VERSION 5.8 ;
BUSBITCHARS "[]" ;
DIVIDERCHAR "/" ;
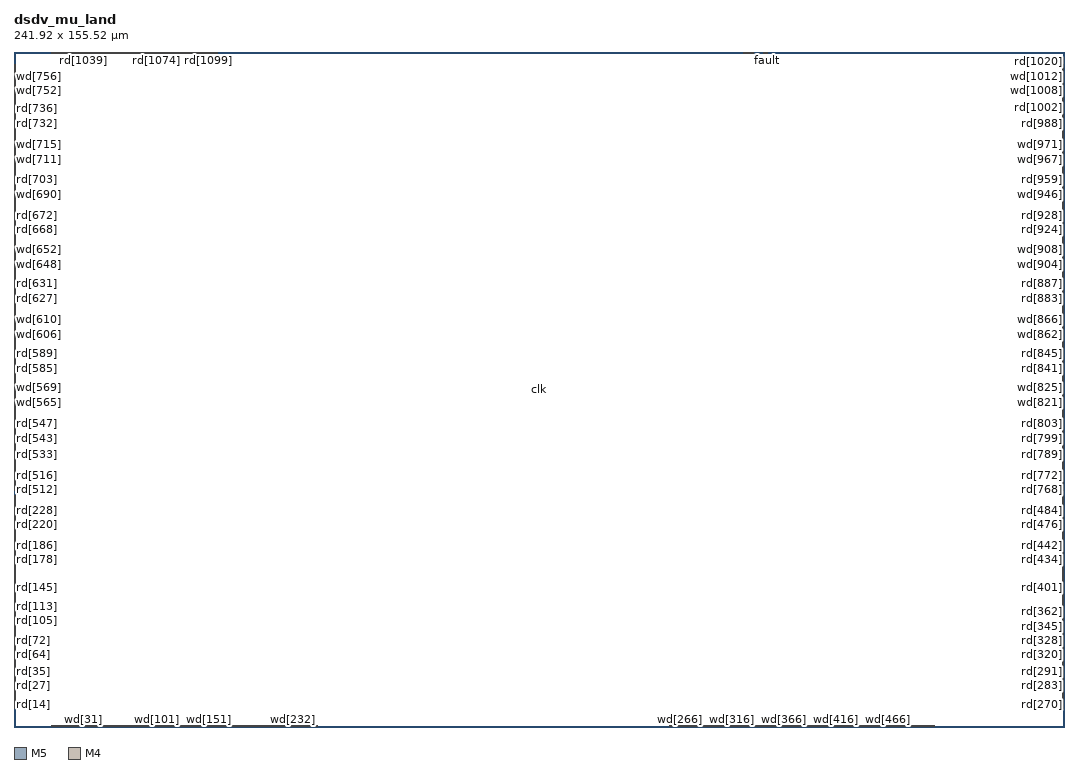
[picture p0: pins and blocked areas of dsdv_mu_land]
MACRO dsdv_mu_land
 CLASS BLOCK ;
 ORIGIN 0 0 ;
 SIZE 241.92 BY 155.52 ;
 SYMMETRY X Y ;
 PIN wd[0]
  DIRECTION INPUT ;
  USE SIGNAL ;
  PORT
   LAYER M5 ;
   RECT 8.6280 0.2160 8.6760 0.2640 ;
  END
 END wd[0]
 PIN rd[0]
  DIRECTION OUTPUT ;
  USE SIGNAL ;
  PORT
   LAYER M4 ;
   RECT 0.2160 4.3080 0.2640 4.3560 ;
  END
 END rd[0]
 PIN wd[1]
  DIRECTION INPUT ;
  USE SIGNAL ;
  PORT
   LAYER M5 ;
   RECT 8.8680 0.2160 8.9160 0.2640 ;
  END
 END wd[1]
 PIN rd[1]
  DIRECTION OUTPUT ;
  USE SIGNAL ;
  PORT
   LAYER M4 ;
   RECT 0.2160 4.5000 0.2640 4.5480 ;
  END
 END rd[1]
 PIN wd[2]
  DIRECTION INPUT ;
  USE SIGNAL ;
  PORT
   LAYER M5 ;
   RECT 9.1080 0.2160 9.1560 0.2640 ;
  END
 END wd[2]
 PIN rd[2]
  DIRECTION OUTPUT ;
  USE SIGNAL ;
  PORT
   LAYER M4 ;
   RECT 0.2160 4.6920 0.2640 4.7400 ;
  END
 END rd[2]
 PIN wd[3]
  DIRECTION INPUT ;
  USE SIGNAL ;
  PORT
   LAYER M5 ;
   RECT 9.3480 0.2160 9.3960 0.2640 ;
  END
 END wd[3]
 PIN rd[3]
  DIRECTION OUTPUT ;
  USE SIGNAL ;
  PORT
   LAYER M4 ;
   RECT 0.2160 4.8840 0.2640 4.9320 ;
  END
 END rd[3]
 PIN wd[4]
  DIRECTION INPUT ;
  USE SIGNAL ;
  PORT
   LAYER M5 ;
   RECT 9.5880 0.2160 9.6360 0.2640 ;
  END
 END wd[4]
 PIN rd[4]
  DIRECTION OUTPUT ;
  USE SIGNAL ;
  PORT
   LAYER M4 ;
   RECT 0.2160 5.0760 0.2640 5.1240 ;
  END
 END rd[4]
 PIN wd[5]
  DIRECTION INPUT ;
  USE SIGNAL ;
  PORT
   LAYER M5 ;
   RECT 9.8280 0.2160 9.8760 0.2640 ;
  END
 END wd[5]
 PIN rd[5]
  DIRECTION OUTPUT ;
  USE SIGNAL ;
  PORT
   LAYER M4 ;
   RECT 0.2160 5.2680 0.2640 5.3160 ;
  END
 END rd[5]
 PIN wd[6]
  DIRECTION INPUT ;
  USE SIGNAL ;
  PORT
   LAYER M5 ;
   RECT 10.0680 0.2160 10.1160 0.2640 ;
  END
 END wd[6]
 PIN rd[6]
  DIRECTION OUTPUT ;
  USE SIGNAL ;
  PORT
   LAYER M4 ;
   RECT 0.2160 5.4600 0.2640 5.5080 ;
  END
 END rd[6]
 PIN wd[7]
  DIRECTION INPUT ;
  USE SIGNAL ;
  PORT
   LAYER M5 ;
   RECT 10.3080 0.2160 10.3560 0.2640 ;
  END
 END wd[7]
 PIN rd[7]
  DIRECTION OUTPUT ;
  USE SIGNAL ;
  PORT
   LAYER M4 ;
   RECT 0.2160 5.6520 0.2640 5.7000 ;
  END
 END rd[7]
 PIN wd[8]
  DIRECTION INPUT ;
  USE SIGNAL ;
  PORT
   LAYER M5 ;
   RECT 10.5480 0.2160 10.5960 0.2640 ;
  END
 END wd[8]
 PIN rd[8]
  DIRECTION OUTPUT ;
  USE SIGNAL ;
  PORT
   LAYER M4 ;
   RECT 0.2160 5.8440 0.2640 5.8920 ;
  END
 END rd[8]
 PIN wd[9]
  DIRECTION INPUT ;
  USE SIGNAL ;
  PORT
   LAYER M5 ;
   RECT 10.7880 0.2160 10.8360 0.2640 ;
  END
 END wd[9]
 PIN rd[9]
  DIRECTION OUTPUT ;
  USE SIGNAL ;
  PORT
   LAYER M4 ;
   RECT 0.2160 6.0360 0.2640 6.0840 ;
  END
 END rd[9]
 PIN wd[10]
  DIRECTION INPUT ;
  USE SIGNAL ;
  PORT
   LAYER M5 ;
   RECT 11.0280 0.2160 11.0760 0.2640 ;
  END
 END wd[10]
 PIN rd[10]
  DIRECTION OUTPUT ;
  USE SIGNAL ;
  PORT
   LAYER M4 ;
   RECT 0.2160 6.2280 0.2640 6.2760 ;
  END
 END rd[10]
 PIN wd[11]
  DIRECTION INPUT ;
  USE SIGNAL ;
  PORT
   LAYER M5 ;
   RECT 11.2680 0.2160 11.3160 0.2640 ;
  END
 END wd[11]
 PIN rd[11]
  DIRECTION OUTPUT ;
  USE SIGNAL ;
  PORT
   LAYER M4 ;
   RECT 0.2160 6.4200 0.2640 6.4680 ;
  END
 END rd[11]
 PIN wd[12]
  DIRECTION INPUT ;
  USE SIGNAL ;
  PORT
   LAYER M5 ;
   RECT 11.5080 0.2160 11.5560 0.2640 ;
  END
 END wd[12]
 PIN rd[12]
  DIRECTION OUTPUT ;
  USE SIGNAL ;
  PORT
   LAYER M4 ;
   RECT 0.2160 6.6120 0.2640 6.6600 ;
  END
 END rd[12]
 PIN wd[13]
  DIRECTION INPUT ;
  USE SIGNAL ;
  PORT
   LAYER M5 ;
   RECT 11.7480 0.2160 11.7960 0.2640 ;
  END
 END wd[13]
 PIN rd[13]
  DIRECTION OUTPUT ;
  USE SIGNAL ;
  PORT
   LAYER M4 ;
   RECT 0.2160 6.8040 0.2640 6.8520 ;
  END
 END rd[13]
 PIN wd[14]
  DIRECTION INPUT ;
  USE SIGNAL ;
  PORT
   LAYER M5 ;
   RECT 11.9880 0.2160 12.0360 0.2640 ;
  END
 END wd[14]
 PIN rd[14]
  DIRECTION OUTPUT ;
  USE SIGNAL ;
  PORT
   LAYER M4 ;
   RECT 0.2160 6.9960 0.2640 7.0440 ;
  END
 END rd[14]
 PIN wd[15]
  DIRECTION INPUT ;
  USE SIGNAL ;
  PORT
   LAYER M5 ;
   RECT 12.2280 0.2160 12.2760 0.2640 ;
  END
 END wd[15]
 PIN rd[15]
  DIRECTION OUTPUT ;
  USE SIGNAL ;
  PORT
   LAYER M4 ;
   RECT 0.2160 7.1880 0.2640 7.2360 ;
  END
 END rd[15]
 PIN wd[16]
  DIRECTION INPUT ;
  USE SIGNAL ;
  PORT
   LAYER M5 ;
   RECT 12.4680 0.2160 12.5160 0.2640 ;
  END
 END wd[16]
 PIN rd[16]
  DIRECTION OUTPUT ;
  USE SIGNAL ;
  PORT
   LAYER M4 ;
   RECT 0.2160 7.3800 0.2640 7.4280 ;
  END
 END rd[16]
 PIN wd[17]
  DIRECTION INPUT ;
  USE SIGNAL ;
  PORT
   LAYER M5 ;
   RECT 12.7080 0.2160 12.7560 0.2640 ;
  END
 END wd[17]
 PIN rd[17]
  DIRECTION OUTPUT ;
  USE SIGNAL ;
  PORT
   LAYER M4 ;
   RECT 0.2160 7.5720 0.2640 7.6200 ;
  END
 END rd[17]
 PIN wd[18]
  DIRECTION INPUT ;
  USE SIGNAL ;
  PORT
   LAYER M5 ;
   RECT 12.9480 0.2160 12.9960 0.2640 ;
  END
 END wd[18]
 PIN rd[18]
  DIRECTION OUTPUT ;
  USE SIGNAL ;
  PORT
   LAYER M4 ;
   RECT 0.2160 7.7640 0.2640 7.8120 ;
  END
 END rd[18]
 PIN wd[19]
  DIRECTION INPUT ;
  USE SIGNAL ;
  PORT
   LAYER M5 ;
   RECT 13.1880 0.2160 13.2360 0.2640 ;
  END
 END wd[19]
 PIN rd[19]
  DIRECTION OUTPUT ;
  USE SIGNAL ;
  PORT
   LAYER M4 ;
   RECT 0.2160 7.9560 0.2640 8.0040 ;
  END
 END rd[19]
 PIN wd[20]
  DIRECTION INPUT ;
  USE SIGNAL ;
  PORT
   LAYER M5 ;
   RECT 13.4280 0.2160 13.4760 0.2640 ;
  END
 END wd[20]
 PIN rd[20]
  DIRECTION OUTPUT ;
  USE SIGNAL ;
  PORT
   LAYER M4 ;
   RECT 0.2160 8.1480 0.2640 8.1960 ;
  END
 END rd[20]
 PIN wd[21]
  DIRECTION INPUT ;
  USE SIGNAL ;
  PORT
   LAYER M5 ;
   RECT 13.6680 0.2160 13.7160 0.2640 ;
  END
 END wd[21]
 PIN rd[21]
  DIRECTION OUTPUT ;
  USE SIGNAL ;
  PORT
   LAYER M4 ;
   RECT 0.2160 8.3400 0.2640 8.3880 ;
  END
 END rd[21]
 PIN wd[22]
  DIRECTION INPUT ;
  USE SIGNAL ;
  PORT
   LAYER M5 ;
   RECT 13.9080 0.2160 13.9560 0.2640 ;
  END
 END wd[22]
 PIN rd[22]
  DIRECTION OUTPUT ;
  USE SIGNAL ;
  PORT
   LAYER M4 ;
   RECT 0.2160 8.5320 0.2640 8.5800 ;
  END
 END rd[22]
 PIN wd[23]
  DIRECTION INPUT ;
  USE SIGNAL ;
  PORT
   LAYER M5 ;
   RECT 14.1480 0.2160 14.1960 0.2640 ;
  END
 END wd[23]
 PIN rd[23]
  DIRECTION OUTPUT ;
  USE SIGNAL ;
  PORT
   LAYER M4 ;
   RECT 0.2160 8.7240 0.2640 8.7720 ;
  END
 END rd[23]
 PIN wd[24]
  DIRECTION INPUT ;
  USE SIGNAL ;
  PORT
   LAYER M5 ;
   RECT 14.3880 0.2160 14.4360 0.2640 ;
  END
 END wd[24]
 PIN rd[24]
  DIRECTION OUTPUT ;
  USE SIGNAL ;
  PORT
   LAYER M4 ;
   RECT 0.2160 8.9160 0.2640 8.9640 ;
  END
 END rd[24]
 PIN wd[25]
  DIRECTION INPUT ;
  USE SIGNAL ;
  PORT
   LAYER M5 ;
   RECT 14.6280 0.2160 14.6760 0.2640 ;
  END
 END wd[25]
 PIN rd[25]
  DIRECTION OUTPUT ;
  USE SIGNAL ;
  PORT
   LAYER M4 ;
   RECT 0.2160 9.1080 0.2640 9.1560 ;
  END
 END rd[25]
 PIN wd[26]
  DIRECTION INPUT ;
  USE SIGNAL ;
  PORT
   LAYER M5 ;
   RECT 14.8680 0.2160 14.9160 0.2640 ;
  END
 END wd[26]
 PIN rd[26]
  DIRECTION OUTPUT ;
  USE SIGNAL ;
  PORT
   LAYER M4 ;
   RECT 0.2160 9.3000 0.2640 9.3480 ;
  END
 END rd[26]
 PIN wd[27]
  DIRECTION INPUT ;
  USE SIGNAL ;
  PORT
   LAYER M5 ;
   RECT 15.1080 0.2160 15.1560 0.2640 ;
  END
 END wd[27]
 PIN rd[27]
  DIRECTION OUTPUT ;
  USE SIGNAL ;
  PORT
   LAYER M4 ;
   RECT 0.2160 9.4920 0.2640 9.5400 ;
  END
 END rd[27]
 PIN wd[28]
  DIRECTION INPUT ;
  USE SIGNAL ;
  PORT
   LAYER M5 ;
   RECT 15.3480 0.2160 15.3960 0.2640 ;
  END
 END wd[28]
 PIN rd[28]
  DIRECTION OUTPUT ;
  USE SIGNAL ;
  PORT
   LAYER M4 ;
   RECT 0.2160 9.6840 0.2640 9.7320 ;
  END
 END rd[28]
 PIN wd[29]
  DIRECTION INPUT ;
  USE SIGNAL ;
  PORT
   LAYER M5 ;
   RECT 15.5880 0.2160 15.6360 0.2640 ;
  END
 END wd[29]
 PIN rd[29]
  DIRECTION OUTPUT ;
  USE SIGNAL ;
  PORT
   LAYER M4 ;
   RECT 0.2160 9.8760 0.2640 9.9240 ;
  END
 END rd[29]
 PIN wd[30]
  DIRECTION INPUT ;
  USE SIGNAL ;
  PORT
   LAYER M5 ;
   RECT 15.8280 0.2160 15.8760 0.2640 ;
  END
 END wd[30]
 PIN rd[30]
  DIRECTION OUTPUT ;
  USE SIGNAL ;
  PORT
   LAYER M4 ;
   RECT 0.2160 10.0680 0.2640 10.1160 ;
  END
 END rd[30]
 PIN wd[31]
  DIRECTION INPUT ;
  USE SIGNAL ;
  PORT
   LAYER M5 ;
   RECT 16.0680 0.2160 16.1160 0.2640 ;
  END
 END wd[31]
 PIN rd[31]
  DIRECTION OUTPUT ;
  USE SIGNAL ;
  PORT
   LAYER M4 ;
   RECT 0.2160 10.2600 0.2640 10.3080 ;
  END
 END rd[31]
 PIN wd[32]
  DIRECTION INPUT ;
  USE SIGNAL ;
  PORT
   LAYER M5 ;
   RECT 16.3080 0.2160 16.3560 0.2640 ;
  END
 END wd[32]
 PIN rd[32]
  DIRECTION OUTPUT ;
  USE SIGNAL ;
  PORT
   LAYER M4 ;
   RECT 0.2160 10.4520 0.2640 10.5000 ;
  END
 END rd[32]
 PIN wd[33]
  DIRECTION INPUT ;
  USE SIGNAL ;
  PORT
   LAYER M5 ;
   RECT 16.5480 0.2160 16.5960 0.2640 ;
  END
 END wd[33]
 PIN rd[33]
  DIRECTION OUTPUT ;
  USE SIGNAL ;
  PORT
   LAYER M4 ;
   RECT 0.2160 10.6440 0.2640 10.6920 ;
  END
 END rd[33]
 PIN wd[34]
  DIRECTION INPUT ;
  USE SIGNAL ;
  PORT
   LAYER M5 ;
   RECT 16.7880 0.2160 16.8360 0.2640 ;
  END
 END wd[34]
 PIN rd[34]
  DIRECTION OUTPUT ;
  USE SIGNAL ;
  PORT
   LAYER M4 ;
   RECT 0.2160 10.8360 0.2640 10.8840 ;
  END
 END rd[34]
 PIN wd[35]
  DIRECTION INPUT ;
  USE SIGNAL ;
  PORT
   LAYER M5 ;
   RECT 17.0280 0.2160 17.0760 0.2640 ;
  END
 END wd[35]
 PIN rd[35]
  DIRECTION OUTPUT ;
  USE SIGNAL ;
  PORT
   LAYER M4 ;
   RECT 0.2160 11.0280 0.2640 11.0760 ;
  END
 END rd[35]
 PIN wd[36]
  DIRECTION INPUT ;
  USE SIGNAL ;
  PORT
   LAYER M5 ;
   RECT 17.2680 0.2160 17.3160 0.2640 ;
  END
 END wd[36]
 PIN rd[36]
  DIRECTION OUTPUT ;
  USE SIGNAL ;
  PORT
   LAYER M4 ;
   RECT 0.2160 11.2200 0.2640 11.2680 ;
  END
 END rd[36]
 PIN wd[37]
  DIRECTION INPUT ;
  USE SIGNAL ;
  PORT
   LAYER M5 ;
   RECT 17.5080 0.2160 17.5560 0.2640 ;
  END
 END wd[37]
 PIN rd[37]
  DIRECTION OUTPUT ;
  USE SIGNAL ;
  PORT
   LAYER M4 ;
   RECT 0.2160 11.4120 0.2640 11.4600 ;
  END
 END rd[37]
 PIN wd[38]
  DIRECTION INPUT ;
  USE SIGNAL ;
  PORT
   LAYER M5 ;
   RECT 17.7480 0.2160 17.7960 0.2640 ;
  END
 END wd[38]
 PIN rd[38]
  DIRECTION OUTPUT ;
  USE SIGNAL ;
  PORT
   LAYER M4 ;
   RECT 0.2160 11.6040 0.2640 11.6520 ;
  END
 END rd[38]
 PIN wd[39]
  DIRECTION INPUT ;
  USE SIGNAL ;
  PORT
   LAYER M5 ;
   RECT 17.9880 0.2160 18.0360 0.2640 ;
  END
 END wd[39]
 PIN rd[39]
  DIRECTION OUTPUT ;
  USE SIGNAL ;
  PORT
   LAYER M4 ;
   RECT 0.2160 11.7960 0.2640 11.8440 ;
  END
 END rd[39]
 PIN wd[40]
  DIRECTION INPUT ;
  USE SIGNAL ;
  PORT
   LAYER M5 ;
   RECT 18.2280 0.2160 18.2760 0.2640 ;
  END
 END wd[40]
 PIN rd[40]
  DIRECTION OUTPUT ;
  USE SIGNAL ;
  PORT
   LAYER M4 ;
   RECT 0.2160 11.9880 0.2640 12.0360 ;
  END
 END rd[40]
 PIN wd[41]
  DIRECTION INPUT ;
  USE SIGNAL ;
  PORT
   LAYER M5 ;
   RECT 18.4680 0.2160 18.5160 0.2640 ;
  END
 END wd[41]
 PIN rd[41]
  DIRECTION OUTPUT ;
  USE SIGNAL ;
  PORT
   LAYER M4 ;
   RECT 0.2160 12.1800 0.2640 12.2280 ;
  END
 END rd[41]
 PIN wd[42]
  DIRECTION INPUT ;
  USE SIGNAL ;
  PORT
   LAYER M5 ;
   RECT 18.7080 0.2160 18.7560 0.2640 ;
  END
 END wd[42]
 PIN rd[42]
  DIRECTION OUTPUT ;
  USE SIGNAL ;
  PORT
   LAYER M4 ;
   RECT 0.2160 12.3720 0.2640 12.4200 ;
  END
 END rd[42]
 PIN wd[43]
  DIRECTION INPUT ;
  USE SIGNAL ;
  PORT
   LAYER M5 ;
   RECT 18.9480 0.2160 18.9960 0.2640 ;
  END
 END wd[43]
 PIN rd[43]
  DIRECTION OUTPUT ;
  USE SIGNAL ;
  PORT
   LAYER M4 ;
   RECT 0.2160 12.5640 0.2640 12.6120 ;
  END
 END rd[43]
 PIN wd[44]
  DIRECTION INPUT ;
  USE SIGNAL ;
  PORT
   LAYER M5 ;
   RECT 19.1880 0.2160 19.2360 0.2640 ;
  END
 END wd[44]
 PIN rd[44]
  DIRECTION OUTPUT ;
  USE SIGNAL ;
  PORT
   LAYER M4 ;
   RECT 0.2160 12.7560 0.2640 12.8040 ;
  END
 END rd[44]
 PIN wd[45]
  DIRECTION INPUT ;
  USE SIGNAL ;
  PORT
   LAYER M5 ;
   RECT 19.4280 0.2160 19.4760 0.2640 ;
  END
 END wd[45]
 PIN rd[45]
  DIRECTION OUTPUT ;
  USE SIGNAL ;
  PORT
   LAYER M4 ;
   RECT 0.2160 12.9480 0.2640 12.9960 ;
  END
 END rd[45]
 PIN wd[46]
  DIRECTION INPUT ;
  USE SIGNAL ;
  PORT
   LAYER M5 ;
   RECT 19.6680 0.2160 19.7160 0.2640 ;
  END
 END wd[46]
 PIN rd[46]
  DIRECTION OUTPUT ;
  USE SIGNAL ;
  PORT
   LAYER M4 ;
   RECT 0.2160 13.1400 0.2640 13.1880 ;
  END
 END rd[46]
 PIN wd[47]
  DIRECTION INPUT ;
  USE SIGNAL ;
  PORT
   LAYER M5 ;
   RECT 19.9080 0.2160 19.9560 0.2640 ;
  END
 END wd[47]
 PIN rd[47]
  DIRECTION OUTPUT ;
  USE SIGNAL ;
  PORT
   LAYER M4 ;
   RECT 0.2160 13.3320 0.2640 13.3800 ;
  END
 END rd[47]
 PIN wd[48]
  DIRECTION INPUT ;
  USE SIGNAL ;
  PORT
   LAYER M5 ;
   RECT 20.1480 0.2160 20.1960 0.2640 ;
  END
 END wd[48]
 PIN rd[48]
  DIRECTION OUTPUT ;
  USE SIGNAL ;
  PORT
   LAYER M4 ;
   RECT 0.2160 13.5240 0.2640 13.5720 ;
  END
 END rd[48]
 PIN wd[49]
  DIRECTION INPUT ;
  USE SIGNAL ;
  PORT
   LAYER M5 ;
   RECT 20.3880 0.2160 20.4360 0.2640 ;
  END
 END wd[49]
 PIN rd[49]
  DIRECTION OUTPUT ;
  USE SIGNAL ;
  PORT
   LAYER M4 ;
   RECT 0.2160 13.7160 0.2640 13.7640 ;
  END
 END rd[49]
 PIN wd[50]
  DIRECTION INPUT ;
  USE SIGNAL ;
  PORT
   LAYER M5 ;
   RECT 20.6280 0.2160 20.6760 0.2640 ;
  END
 END wd[50]
 PIN rd[50]
  DIRECTION OUTPUT ;
  USE SIGNAL ;
  PORT
   LAYER M4 ;
   RECT 0.2160 13.9080 0.2640 13.9560 ;
  END
 END rd[50]
 PIN wd[51]
  DIRECTION INPUT ;
  USE SIGNAL ;
  PORT
   LAYER M5 ;
   RECT 20.8680 0.2160 20.9160 0.2640 ;
  END
 END wd[51]
 PIN rd[51]
  DIRECTION OUTPUT ;
  USE SIGNAL ;
  PORT
   LAYER M4 ;
   RECT 0.2160 14.1000 0.2640 14.1480 ;
  END
 END rd[51]
 PIN wd[52]
  DIRECTION INPUT ;
  USE SIGNAL ;
  PORT
   LAYER M5 ;
   RECT 21.1080 0.2160 21.1560 0.2640 ;
  END
 END wd[52]
 PIN rd[52]
  DIRECTION OUTPUT ;
  USE SIGNAL ;
  PORT
   LAYER M4 ;
   RECT 0.2160 14.2920 0.2640 14.3400 ;
  END
 END rd[52]
 PIN wd[53]
  DIRECTION INPUT ;
  USE SIGNAL ;
  PORT
   LAYER M5 ;
   RECT 21.3480 0.2160 21.3960 0.2640 ;
  END
 END wd[53]
 PIN rd[53]
  DIRECTION OUTPUT ;
  USE SIGNAL ;
  PORT
   LAYER M4 ;
   RECT 0.2160 14.4840 0.2640 14.5320 ;
  END
 END rd[53]
 PIN wd[54]
  DIRECTION INPUT ;
  USE SIGNAL ;
  PORT
   LAYER M5 ;
   RECT 21.5880 0.2160 21.6360 0.2640 ;
  END
 END wd[54]
 PIN rd[54]
  DIRECTION OUTPUT ;
  USE SIGNAL ;
  PORT
   LAYER M4 ;
   RECT 0.2160 14.6760 0.2640 14.7240 ;
  END
 END rd[54]
 PIN wd[55]
  DIRECTION INPUT ;
  USE SIGNAL ;
  PORT
   LAYER M5 ;
   RECT 21.8280 0.2160 21.8760 0.2640 ;
  END
 END wd[55]
 PIN rd[55]
  DIRECTION OUTPUT ;
  USE SIGNAL ;
  PORT
   LAYER M4 ;
   RECT 0.2160 14.8680 0.2640 14.9160 ;
  END
 END rd[55]
 PIN wd[56]
  DIRECTION INPUT ;
  USE SIGNAL ;
  PORT
   LAYER M5 ;
   RECT 22.0680 0.2160 22.1160 0.2640 ;
  END
 END wd[56]
 PIN rd[56]
  DIRECTION OUTPUT ;
  USE SIGNAL ;
  PORT
   LAYER M4 ;
   RECT 0.2160 15.0600 0.2640 15.1080 ;
  END
 END rd[56]
 PIN wd[57]
  DIRECTION INPUT ;
  USE SIGNAL ;
  PORT
   LAYER M5 ;
   RECT 22.3080 0.2160 22.3560 0.2640 ;
  END
 END wd[57]
 PIN rd[57]
  DIRECTION OUTPUT ;
  USE SIGNAL ;
  PORT
   LAYER M4 ;
   RECT 0.2160 15.2520 0.2640 15.3000 ;
  END
 END rd[57]
 PIN wd[58]
  DIRECTION INPUT ;
  USE SIGNAL ;
  PORT
   LAYER M5 ;
   RECT 22.5480 0.2160 22.5960 0.2640 ;
  END
 END wd[58]
 PIN rd[58]
  DIRECTION OUTPUT ;
  USE SIGNAL ;
  PORT
   LAYER M4 ;
   RECT 0.2160 15.4440 0.2640 15.4920 ;
  END
 END rd[58]
 PIN wd[59]
  DIRECTION INPUT ;
  USE SIGNAL ;
  PORT
   LAYER M5 ;
   RECT 22.7880 0.2160 22.8360 0.2640 ;
  END
 END wd[59]
 PIN rd[59]
  DIRECTION OUTPUT ;
  USE SIGNAL ;
  PORT
   LAYER M4 ;
   RECT 0.2160 15.6360 0.2640 15.6840 ;
  END
 END rd[59]
 PIN wd[60]
  DIRECTION INPUT ;
  USE SIGNAL ;
  PORT
   LAYER M5 ;
   RECT 23.0280 0.2160 23.0760 0.2640 ;
  END
 END wd[60]
 PIN rd[60]
  DIRECTION OUTPUT ;
  USE SIGNAL ;
  PORT
   LAYER M4 ;
   RECT 0.2160 15.8280 0.2640 15.8760 ;
  END
 END rd[60]
 PIN wd[61]
  DIRECTION INPUT ;
  USE SIGNAL ;
  PORT
   LAYER M5 ;
   RECT 23.2680 0.2160 23.3160 0.2640 ;
  END
 END wd[61]
 PIN rd[61]
  DIRECTION OUTPUT ;
  USE SIGNAL ;
  PORT
   LAYER M4 ;
   RECT 0.2160 16.0200 0.2640 16.0680 ;
  END
 END rd[61]
 PIN wd[62]
  DIRECTION INPUT ;
  USE SIGNAL ;
  PORT
   LAYER M5 ;
   RECT 23.5080 0.2160 23.5560 0.2640 ;
  END
 END wd[62]
 PIN rd[62]
  DIRECTION OUTPUT ;
  USE SIGNAL ;
  PORT
   LAYER M4 ;
   RECT 0.2160 16.2120 0.2640 16.2600 ;
  END
 END rd[62]
 PIN wd[63]
  DIRECTION INPUT ;
  USE SIGNAL ;
  PORT
   LAYER M5 ;
   RECT 23.7480 0.2160 23.7960 0.2640 ;
  END
 END wd[63]
 PIN rd[63]
  DIRECTION OUTPUT ;
  USE SIGNAL ;
  PORT
   LAYER M4 ;
   RECT 0.2160 16.4040 0.2640 16.4520 ;
  END
 END rd[63]
 PIN wd[64]
  DIRECTION INPUT ;
  USE SIGNAL ;
  PORT
   LAYER M5 ;
   RECT 23.9880 0.2160 24.0360 0.2640 ;
  END
 END wd[64]
 PIN rd[64]
  DIRECTION OUTPUT ;
  USE SIGNAL ;
  PORT
   LAYER M4 ;
   RECT 0.2160 16.5960 0.2640 16.6440 ;
  END
 END rd[64]
 PIN wd[65]
  DIRECTION INPUT ;
  USE SIGNAL ;
  PORT
   LAYER M5 ;
   RECT 24.2280 0.2160 24.2760 0.2640 ;
  END
 END wd[65]
 PIN rd[65]
  DIRECTION OUTPUT ;
  USE SIGNAL ;
  PORT
   LAYER M4 ;
   RECT 0.2160 16.7880 0.2640 16.8360 ;
  END
 END rd[65]
 PIN wd[66]
  DIRECTION INPUT ;
  USE SIGNAL ;
  PORT
   LAYER M5 ;
   RECT 24.4680 0.2160 24.5160 0.2640 ;
  END
 END wd[66]
 PIN rd[66]
  DIRECTION OUTPUT ;
  USE SIGNAL ;
  PORT
   LAYER M4 ;
   RECT 0.2160 16.9800 0.2640 17.0280 ;
  END
 END rd[66]
 PIN wd[67]
  DIRECTION INPUT ;
  USE SIGNAL ;
  PORT
   LAYER M5 ;
   RECT 24.7080 0.2160 24.7560 0.2640 ;
  END
 END wd[67]
 PIN rd[67]
  DIRECTION OUTPUT ;
  USE SIGNAL ;
  PORT
   LAYER M4 ;
   RECT 0.2160 17.1720 0.2640 17.2200 ;
  END
 END rd[67]
 PIN wd[68]
  DIRECTION INPUT ;
  USE SIGNAL ;
  PORT
   LAYER M5 ;
   RECT 24.9480 0.2160 24.9960 0.2640 ;
  END
 END wd[68]
 PIN rd[68]
  DIRECTION OUTPUT ;
  USE SIGNAL ;
  PORT
   LAYER M4 ;
   RECT 0.2160 17.3640 0.2640 17.4120 ;
  END
 END rd[68]
 PIN wd[69]
  DIRECTION INPUT ;
  USE SIGNAL ;
  PORT
   LAYER M5 ;
   RECT 25.1880 0.2160 25.2360 0.2640 ;
  END
 END wd[69]
 PIN rd[69]
  DIRECTION OUTPUT ;
  USE SIGNAL ;
  PORT
   LAYER M4 ;
   RECT 0.2160 17.5560 0.2640 17.6040 ;
  END
 END rd[69]
 PIN wd[70]
  DIRECTION INPUT ;
  USE SIGNAL ;
  PORT
   LAYER M5 ;
   RECT 25.4280 0.2160 25.4760 0.2640 ;
  END
 END wd[70]
 PIN rd[70]
  DIRECTION OUTPUT ;
  USE SIGNAL ;
  PORT
   LAYER M4 ;
   RECT 0.2160 17.7480 0.2640 17.7960 ;
  END
 END rd[70]
 PIN wd[71]
  DIRECTION INPUT ;
  USE SIGNAL ;
  PORT
   LAYER M5 ;
   RECT 25.6680 0.2160 25.7160 0.2640 ;
  END
 END wd[71]
 PIN rd[71]
  DIRECTION OUTPUT ;
  USE SIGNAL ;
  PORT
   LAYER M4 ;
   RECT 0.2160 17.9400 0.2640 17.9880 ;
  END
 END rd[71]
 PIN wd[72]
  DIRECTION INPUT ;
  USE SIGNAL ;
  PORT
   LAYER M5 ;
   RECT 25.9080 0.2160 25.9560 0.2640 ;
  END
 END wd[72]
 PIN rd[72]
  DIRECTION OUTPUT ;
  USE SIGNAL ;
  PORT
   LAYER M4 ;
   RECT 0.2160 18.1320 0.2640 18.1800 ;
  END
 END rd[72]
 PIN wd[73]
  DIRECTION INPUT ;
  USE SIGNAL ;
  PORT
   LAYER M5 ;
   RECT 26.1480 0.2160 26.1960 0.2640 ;
  END
 END wd[73]
 PIN rd[73]
  DIRECTION OUTPUT ;
  USE SIGNAL ;
  PORT
   LAYER M4 ;
   RECT 0.2160 18.3240 0.2640 18.3720 ;
  END
 END rd[73]
 PIN wd[74]
  DIRECTION INPUT ;
  USE SIGNAL ;
  PORT
   LAYER M5 ;
   RECT 26.3880 0.2160 26.4360 0.2640 ;
  END
 END wd[74]
 PIN rd[74]
  DIRECTION OUTPUT ;
  USE SIGNAL ;
  PORT
   LAYER M4 ;
   RECT 0.2160 18.5160 0.2640 18.5640 ;
  END
 END rd[74]
 PIN wd[75]
  DIRECTION INPUT ;
  USE SIGNAL ;
  PORT
   LAYER M5 ;
   RECT 26.6280 0.2160 26.6760 0.2640 ;
  END
 END wd[75]
 PIN rd[75]
  DIRECTION OUTPUT ;
  USE SIGNAL ;
  PORT
   LAYER M4 ;
   RECT 0.2160 18.7080 0.2640 18.7560 ;
  END
 END rd[75]
 PIN wd[76]
  DIRECTION INPUT ;
  USE SIGNAL ;
  PORT
   LAYER M5 ;
   RECT 26.8680 0.2160 26.9160 0.2640 ;
  END
 END wd[76]
 PIN rd[76]
  DIRECTION OUTPUT ;
  USE SIGNAL ;
  PORT
   LAYER M4 ;
   RECT 0.2160 18.9000 0.2640 18.9480 ;
  END
 END rd[76]
 PIN wd[77]
  DIRECTION INPUT ;
  USE SIGNAL ;
  PORT
   LAYER M5 ;
   RECT 27.1080 0.2160 27.1560 0.2640 ;
  END
 END wd[77]
 PIN rd[77]
  DIRECTION OUTPUT ;
  USE SIGNAL ;
  PORT
   LAYER M4 ;
   RECT 0.2160 19.0920 0.2640 19.1400 ;
  END
 END rd[77]
 PIN wd[78]
  DIRECTION INPUT ;
  USE SIGNAL ;
  PORT
   LAYER M5 ;
   RECT 27.3480 0.2160 27.3960 0.2640 ;
  END
 END wd[78]
 PIN rd[78]
  DIRECTION OUTPUT ;
  USE SIGNAL ;
  PORT
   LAYER M4 ;
   RECT 0.2160 19.2840 0.2640 19.3320 ;
  END
 END rd[78]
 PIN wd[79]
  DIRECTION INPUT ;
  USE SIGNAL ;
  PORT
   LAYER M5 ;
   RECT 27.5880 0.2160 27.6360 0.2640 ;
  END
 END wd[79]
 PIN rd[79]
  DIRECTION OUTPUT ;
  USE SIGNAL ;
  PORT
   LAYER M4 ;
   RECT 0.2160 19.4760 0.2640 19.5240 ;
  END
 END rd[79]
 PIN wd[80]
  DIRECTION INPUT ;
  USE SIGNAL ;
  PORT
   LAYER M5 ;
   RECT 27.8280 0.2160 27.8760 0.2640 ;
  END
 END wd[80]
 PIN rd[80]
  DIRECTION OUTPUT ;
  USE SIGNAL ;
  PORT
   LAYER M4 ;
   RECT 0.2160 19.6680 0.2640 19.7160 ;
  END
 END rd[80]
 PIN wd[81]
  DIRECTION INPUT ;
  USE SIGNAL ;
  PORT
   LAYER M5 ;
   RECT 28.0680 0.2160 28.1160 0.2640 ;
  END
 END wd[81]
 PIN rd[81]
  DIRECTION OUTPUT ;
  USE SIGNAL ;
  PORT
   LAYER M4 ;
   RECT 0.2160 19.8600 0.2640 19.9080 ;
  END
 END rd[81]
 PIN wd[82]
  DIRECTION INPUT ;
  USE SIGNAL ;
  PORT
   LAYER M5 ;
   RECT 28.3080 0.2160 28.3560 0.2640 ;
  END
 END wd[82]
 PIN rd[82]
  DIRECTION OUTPUT ;
  USE SIGNAL ;
  PORT
   LAYER M4 ;
   RECT 0.2160 20.0520 0.2640 20.1000 ;
  END
 END rd[82]
 PIN wd[83]
  DIRECTION INPUT ;
  USE SIGNAL ;
  PORT
   LAYER M5 ;
   RECT 28.5480 0.2160 28.5960 0.2640 ;
  END
 END wd[83]
 PIN rd[83]
  DIRECTION OUTPUT ;
  USE SIGNAL ;
  PORT
   LAYER M4 ;
   RECT 0.2160 20.2440 0.2640 20.2920 ;
  END
 END rd[83]
 PIN wd[84]
  DIRECTION INPUT ;
  USE SIGNAL ;
  PORT
   LAYER M5 ;
   RECT 28.7880 0.2160 28.8360 0.2640 ;
  END
 END wd[84]
 PIN rd[84]
  DIRECTION OUTPUT ;
  USE SIGNAL ;
  PORT
   LAYER M4 ;
   RECT 0.2160 20.4360 0.2640 20.4840 ;
  END
 END rd[84]
 PIN wd[85]
  DIRECTION INPUT ;
  USE SIGNAL ;
  PORT
   LAYER M5 ;
   RECT 29.0280 0.2160 29.0760 0.2640 ;
  END
 END wd[85]
 PIN rd[85]
  DIRECTION OUTPUT ;
  USE SIGNAL ;
  PORT
   LAYER M4 ;
   RECT 0.2160 20.6280 0.2640 20.6760 ;
  END
 END rd[85]
 PIN wd[86]
  DIRECTION INPUT ;
  USE SIGNAL ;
  PORT
   LAYER M5 ;
   RECT 29.2680 0.2160 29.3160 0.2640 ;
  END
 END wd[86]
 PIN rd[86]
  DIRECTION OUTPUT ;
  USE SIGNAL ;
  PORT
   LAYER M4 ;
   RECT 0.2160 20.8200 0.2640 20.8680 ;
  END
 END rd[86]
 PIN wd[87]
  DIRECTION INPUT ;
  USE SIGNAL ;
  PORT
   LAYER M5 ;
   RECT 29.5080 0.2160 29.5560 0.2640 ;
  END
 END wd[87]
 PIN rd[87]
  DIRECTION OUTPUT ;
  USE SIGNAL ;
  PORT
   LAYER M4 ;
   RECT 0.2160 21.0120 0.2640 21.0600 ;
  END
 END rd[87]
 PIN wd[88]
  DIRECTION INPUT ;
  USE SIGNAL ;
  PORT
   LAYER M5 ;
   RECT 29.7480 0.2160 29.7960 0.2640 ;
  END
 END wd[88]
 PIN rd[88]
  DIRECTION OUTPUT ;
  USE SIGNAL ;
  PORT
   LAYER M4 ;
   RECT 0.2160 21.2040 0.2640 21.2520 ;
  END
 END rd[88]
 PIN wd[89]
  DIRECTION INPUT ;
  USE SIGNAL ;
  PORT
   LAYER M5 ;
   RECT 29.9880 0.2160 30.0360 0.2640 ;
  END
 END wd[89]
 PIN rd[89]
  DIRECTION OUTPUT ;
  USE SIGNAL ;
  PORT
   LAYER M4 ;
   RECT 0.2160 21.3960 0.2640 21.4440 ;
  END
 END rd[89]
 PIN wd[90]
  DIRECTION INPUT ;
  USE SIGNAL ;
  PORT
   LAYER M5 ;
   RECT 30.2280 0.2160 30.2760 0.2640 ;
  END
 END wd[90]
 PIN rd[90]
  DIRECTION OUTPUT ;
  USE SIGNAL ;
  PORT
   LAYER M4 ;
   RECT 0.2160 21.5880 0.2640 21.6360 ;
  END
 END rd[90]
 PIN wd[91]
  DIRECTION INPUT ;
  USE SIGNAL ;
  PORT
   LAYER M5 ;
   RECT 30.4680 0.2160 30.5160 0.2640 ;
  END
 END wd[91]
 PIN rd[91]
  DIRECTION OUTPUT ;
  USE SIGNAL ;
  PORT
   LAYER M4 ;
   RECT 0.2160 21.7800 0.2640 21.8280 ;
  END
 END rd[91]
 PIN wd[92]
  DIRECTION INPUT ;
  USE SIGNAL ;
  PORT
   LAYER M5 ;
   RECT 30.7080 0.2160 30.7560 0.2640 ;
  END
 END wd[92]
 PIN rd[92]
  DIRECTION OUTPUT ;
  USE SIGNAL ;
  PORT
   LAYER M4 ;
   RECT 0.2160 21.9720 0.2640 22.0200 ;
  END
 END rd[92]
 PIN wd[93]
  DIRECTION INPUT ;
  USE SIGNAL ;
  PORT
   LAYER M5 ;
   RECT 30.9480 0.2160 30.9960 0.2640 ;
  END
 END wd[93]
 PIN rd[93]
  DIRECTION OUTPUT ;
  USE SIGNAL ;
  PORT
   LAYER M4 ;
   RECT 0.2160 22.1640 0.2640 22.2120 ;
  END
 END rd[93]
 PIN wd[94]
  DIRECTION INPUT ;
  USE SIGNAL ;
  PORT
   LAYER M5 ;
   RECT 31.1880 0.2160 31.2360 0.2640 ;
  END
 END wd[94]
 PIN rd[94]
  DIRECTION OUTPUT ;
  USE SIGNAL ;
  PORT
   LAYER M4 ;
   RECT 0.2160 22.3560 0.2640 22.4040 ;
  END
 END rd[94]
 PIN wd[95]
  DIRECTION INPUT ;
  USE SIGNAL ;
  PORT
   LAYER M5 ;
   RECT 31.4280 0.2160 31.4760 0.2640 ;
  END
 END wd[95]
 PIN rd[95]
  DIRECTION OUTPUT ;
  USE SIGNAL ;
  PORT
   LAYER M4 ;
   RECT 0.2160 22.5480 0.2640 22.5960 ;
  END
 END rd[95]
 PIN wd[96]
  DIRECTION INPUT ;
  USE SIGNAL ;
  PORT
   LAYER M5 ;
   RECT 31.6680 0.2160 31.7160 0.2640 ;
  END
 END wd[96]
 PIN rd[96]
  DIRECTION OUTPUT ;
  USE SIGNAL ;
  PORT
   LAYER M4 ;
   RECT 0.2160 22.7400 0.2640 22.7880 ;
  END
 END rd[96]
 PIN wd[97]
  DIRECTION INPUT ;
  USE SIGNAL ;
  PORT
   LAYER M5 ;
   RECT 31.9080 0.2160 31.9560 0.2640 ;
  END
 END wd[97]
 PIN rd[97]
  DIRECTION OUTPUT ;
  USE SIGNAL ;
  PORT
   LAYER M4 ;
   RECT 0.2160 22.9320 0.2640 22.9800 ;
  END
 END rd[97]
 PIN wd[98]
  DIRECTION INPUT ;
  USE SIGNAL ;
  PORT
   LAYER M5 ;
   RECT 32.1480 0.2160 32.1960 0.2640 ;
  END
 END wd[98]
 PIN rd[98]
  DIRECTION OUTPUT ;
  USE SIGNAL ;
  PORT
   LAYER M4 ;
   RECT 0.2160 23.1240 0.2640 23.1720 ;
  END
 END rd[98]
 PIN wd[99]
  DIRECTION INPUT ;
  USE SIGNAL ;
  PORT
   LAYER M5 ;
   RECT 32.3880 0.2160 32.4360 0.2640 ;
  END
 END wd[99]
 PIN rd[99]
  DIRECTION OUTPUT ;
  USE SIGNAL ;
  PORT
   LAYER M4 ;
   RECT 0.2160 23.3160 0.2640 23.3640 ;
  END
 END rd[99]
 PIN wd[100]
  DIRECTION INPUT ;
  USE SIGNAL ;
  PORT
   LAYER M5 ;
   RECT 32.6280 0.2160 32.6760 0.2640 ;
  END
 END wd[100]
 PIN rd[100]
  DIRECTION OUTPUT ;
  USE SIGNAL ;
  PORT
   LAYER M4 ;
   RECT 0.2160 23.5080 0.2640 23.5560 ;
  END
 END rd[100]
 PIN wd[101]
  DIRECTION INPUT ;
  USE SIGNAL ;
  PORT
   LAYER M5 ;
   RECT 32.8680 0.2160 32.9160 0.2640 ;
  END
 END wd[101]
 PIN rd[101]
  DIRECTION OUTPUT ;
  USE SIGNAL ;
  PORT
   LAYER M4 ;
   RECT 0.2160 23.7000 0.2640 23.7480 ;
  END
 END rd[101]
 PIN wd[102]
  DIRECTION INPUT ;
  USE SIGNAL ;
  PORT
   LAYER M5 ;
   RECT 33.1080 0.2160 33.1560 0.2640 ;
  END
 END wd[102]
 PIN rd[102]
  DIRECTION OUTPUT ;
  USE SIGNAL ;
  PORT
   LAYER M4 ;
   RECT 0.2160 23.8920 0.2640 23.9400 ;
  END
 END rd[102]
 PIN wd[103]
  DIRECTION INPUT ;
  USE SIGNAL ;
  PORT
   LAYER M5 ;
   RECT 33.3480 0.2160 33.3960 0.2640 ;
  END
 END wd[103]
 PIN rd[103]
  DIRECTION OUTPUT ;
  USE SIGNAL ;
  PORT
   LAYER M4 ;
   RECT 0.2160 24.0840 0.2640 24.1320 ;
  END
 END rd[103]
 PIN wd[104]
  DIRECTION INPUT ;
  USE SIGNAL ;
  PORT
   LAYER M5 ;
   RECT 33.5880 0.2160 33.6360 0.2640 ;
  END
 END wd[104]
 PIN rd[104]
  DIRECTION OUTPUT ;
  USE SIGNAL ;
  PORT
   LAYER M4 ;
   RECT 0.2160 24.2760 0.2640 24.3240 ;
  END
 END rd[104]
 PIN wd[105]
  DIRECTION INPUT ;
  USE SIGNAL ;
  PORT
   LAYER M5 ;
   RECT 33.8280 0.2160 33.8760 0.2640 ;
  END
 END wd[105]
 PIN rd[105]
  DIRECTION OUTPUT ;
  USE SIGNAL ;
  PORT
   LAYER M4 ;
   RECT 0.2160 24.4680 0.2640 24.5160 ;
  END
 END rd[105]
 PIN wd[106]
  DIRECTION INPUT ;
  USE SIGNAL ;
  PORT
   LAYER M5 ;
   RECT 34.0680 0.2160 34.1160 0.2640 ;
  END
 END wd[106]
 PIN rd[106]
  DIRECTION OUTPUT ;
  USE SIGNAL ;
  PORT
   LAYER M4 ;
   RECT 0.2160 24.6600 0.2640 24.7080 ;
  END
 END rd[106]
 PIN wd[107]
  DIRECTION INPUT ;
  USE SIGNAL ;
  PORT
   LAYER M5 ;
   RECT 34.3080 0.2160 34.3560 0.2640 ;
  END
 END wd[107]
 PIN rd[107]
  DIRECTION OUTPUT ;
  USE SIGNAL ;
  PORT
   LAYER M4 ;
   RECT 0.2160 24.8520 0.2640 24.9000 ;
  END
 END rd[107]
 PIN wd[108]
  DIRECTION INPUT ;
  USE SIGNAL ;
  PORT
   LAYER M5 ;
   RECT 34.5480 0.2160 34.5960 0.2640 ;
  END
 END wd[108]
 PIN rd[108]
  DIRECTION OUTPUT ;
  USE SIGNAL ;
  PORT
   LAYER M4 ;
   RECT 0.2160 25.0440 0.2640 25.0920 ;
  END
 END rd[108]
 PIN wd[109]
  DIRECTION INPUT ;
  USE SIGNAL ;
  PORT
   LAYER M5 ;
   RECT 34.7880 0.2160 34.8360 0.2640 ;
  END
 END wd[109]
 PIN rd[109]
  DIRECTION OUTPUT ;
  USE SIGNAL ;
  PORT
   LAYER M4 ;
   RECT 0.2160 25.2360 0.2640 25.2840 ;
  END
 END rd[109]
 PIN wd[110]
  DIRECTION INPUT ;
  USE SIGNAL ;
  PORT
   LAYER M5 ;
   RECT 35.0280 0.2160 35.0760 0.2640 ;
  END
 END wd[110]
 PIN rd[110]
  DIRECTION OUTPUT ;
  USE SIGNAL ;
  PORT
   LAYER M4 ;
   RECT 0.2160 25.4280 0.2640 25.4760 ;
  END
 END rd[110]
 PIN wd[111]
  DIRECTION INPUT ;
  USE SIGNAL ;
  PORT
   LAYER M5 ;
   RECT 35.2680 0.2160 35.3160 0.2640 ;
  END
 END wd[111]
 PIN rd[111]
  DIRECTION OUTPUT ;
  USE SIGNAL ;
  PORT
   LAYER M4 ;
   RECT 0.2160 25.6200 0.2640 25.6680 ;
  END
 END rd[111]
 PIN wd[112]
  DIRECTION INPUT ;
  USE SIGNAL ;
  PORT
   LAYER M5 ;
   RECT 35.5080 0.2160 35.5560 0.2640 ;
  END
 END wd[112]
 PIN rd[112]
  DIRECTION OUTPUT ;
  USE SIGNAL ;
  PORT
   LAYER M4 ;
   RECT 0.2160 25.8120 0.2640 25.8600 ;
  END
 END rd[112]
 PIN wd[113]
  DIRECTION INPUT ;
  USE SIGNAL ;
  PORT
   LAYER M5 ;
   RECT 35.7480 0.2160 35.7960 0.2640 ;
  END
 END wd[113]
 PIN rd[113]
  DIRECTION OUTPUT ;
  USE SIGNAL ;
  PORT
   LAYER M4 ;
   RECT 0.2160 26.0040 0.2640 26.0520 ;
  END
 END rd[113]
 PIN wd[114]
  DIRECTION INPUT ;
  USE SIGNAL ;
  PORT
   LAYER M5 ;
   RECT 35.9880 0.2160 36.0360 0.2640 ;
  END
 END wd[114]
 PIN rd[114]
  DIRECTION OUTPUT ;
  USE SIGNAL ;
  PORT
   LAYER M4 ;
   RECT 0.2160 26.1960 0.2640 26.2440 ;
  END
 END rd[114]
 PIN wd[115]
  DIRECTION INPUT ;
  USE SIGNAL ;
  PORT
   LAYER M5 ;
   RECT 36.2280 0.2160 36.2760 0.2640 ;
  END
 END wd[115]
 PIN rd[115]
  DIRECTION OUTPUT ;
  USE SIGNAL ;
  PORT
   LAYER M4 ;
   RECT 0.2160 26.3880 0.2640 26.4360 ;
  END
 END rd[115]
 PIN wd[116]
  DIRECTION INPUT ;
  USE SIGNAL ;
  PORT
   LAYER M5 ;
   RECT 36.4680 0.2160 36.5160 0.2640 ;
  END
 END wd[116]
 PIN rd[116]
  DIRECTION OUTPUT ;
  USE SIGNAL ;
  PORT
   LAYER M4 ;
   RECT 0.2160 26.5800 0.2640 26.6280 ;
  END
 END rd[116]
 PIN wd[117]
  DIRECTION INPUT ;
  USE SIGNAL ;
  PORT
   LAYER M5 ;
   RECT 36.7080 0.2160 36.7560 0.2640 ;
  END
 END wd[117]
 PIN rd[117]
  DIRECTION OUTPUT ;
  USE SIGNAL ;
  PORT
   LAYER M4 ;
   RECT 0.2160 26.7720 0.2640 26.8200 ;
  END
 END rd[117]
 PIN wd[118]
  DIRECTION INPUT ;
  USE SIGNAL ;
  PORT
   LAYER M5 ;
   RECT 36.9480 0.2160 36.9960 0.2640 ;
  END
 END wd[118]
 PIN rd[118]
  DIRECTION OUTPUT ;
  USE SIGNAL ;
  PORT
   LAYER M4 ;
   RECT 0.2160 26.9640 0.2640 27.0120 ;
  END
 END rd[118]
 PIN wd[119]
  DIRECTION INPUT ;
  USE SIGNAL ;
  PORT
   LAYER M5 ;
   RECT 37.1880 0.2160 37.2360 0.2640 ;
  END
 END wd[119]
 PIN rd[119]
  DIRECTION OUTPUT ;
  USE SIGNAL ;
  PORT
   LAYER M4 ;
   RECT 0.2160 27.1560 0.2640 27.2040 ;
  END
 END rd[119]
 PIN wd[120]
  DIRECTION INPUT ;
  USE SIGNAL ;
  PORT
   LAYER M5 ;
   RECT 37.4280 0.2160 37.4760 0.2640 ;
  END
 END wd[120]
 PIN rd[120]
  DIRECTION OUTPUT ;
  USE SIGNAL ;
  PORT
   LAYER M4 ;
   RECT 0.2160 27.3480 0.2640 27.3960 ;
  END
 END rd[120]
 PIN wd[121]
  DIRECTION INPUT ;
  USE SIGNAL ;
  PORT
   LAYER M5 ;
   RECT 37.6680 0.2160 37.7160 0.2640 ;
  END
 END wd[121]
 PIN rd[121]
  DIRECTION OUTPUT ;
  USE SIGNAL ;
  PORT
   LAYER M4 ;
   RECT 0.2160 27.5400 0.2640 27.5880 ;
  END
 END rd[121]
 PIN wd[122]
  DIRECTION INPUT ;
  USE SIGNAL ;
  PORT
   LAYER M5 ;
   RECT 37.9080 0.2160 37.9560 0.2640 ;
  END
 END wd[122]
 PIN rd[122]
  DIRECTION OUTPUT ;
  USE SIGNAL ;
  PORT
   LAYER M4 ;
   RECT 0.2160 27.7320 0.2640 27.7800 ;
  END
 END rd[122]
 PIN wd[123]
  DIRECTION INPUT ;
  USE SIGNAL ;
  PORT
   LAYER M5 ;
   RECT 38.1480 0.2160 38.1960 0.2640 ;
  END
 END wd[123]
 PIN rd[123]
  DIRECTION OUTPUT ;
  USE SIGNAL ;
  PORT
   LAYER M4 ;
   RECT 0.2160 27.9240 0.2640 27.9720 ;
  END
 END rd[123]
 PIN wd[124]
  DIRECTION INPUT ;
  USE SIGNAL ;
  PORT
   LAYER M5 ;
   RECT 38.3880 0.2160 38.4360 0.2640 ;
  END
 END wd[124]
 PIN rd[124]
  DIRECTION OUTPUT ;
  USE SIGNAL ;
  PORT
   LAYER M4 ;
   RECT 0.2160 28.1160 0.2640 28.1640 ;
  END
 END rd[124]
 PIN wd[125]
  DIRECTION INPUT ;
  USE SIGNAL ;
  PORT
   LAYER M5 ;
   RECT 38.6280 0.2160 38.6760 0.2640 ;
  END
 END wd[125]
 PIN rd[125]
  DIRECTION OUTPUT ;
  USE SIGNAL ;
  PORT
   LAYER M4 ;
   RECT 0.2160 28.3080 0.2640 28.3560 ;
  END
 END rd[125]
 PIN wd[126]
  DIRECTION INPUT ;
  USE SIGNAL ;
  PORT
   LAYER M5 ;
   RECT 38.8680 0.2160 38.9160 0.2640 ;
  END
 END wd[126]
 PIN rd[126]
  DIRECTION OUTPUT ;
  USE SIGNAL ;
  PORT
   LAYER M4 ;
   RECT 0.2160 28.5000 0.2640 28.5480 ;
  END
 END rd[126]
 PIN wd[127]
  DIRECTION INPUT ;
  USE SIGNAL ;
  PORT
   LAYER M5 ;
   RECT 39.1080 0.2160 39.1560 0.2640 ;
  END
 END wd[127]
 PIN rd[127]
  DIRECTION OUTPUT ;
  USE SIGNAL ;
  PORT
   LAYER M4 ;
   RECT 0.2160 28.6920 0.2640 28.7400 ;
  END
 END rd[127]
 PIN wd[128]
  DIRECTION INPUT ;
  USE SIGNAL ;
  PORT
   LAYER M5 ;
   RECT 39.3480 0.2160 39.3960 0.2640 ;
  END
 END wd[128]
 PIN rd[128]
  DIRECTION OUTPUT ;
  USE SIGNAL ;
  PORT
   LAYER M4 ;
   RECT 0.2160 28.8840 0.2640 28.9320 ;
  END
 END rd[128]
 PIN wd[129]
  DIRECTION INPUT ;
  USE SIGNAL ;
  PORT
   LAYER M5 ;
   RECT 39.5880 0.2160 39.6360 0.2640 ;
  END
 END wd[129]
 PIN rd[129]
  DIRECTION OUTPUT ;
  USE SIGNAL ;
  PORT
   LAYER M4 ;
   RECT 0.2160 29.0760 0.2640 29.1240 ;
  END
 END rd[129]
 PIN wd[130]
  DIRECTION INPUT ;
  USE SIGNAL ;
  PORT
   LAYER M5 ;
   RECT 39.8280 0.2160 39.8760 0.2640 ;
  END
 END wd[130]
 PIN rd[130]
  DIRECTION OUTPUT ;
  USE SIGNAL ;
  PORT
   LAYER M4 ;
   RECT 0.2160 29.2680 0.2640 29.3160 ;
  END
 END rd[130]
 PIN wd[131]
  DIRECTION INPUT ;
  USE SIGNAL ;
  PORT
   LAYER M5 ;
   RECT 40.0680 0.2160 40.1160 0.2640 ;
  END
 END wd[131]
 PIN rd[131]
  DIRECTION OUTPUT ;
  USE SIGNAL ;
  PORT
   LAYER M4 ;
   RECT 0.2160 29.4600 0.2640 29.5080 ;
  END
 END rd[131]
 PIN wd[132]
  DIRECTION INPUT ;
  USE SIGNAL ;
  PORT
   LAYER M5 ;
   RECT 40.3080 0.2160 40.3560 0.2640 ;
  END
 END wd[132]
 PIN rd[132]
  DIRECTION OUTPUT ;
  USE SIGNAL ;
  PORT
   LAYER M4 ;
   RECT 0.2160 29.6520 0.2640 29.7000 ;
  END
 END rd[132]
 PIN wd[133]
  DIRECTION INPUT ;
  USE SIGNAL ;
  PORT
   LAYER M5 ;
   RECT 40.5480 0.2160 40.5960 0.2640 ;
  END
 END wd[133]
 PIN rd[133]
  DIRECTION OUTPUT ;
  USE SIGNAL ;
  PORT
   LAYER M4 ;
   RECT 0.2160 29.8440 0.2640 29.8920 ;
  END
 END rd[133]
 PIN wd[134]
  DIRECTION INPUT ;
  USE SIGNAL ;
  PORT
   LAYER M5 ;
   RECT 40.7880 0.2160 40.8360 0.2640 ;
  END
 END wd[134]
 PIN rd[134]
  DIRECTION OUTPUT ;
  USE SIGNAL ;
  PORT
   LAYER M4 ;
   RECT 0.2160 30.0360 0.2640 30.0840 ;
  END
 END rd[134]
 PIN wd[135]
  DIRECTION INPUT ;
  USE SIGNAL ;
  PORT
   LAYER M5 ;
   RECT 41.0280 0.2160 41.0760 0.2640 ;
  END
 END wd[135]
 PIN rd[135]
  DIRECTION OUTPUT ;
  USE SIGNAL ;
  PORT
   LAYER M4 ;
   RECT 0.2160 30.2280 0.2640 30.2760 ;
  END
 END rd[135]
 PIN wd[136]
  DIRECTION INPUT ;
  USE SIGNAL ;
  PORT
   LAYER M5 ;
   RECT 41.2680 0.2160 41.3160 0.2640 ;
  END
 END wd[136]
 PIN rd[136]
  DIRECTION OUTPUT ;
  USE SIGNAL ;
  PORT
   LAYER M4 ;
   RECT 0.2160 30.4200 0.2640 30.4680 ;
  END
 END rd[136]
 PIN wd[137]
  DIRECTION INPUT ;
  USE SIGNAL ;
  PORT
   LAYER M5 ;
   RECT 41.5080 0.2160 41.5560 0.2640 ;
  END
 END wd[137]
 PIN rd[137]
  DIRECTION OUTPUT ;
  USE SIGNAL ;
  PORT
   LAYER M4 ;
   RECT 0.2160 30.6120 0.2640 30.6600 ;
  END
 END rd[137]
 PIN wd[138]
  DIRECTION INPUT ;
  USE SIGNAL ;
  PORT
   LAYER M5 ;
   RECT 41.7480 0.2160 41.7960 0.2640 ;
  END
 END wd[138]
 PIN rd[138]
  DIRECTION OUTPUT ;
  USE SIGNAL ;
  PORT
   LAYER M4 ;
   RECT 0.2160 30.8040 0.2640 30.8520 ;
  END
 END rd[138]
 PIN wd[139]
  DIRECTION INPUT ;
  USE SIGNAL ;
  PORT
   LAYER M5 ;
   RECT 41.9880 0.2160 42.0360 0.2640 ;
  END
 END wd[139]
 PIN rd[139]
  DIRECTION OUTPUT ;
  USE SIGNAL ;
  PORT
   LAYER M4 ;
   RECT 0.2160 30.9960 0.2640 31.0440 ;
  END
 END rd[139]
 PIN wd[140]
  DIRECTION INPUT ;
  USE SIGNAL ;
  PORT
   LAYER M5 ;
   RECT 42.2280 0.2160 42.2760 0.2640 ;
  END
 END wd[140]
 PIN rd[140]
  DIRECTION OUTPUT ;
  USE SIGNAL ;
  PORT
   LAYER M4 ;
   RECT 0.2160 31.1880 0.2640 31.2360 ;
  END
 END rd[140]
 PIN wd[141]
  DIRECTION INPUT ;
  USE SIGNAL ;
  PORT
   LAYER M5 ;
   RECT 42.4680 0.2160 42.5160 0.2640 ;
  END
 END wd[141]
 PIN rd[141]
  DIRECTION OUTPUT ;
  USE SIGNAL ;
  PORT
   LAYER M4 ;
   RECT 0.2160 31.3800 0.2640 31.4280 ;
  END
 END rd[141]
 PIN wd[142]
  DIRECTION INPUT ;
  USE SIGNAL ;
  PORT
   LAYER M5 ;
   RECT 42.7080 0.2160 42.7560 0.2640 ;
  END
 END wd[142]
 PIN rd[142]
  DIRECTION OUTPUT ;
  USE SIGNAL ;
  PORT
   LAYER M4 ;
   RECT 0.2160 31.5720 0.2640 31.6200 ;
  END
 END rd[142]
 PIN wd[143]
  DIRECTION INPUT ;
  USE SIGNAL ;
  PORT
   LAYER M5 ;
   RECT 42.9480 0.2160 42.9960 0.2640 ;
  END
 END wd[143]
 PIN rd[143]
  DIRECTION OUTPUT ;
  USE SIGNAL ;
  PORT
   LAYER M4 ;
   RECT 0.2160 31.7640 0.2640 31.8120 ;
  END
 END rd[143]
 PIN wd[144]
  DIRECTION INPUT ;
  USE SIGNAL ;
  PORT
   LAYER M5 ;
   RECT 43.1880 0.2160 43.2360 0.2640 ;
  END
 END wd[144]
 PIN rd[144]
  DIRECTION OUTPUT ;
  USE SIGNAL ;
  PORT
   LAYER M4 ;
   RECT 0.2160 31.9560 0.2640 32.0040 ;
  END
 END rd[144]
 PIN wd[145]
  DIRECTION INPUT ;
  USE SIGNAL ;
  PORT
   LAYER M5 ;
   RECT 43.4280 0.2160 43.4760 0.2640 ;
  END
 END wd[145]
 PIN rd[145]
  DIRECTION OUTPUT ;
  USE SIGNAL ;
  PORT
   LAYER M4 ;
   RECT 0.2160 32.1480 0.2640 32.1960 ;
  END
 END rd[145]
 PIN wd[146]
  DIRECTION INPUT ;
  USE SIGNAL ;
  PORT
   LAYER M5 ;
   RECT 43.6680 0.2160 43.7160 0.2640 ;
  END
 END wd[146]
 PIN rd[146]
  DIRECTION OUTPUT ;
  USE SIGNAL ;
  PORT
   LAYER M4 ;
   RECT 0.2160 32.3400 0.2640 32.3880 ;
  END
 END rd[146]
 PIN wd[147]
  DIRECTION INPUT ;
  USE SIGNAL ;
  PORT
   LAYER M5 ;
   RECT 43.9080 0.2160 43.9560 0.2640 ;
  END
 END wd[147]
 PIN rd[147]
  DIRECTION OUTPUT ;
  USE SIGNAL ;
  PORT
   LAYER M4 ;
   RECT 0.2160 32.5320 0.2640 32.5800 ;
  END
 END rd[147]
 PIN wd[148]
  DIRECTION INPUT ;
  USE SIGNAL ;
  PORT
   LAYER M5 ;
   RECT 44.1480 0.2160 44.1960 0.2640 ;
  END
 END wd[148]
 PIN rd[148]
  DIRECTION OUTPUT ;
  USE SIGNAL ;
  PORT
   LAYER M4 ;
   RECT 0.2160 32.7240 0.2640 32.7720 ;
  END
 END rd[148]
 PIN wd[149]
  DIRECTION INPUT ;
  USE SIGNAL ;
  PORT
   LAYER M5 ;
   RECT 44.3880 0.2160 44.4360 0.2640 ;
  END
 END wd[149]
 PIN rd[149]
  DIRECTION OUTPUT ;
  USE SIGNAL ;
  PORT
   LAYER M4 ;
   RECT 0.2160 32.9160 0.2640 32.9640 ;
  END
 END rd[149]
 PIN wd[150]
  DIRECTION INPUT ;
  USE SIGNAL ;
  PORT
   LAYER M5 ;
   RECT 44.6280 0.2160 44.6760 0.2640 ;
  END
 END wd[150]
 PIN rd[150]
  DIRECTION OUTPUT ;
  USE SIGNAL ;
  PORT
   LAYER M4 ;
   RECT 0.2160 33.1080 0.2640 33.1560 ;
  END
 END rd[150]
 PIN wd[151]
  DIRECTION INPUT ;
  USE SIGNAL ;
  PORT
   LAYER M5 ;
   RECT 44.8680 0.2160 44.9160 0.2640 ;
  END
 END wd[151]
 PIN rd[151]
  DIRECTION OUTPUT ;
  USE SIGNAL ;
  PORT
   LAYER M4 ;
   RECT 0.2160 33.3000 0.2640 33.3480 ;
  END
 END rd[151]
 PIN wd[152]
  DIRECTION INPUT ;
  USE SIGNAL ;
  PORT
   LAYER M5 ;
   RECT 45.1080 0.2160 45.1560 0.2640 ;
  END
 END wd[152]
 PIN rd[152]
  DIRECTION OUTPUT ;
  USE SIGNAL ;
  PORT
   LAYER M4 ;
   RECT 0.2160 33.4920 0.2640 33.5400 ;
  END
 END rd[152]
 PIN wd[153]
  DIRECTION INPUT ;
  USE SIGNAL ;
  PORT
   LAYER M5 ;
   RECT 45.3480 0.2160 45.3960 0.2640 ;
  END
 END wd[153]
 PIN rd[153]
  DIRECTION OUTPUT ;
  USE SIGNAL ;
  PORT
   LAYER M4 ;
   RECT 0.2160 33.6840 0.2640 33.7320 ;
  END
 END rd[153]
 PIN wd[154]
  DIRECTION INPUT ;
  USE SIGNAL ;
  PORT
   LAYER M5 ;
   RECT 45.5880 0.2160 45.6360 0.2640 ;
  END
 END wd[154]
 PIN rd[154]
  DIRECTION OUTPUT ;
  USE SIGNAL ;
  PORT
   LAYER M4 ;
   RECT 0.2160 33.8760 0.2640 33.9240 ;
  END
 END rd[154]
 PIN wd[155]
  DIRECTION INPUT ;
  USE SIGNAL ;
  PORT
   LAYER M5 ;
   RECT 45.8280 0.2160 45.8760 0.2640 ;
  END
 END wd[155]
 PIN rd[155]
  DIRECTION OUTPUT ;
  USE SIGNAL ;
  PORT
   LAYER M4 ;
   RECT 0.2160 34.0680 0.2640 34.1160 ;
  END
 END rd[155]
 PIN wd[156]
  DIRECTION INPUT ;
  USE SIGNAL ;
  PORT
   LAYER M5 ;
   RECT 46.0680 0.2160 46.1160 0.2640 ;
  END
 END wd[156]
 PIN rd[156]
  DIRECTION OUTPUT ;
  USE SIGNAL ;
  PORT
   LAYER M4 ;
   RECT 0.2160 34.2600 0.2640 34.3080 ;
  END
 END rd[156]
 PIN wd[157]
  DIRECTION INPUT ;
  USE SIGNAL ;
  PORT
   LAYER M5 ;
   RECT 46.3080 0.2160 46.3560 0.2640 ;
  END
 END wd[157]
 PIN rd[157]
  DIRECTION OUTPUT ;
  USE SIGNAL ;
  PORT
   LAYER M4 ;
   RECT 0.2160 34.4520 0.2640 34.5000 ;
  END
 END rd[157]
 PIN wd[158]
  DIRECTION INPUT ;
  USE SIGNAL ;
  PORT
   LAYER M5 ;
   RECT 46.5480 0.2160 46.5960 0.2640 ;
  END
 END wd[158]
 PIN rd[158]
  DIRECTION OUTPUT ;
  USE SIGNAL ;
  PORT
   LAYER M4 ;
   RECT 0.2160 34.6440 0.2640 34.6920 ;
  END
 END rd[158]
 PIN wd[159]
  DIRECTION INPUT ;
  USE SIGNAL ;
  PORT
   LAYER M5 ;
   RECT 46.7880 0.2160 46.8360 0.2640 ;
  END
 END wd[159]
 PIN rd[159]
  DIRECTION OUTPUT ;
  USE SIGNAL ;
  PORT
   LAYER M4 ;
   RECT 0.2160 34.8360 0.2640 34.8840 ;
  END
 END rd[159]
 PIN wd[160]
  DIRECTION INPUT ;
  USE SIGNAL ;
  PORT
   LAYER M5 ;
   RECT 47.0280 0.2160 47.0760 0.2640 ;
  END
 END wd[160]
 PIN rd[160]
  DIRECTION OUTPUT ;
  USE SIGNAL ;
  PORT
   LAYER M4 ;
   RECT 0.2160 35.0280 0.2640 35.0760 ;
  END
 END rd[160]
 PIN wd[161]
  DIRECTION INPUT ;
  USE SIGNAL ;
  PORT
   LAYER M5 ;
   RECT 47.2680 0.2160 47.3160 0.2640 ;
  END
 END wd[161]
 PIN rd[161]
  DIRECTION OUTPUT ;
  USE SIGNAL ;
  PORT
   LAYER M4 ;
   RECT 0.2160 35.2200 0.2640 35.2680 ;
  END
 END rd[161]
 PIN wd[162]
  DIRECTION INPUT ;
  USE SIGNAL ;
  PORT
   LAYER M5 ;
   RECT 47.5080 0.2160 47.5560 0.2640 ;
  END
 END wd[162]
 PIN rd[162]
  DIRECTION OUTPUT ;
  USE SIGNAL ;
  PORT
   LAYER M4 ;
   RECT 0.2160 35.4120 0.2640 35.4600 ;
  END
 END rd[162]
 PIN wd[163]
  DIRECTION INPUT ;
  USE SIGNAL ;
  PORT
   LAYER M5 ;
   RECT 47.7480 0.2160 47.7960 0.2640 ;
  END
 END wd[163]
 PIN rd[163]
  DIRECTION OUTPUT ;
  USE SIGNAL ;
  PORT
   LAYER M4 ;
   RECT 0.2160 35.6040 0.2640 35.6520 ;
  END
 END rd[163]
 PIN wd[164]
  DIRECTION INPUT ;
  USE SIGNAL ;
  PORT
   LAYER M5 ;
   RECT 47.9880 0.2160 48.0360 0.2640 ;
  END
 END wd[164]
 PIN rd[164]
  DIRECTION OUTPUT ;
  USE SIGNAL ;
  PORT
   LAYER M4 ;
   RECT 0.2160 35.7960 0.2640 35.8440 ;
  END
 END rd[164]
 PIN wd[165]
  DIRECTION INPUT ;
  USE SIGNAL ;
  PORT
   LAYER M5 ;
   RECT 48.2280 0.2160 48.2760 0.2640 ;
  END
 END wd[165]
 PIN rd[165]
  DIRECTION OUTPUT ;
  USE SIGNAL ;
  PORT
   LAYER M4 ;
   RECT 0.2160 35.9880 0.2640 36.0360 ;
  END
 END rd[165]
 PIN wd[166]
  DIRECTION INPUT ;
  USE SIGNAL ;
  PORT
   LAYER M5 ;
   RECT 48.4680 0.2160 48.5160 0.2640 ;
  END
 END wd[166]
 PIN rd[166]
  DIRECTION OUTPUT ;
  USE SIGNAL ;
  PORT
   LAYER M4 ;
   RECT 0.2160 36.1800 0.2640 36.2280 ;
  END
 END rd[166]
 PIN wd[167]
  DIRECTION INPUT ;
  USE SIGNAL ;
  PORT
   LAYER M5 ;
   RECT 48.7080 0.2160 48.7560 0.2640 ;
  END
 END wd[167]
 PIN rd[167]
  DIRECTION OUTPUT ;
  USE SIGNAL ;
  PORT
   LAYER M4 ;
   RECT 0.2160 36.3720 0.2640 36.4200 ;
  END
 END rd[167]
 PIN wd[168]
  DIRECTION INPUT ;
  USE SIGNAL ;
  PORT
   LAYER M5 ;
   RECT 48.9480 0.2160 48.9960 0.2640 ;
  END
 END wd[168]
 PIN rd[168]
  DIRECTION OUTPUT ;
  USE SIGNAL ;
  PORT
   LAYER M4 ;
   RECT 0.2160 36.5640 0.2640 36.6120 ;
  END
 END rd[168]
 PIN wd[169]
  DIRECTION INPUT ;
  USE SIGNAL ;
  PORT
   LAYER M5 ;
   RECT 49.1880 0.2160 49.2360 0.2640 ;
  END
 END wd[169]
 PIN rd[169]
  DIRECTION OUTPUT ;
  USE SIGNAL ;
  PORT
   LAYER M4 ;
   RECT 0.2160 36.7560 0.2640 36.8040 ;
  END
 END rd[169]
 PIN wd[170]
  DIRECTION INPUT ;
  USE SIGNAL ;
  PORT
   LAYER M5 ;
   RECT 49.4280 0.2160 49.4760 0.2640 ;
  END
 END wd[170]
 PIN rd[170]
  DIRECTION OUTPUT ;
  USE SIGNAL ;
  PORT
   LAYER M4 ;
   RECT 0.2160 36.9480 0.2640 36.9960 ;
  END
 END rd[170]
 PIN wd[171]
  DIRECTION INPUT ;
  USE SIGNAL ;
  PORT
   LAYER M5 ;
   RECT 49.6680 0.2160 49.7160 0.2640 ;
  END
 END wd[171]
 PIN rd[171]
  DIRECTION OUTPUT ;
  USE SIGNAL ;
  PORT
   LAYER M4 ;
   RECT 0.2160 37.1400 0.2640 37.1880 ;
  END
 END rd[171]
 PIN wd[172]
  DIRECTION INPUT ;
  USE SIGNAL ;
  PORT
   LAYER M5 ;
   RECT 49.9080 0.2160 49.9560 0.2640 ;
  END
 END wd[172]
 PIN rd[172]
  DIRECTION OUTPUT ;
  USE SIGNAL ;
  PORT
   LAYER M4 ;
   RECT 0.2160 37.3320 0.2640 37.3800 ;
  END
 END rd[172]
 PIN wd[173]
  DIRECTION INPUT ;
  USE SIGNAL ;
  PORT
   LAYER M5 ;
   RECT 50.1480 0.2160 50.1960 0.2640 ;
  END
 END wd[173]
 PIN rd[173]
  DIRECTION OUTPUT ;
  USE SIGNAL ;
  PORT
   LAYER M4 ;
   RECT 0.2160 37.5240 0.2640 37.5720 ;
  END
 END rd[173]
 PIN wd[174]
  DIRECTION INPUT ;
  USE SIGNAL ;
  PORT
   LAYER M5 ;
   RECT 50.3880 0.2160 50.4360 0.2640 ;
  END
 END wd[174]
 PIN rd[174]
  DIRECTION OUTPUT ;
  USE SIGNAL ;
  PORT
   LAYER M4 ;
   RECT 0.2160 37.7160 0.2640 37.7640 ;
  END
 END rd[174]
 PIN wd[175]
  DIRECTION INPUT ;
  USE SIGNAL ;
  PORT
   LAYER M5 ;
   RECT 50.6280 0.2160 50.6760 0.2640 ;
  END
 END wd[175]
 PIN rd[175]
  DIRECTION OUTPUT ;
  USE SIGNAL ;
  PORT
   LAYER M4 ;
   RECT 0.2160 37.9080 0.2640 37.9560 ;
  END
 END rd[175]
 PIN wd[176]
  DIRECTION INPUT ;
  USE SIGNAL ;
  PORT
   LAYER M5 ;
   RECT 50.8680 0.2160 50.9160 0.2640 ;
  END
 END wd[176]
 PIN rd[176]
  DIRECTION OUTPUT ;
  USE SIGNAL ;
  PORT
   LAYER M4 ;
   RECT 0.2160 38.1000 0.2640 38.1480 ;
  END
 END rd[176]
 PIN wd[177]
  DIRECTION INPUT ;
  USE SIGNAL ;
  PORT
   LAYER M5 ;
   RECT 51.1080 0.2160 51.1560 0.2640 ;
  END
 END wd[177]
 PIN rd[177]
  DIRECTION OUTPUT ;
  USE SIGNAL ;
  PORT
   LAYER M4 ;
   RECT 0.2160 38.2920 0.2640 38.3400 ;
  END
 END rd[177]
 PIN wd[178]
  DIRECTION INPUT ;
  USE SIGNAL ;
  PORT
   LAYER M5 ;
   RECT 51.3480 0.2160 51.3960 0.2640 ;
  END
 END wd[178]
 PIN rd[178]
  DIRECTION OUTPUT ;
  USE SIGNAL ;
  PORT
   LAYER M4 ;
   RECT 0.2160 38.4840 0.2640 38.5320 ;
  END
 END rd[178]
 PIN wd[179]
  DIRECTION INPUT ;
  USE SIGNAL ;
  PORT
   LAYER M5 ;
   RECT 51.5880 0.2160 51.6360 0.2640 ;
  END
 END wd[179]
 PIN rd[179]
  DIRECTION OUTPUT ;
  USE SIGNAL ;
  PORT
   LAYER M4 ;
   RECT 0.2160 38.6760 0.2640 38.7240 ;
  END
 END rd[179]
 PIN wd[180]
  DIRECTION INPUT ;
  USE SIGNAL ;
  PORT
   LAYER M5 ;
   RECT 51.8280 0.2160 51.8760 0.2640 ;
  END
 END wd[180]
 PIN rd[180]
  DIRECTION OUTPUT ;
  USE SIGNAL ;
  PORT
   LAYER M4 ;
   RECT 0.2160 38.8680 0.2640 38.9160 ;
  END
 END rd[180]
 PIN wd[181]
  DIRECTION INPUT ;
  USE SIGNAL ;
  PORT
   LAYER M5 ;
   RECT 52.0680 0.2160 52.1160 0.2640 ;
  END
 END wd[181]
 PIN rd[181]
  DIRECTION OUTPUT ;
  USE SIGNAL ;
  PORT
   LAYER M4 ;
   RECT 0.2160 39.0600 0.2640 39.1080 ;
  END
 END rd[181]
 PIN wd[182]
  DIRECTION INPUT ;
  USE SIGNAL ;
  PORT
   LAYER M5 ;
   RECT 52.3080 0.2160 52.3560 0.2640 ;
  END
 END wd[182]
 PIN rd[182]
  DIRECTION OUTPUT ;
  USE SIGNAL ;
  PORT
   LAYER M4 ;
   RECT 0.2160 39.2520 0.2640 39.3000 ;
  END
 END rd[182]
 PIN wd[183]
  DIRECTION INPUT ;
  USE SIGNAL ;
  PORT
   LAYER M5 ;
   RECT 52.5480 0.2160 52.5960 0.2640 ;
  END
 END wd[183]
 PIN rd[183]
  DIRECTION OUTPUT ;
  USE SIGNAL ;
  PORT
   LAYER M4 ;
   RECT 0.2160 39.4440 0.2640 39.4920 ;
  END
 END rd[183]
 PIN wd[184]
  DIRECTION INPUT ;
  USE SIGNAL ;
  PORT
   LAYER M5 ;
   RECT 52.7880 0.2160 52.8360 0.2640 ;
  END
 END wd[184]
 PIN rd[184]
  DIRECTION OUTPUT ;
  USE SIGNAL ;
  PORT
   LAYER M4 ;
   RECT 0.2160 39.6360 0.2640 39.6840 ;
  END
 END rd[184]
 PIN wd[185]
  DIRECTION INPUT ;
  USE SIGNAL ;
  PORT
   LAYER M5 ;
   RECT 53.0280 0.2160 53.0760 0.2640 ;
  END
 END wd[185]
 PIN rd[185]
  DIRECTION OUTPUT ;
  USE SIGNAL ;
  PORT
   LAYER M4 ;
   RECT 0.2160 39.8280 0.2640 39.8760 ;
  END
 END rd[185]
 PIN wd[186]
  DIRECTION INPUT ;
  USE SIGNAL ;
  PORT
   LAYER M5 ;
   RECT 53.2680 0.2160 53.3160 0.2640 ;
  END
 END wd[186]
 PIN rd[186]
  DIRECTION OUTPUT ;
  USE SIGNAL ;
  PORT
   LAYER M4 ;
   RECT 0.2160 40.0200 0.2640 40.0680 ;
  END
 END rd[186]
 PIN wd[187]
  DIRECTION INPUT ;
  USE SIGNAL ;
  PORT
   LAYER M5 ;
   RECT 53.5080 0.2160 53.5560 0.2640 ;
  END
 END wd[187]
 PIN rd[187]
  DIRECTION OUTPUT ;
  USE SIGNAL ;
  PORT
   LAYER M4 ;
   RECT 0.2160 40.2120 0.2640 40.2600 ;
  END
 END rd[187]
 PIN wd[188]
  DIRECTION INPUT ;
  USE SIGNAL ;
  PORT
   LAYER M5 ;
   RECT 53.7480 0.2160 53.7960 0.2640 ;
  END
 END wd[188]
 PIN rd[188]
  DIRECTION OUTPUT ;
  USE SIGNAL ;
  PORT
   LAYER M4 ;
   RECT 0.2160 40.4040 0.2640 40.4520 ;
  END
 END rd[188]
 PIN wd[189]
  DIRECTION INPUT ;
  USE SIGNAL ;
  PORT
   LAYER M5 ;
   RECT 53.9880 0.2160 54.0360 0.2640 ;
  END
 END wd[189]
 PIN rd[189]
  DIRECTION OUTPUT ;
  USE SIGNAL ;
  PORT
   LAYER M4 ;
   RECT 0.2160 40.5960 0.2640 40.6440 ;
  END
 END rd[189]
 PIN wd[190]
  DIRECTION INPUT ;
  USE SIGNAL ;
  PORT
   LAYER M5 ;
   RECT 54.2280 0.2160 54.2760 0.2640 ;
  END
 END wd[190]
 PIN rd[190]
  DIRECTION OUTPUT ;
  USE SIGNAL ;
  PORT
   LAYER M4 ;
   RECT 0.2160 40.7880 0.2640 40.8360 ;
  END
 END rd[190]
 PIN wd[191]
  DIRECTION INPUT ;
  USE SIGNAL ;
  PORT
   LAYER M5 ;
   RECT 54.4680 0.2160 54.5160 0.2640 ;
  END
 END wd[191]
 PIN rd[191]
  DIRECTION OUTPUT ;
  USE SIGNAL ;
  PORT
   LAYER M4 ;
   RECT 0.2160 40.9800 0.2640 41.0280 ;
  END
 END rd[191]
 PIN wd[192]
  DIRECTION INPUT ;
  USE SIGNAL ;
  PORT
   LAYER M5 ;
   RECT 54.7080 0.2160 54.7560 0.2640 ;
  END
 END wd[192]
 PIN rd[192]
  DIRECTION OUTPUT ;
  USE SIGNAL ;
  PORT
   LAYER M4 ;
   RECT 0.2160 41.1720 0.2640 41.2200 ;
  END
 END rd[192]
 PIN wd[193]
  DIRECTION INPUT ;
  USE SIGNAL ;
  PORT
   LAYER M5 ;
   RECT 54.9480 0.2160 54.9960 0.2640 ;
  END
 END wd[193]
 PIN rd[193]
  DIRECTION OUTPUT ;
  USE SIGNAL ;
  PORT
   LAYER M4 ;
   RECT 0.2160 41.3640 0.2640 41.4120 ;
  END
 END rd[193]
 PIN wd[194]
  DIRECTION INPUT ;
  USE SIGNAL ;
  PORT
   LAYER M5 ;
   RECT 55.1880 0.2160 55.2360 0.2640 ;
  END
 END wd[194]
 PIN rd[194]
  DIRECTION OUTPUT ;
  USE SIGNAL ;
  PORT
   LAYER M4 ;
   RECT 0.2160 41.5560 0.2640 41.6040 ;
  END
 END rd[194]
 PIN wd[195]
  DIRECTION INPUT ;
  USE SIGNAL ;
  PORT
   LAYER M5 ;
   RECT 55.4280 0.2160 55.4760 0.2640 ;
  END
 END wd[195]
 PIN rd[195]
  DIRECTION OUTPUT ;
  USE SIGNAL ;
  PORT
   LAYER M4 ;
   RECT 0.2160 41.7480 0.2640 41.7960 ;
  END
 END rd[195]
 PIN wd[196]
  DIRECTION INPUT ;
  USE SIGNAL ;
  PORT
   LAYER M5 ;
   RECT 55.6680 0.2160 55.7160 0.2640 ;
  END
 END wd[196]
 PIN rd[196]
  DIRECTION OUTPUT ;
  USE SIGNAL ;
  PORT
   LAYER M4 ;
   RECT 0.2160 41.9400 0.2640 41.9880 ;
  END
 END rd[196]
 PIN wd[197]
  DIRECTION INPUT ;
  USE SIGNAL ;
  PORT
   LAYER M5 ;
   RECT 55.9080 0.2160 55.9560 0.2640 ;
  END
 END wd[197]
 PIN rd[197]
  DIRECTION OUTPUT ;
  USE SIGNAL ;
  PORT
   LAYER M4 ;
   RECT 0.2160 42.1320 0.2640 42.1800 ;
  END
 END rd[197]
 PIN wd[198]
  DIRECTION INPUT ;
  USE SIGNAL ;
  PORT
   LAYER M5 ;
   RECT 56.1480 0.2160 56.1960 0.2640 ;
  END
 END wd[198]
 PIN rd[198]
  DIRECTION OUTPUT ;
  USE SIGNAL ;
  PORT
   LAYER M4 ;
   RECT 0.2160 42.3240 0.2640 42.3720 ;
  END
 END rd[198]
 PIN wd[199]
  DIRECTION INPUT ;
  USE SIGNAL ;
  PORT
   LAYER M5 ;
   RECT 56.3880 0.2160 56.4360 0.2640 ;
  END
 END wd[199]
 PIN rd[199]
  DIRECTION OUTPUT ;
  USE SIGNAL ;
  PORT
   LAYER M4 ;
   RECT 0.2160 42.5160 0.2640 42.5640 ;
  END
 END rd[199]
 PIN wd[200]
  DIRECTION INPUT ;
  USE SIGNAL ;
  PORT
   LAYER M5 ;
   RECT 56.6280 0.2160 56.6760 0.2640 ;
  END
 END wd[200]
 PIN rd[200]
  DIRECTION OUTPUT ;
  USE SIGNAL ;
  PORT
   LAYER M4 ;
   RECT 0.2160 42.7080 0.2640 42.7560 ;
  END
 END rd[200]
 PIN wd[201]
  DIRECTION INPUT ;
  USE SIGNAL ;
  PORT
   LAYER M5 ;
   RECT 56.8680 0.2160 56.9160 0.2640 ;
  END
 END wd[201]
 PIN rd[201]
  DIRECTION OUTPUT ;
  USE SIGNAL ;
  PORT
   LAYER M4 ;
   RECT 0.2160 42.9000 0.2640 42.9480 ;
  END
 END rd[201]
 PIN wd[202]
  DIRECTION INPUT ;
  USE SIGNAL ;
  PORT
   LAYER M5 ;
   RECT 57.1080 0.2160 57.1560 0.2640 ;
  END
 END wd[202]
 PIN rd[202]
  DIRECTION OUTPUT ;
  USE SIGNAL ;
  PORT
   LAYER M4 ;
   RECT 0.2160 43.0920 0.2640 43.1400 ;
  END
 END rd[202]
 PIN wd[203]
  DIRECTION INPUT ;
  USE SIGNAL ;
  PORT
   LAYER M5 ;
   RECT 57.3480 0.2160 57.3960 0.2640 ;
  END
 END wd[203]
 PIN rd[203]
  DIRECTION OUTPUT ;
  USE SIGNAL ;
  PORT
   LAYER M4 ;
   RECT 0.2160 43.2840 0.2640 43.3320 ;
  END
 END rd[203]
 PIN wd[204]
  DIRECTION INPUT ;
  USE SIGNAL ;
  PORT
   LAYER M5 ;
   RECT 57.5880 0.2160 57.6360 0.2640 ;
  END
 END wd[204]
 PIN rd[204]
  DIRECTION OUTPUT ;
  USE SIGNAL ;
  PORT
   LAYER M4 ;
   RECT 0.2160 43.4760 0.2640 43.5240 ;
  END
 END rd[204]
 PIN wd[205]
  DIRECTION INPUT ;
  USE SIGNAL ;
  PORT
   LAYER M5 ;
   RECT 57.8280 0.2160 57.8760 0.2640 ;
  END
 END wd[205]
 PIN rd[205]
  DIRECTION OUTPUT ;
  USE SIGNAL ;
  PORT
   LAYER M4 ;
   RECT 0.2160 43.6680 0.2640 43.7160 ;
  END
 END rd[205]
 PIN wd[206]
  DIRECTION INPUT ;
  USE SIGNAL ;
  PORT
   LAYER M5 ;
   RECT 58.0680 0.2160 58.1160 0.2640 ;
  END
 END wd[206]
 PIN rd[206]
  DIRECTION OUTPUT ;
  USE SIGNAL ;
  PORT
   LAYER M4 ;
   RECT 0.2160 43.8600 0.2640 43.9080 ;
  END
 END rd[206]
 PIN wd[207]
  DIRECTION INPUT ;
  USE SIGNAL ;
  PORT
   LAYER M5 ;
   RECT 58.3080 0.2160 58.3560 0.2640 ;
  END
 END wd[207]
 PIN rd[207]
  DIRECTION OUTPUT ;
  USE SIGNAL ;
  PORT
   LAYER M4 ;
   RECT 0.2160 44.0520 0.2640 44.1000 ;
  END
 END rd[207]
 PIN wd[208]
  DIRECTION INPUT ;
  USE SIGNAL ;
  PORT
   LAYER M5 ;
   RECT 58.5480 0.2160 58.5960 0.2640 ;
  END
 END wd[208]
 PIN rd[208]
  DIRECTION OUTPUT ;
  USE SIGNAL ;
  PORT
   LAYER M4 ;
   RECT 0.2160 44.2440 0.2640 44.2920 ;
  END
 END rd[208]
 PIN wd[209]
  DIRECTION INPUT ;
  USE SIGNAL ;
  PORT
   LAYER M5 ;
   RECT 58.7880 0.2160 58.8360 0.2640 ;
  END
 END wd[209]
 PIN rd[209]
  DIRECTION OUTPUT ;
  USE SIGNAL ;
  PORT
   LAYER M4 ;
   RECT 0.2160 44.4360 0.2640 44.4840 ;
  END
 END rd[209]
 PIN wd[210]
  DIRECTION INPUT ;
  USE SIGNAL ;
  PORT
   LAYER M5 ;
   RECT 59.0280 0.2160 59.0760 0.2640 ;
  END
 END wd[210]
 PIN rd[210]
  DIRECTION OUTPUT ;
  USE SIGNAL ;
  PORT
   LAYER M4 ;
   RECT 0.2160 44.6280 0.2640 44.6760 ;
  END
 END rd[210]
 PIN wd[211]
  DIRECTION INPUT ;
  USE SIGNAL ;
  PORT
   LAYER M5 ;
   RECT 59.2680 0.2160 59.3160 0.2640 ;
  END
 END wd[211]
 PIN rd[211]
  DIRECTION OUTPUT ;
  USE SIGNAL ;
  PORT
   LAYER M4 ;
   RECT 0.2160 44.8200 0.2640 44.8680 ;
  END
 END rd[211]
 PIN wd[212]
  DIRECTION INPUT ;
  USE SIGNAL ;
  PORT
   LAYER M5 ;
   RECT 59.5080 0.2160 59.5560 0.2640 ;
  END
 END wd[212]
 PIN rd[212]
  DIRECTION OUTPUT ;
  USE SIGNAL ;
  PORT
   LAYER M4 ;
   RECT 0.2160 45.0120 0.2640 45.0600 ;
  END
 END rd[212]
 PIN wd[213]
  DIRECTION INPUT ;
  USE SIGNAL ;
  PORT
   LAYER M5 ;
   RECT 59.7480 0.2160 59.7960 0.2640 ;
  END
 END wd[213]
 PIN rd[213]
  DIRECTION OUTPUT ;
  USE SIGNAL ;
  PORT
   LAYER M4 ;
   RECT 0.2160 45.2040 0.2640 45.2520 ;
  END
 END rd[213]
 PIN wd[214]
  DIRECTION INPUT ;
  USE SIGNAL ;
  PORT
   LAYER M5 ;
   RECT 59.9880 0.2160 60.0360 0.2640 ;
  END
 END wd[214]
 PIN rd[214]
  DIRECTION OUTPUT ;
  USE SIGNAL ;
  PORT
   LAYER M4 ;
   RECT 0.2160 45.3960 0.2640 45.4440 ;
  END
 END rd[214]
 PIN wd[215]
  DIRECTION INPUT ;
  USE SIGNAL ;
  PORT
   LAYER M5 ;
   RECT 60.2280 0.2160 60.2760 0.2640 ;
  END
 END wd[215]
 PIN rd[215]
  DIRECTION OUTPUT ;
  USE SIGNAL ;
  PORT
   LAYER M4 ;
   RECT 0.2160 45.5880 0.2640 45.6360 ;
  END
 END rd[215]
 PIN wd[216]
  DIRECTION INPUT ;
  USE SIGNAL ;
  PORT
   LAYER M5 ;
   RECT 60.4680 0.2160 60.5160 0.2640 ;
  END
 END wd[216]
 PIN rd[216]
  DIRECTION OUTPUT ;
  USE SIGNAL ;
  PORT
   LAYER M4 ;
   RECT 0.2160 45.7800 0.2640 45.8280 ;
  END
 END rd[216]
 PIN wd[217]
  DIRECTION INPUT ;
  USE SIGNAL ;
  PORT
   LAYER M5 ;
   RECT 60.7080 0.2160 60.7560 0.2640 ;
  END
 END wd[217]
 PIN rd[217]
  DIRECTION OUTPUT ;
  USE SIGNAL ;
  PORT
   LAYER M4 ;
   RECT 0.2160 45.9720 0.2640 46.0200 ;
  END
 END rd[217]
 PIN wd[218]
  DIRECTION INPUT ;
  USE SIGNAL ;
  PORT
   LAYER M5 ;
   RECT 60.9480 0.2160 60.9960 0.2640 ;
  END
 END wd[218]
 PIN rd[218]
  DIRECTION OUTPUT ;
  USE SIGNAL ;
  PORT
   LAYER M4 ;
   RECT 0.2160 46.1640 0.2640 46.2120 ;
  END
 END rd[218]
 PIN wd[219]
  DIRECTION INPUT ;
  USE SIGNAL ;
  PORT
   LAYER M5 ;
   RECT 61.1880 0.2160 61.2360 0.2640 ;
  END
 END wd[219]
 PIN rd[219]
  DIRECTION OUTPUT ;
  USE SIGNAL ;
  PORT
   LAYER M4 ;
   RECT 0.2160 46.3560 0.2640 46.4040 ;
  END
 END rd[219]
 PIN wd[220]
  DIRECTION INPUT ;
  USE SIGNAL ;
  PORT
   LAYER M5 ;
   RECT 61.4280 0.2160 61.4760 0.2640 ;
  END
 END wd[220]
 PIN rd[220]
  DIRECTION OUTPUT ;
  USE SIGNAL ;
  PORT
   LAYER M4 ;
   RECT 0.2160 46.5480 0.2640 46.5960 ;
  END
 END rd[220]
 PIN wd[221]
  DIRECTION INPUT ;
  USE SIGNAL ;
  PORT
   LAYER M5 ;
   RECT 61.6680 0.2160 61.7160 0.2640 ;
  END
 END wd[221]
 PIN rd[221]
  DIRECTION OUTPUT ;
  USE SIGNAL ;
  PORT
   LAYER M4 ;
   RECT 0.2160 46.7400 0.2640 46.7880 ;
  END
 END rd[221]
 PIN wd[222]
  DIRECTION INPUT ;
  USE SIGNAL ;
  PORT
   LAYER M5 ;
   RECT 61.9080 0.2160 61.9560 0.2640 ;
  END
 END wd[222]
 PIN rd[222]
  DIRECTION OUTPUT ;
  USE SIGNAL ;
  PORT
   LAYER M4 ;
   RECT 0.2160 46.9320 0.2640 46.9800 ;
  END
 END rd[222]
 PIN wd[223]
  DIRECTION INPUT ;
  USE SIGNAL ;
  PORT
   LAYER M5 ;
   RECT 62.1480 0.2160 62.1960 0.2640 ;
  END
 END wd[223]
 PIN rd[223]
  DIRECTION OUTPUT ;
  USE SIGNAL ;
  PORT
   LAYER M4 ;
   RECT 0.2160 47.1240 0.2640 47.1720 ;
  END
 END rd[223]
 PIN wd[224]
  DIRECTION INPUT ;
  USE SIGNAL ;
  PORT
   LAYER M5 ;
   RECT 62.3880 0.2160 62.4360 0.2640 ;
  END
 END wd[224]
 PIN rd[224]
  DIRECTION OUTPUT ;
  USE SIGNAL ;
  PORT
   LAYER M4 ;
   RECT 0.2160 47.3160 0.2640 47.3640 ;
  END
 END rd[224]
 PIN wd[225]
  DIRECTION INPUT ;
  USE SIGNAL ;
  PORT
   LAYER M5 ;
   RECT 62.6280 0.2160 62.6760 0.2640 ;
  END
 END wd[225]
 PIN rd[225]
  DIRECTION OUTPUT ;
  USE SIGNAL ;
  PORT
   LAYER M4 ;
   RECT 0.2160 47.5080 0.2640 47.5560 ;
  END
 END rd[225]
 PIN wd[226]
  DIRECTION INPUT ;
  USE SIGNAL ;
  PORT
   LAYER M5 ;
   RECT 62.8680 0.2160 62.9160 0.2640 ;
  END
 END wd[226]
 PIN rd[226]
  DIRECTION OUTPUT ;
  USE SIGNAL ;
  PORT
   LAYER M4 ;
   RECT 0.2160 47.7000 0.2640 47.7480 ;
  END
 END rd[226]
 PIN wd[227]
  DIRECTION INPUT ;
  USE SIGNAL ;
  PORT
   LAYER M5 ;
   RECT 63.1080 0.2160 63.1560 0.2640 ;
  END
 END wd[227]
 PIN rd[227]
  DIRECTION OUTPUT ;
  USE SIGNAL ;
  PORT
   LAYER M4 ;
   RECT 0.2160 47.8920 0.2640 47.9400 ;
  END
 END rd[227]
 PIN wd[228]
  DIRECTION INPUT ;
  USE SIGNAL ;
  PORT
   LAYER M5 ;
   RECT 63.3480 0.2160 63.3960 0.2640 ;
  END
 END wd[228]
 PIN rd[228]
  DIRECTION OUTPUT ;
  USE SIGNAL ;
  PORT
   LAYER M4 ;
   RECT 0.2160 48.0840 0.2640 48.1320 ;
  END
 END rd[228]
 PIN wd[229]
  DIRECTION INPUT ;
  USE SIGNAL ;
  PORT
   LAYER M5 ;
   RECT 63.5880 0.2160 63.6360 0.2640 ;
  END
 END wd[229]
 PIN rd[229]
  DIRECTION OUTPUT ;
  USE SIGNAL ;
  PORT
   LAYER M4 ;
   RECT 0.2160 48.2760 0.2640 48.3240 ;
  END
 END rd[229]
 PIN wd[230]
  DIRECTION INPUT ;
  USE SIGNAL ;
  PORT
   LAYER M5 ;
   RECT 63.8280 0.2160 63.8760 0.2640 ;
  END
 END wd[230]
 PIN rd[230]
  DIRECTION OUTPUT ;
  USE SIGNAL ;
  PORT
   LAYER M4 ;
   RECT 0.2160 48.4680 0.2640 48.5160 ;
  END
 END rd[230]
 PIN wd[231]
  DIRECTION INPUT ;
  USE SIGNAL ;
  PORT
   LAYER M5 ;
   RECT 64.0680 0.2160 64.1160 0.2640 ;
  END
 END wd[231]
 PIN rd[231]
  DIRECTION OUTPUT ;
  USE SIGNAL ;
  PORT
   LAYER M4 ;
   RECT 0.2160 48.6600 0.2640 48.7080 ;
  END
 END rd[231]
 PIN wd[232]
  DIRECTION INPUT ;
  USE SIGNAL ;
  PORT
   LAYER M5 ;
   RECT 64.3080 0.2160 64.3560 0.2640 ;
  END
 END wd[232]
 PIN rd[232]
  DIRECTION OUTPUT ;
  USE SIGNAL ;
  PORT
   LAYER M4 ;
   RECT 0.2160 48.8520 0.2640 48.9000 ;
  END
 END rd[232]
 PIN wd[233]
  DIRECTION INPUT ;
  USE SIGNAL ;
  PORT
   LAYER M5 ;
   RECT 64.5480 0.2160 64.5960 0.2640 ;
  END
 END wd[233]
 PIN rd[233]
  DIRECTION OUTPUT ;
  USE SIGNAL ;
  PORT
   LAYER M4 ;
   RECT 0.2160 49.0440 0.2640 49.0920 ;
  END
 END rd[233]
 PIN wd[234]
  DIRECTION INPUT ;
  USE SIGNAL ;
  PORT
   LAYER M5 ;
   RECT 64.7880 0.2160 64.8360 0.2640 ;
  END
 END wd[234]
 PIN rd[234]
  DIRECTION OUTPUT ;
  USE SIGNAL ;
  PORT
   LAYER M4 ;
   RECT 0.2160 49.2360 0.2640 49.2840 ;
  END
 END rd[234]
 PIN wd[235]
  DIRECTION INPUT ;
  USE SIGNAL ;
  PORT
   LAYER M5 ;
   RECT 65.0280 0.2160 65.0760 0.2640 ;
  END
 END wd[235]
 PIN rd[235]
  DIRECTION OUTPUT ;
  USE SIGNAL ;
  PORT
   LAYER M4 ;
   RECT 0.2160 49.4280 0.2640 49.4760 ;
  END
 END rd[235]
 PIN wd[236]
  DIRECTION INPUT ;
  USE SIGNAL ;
  PORT
   LAYER M5 ;
   RECT 65.2680 0.2160 65.3160 0.2640 ;
  END
 END wd[236]
 PIN rd[236]
  DIRECTION OUTPUT ;
  USE SIGNAL ;
  PORT
   LAYER M4 ;
   RECT 0.2160 49.6200 0.2640 49.6680 ;
  END
 END rd[236]
 PIN wd[237]
  DIRECTION INPUT ;
  USE SIGNAL ;
  PORT
   LAYER M5 ;
   RECT 65.5080 0.2160 65.5560 0.2640 ;
  END
 END wd[237]
 PIN rd[237]
  DIRECTION OUTPUT ;
  USE SIGNAL ;
  PORT
   LAYER M4 ;
   RECT 0.2160 49.8120 0.2640 49.8600 ;
  END
 END rd[237]
 PIN wd[238]
  DIRECTION INPUT ;
  USE SIGNAL ;
  PORT
   LAYER M5 ;
   RECT 65.7480 0.2160 65.7960 0.2640 ;
  END
 END wd[238]
 PIN rd[238]
  DIRECTION OUTPUT ;
  USE SIGNAL ;
  PORT
   LAYER M4 ;
   RECT 0.2160 50.0040 0.2640 50.0520 ;
  END
 END rd[238]
 PIN wd[239]
  DIRECTION INPUT ;
  USE SIGNAL ;
  PORT
   LAYER M5 ;
   RECT 65.9880 0.2160 66.0360 0.2640 ;
  END
 END wd[239]
 PIN rd[239]
  DIRECTION OUTPUT ;
  USE SIGNAL ;
  PORT
   LAYER M4 ;
   RECT 0.2160 50.1960 0.2640 50.2440 ;
  END
 END rd[239]
 PIN wd[240]
  DIRECTION INPUT ;
  USE SIGNAL ;
  PORT
   LAYER M5 ;
   RECT 66.2280 0.2160 66.2760 0.2640 ;
  END
 END wd[240]
 PIN rd[240]
  DIRECTION OUTPUT ;
  USE SIGNAL ;
  PORT
   LAYER M4 ;
   RECT 0.2160 50.3880 0.2640 50.4360 ;
  END
 END rd[240]
 PIN wd[241]
  DIRECTION INPUT ;
  USE SIGNAL ;
  PORT
   LAYER M5 ;
   RECT 66.4680 0.2160 66.5160 0.2640 ;
  END
 END wd[241]
 PIN rd[241]
  DIRECTION OUTPUT ;
  USE SIGNAL ;
  PORT
   LAYER M4 ;
   RECT 0.2160 50.5800 0.2640 50.6280 ;
  END
 END rd[241]
 PIN wd[242]
  DIRECTION INPUT ;
  USE SIGNAL ;
  PORT
   LAYER M5 ;
   RECT 66.7080 0.2160 66.7560 0.2640 ;
  END
 END wd[242]
 PIN rd[242]
  DIRECTION OUTPUT ;
  USE SIGNAL ;
  PORT
   LAYER M4 ;
   RECT 0.2160 50.7720 0.2640 50.8200 ;
  END
 END rd[242]
 PIN wd[243]
  DIRECTION INPUT ;
  USE SIGNAL ;
  PORT
   LAYER M5 ;
   RECT 66.9480 0.2160 66.9960 0.2640 ;
  END
 END wd[243]
 PIN rd[243]
  DIRECTION OUTPUT ;
  USE SIGNAL ;
  PORT
   LAYER M4 ;
   RECT 0.2160 50.9640 0.2640 51.0120 ;
  END
 END rd[243]
 PIN wd[244]
  DIRECTION INPUT ;
  USE SIGNAL ;
  PORT
   LAYER M5 ;
   RECT 67.1880 0.2160 67.2360 0.2640 ;
  END
 END wd[244]
 PIN rd[244]
  DIRECTION OUTPUT ;
  USE SIGNAL ;
  PORT
   LAYER M4 ;
   RECT 0.2160 51.1560 0.2640 51.2040 ;
  END
 END rd[244]
 PIN wd[245]
  DIRECTION INPUT ;
  USE SIGNAL ;
  PORT
   LAYER M5 ;
   RECT 67.4280 0.2160 67.4760 0.2640 ;
  END
 END wd[245]
 PIN rd[245]
  DIRECTION OUTPUT ;
  USE SIGNAL ;
  PORT
   LAYER M4 ;
   RECT 0.2160 51.3480 0.2640 51.3960 ;
  END
 END rd[245]
 PIN wd[246]
  DIRECTION INPUT ;
  USE SIGNAL ;
  PORT
   LAYER M5 ;
   RECT 67.6680 0.2160 67.7160 0.2640 ;
  END
 END wd[246]
 PIN rd[246]
  DIRECTION OUTPUT ;
  USE SIGNAL ;
  PORT
   LAYER M4 ;
   RECT 0.2160 51.5400 0.2640 51.5880 ;
  END
 END rd[246]
 PIN wd[247]
  DIRECTION INPUT ;
  USE SIGNAL ;
  PORT
   LAYER M5 ;
   RECT 67.9080 0.2160 67.9560 0.2640 ;
  END
 END wd[247]
 PIN rd[247]
  DIRECTION OUTPUT ;
  USE SIGNAL ;
  PORT
   LAYER M4 ;
   RECT 0.2160 51.7320 0.2640 51.7800 ;
  END
 END rd[247]
 PIN wd[248]
  DIRECTION INPUT ;
  USE SIGNAL ;
  PORT
   LAYER M5 ;
   RECT 68.1480 0.2160 68.1960 0.2640 ;
  END
 END wd[248]
 PIN rd[248]
  DIRECTION OUTPUT ;
  USE SIGNAL ;
  PORT
   LAYER M4 ;
   RECT 0.2160 51.9240 0.2640 51.9720 ;
  END
 END rd[248]
 PIN wd[249]
  DIRECTION INPUT ;
  USE SIGNAL ;
  PORT
   LAYER M5 ;
   RECT 68.3880 0.2160 68.4360 0.2640 ;
  END
 END wd[249]
 PIN rd[249]
  DIRECTION OUTPUT ;
  USE SIGNAL ;
  PORT
   LAYER M4 ;
   RECT 0.2160 52.1160 0.2640 52.1640 ;
  END
 END rd[249]
 PIN wd[250]
  DIRECTION INPUT ;
  USE SIGNAL ;
  PORT
   LAYER M5 ;
   RECT 68.6280 0.2160 68.6760 0.2640 ;
  END
 END wd[250]
 PIN rd[250]
  DIRECTION OUTPUT ;
  USE SIGNAL ;
  PORT
   LAYER M4 ;
   RECT 0.2160 52.3080 0.2640 52.3560 ;
  END
 END rd[250]
 PIN wd[251]
  DIRECTION INPUT ;
  USE SIGNAL ;
  PORT
   LAYER M5 ;
   RECT 68.8680 0.2160 68.9160 0.2640 ;
  END
 END wd[251]
 PIN rd[251]
  DIRECTION OUTPUT ;
  USE SIGNAL ;
  PORT
   LAYER M4 ;
   RECT 0.2160 52.5000 0.2640 52.5480 ;
  END
 END rd[251]
 PIN wd[252]
  DIRECTION INPUT ;
  USE SIGNAL ;
  PORT
   LAYER M5 ;
   RECT 69.1080 0.2160 69.1560 0.2640 ;
  END
 END wd[252]
 PIN rd[252]
  DIRECTION OUTPUT ;
  USE SIGNAL ;
  PORT
   LAYER M4 ;
   RECT 0.2160 52.6920 0.2640 52.7400 ;
  END
 END rd[252]
 PIN wd[253]
  DIRECTION INPUT ;
  USE SIGNAL ;
  PORT
   LAYER M5 ;
   RECT 69.3480 0.2160 69.3960 0.2640 ;
  END
 END wd[253]
 PIN rd[253]
  DIRECTION OUTPUT ;
  USE SIGNAL ;
  PORT
   LAYER M4 ;
   RECT 0.2160 52.8840 0.2640 52.9320 ;
  END
 END rd[253]
 PIN wd[254]
  DIRECTION INPUT ;
  USE SIGNAL ;
  PORT
   LAYER M5 ;
   RECT 69.5880 0.2160 69.6360 0.2640 ;
  END
 END wd[254]
 PIN rd[254]
  DIRECTION OUTPUT ;
  USE SIGNAL ;
  PORT
   LAYER M4 ;
   RECT 0.2160 53.0760 0.2640 53.1240 ;
  END
 END rd[254]
 PIN wd[255]
  DIRECTION INPUT ;
  USE SIGNAL ;
  PORT
   LAYER M5 ;
   RECT 69.8280 0.2160 69.8760 0.2640 ;
  END
 END wd[255]
 PIN rd[255]
  DIRECTION OUTPUT ;
  USE SIGNAL ;
  PORT
   LAYER M4 ;
   RECT 0.2160 53.2680 0.2640 53.3160 ;
  END
 END rd[255]
 PIN wd[256]
  DIRECTION INPUT ;
  USE SIGNAL ;
  PORT
   LAYER M5 ;
   RECT 150.9480 0.2160 150.9960 0.2640 ;
  END
 END wd[256]
 PIN rd[256]
  DIRECTION OUTPUT ;
  USE SIGNAL ;
  PORT
   LAYER M4 ;
   RECT 241.6560 4.3080 241.7040 4.3560 ;
  END
 END rd[256]
 PIN wd[257]
  DIRECTION INPUT ;
  USE SIGNAL ;
  PORT
   LAYER M5 ;
   RECT 151.1880 0.2160 151.2360 0.2640 ;
  END
 END wd[257]
 PIN rd[257]
  DIRECTION OUTPUT ;
  USE SIGNAL ;
  PORT
   LAYER M4 ;
   RECT 241.6560 4.5000 241.7040 4.5480 ;
  END
 END rd[257]
 PIN wd[258]
  DIRECTION INPUT ;
  USE SIGNAL ;
  PORT
   LAYER M5 ;
   RECT 151.4280 0.2160 151.4760 0.2640 ;
  END
 END wd[258]
 PIN rd[258]
  DIRECTION OUTPUT ;
  USE SIGNAL ;
  PORT
   LAYER M4 ;
   RECT 241.6560 4.6920 241.7040 4.7400 ;
  END
 END rd[258]
 PIN wd[259]
  DIRECTION INPUT ;
  USE SIGNAL ;
  PORT
   LAYER M5 ;
   RECT 151.6680 0.2160 151.7160 0.2640 ;
  END
 END wd[259]
 PIN rd[259]
  DIRECTION OUTPUT ;
  USE SIGNAL ;
  PORT
   LAYER M4 ;
   RECT 241.6560 4.8840 241.7040 4.9320 ;
  END
 END rd[259]
 PIN wd[260]
  DIRECTION INPUT ;
  USE SIGNAL ;
  PORT
   LAYER M5 ;
   RECT 151.9080 0.2160 151.9560 0.2640 ;
  END
 END wd[260]
 PIN rd[260]
  DIRECTION OUTPUT ;
  USE SIGNAL ;
  PORT
   LAYER M4 ;
   RECT 241.6560 5.0760 241.7040 5.1240 ;
  END
 END rd[260]
 PIN wd[261]
  DIRECTION INPUT ;
  USE SIGNAL ;
  PORT
   LAYER M5 ;
   RECT 152.1480 0.2160 152.1960 0.2640 ;
  END
 END wd[261]
 PIN rd[261]
  DIRECTION OUTPUT ;
  USE SIGNAL ;
  PORT
   LAYER M4 ;
   RECT 241.6560 5.2680 241.7040 5.3160 ;
  END
 END rd[261]
 PIN wd[262]
  DIRECTION INPUT ;
  USE SIGNAL ;
  PORT
   LAYER M5 ;
   RECT 152.3880 0.2160 152.4360 0.2640 ;
  END
 END wd[262]
 PIN rd[262]
  DIRECTION OUTPUT ;
  USE SIGNAL ;
  PORT
   LAYER M4 ;
   RECT 241.6560 5.4600 241.7040 5.5080 ;
  END
 END rd[262]
 PIN wd[263]
  DIRECTION INPUT ;
  USE SIGNAL ;
  PORT
   LAYER M5 ;
   RECT 152.6280 0.2160 152.6760 0.2640 ;
  END
 END wd[263]
 PIN rd[263]
  DIRECTION OUTPUT ;
  USE SIGNAL ;
  PORT
   LAYER M4 ;
   RECT 241.6560 5.6520 241.7040 5.7000 ;
  END
 END rd[263]
 PIN wd[264]
  DIRECTION INPUT ;
  USE SIGNAL ;
  PORT
   LAYER M5 ;
   RECT 152.8680 0.2160 152.9160 0.2640 ;
  END
 END wd[264]
 PIN rd[264]
  DIRECTION OUTPUT ;
  USE SIGNAL ;
  PORT
   LAYER M4 ;
   RECT 241.6560 5.8440 241.7040 5.8920 ;
  END
 END rd[264]
 PIN wd[265]
  DIRECTION INPUT ;
  USE SIGNAL ;
  PORT
   LAYER M5 ;
   RECT 153.1080 0.2160 153.1560 0.2640 ;
  END
 END wd[265]
 PIN rd[265]
  DIRECTION OUTPUT ;
  USE SIGNAL ;
  PORT
   LAYER M4 ;
   RECT 241.6560 6.0360 241.7040 6.0840 ;
  END
 END rd[265]
 PIN wd[266]
  DIRECTION INPUT ;
  USE SIGNAL ;
  PORT
   LAYER M5 ;
   RECT 153.3480 0.2160 153.3960 0.2640 ;
  END
 END wd[266]
 PIN rd[266]
  DIRECTION OUTPUT ;
  USE SIGNAL ;
  PORT
   LAYER M4 ;
   RECT 241.6560 6.2280 241.7040 6.2760 ;
  END
 END rd[266]
 PIN wd[267]
  DIRECTION INPUT ;
  USE SIGNAL ;
  PORT
   LAYER M5 ;
   RECT 153.5880 0.2160 153.6360 0.2640 ;
  END
 END wd[267]
 PIN rd[267]
  DIRECTION OUTPUT ;
  USE SIGNAL ;
  PORT
   LAYER M4 ;
   RECT 241.6560 6.4200 241.7040 6.4680 ;
  END
 END rd[267]
 PIN wd[268]
  DIRECTION INPUT ;
  USE SIGNAL ;
  PORT
   LAYER M5 ;
   RECT 153.8280 0.2160 153.8760 0.2640 ;
  END
 END wd[268]
 PIN rd[268]
  DIRECTION OUTPUT ;
  USE SIGNAL ;
  PORT
   LAYER M4 ;
   RECT 241.6560 6.6120 241.7040 6.6600 ;
  END
 END rd[268]
 PIN wd[269]
  DIRECTION INPUT ;
  USE SIGNAL ;
  PORT
   LAYER M5 ;
   RECT 154.0680 0.2160 154.1160 0.2640 ;
  END
 END wd[269]
 PIN rd[269]
  DIRECTION OUTPUT ;
  USE SIGNAL ;
  PORT
   LAYER M4 ;
   RECT 241.6560 6.8040 241.7040 6.8520 ;
  END
 END rd[269]
 PIN wd[270]
  DIRECTION INPUT ;
  USE SIGNAL ;
  PORT
   LAYER M5 ;
   RECT 154.3080 0.2160 154.3560 0.2640 ;
  END
 END wd[270]
 PIN rd[270]
  DIRECTION OUTPUT ;
  USE SIGNAL ;
  PORT
   LAYER M4 ;
   RECT 241.6560 6.9960 241.7040 7.0440 ;
  END
 END rd[270]
 PIN wd[271]
  DIRECTION INPUT ;
  USE SIGNAL ;
  PORT
   LAYER M5 ;
   RECT 154.5480 0.2160 154.5960 0.2640 ;
  END
 END wd[271]
 PIN rd[271]
  DIRECTION OUTPUT ;
  USE SIGNAL ;
  PORT
   LAYER M4 ;
   RECT 241.6560 7.1880 241.7040 7.2360 ;
  END
 END rd[271]
 PIN wd[272]
  DIRECTION INPUT ;
  USE SIGNAL ;
  PORT
   LAYER M5 ;
   RECT 154.7880 0.2160 154.8360 0.2640 ;
  END
 END wd[272]
 PIN rd[272]
  DIRECTION OUTPUT ;
  USE SIGNAL ;
  PORT
   LAYER M4 ;
   RECT 241.6560 7.3800 241.7040 7.4280 ;
  END
 END rd[272]
 PIN wd[273]
  DIRECTION INPUT ;
  USE SIGNAL ;
  PORT
   LAYER M5 ;
   RECT 155.0280 0.2160 155.0760 0.2640 ;
  END
 END wd[273]
 PIN rd[273]
  DIRECTION OUTPUT ;
  USE SIGNAL ;
  PORT
   LAYER M4 ;
   RECT 241.6560 7.5720 241.7040 7.6200 ;
  END
 END rd[273]
 PIN wd[274]
  DIRECTION INPUT ;
  USE SIGNAL ;
  PORT
   LAYER M5 ;
   RECT 155.2680 0.2160 155.3160 0.2640 ;
  END
 END wd[274]
 PIN rd[274]
  DIRECTION OUTPUT ;
  USE SIGNAL ;
  PORT
   LAYER M4 ;
   RECT 241.6560 7.7640 241.7040 7.8120 ;
  END
 END rd[274]
 PIN wd[275]
  DIRECTION INPUT ;
  USE SIGNAL ;
  PORT
   LAYER M5 ;
   RECT 155.5080 0.2160 155.5560 0.2640 ;
  END
 END wd[275]
 PIN rd[275]
  DIRECTION OUTPUT ;
  USE SIGNAL ;
  PORT
   LAYER M4 ;
   RECT 241.6560 7.9560 241.7040 8.0040 ;
  END
 END rd[275]
 PIN wd[276]
  DIRECTION INPUT ;
  USE SIGNAL ;
  PORT
   LAYER M5 ;
   RECT 155.7480 0.2160 155.7960 0.2640 ;
  END
 END wd[276]
 PIN rd[276]
  DIRECTION OUTPUT ;
  USE SIGNAL ;
  PORT
   LAYER M4 ;
   RECT 241.6560 8.1480 241.7040 8.1960 ;
  END
 END rd[276]
 PIN wd[277]
  DIRECTION INPUT ;
  USE SIGNAL ;
  PORT
   LAYER M5 ;
   RECT 155.9880 0.2160 156.0360 0.2640 ;
  END
 END wd[277]
 PIN rd[277]
  DIRECTION OUTPUT ;
  USE SIGNAL ;
  PORT
   LAYER M4 ;
   RECT 241.6560 8.3400 241.7040 8.3880 ;
  END
 END rd[277]
 PIN wd[278]
  DIRECTION INPUT ;
  USE SIGNAL ;
  PORT
   LAYER M5 ;
   RECT 156.2280 0.2160 156.2760 0.2640 ;
  END
 END wd[278]
 PIN rd[278]
  DIRECTION OUTPUT ;
  USE SIGNAL ;
  PORT
   LAYER M4 ;
   RECT 241.6560 8.5320 241.7040 8.5800 ;
  END
 END rd[278]
 PIN wd[279]
  DIRECTION INPUT ;
  USE SIGNAL ;
  PORT
   LAYER M5 ;
   RECT 156.4680 0.2160 156.5160 0.2640 ;
  END
 END wd[279]
 PIN rd[279]
  DIRECTION OUTPUT ;
  USE SIGNAL ;
  PORT
   LAYER M4 ;
   RECT 241.6560 8.7240 241.7040 8.7720 ;
  END
 END rd[279]
 PIN wd[280]
  DIRECTION INPUT ;
  USE SIGNAL ;
  PORT
   LAYER M5 ;
   RECT 156.7080 0.2160 156.7560 0.2640 ;
  END
 END wd[280]
 PIN rd[280]
  DIRECTION OUTPUT ;
  USE SIGNAL ;
  PORT
   LAYER M4 ;
   RECT 241.6560 8.9160 241.7040 8.9640 ;
  END
 END rd[280]
 PIN wd[281]
  DIRECTION INPUT ;
  USE SIGNAL ;
  PORT
   LAYER M5 ;
   RECT 156.9480 0.2160 156.9960 0.2640 ;
  END
 END wd[281]
 PIN rd[281]
  DIRECTION OUTPUT ;
  USE SIGNAL ;
  PORT
   LAYER M4 ;
   RECT 241.6560 9.1080 241.7040 9.1560 ;
  END
 END rd[281]
 PIN wd[282]
  DIRECTION INPUT ;
  USE SIGNAL ;
  PORT
   LAYER M5 ;
   RECT 157.1880 0.2160 157.2360 0.2640 ;
  END
 END wd[282]
 PIN rd[282]
  DIRECTION OUTPUT ;
  USE SIGNAL ;
  PORT
   LAYER M4 ;
   RECT 241.6560 9.3000 241.7040 9.3480 ;
  END
 END rd[282]
 PIN wd[283]
  DIRECTION INPUT ;
  USE SIGNAL ;
  PORT
   LAYER M5 ;
   RECT 157.4280 0.2160 157.4760 0.2640 ;
  END
 END wd[283]
 PIN rd[283]
  DIRECTION OUTPUT ;
  USE SIGNAL ;
  PORT
   LAYER M4 ;
   RECT 241.6560 9.4920 241.7040 9.5400 ;
  END
 END rd[283]
 PIN wd[284]
  DIRECTION INPUT ;
  USE SIGNAL ;
  PORT
   LAYER M5 ;
   RECT 157.6680 0.2160 157.7160 0.2640 ;
  END
 END wd[284]
 PIN rd[284]
  DIRECTION OUTPUT ;
  USE SIGNAL ;
  PORT
   LAYER M4 ;
   RECT 241.6560 9.6840 241.7040 9.7320 ;
  END
 END rd[284]
 PIN wd[285]
  DIRECTION INPUT ;
  USE SIGNAL ;
  PORT
   LAYER M5 ;
   RECT 157.9080 0.2160 157.9560 0.2640 ;
  END
 END wd[285]
 PIN rd[285]
  DIRECTION OUTPUT ;
  USE SIGNAL ;
  PORT
   LAYER M4 ;
   RECT 241.6560 9.8760 241.7040 9.9240 ;
  END
 END rd[285]
 PIN wd[286]
  DIRECTION INPUT ;
  USE SIGNAL ;
  PORT
   LAYER M5 ;
   RECT 158.1480 0.2160 158.1960 0.2640 ;
  END
 END wd[286]
 PIN rd[286]
  DIRECTION OUTPUT ;
  USE SIGNAL ;
  PORT
   LAYER M4 ;
   RECT 241.6560 10.0680 241.7040 10.1160 ;
  END
 END rd[286]
 PIN wd[287]
  DIRECTION INPUT ;
  USE SIGNAL ;
  PORT
   LAYER M5 ;
   RECT 158.3880 0.2160 158.4360 0.2640 ;
  END
 END wd[287]
 PIN rd[287]
  DIRECTION OUTPUT ;
  USE SIGNAL ;
  PORT
   LAYER M4 ;
   RECT 241.6560 10.2600 241.7040 10.3080 ;
  END
 END rd[287]
 PIN wd[288]
  DIRECTION INPUT ;
  USE SIGNAL ;
  PORT
   LAYER M5 ;
   RECT 158.6280 0.2160 158.6760 0.2640 ;
  END
 END wd[288]
 PIN rd[288]
  DIRECTION OUTPUT ;
  USE SIGNAL ;
  PORT
   LAYER M4 ;
   RECT 241.6560 10.4520 241.7040 10.5000 ;
  END
 END rd[288]
 PIN wd[289]
  DIRECTION INPUT ;
  USE SIGNAL ;
  PORT
   LAYER M5 ;
   RECT 158.8680 0.2160 158.9160 0.2640 ;
  END
 END wd[289]
 PIN rd[289]
  DIRECTION OUTPUT ;
  USE SIGNAL ;
  PORT
   LAYER M4 ;
   RECT 241.6560 10.6440 241.7040 10.6920 ;
  END
 END rd[289]
 PIN wd[290]
  DIRECTION INPUT ;
  USE SIGNAL ;
  PORT
   LAYER M5 ;
   RECT 159.1080 0.2160 159.1560 0.2640 ;
  END
 END wd[290]
 PIN rd[290]
  DIRECTION OUTPUT ;
  USE SIGNAL ;
  PORT
   LAYER M4 ;
   RECT 241.6560 10.8360 241.7040 10.8840 ;
  END
 END rd[290]
 PIN wd[291]
  DIRECTION INPUT ;
  USE SIGNAL ;
  PORT
   LAYER M5 ;
   RECT 159.3480 0.2160 159.3960 0.2640 ;
  END
 END wd[291]
 PIN rd[291]
  DIRECTION OUTPUT ;
  USE SIGNAL ;
  PORT
   LAYER M4 ;
   RECT 241.6560 11.0280 241.7040 11.0760 ;
  END
 END rd[291]
 PIN wd[292]
  DIRECTION INPUT ;
  USE SIGNAL ;
  PORT
   LAYER M5 ;
   RECT 159.5880 0.2160 159.6360 0.2640 ;
  END
 END wd[292]
 PIN rd[292]
  DIRECTION OUTPUT ;
  USE SIGNAL ;
  PORT
   LAYER M4 ;
   RECT 241.6560 11.2200 241.7040 11.2680 ;
  END
 END rd[292]
 PIN wd[293]
  DIRECTION INPUT ;
  USE SIGNAL ;
  PORT
   LAYER M5 ;
   RECT 159.8280 0.2160 159.8760 0.2640 ;
  END
 END wd[293]
 PIN rd[293]
  DIRECTION OUTPUT ;
  USE SIGNAL ;
  PORT
   LAYER M4 ;
   RECT 241.6560 11.4120 241.7040 11.4600 ;
  END
 END rd[293]
 PIN wd[294]
  DIRECTION INPUT ;
  USE SIGNAL ;
  PORT
   LAYER M5 ;
   RECT 160.0680 0.2160 160.1160 0.2640 ;
  END
 END wd[294]
 PIN rd[294]
  DIRECTION OUTPUT ;
  USE SIGNAL ;
  PORT
   LAYER M4 ;
   RECT 241.6560 11.6040 241.7040 11.6520 ;
  END
 END rd[294]
 PIN wd[295]
  DIRECTION INPUT ;
  USE SIGNAL ;
  PORT
   LAYER M5 ;
   RECT 160.3080 0.2160 160.3560 0.2640 ;
  END
 END wd[295]
 PIN rd[295]
  DIRECTION OUTPUT ;
  USE SIGNAL ;
  PORT
   LAYER M4 ;
   RECT 241.6560 11.7960 241.7040 11.8440 ;
  END
 END rd[295]
 PIN wd[296]
  DIRECTION INPUT ;
  USE SIGNAL ;
  PORT
   LAYER M5 ;
   RECT 160.5480 0.2160 160.5960 0.2640 ;
  END
 END wd[296]
 PIN rd[296]
  DIRECTION OUTPUT ;
  USE SIGNAL ;
  PORT
   LAYER M4 ;
   RECT 241.6560 11.9880 241.7040 12.0360 ;
  END
 END rd[296]
 PIN wd[297]
  DIRECTION INPUT ;
  USE SIGNAL ;
  PORT
   LAYER M5 ;
   RECT 160.7880 0.2160 160.8360 0.2640 ;
  END
 END wd[297]
 PIN rd[297]
  DIRECTION OUTPUT ;
  USE SIGNAL ;
  PORT
   LAYER M4 ;
   RECT 241.6560 12.1800 241.7040 12.2280 ;
  END
 END rd[297]
 PIN wd[298]
  DIRECTION INPUT ;
  USE SIGNAL ;
  PORT
   LAYER M5 ;
   RECT 161.0280 0.2160 161.0760 0.2640 ;
  END
 END wd[298]
 PIN rd[298]
  DIRECTION OUTPUT ;
  USE SIGNAL ;
  PORT
   LAYER M4 ;
   RECT 241.6560 12.3720 241.7040 12.4200 ;
  END
 END rd[298]
 PIN wd[299]
  DIRECTION INPUT ;
  USE SIGNAL ;
  PORT
   LAYER M5 ;
   RECT 161.2680 0.2160 161.3160 0.2640 ;
  END
 END wd[299]
 PIN rd[299]
  DIRECTION OUTPUT ;
  USE SIGNAL ;
  PORT
   LAYER M4 ;
   RECT 241.6560 12.5640 241.7040 12.6120 ;
  END
 END rd[299]
 PIN wd[300]
  DIRECTION INPUT ;
  USE SIGNAL ;
  PORT
   LAYER M5 ;
   RECT 161.5080 0.2160 161.5560 0.2640 ;
  END
 END wd[300]
 PIN rd[300]
  DIRECTION OUTPUT ;
  USE SIGNAL ;
  PORT
   LAYER M4 ;
   RECT 241.6560 12.7560 241.7040 12.8040 ;
  END
 END rd[300]
 PIN wd[301]
  DIRECTION INPUT ;
  USE SIGNAL ;
  PORT
   LAYER M5 ;
   RECT 161.7480 0.2160 161.7960 0.2640 ;
  END
 END wd[301]
 PIN rd[301]
  DIRECTION OUTPUT ;
  USE SIGNAL ;
  PORT
   LAYER M4 ;
   RECT 241.6560 12.9480 241.7040 12.9960 ;
  END
 END rd[301]
 PIN wd[302]
  DIRECTION INPUT ;
  USE SIGNAL ;
  PORT
   LAYER M5 ;
   RECT 161.9880 0.2160 162.0360 0.2640 ;
  END
 END wd[302]
 PIN rd[302]
  DIRECTION OUTPUT ;
  USE SIGNAL ;
  PORT
   LAYER M4 ;
   RECT 241.6560 13.1400 241.7040 13.1880 ;
  END
 END rd[302]
 PIN wd[303]
  DIRECTION INPUT ;
  USE SIGNAL ;
  PORT
   LAYER M5 ;
   RECT 162.2280 0.2160 162.2760 0.2640 ;
  END
 END wd[303]
 PIN rd[303]
  DIRECTION OUTPUT ;
  USE SIGNAL ;
  PORT
   LAYER M4 ;
   RECT 241.6560 13.3320 241.7040 13.3800 ;
  END
 END rd[303]
 PIN wd[304]
  DIRECTION INPUT ;
  USE SIGNAL ;
  PORT
   LAYER M5 ;
   RECT 162.4680 0.2160 162.5160 0.2640 ;
  END
 END wd[304]
 PIN rd[304]
  DIRECTION OUTPUT ;
  USE SIGNAL ;
  PORT
   LAYER M4 ;
   RECT 241.6560 13.5240 241.7040 13.5720 ;
  END
 END rd[304]
 PIN wd[305]
  DIRECTION INPUT ;
  USE SIGNAL ;
  PORT
   LAYER M5 ;
   RECT 162.7080 0.2160 162.7560 0.2640 ;
  END
 END wd[305]
 PIN rd[305]
  DIRECTION OUTPUT ;
  USE SIGNAL ;
  PORT
   LAYER M4 ;
   RECT 241.6560 13.7160 241.7040 13.7640 ;
  END
 END rd[305]
 PIN wd[306]
  DIRECTION INPUT ;
  USE SIGNAL ;
  PORT
   LAYER M5 ;
   RECT 162.9480 0.2160 162.9960 0.2640 ;
  END
 END wd[306]
 PIN rd[306]
  DIRECTION OUTPUT ;
  USE SIGNAL ;
  PORT
   LAYER M4 ;
   RECT 241.6560 13.9080 241.7040 13.9560 ;
  END
 END rd[306]
 PIN wd[307]
  DIRECTION INPUT ;
  USE SIGNAL ;
  PORT
   LAYER M5 ;
   RECT 163.1880 0.2160 163.2360 0.2640 ;
  END
 END wd[307]
 PIN rd[307]
  DIRECTION OUTPUT ;
  USE SIGNAL ;
  PORT
   LAYER M4 ;
   RECT 241.6560 14.1000 241.7040 14.1480 ;
  END
 END rd[307]
 PIN wd[308]
  DIRECTION INPUT ;
  USE SIGNAL ;
  PORT
   LAYER M5 ;
   RECT 163.4280 0.2160 163.4760 0.2640 ;
  END
 END wd[308]
 PIN rd[308]
  DIRECTION OUTPUT ;
  USE SIGNAL ;
  PORT
   LAYER M4 ;
   RECT 241.6560 14.2920 241.7040 14.3400 ;
  END
 END rd[308]
 PIN wd[309]
  DIRECTION INPUT ;
  USE SIGNAL ;
  PORT
   LAYER M5 ;
   RECT 163.6680 0.2160 163.7160 0.2640 ;
  END
 END wd[309]
 PIN rd[309]
  DIRECTION OUTPUT ;
  USE SIGNAL ;
  PORT
   LAYER M4 ;
   RECT 241.6560 14.4840 241.7040 14.5320 ;
  END
 END rd[309]
 PIN wd[310]
  DIRECTION INPUT ;
  USE SIGNAL ;
  PORT
   LAYER M5 ;
   RECT 163.9080 0.2160 163.9560 0.2640 ;
  END
 END wd[310]
 PIN rd[310]
  DIRECTION OUTPUT ;
  USE SIGNAL ;
  PORT
   LAYER M4 ;
   RECT 241.6560 14.6760 241.7040 14.7240 ;
  END
 END rd[310]
 PIN wd[311]
  DIRECTION INPUT ;
  USE SIGNAL ;
  PORT
   LAYER M5 ;
   RECT 164.1480 0.2160 164.1960 0.2640 ;
  END
 END wd[311]
 PIN rd[311]
  DIRECTION OUTPUT ;
  USE SIGNAL ;
  PORT
   LAYER M4 ;
   RECT 241.6560 14.8680 241.7040 14.9160 ;
  END
 END rd[311]
 PIN wd[312]
  DIRECTION INPUT ;
  USE SIGNAL ;
  PORT
   LAYER M5 ;
   RECT 164.3880 0.2160 164.4360 0.2640 ;
  END
 END wd[312]
 PIN rd[312]
  DIRECTION OUTPUT ;
  USE SIGNAL ;
  PORT
   LAYER M4 ;
   RECT 241.6560 15.0600 241.7040 15.1080 ;
  END
 END rd[312]
 PIN wd[313]
  DIRECTION INPUT ;
  USE SIGNAL ;
  PORT
   LAYER M5 ;
   RECT 164.6280 0.2160 164.6760 0.2640 ;
  END
 END wd[313]
 PIN rd[313]
  DIRECTION OUTPUT ;
  USE SIGNAL ;
  PORT
   LAYER M4 ;
   RECT 241.6560 15.2520 241.7040 15.3000 ;
  END
 END rd[313]
 PIN wd[314]
  DIRECTION INPUT ;
  USE SIGNAL ;
  PORT
   LAYER M5 ;
   RECT 164.8680 0.2160 164.9160 0.2640 ;
  END
 END wd[314]
 PIN rd[314]
  DIRECTION OUTPUT ;
  USE SIGNAL ;
  PORT
   LAYER M4 ;
   RECT 241.6560 15.4440 241.7040 15.4920 ;
  END
 END rd[314]
 PIN wd[315]
  DIRECTION INPUT ;
  USE SIGNAL ;
  PORT
   LAYER M5 ;
   RECT 165.1080 0.2160 165.1560 0.2640 ;
  END
 END wd[315]
 PIN rd[315]
  DIRECTION OUTPUT ;
  USE SIGNAL ;
  PORT
   LAYER M4 ;
   RECT 241.6560 15.6360 241.7040 15.6840 ;
  END
 END rd[315]
 PIN wd[316]
  DIRECTION INPUT ;
  USE SIGNAL ;
  PORT
   LAYER M5 ;
   RECT 165.3480 0.2160 165.3960 0.2640 ;
  END
 END wd[316]
 PIN rd[316]
  DIRECTION OUTPUT ;
  USE SIGNAL ;
  PORT
   LAYER M4 ;
   RECT 241.6560 15.8280 241.7040 15.8760 ;
  END
 END rd[316]
 PIN wd[317]
  DIRECTION INPUT ;
  USE SIGNAL ;
  PORT
   LAYER M5 ;
   RECT 165.5880 0.2160 165.6360 0.2640 ;
  END
 END wd[317]
 PIN rd[317]
  DIRECTION OUTPUT ;
  USE SIGNAL ;
  PORT
   LAYER M4 ;
   RECT 241.6560 16.0200 241.7040 16.0680 ;
  END
 END rd[317]
 PIN wd[318]
  DIRECTION INPUT ;
  USE SIGNAL ;
  PORT
   LAYER M5 ;
   RECT 165.8280 0.2160 165.8760 0.2640 ;
  END
 END wd[318]
 PIN rd[318]
  DIRECTION OUTPUT ;
  USE SIGNAL ;
  PORT
   LAYER M4 ;
   RECT 241.6560 16.2120 241.7040 16.2600 ;
  END
 END rd[318]
 PIN wd[319]
  DIRECTION INPUT ;
  USE SIGNAL ;
  PORT
   LAYER M5 ;
   RECT 166.0680 0.2160 166.1160 0.2640 ;
  END
 END wd[319]
 PIN rd[319]
  DIRECTION OUTPUT ;
  USE SIGNAL ;
  PORT
   LAYER M4 ;
   RECT 241.6560 16.4040 241.7040 16.4520 ;
  END
 END rd[319]
 PIN wd[320]
  DIRECTION INPUT ;
  USE SIGNAL ;
  PORT
   LAYER M5 ;
   RECT 166.3080 0.2160 166.3560 0.2640 ;
  END
 END wd[320]
 PIN rd[320]
  DIRECTION OUTPUT ;
  USE SIGNAL ;
  PORT
   LAYER M4 ;
   RECT 241.6560 16.5960 241.7040 16.6440 ;
  END
 END rd[320]
 PIN wd[321]
  DIRECTION INPUT ;
  USE SIGNAL ;
  PORT
   LAYER M5 ;
   RECT 166.5480 0.2160 166.5960 0.2640 ;
  END
 END wd[321]
 PIN rd[321]
  DIRECTION OUTPUT ;
  USE SIGNAL ;
  PORT
   LAYER M4 ;
   RECT 241.6560 16.7880 241.7040 16.8360 ;
  END
 END rd[321]
 PIN wd[322]
  DIRECTION INPUT ;
  USE SIGNAL ;
  PORT
   LAYER M5 ;
   RECT 166.7880 0.2160 166.8360 0.2640 ;
  END
 END wd[322]
 PIN rd[322]
  DIRECTION OUTPUT ;
  USE SIGNAL ;
  PORT
   LAYER M4 ;
   RECT 241.6560 16.9800 241.7040 17.0280 ;
  END
 END rd[322]
 PIN wd[323]
  DIRECTION INPUT ;
  USE SIGNAL ;
  PORT
   LAYER M5 ;
   RECT 167.0280 0.2160 167.0760 0.2640 ;
  END
 END wd[323]
 PIN rd[323]
  DIRECTION OUTPUT ;
  USE SIGNAL ;
  PORT
   LAYER M4 ;
   RECT 241.6560 17.1720 241.7040 17.2200 ;
  END
 END rd[323]
 PIN wd[324]
  DIRECTION INPUT ;
  USE SIGNAL ;
  PORT
   LAYER M5 ;
   RECT 167.2680 0.2160 167.3160 0.2640 ;
  END
 END wd[324]
 PIN rd[324]
  DIRECTION OUTPUT ;
  USE SIGNAL ;
  PORT
   LAYER M4 ;
   RECT 241.6560 17.3640 241.7040 17.4120 ;
  END
 END rd[324]
 PIN wd[325]
  DIRECTION INPUT ;
  USE SIGNAL ;
  PORT
   LAYER M5 ;
   RECT 167.5080 0.2160 167.5560 0.2640 ;
  END
 END wd[325]
 PIN rd[325]
  DIRECTION OUTPUT ;
  USE SIGNAL ;
  PORT
   LAYER M4 ;
   RECT 241.6560 17.5560 241.7040 17.6040 ;
  END
 END rd[325]
 PIN wd[326]
  DIRECTION INPUT ;
  USE SIGNAL ;
  PORT
   LAYER M5 ;
   RECT 167.7480 0.2160 167.7960 0.2640 ;
  END
 END wd[326]
 PIN rd[326]
  DIRECTION OUTPUT ;
  USE SIGNAL ;
  PORT
   LAYER M4 ;
   RECT 241.6560 17.7480 241.7040 17.7960 ;
  END
 END rd[326]
 PIN wd[327]
  DIRECTION INPUT ;
  USE SIGNAL ;
  PORT
   LAYER M5 ;
   RECT 167.9880 0.2160 168.0360 0.2640 ;
  END
 END wd[327]
 PIN rd[327]
  DIRECTION OUTPUT ;
  USE SIGNAL ;
  PORT
   LAYER M4 ;
   RECT 241.6560 17.9400 241.7040 17.9880 ;
  END
 END rd[327]
 PIN wd[328]
  DIRECTION INPUT ;
  USE SIGNAL ;
  PORT
   LAYER M5 ;
   RECT 168.2280 0.2160 168.2760 0.2640 ;
  END
 END wd[328]
 PIN rd[328]
  DIRECTION OUTPUT ;
  USE SIGNAL ;
  PORT
   LAYER M4 ;
   RECT 241.6560 18.1320 241.7040 18.1800 ;
  END
 END rd[328]
 PIN wd[329]
  DIRECTION INPUT ;
  USE SIGNAL ;
  PORT
   LAYER M5 ;
   RECT 168.4680 0.2160 168.5160 0.2640 ;
  END
 END wd[329]
 PIN rd[329]
  DIRECTION OUTPUT ;
  USE SIGNAL ;
  PORT
   LAYER M4 ;
   RECT 241.6560 18.3240 241.7040 18.3720 ;
  END
 END rd[329]
 PIN wd[330]
  DIRECTION INPUT ;
  USE SIGNAL ;
  PORT
   LAYER M5 ;
   RECT 168.7080 0.2160 168.7560 0.2640 ;
  END
 END wd[330]
 PIN rd[330]
  DIRECTION OUTPUT ;
  USE SIGNAL ;
  PORT
   LAYER M4 ;
   RECT 241.6560 18.5160 241.7040 18.5640 ;
  END
 END rd[330]
 PIN wd[331]
  DIRECTION INPUT ;
  USE SIGNAL ;
  PORT
   LAYER M5 ;
   RECT 168.9480 0.2160 168.9960 0.2640 ;
  END
 END wd[331]
 PIN rd[331]
  DIRECTION OUTPUT ;
  USE SIGNAL ;
  PORT
   LAYER M4 ;
   RECT 241.6560 18.7080 241.7040 18.7560 ;
  END
 END rd[331]
 PIN wd[332]
  DIRECTION INPUT ;
  USE SIGNAL ;
  PORT
   LAYER M5 ;
   RECT 169.1880 0.2160 169.2360 0.2640 ;
  END
 END wd[332]
 PIN rd[332]
  DIRECTION OUTPUT ;
  USE SIGNAL ;
  PORT
   LAYER M4 ;
   RECT 241.6560 18.9000 241.7040 18.9480 ;
  END
 END rd[332]
 PIN wd[333]
  DIRECTION INPUT ;
  USE SIGNAL ;
  PORT
   LAYER M5 ;
   RECT 169.4280 0.2160 169.4760 0.2640 ;
  END
 END wd[333]
 PIN rd[333]
  DIRECTION OUTPUT ;
  USE SIGNAL ;
  PORT
   LAYER M4 ;
   RECT 241.6560 19.0920 241.7040 19.1400 ;
  END
 END rd[333]
 PIN wd[334]
  DIRECTION INPUT ;
  USE SIGNAL ;
  PORT
   LAYER M5 ;
   RECT 169.6680 0.2160 169.7160 0.2640 ;
  END
 END wd[334]
 PIN rd[334]
  DIRECTION OUTPUT ;
  USE SIGNAL ;
  PORT
   LAYER M4 ;
   RECT 241.6560 19.2840 241.7040 19.3320 ;
  END
 END rd[334]
 PIN wd[335]
  DIRECTION INPUT ;
  USE SIGNAL ;
  PORT
   LAYER M5 ;
   RECT 169.9080 0.2160 169.9560 0.2640 ;
  END
 END wd[335]
 PIN rd[335]
  DIRECTION OUTPUT ;
  USE SIGNAL ;
  PORT
   LAYER M4 ;
   RECT 241.6560 19.4760 241.7040 19.5240 ;
  END
 END rd[335]
 PIN wd[336]
  DIRECTION INPUT ;
  USE SIGNAL ;
  PORT
   LAYER M5 ;
   RECT 170.1480 0.2160 170.1960 0.2640 ;
  END
 END wd[336]
 PIN rd[336]
  DIRECTION OUTPUT ;
  USE SIGNAL ;
  PORT
   LAYER M4 ;
   RECT 241.6560 19.6680 241.7040 19.7160 ;
  END
 END rd[336]
 PIN wd[337]
  DIRECTION INPUT ;
  USE SIGNAL ;
  PORT
   LAYER M5 ;
   RECT 170.3880 0.2160 170.4360 0.2640 ;
  END
 END wd[337]
 PIN rd[337]
  DIRECTION OUTPUT ;
  USE SIGNAL ;
  PORT
   LAYER M4 ;
   RECT 241.6560 19.8600 241.7040 19.9080 ;
  END
 END rd[337]
 PIN wd[338]
  DIRECTION INPUT ;
  USE SIGNAL ;
  PORT
   LAYER M5 ;
   RECT 170.6280 0.2160 170.6760 0.2640 ;
  END
 END wd[338]
 PIN rd[338]
  DIRECTION OUTPUT ;
  USE SIGNAL ;
  PORT
   LAYER M4 ;
   RECT 241.6560 20.0520 241.7040 20.1000 ;
  END
 END rd[338]
 PIN wd[339]
  DIRECTION INPUT ;
  USE SIGNAL ;
  PORT
   LAYER M5 ;
   RECT 170.8680 0.2160 170.9160 0.2640 ;
  END
 END wd[339]
 PIN rd[339]
  DIRECTION OUTPUT ;
  USE SIGNAL ;
  PORT
   LAYER M4 ;
   RECT 241.6560 20.2440 241.7040 20.2920 ;
  END
 END rd[339]
 PIN wd[340]
  DIRECTION INPUT ;
  USE SIGNAL ;
  PORT
   LAYER M5 ;
   RECT 171.1080 0.2160 171.1560 0.2640 ;
  END
 END wd[340]
 PIN rd[340]
  DIRECTION OUTPUT ;
  USE SIGNAL ;
  PORT
   LAYER M4 ;
   RECT 241.6560 20.4360 241.7040 20.4840 ;
  END
 END rd[340]
 PIN wd[341]
  DIRECTION INPUT ;
  USE SIGNAL ;
  PORT
   LAYER M5 ;
   RECT 171.3480 0.2160 171.3960 0.2640 ;
  END
 END wd[341]
 PIN rd[341]
  DIRECTION OUTPUT ;
  USE SIGNAL ;
  PORT
   LAYER M4 ;
   RECT 241.6560 20.6280 241.7040 20.6760 ;
  END
 END rd[341]
 PIN wd[342]
  DIRECTION INPUT ;
  USE SIGNAL ;
  PORT
   LAYER M5 ;
   RECT 171.5880 0.2160 171.6360 0.2640 ;
  END
 END wd[342]
 PIN rd[342]
  DIRECTION OUTPUT ;
  USE SIGNAL ;
  PORT
   LAYER M4 ;
   RECT 241.6560 20.8200 241.7040 20.8680 ;
  END
 END rd[342]
 PIN wd[343]
  DIRECTION INPUT ;
  USE SIGNAL ;
  PORT
   LAYER M5 ;
   RECT 171.8280 0.2160 171.8760 0.2640 ;
  END
 END wd[343]
 PIN rd[343]
  DIRECTION OUTPUT ;
  USE SIGNAL ;
  PORT
   LAYER M4 ;
   RECT 241.6560 21.0120 241.7040 21.0600 ;
  END
 END rd[343]
 PIN wd[344]
  DIRECTION INPUT ;
  USE SIGNAL ;
  PORT
   LAYER M5 ;
   RECT 172.0680 0.2160 172.1160 0.2640 ;
  END
 END wd[344]
 PIN rd[344]
  DIRECTION OUTPUT ;
  USE SIGNAL ;
  PORT
   LAYER M4 ;
   RECT 241.6560 21.2040 241.7040 21.2520 ;
  END
 END rd[344]
 PIN wd[345]
  DIRECTION INPUT ;
  USE SIGNAL ;
  PORT
   LAYER M5 ;
   RECT 172.3080 0.2160 172.3560 0.2640 ;
  END
 END wd[345]
 PIN rd[345]
  DIRECTION OUTPUT ;
  USE SIGNAL ;
  PORT
   LAYER M4 ;
   RECT 241.6560 21.3960 241.7040 21.4440 ;
  END
 END rd[345]
 PIN wd[346]
  DIRECTION INPUT ;
  USE SIGNAL ;
  PORT
   LAYER M5 ;
   RECT 172.5480 0.2160 172.5960 0.2640 ;
  END
 END wd[346]
 PIN rd[346]
  DIRECTION OUTPUT ;
  USE SIGNAL ;
  PORT
   LAYER M4 ;
   RECT 241.6560 21.5880 241.7040 21.6360 ;
  END
 END rd[346]
 PIN wd[347]
  DIRECTION INPUT ;
  USE SIGNAL ;
  PORT
   LAYER M5 ;
   RECT 172.7880 0.2160 172.8360 0.2640 ;
  END
 END wd[347]
 PIN rd[347]
  DIRECTION OUTPUT ;
  USE SIGNAL ;
  PORT
   LAYER M4 ;
   RECT 241.6560 21.7800 241.7040 21.8280 ;
  END
 END rd[347]
 PIN wd[348]
  DIRECTION INPUT ;
  USE SIGNAL ;
  PORT
   LAYER M5 ;
   RECT 173.0280 0.2160 173.0760 0.2640 ;
  END
 END wd[348]
 PIN rd[348]
  DIRECTION OUTPUT ;
  USE SIGNAL ;
  PORT
   LAYER M4 ;
   RECT 241.6560 21.9720 241.7040 22.0200 ;
  END
 END rd[348]
 PIN wd[349]
  DIRECTION INPUT ;
  USE SIGNAL ;
  PORT
   LAYER M5 ;
   RECT 173.2680 0.2160 173.3160 0.2640 ;
  END
 END wd[349]
 PIN rd[349]
  DIRECTION OUTPUT ;
  USE SIGNAL ;
  PORT
   LAYER M4 ;
   RECT 241.6560 22.1640 241.7040 22.2120 ;
  END
 END rd[349]
 PIN wd[350]
  DIRECTION INPUT ;
  USE SIGNAL ;
  PORT
   LAYER M5 ;
   RECT 173.5080 0.2160 173.5560 0.2640 ;
  END
 END wd[350]
 PIN rd[350]
  DIRECTION OUTPUT ;
  USE SIGNAL ;
  PORT
   LAYER M4 ;
   RECT 241.6560 22.3560 241.7040 22.4040 ;
  END
 END rd[350]
 PIN wd[351]
  DIRECTION INPUT ;
  USE SIGNAL ;
  PORT
   LAYER M5 ;
   RECT 173.7480 0.2160 173.7960 0.2640 ;
  END
 END wd[351]
 PIN rd[351]
  DIRECTION OUTPUT ;
  USE SIGNAL ;
  PORT
   LAYER M4 ;
   RECT 241.6560 22.5480 241.7040 22.5960 ;
  END
 END rd[351]
 PIN wd[352]
  DIRECTION INPUT ;
  USE SIGNAL ;
  PORT
   LAYER M5 ;
   RECT 173.9880 0.2160 174.0360 0.2640 ;
  END
 END wd[352]
 PIN rd[352]
  DIRECTION OUTPUT ;
  USE SIGNAL ;
  PORT
   LAYER M4 ;
   RECT 241.6560 22.7400 241.7040 22.7880 ;
  END
 END rd[352]
 PIN wd[353]
  DIRECTION INPUT ;
  USE SIGNAL ;
  PORT
   LAYER M5 ;
   RECT 174.2280 0.2160 174.2760 0.2640 ;
  END
 END wd[353]
 PIN rd[353]
  DIRECTION OUTPUT ;
  USE SIGNAL ;
  PORT
   LAYER M4 ;
   RECT 241.6560 22.9320 241.7040 22.9800 ;
  END
 END rd[353]
 PIN wd[354]
  DIRECTION INPUT ;
  USE SIGNAL ;
  PORT
   LAYER M5 ;
   RECT 174.4680 0.2160 174.5160 0.2640 ;
  END
 END wd[354]
 PIN rd[354]
  DIRECTION OUTPUT ;
  USE SIGNAL ;
  PORT
   LAYER M4 ;
   RECT 241.6560 23.1240 241.7040 23.1720 ;
  END
 END rd[354]
 PIN wd[355]
  DIRECTION INPUT ;
  USE SIGNAL ;
  PORT
   LAYER M5 ;
   RECT 174.7080 0.2160 174.7560 0.2640 ;
  END
 END wd[355]
 PIN rd[355]
  DIRECTION OUTPUT ;
  USE SIGNAL ;
  PORT
   LAYER M4 ;
   RECT 241.6560 23.3160 241.7040 23.3640 ;
  END
 END rd[355]
 PIN wd[356]
  DIRECTION INPUT ;
  USE SIGNAL ;
  PORT
   LAYER M5 ;
   RECT 174.9480 0.2160 174.9960 0.2640 ;
  END
 END wd[356]
 PIN rd[356]
  DIRECTION OUTPUT ;
  USE SIGNAL ;
  PORT
   LAYER M4 ;
   RECT 241.6560 23.5080 241.7040 23.5560 ;
  END
 END rd[356]
 PIN wd[357]
  DIRECTION INPUT ;
  USE SIGNAL ;
  PORT
   LAYER M5 ;
   RECT 175.1880 0.2160 175.2360 0.2640 ;
  END
 END wd[357]
 PIN rd[357]
  DIRECTION OUTPUT ;
  USE SIGNAL ;
  PORT
   LAYER M4 ;
   RECT 241.6560 23.7000 241.7040 23.7480 ;
  END
 END rd[357]
 PIN wd[358]
  DIRECTION INPUT ;
  USE SIGNAL ;
  PORT
   LAYER M5 ;
   RECT 175.4280 0.2160 175.4760 0.2640 ;
  END
 END wd[358]
 PIN rd[358]
  DIRECTION OUTPUT ;
  USE SIGNAL ;
  PORT
   LAYER M4 ;
   RECT 241.6560 23.8920 241.7040 23.9400 ;
  END
 END rd[358]
 PIN wd[359]
  DIRECTION INPUT ;
  USE SIGNAL ;
  PORT
   LAYER M5 ;
   RECT 175.6680 0.2160 175.7160 0.2640 ;
  END
 END wd[359]
 PIN rd[359]
  DIRECTION OUTPUT ;
  USE SIGNAL ;
  PORT
   LAYER M4 ;
   RECT 241.6560 24.0840 241.7040 24.1320 ;
  END
 END rd[359]
 PIN wd[360]
  DIRECTION INPUT ;
  USE SIGNAL ;
  PORT
   LAYER M5 ;
   RECT 175.9080 0.2160 175.9560 0.2640 ;
  END
 END wd[360]
 PIN rd[360]
  DIRECTION OUTPUT ;
  USE SIGNAL ;
  PORT
   LAYER M4 ;
   RECT 241.6560 24.2760 241.7040 24.3240 ;
  END
 END rd[360]
 PIN wd[361]
  DIRECTION INPUT ;
  USE SIGNAL ;
  PORT
   LAYER M5 ;
   RECT 176.1480 0.2160 176.1960 0.2640 ;
  END
 END wd[361]
 PIN rd[361]
  DIRECTION OUTPUT ;
  USE SIGNAL ;
  PORT
   LAYER M4 ;
   RECT 241.6560 24.4680 241.7040 24.5160 ;
  END
 END rd[361]
 PIN wd[362]
  DIRECTION INPUT ;
  USE SIGNAL ;
  PORT
   LAYER M5 ;
   RECT 176.3880 0.2160 176.4360 0.2640 ;
  END
 END wd[362]
 PIN rd[362]
  DIRECTION OUTPUT ;
  USE SIGNAL ;
  PORT
   LAYER M4 ;
   RECT 241.6560 24.6600 241.7040 24.7080 ;
  END
 END rd[362]
 PIN wd[363]
  DIRECTION INPUT ;
  USE SIGNAL ;
  PORT
   LAYER M5 ;
   RECT 176.6280 0.2160 176.6760 0.2640 ;
  END
 END wd[363]
 PIN rd[363]
  DIRECTION OUTPUT ;
  USE SIGNAL ;
  PORT
   LAYER M4 ;
   RECT 241.6560 24.8520 241.7040 24.9000 ;
  END
 END rd[363]
 PIN wd[364]
  DIRECTION INPUT ;
  USE SIGNAL ;
  PORT
   LAYER M5 ;
   RECT 176.8680 0.2160 176.9160 0.2640 ;
  END
 END wd[364]
 PIN rd[364]
  DIRECTION OUTPUT ;
  USE SIGNAL ;
  PORT
   LAYER M4 ;
   RECT 241.6560 25.0440 241.7040 25.0920 ;
  END
 END rd[364]
 PIN wd[365]
  DIRECTION INPUT ;
  USE SIGNAL ;
  PORT
   LAYER M5 ;
   RECT 177.1080 0.2160 177.1560 0.2640 ;
  END
 END wd[365]
 PIN rd[365]
  DIRECTION OUTPUT ;
  USE SIGNAL ;
  PORT
   LAYER M4 ;
   RECT 241.6560 25.2360 241.7040 25.2840 ;
  END
 END rd[365]
 PIN wd[366]
  DIRECTION INPUT ;
  USE SIGNAL ;
  PORT
   LAYER M5 ;
   RECT 177.3480 0.2160 177.3960 0.2640 ;
  END
 END wd[366]
 PIN rd[366]
  DIRECTION OUTPUT ;
  USE SIGNAL ;
  PORT
   LAYER M4 ;
   RECT 241.6560 25.4280 241.7040 25.4760 ;
  END
 END rd[366]
 PIN wd[367]
  DIRECTION INPUT ;
  USE SIGNAL ;
  PORT
   LAYER M5 ;
   RECT 177.5880 0.2160 177.6360 0.2640 ;
  END
 END wd[367]
 PIN rd[367]
  DIRECTION OUTPUT ;
  USE SIGNAL ;
  PORT
   LAYER M4 ;
   RECT 241.6560 25.6200 241.7040 25.6680 ;
  END
 END rd[367]
 PIN wd[368]
  DIRECTION INPUT ;
  USE SIGNAL ;
  PORT
   LAYER M5 ;
   RECT 177.8280 0.2160 177.8760 0.2640 ;
  END
 END wd[368]
 PIN rd[368]
  DIRECTION OUTPUT ;
  USE SIGNAL ;
  PORT
   LAYER M4 ;
   RECT 241.6560 25.8120 241.7040 25.8600 ;
  END
 END rd[368]
 PIN wd[369]
  DIRECTION INPUT ;
  USE SIGNAL ;
  PORT
   LAYER M5 ;
   RECT 178.0680 0.2160 178.1160 0.2640 ;
  END
 END wd[369]
 PIN rd[369]
  DIRECTION OUTPUT ;
  USE SIGNAL ;
  PORT
   LAYER M4 ;
   RECT 241.6560 26.0040 241.7040 26.0520 ;
  END
 END rd[369]
 PIN wd[370]
  DIRECTION INPUT ;
  USE SIGNAL ;
  PORT
   LAYER M5 ;
   RECT 178.3080 0.2160 178.3560 0.2640 ;
  END
 END wd[370]
 PIN rd[370]
  DIRECTION OUTPUT ;
  USE SIGNAL ;
  PORT
   LAYER M4 ;
   RECT 241.6560 26.1960 241.7040 26.2440 ;
  END
 END rd[370]
 PIN wd[371]
  DIRECTION INPUT ;
  USE SIGNAL ;
  PORT
   LAYER M5 ;
   RECT 178.5480 0.2160 178.5960 0.2640 ;
  END
 END wd[371]
 PIN rd[371]
  DIRECTION OUTPUT ;
  USE SIGNAL ;
  PORT
   LAYER M4 ;
   RECT 241.6560 26.3880 241.7040 26.4360 ;
  END
 END rd[371]
 PIN wd[372]
  DIRECTION INPUT ;
  USE SIGNAL ;
  PORT
   LAYER M5 ;
   RECT 178.7880 0.2160 178.8360 0.2640 ;
  END
 END wd[372]
 PIN rd[372]
  DIRECTION OUTPUT ;
  USE SIGNAL ;
  PORT
   LAYER M4 ;
   RECT 241.6560 26.5800 241.7040 26.6280 ;
  END
 END rd[372]
 PIN wd[373]
  DIRECTION INPUT ;
  USE SIGNAL ;
  PORT
   LAYER M5 ;
   RECT 179.0280 0.2160 179.0760 0.2640 ;
  END
 END wd[373]
 PIN rd[373]
  DIRECTION OUTPUT ;
  USE SIGNAL ;
  PORT
   LAYER M4 ;
   RECT 241.6560 26.7720 241.7040 26.8200 ;
  END
 END rd[373]
 PIN wd[374]
  DIRECTION INPUT ;
  USE SIGNAL ;
  PORT
   LAYER M5 ;
   RECT 179.2680 0.2160 179.3160 0.2640 ;
  END
 END wd[374]
 PIN rd[374]
  DIRECTION OUTPUT ;
  USE SIGNAL ;
  PORT
   LAYER M4 ;
   RECT 241.6560 26.9640 241.7040 27.0120 ;
  END
 END rd[374]
 PIN wd[375]
  DIRECTION INPUT ;
  USE SIGNAL ;
  PORT
   LAYER M5 ;
   RECT 179.5080 0.2160 179.5560 0.2640 ;
  END
 END wd[375]
 PIN rd[375]
  DIRECTION OUTPUT ;
  USE SIGNAL ;
  PORT
   LAYER M4 ;
   RECT 241.6560 27.1560 241.7040 27.2040 ;
  END
 END rd[375]
 PIN wd[376]
  DIRECTION INPUT ;
  USE SIGNAL ;
  PORT
   LAYER M5 ;
   RECT 179.7480 0.2160 179.7960 0.2640 ;
  END
 END wd[376]
 PIN rd[376]
  DIRECTION OUTPUT ;
  USE SIGNAL ;
  PORT
   LAYER M4 ;
   RECT 241.6560 27.3480 241.7040 27.3960 ;
  END
 END rd[376]
 PIN wd[377]
  DIRECTION INPUT ;
  USE SIGNAL ;
  PORT
   LAYER M5 ;
   RECT 179.9880 0.2160 180.0360 0.2640 ;
  END
 END wd[377]
 PIN rd[377]
  DIRECTION OUTPUT ;
  USE SIGNAL ;
  PORT
   LAYER M4 ;
   RECT 241.6560 27.5400 241.7040 27.5880 ;
  END
 END rd[377]
 PIN wd[378]
  DIRECTION INPUT ;
  USE SIGNAL ;
  PORT
   LAYER M5 ;
   RECT 180.2280 0.2160 180.2760 0.2640 ;
  END
 END wd[378]
 PIN rd[378]
  DIRECTION OUTPUT ;
  USE SIGNAL ;
  PORT
   LAYER M4 ;
   RECT 241.6560 27.7320 241.7040 27.7800 ;
  END
 END rd[378]
 PIN wd[379]
  DIRECTION INPUT ;
  USE SIGNAL ;
  PORT
   LAYER M5 ;
   RECT 180.4680 0.2160 180.5160 0.2640 ;
  END
 END wd[379]
 PIN rd[379]
  DIRECTION OUTPUT ;
  USE SIGNAL ;
  PORT
   LAYER M4 ;
   RECT 241.6560 27.9240 241.7040 27.9720 ;
  END
 END rd[379]
 PIN wd[380]
  DIRECTION INPUT ;
  USE SIGNAL ;
  PORT
   LAYER M5 ;
   RECT 180.7080 0.2160 180.7560 0.2640 ;
  END
 END wd[380]
 PIN rd[380]
  DIRECTION OUTPUT ;
  USE SIGNAL ;
  PORT
   LAYER M4 ;
   RECT 241.6560 28.1160 241.7040 28.1640 ;
  END
 END rd[380]
 PIN wd[381]
  DIRECTION INPUT ;
  USE SIGNAL ;
  PORT
   LAYER M5 ;
   RECT 180.9480 0.2160 180.9960 0.2640 ;
  END
 END wd[381]
 PIN rd[381]
  DIRECTION OUTPUT ;
  USE SIGNAL ;
  PORT
   LAYER M4 ;
   RECT 241.6560 28.3080 241.7040 28.3560 ;
  END
 END rd[381]
 PIN wd[382]
  DIRECTION INPUT ;
  USE SIGNAL ;
  PORT
   LAYER M5 ;
   RECT 181.1880 0.2160 181.2360 0.2640 ;
  END
 END wd[382]
 PIN rd[382]
  DIRECTION OUTPUT ;
  USE SIGNAL ;
  PORT
   LAYER M4 ;
   RECT 241.6560 28.5000 241.7040 28.5480 ;
  END
 END rd[382]
 PIN wd[383]
  DIRECTION INPUT ;
  USE SIGNAL ;
  PORT
   LAYER M5 ;
   RECT 181.4280 0.2160 181.4760 0.2640 ;
  END
 END wd[383]
 PIN rd[383]
  DIRECTION OUTPUT ;
  USE SIGNAL ;
  PORT
   LAYER M4 ;
   RECT 241.6560 28.6920 241.7040 28.7400 ;
  END
 END rd[383]
 PIN wd[384]
  DIRECTION INPUT ;
  USE SIGNAL ;
  PORT
   LAYER M5 ;
   RECT 181.6680 0.2160 181.7160 0.2640 ;
  END
 END wd[384]
 PIN rd[384]
  DIRECTION OUTPUT ;
  USE SIGNAL ;
  PORT
   LAYER M4 ;
   RECT 241.6560 28.8840 241.7040 28.9320 ;
  END
 END rd[384]
 PIN wd[385]
  DIRECTION INPUT ;
  USE SIGNAL ;
  PORT
   LAYER M5 ;
   RECT 181.9080 0.2160 181.9560 0.2640 ;
  END
 END wd[385]
 PIN rd[385]
  DIRECTION OUTPUT ;
  USE SIGNAL ;
  PORT
   LAYER M4 ;
   RECT 241.6560 29.0760 241.7040 29.1240 ;
  END
 END rd[385]
 PIN wd[386]
  DIRECTION INPUT ;
  USE SIGNAL ;
  PORT
   LAYER M5 ;
   RECT 182.1480 0.2160 182.1960 0.2640 ;
  END
 END wd[386]
 PIN rd[386]
  DIRECTION OUTPUT ;
  USE SIGNAL ;
  PORT
   LAYER M4 ;
   RECT 241.6560 29.2680 241.7040 29.3160 ;
  END
 END rd[386]
 PIN wd[387]
  DIRECTION INPUT ;
  USE SIGNAL ;
  PORT
   LAYER M5 ;
   RECT 182.3880 0.2160 182.4360 0.2640 ;
  END
 END wd[387]
 PIN rd[387]
  DIRECTION OUTPUT ;
  USE SIGNAL ;
  PORT
   LAYER M4 ;
   RECT 241.6560 29.4600 241.7040 29.5080 ;
  END
 END rd[387]
 PIN wd[388]
  DIRECTION INPUT ;
  USE SIGNAL ;
  PORT
   LAYER M5 ;
   RECT 182.6280 0.2160 182.6760 0.2640 ;
  END
 END wd[388]
 PIN rd[388]
  DIRECTION OUTPUT ;
  USE SIGNAL ;
  PORT
   LAYER M4 ;
   RECT 241.6560 29.6520 241.7040 29.7000 ;
  END
 END rd[388]
 PIN wd[389]
  DIRECTION INPUT ;
  USE SIGNAL ;
  PORT
   LAYER M5 ;
   RECT 182.8680 0.2160 182.9160 0.2640 ;
  END
 END wd[389]
 PIN rd[389]
  DIRECTION OUTPUT ;
  USE SIGNAL ;
  PORT
   LAYER M4 ;
   RECT 241.6560 29.8440 241.7040 29.8920 ;
  END
 END rd[389]
 PIN wd[390]
  DIRECTION INPUT ;
  USE SIGNAL ;
  PORT
   LAYER M5 ;
   RECT 183.1080 0.2160 183.1560 0.2640 ;
  END
 END wd[390]
 PIN rd[390]
  DIRECTION OUTPUT ;
  USE SIGNAL ;
  PORT
   LAYER M4 ;
   RECT 241.6560 30.0360 241.7040 30.0840 ;
  END
 END rd[390]
 PIN wd[391]
  DIRECTION INPUT ;
  USE SIGNAL ;
  PORT
   LAYER M5 ;
   RECT 183.3480 0.2160 183.3960 0.2640 ;
  END
 END wd[391]
 PIN rd[391]
  DIRECTION OUTPUT ;
  USE SIGNAL ;
  PORT
   LAYER M4 ;
   RECT 241.6560 30.2280 241.7040 30.2760 ;
  END
 END rd[391]
 PIN wd[392]
  DIRECTION INPUT ;
  USE SIGNAL ;
  PORT
   LAYER M5 ;
   RECT 183.5880 0.2160 183.6360 0.2640 ;
  END
 END wd[392]
 PIN rd[392]
  DIRECTION OUTPUT ;
  USE SIGNAL ;
  PORT
   LAYER M4 ;
   RECT 241.6560 30.4200 241.7040 30.4680 ;
  END
 END rd[392]
 PIN wd[393]
  DIRECTION INPUT ;
  USE SIGNAL ;
  PORT
   LAYER M5 ;
   RECT 183.8280 0.2160 183.8760 0.2640 ;
  END
 END wd[393]
 PIN rd[393]
  DIRECTION OUTPUT ;
  USE SIGNAL ;
  PORT
   LAYER M4 ;
   RECT 241.6560 30.6120 241.7040 30.6600 ;
  END
 END rd[393]
 PIN wd[394]
  DIRECTION INPUT ;
  USE SIGNAL ;
  PORT
   LAYER M5 ;
   RECT 184.0680 0.2160 184.1160 0.2640 ;
  END
 END wd[394]
 PIN rd[394]
  DIRECTION OUTPUT ;
  USE SIGNAL ;
  PORT
   LAYER M4 ;
   RECT 241.6560 30.8040 241.7040 30.8520 ;
  END
 END rd[394]
 PIN wd[395]
  DIRECTION INPUT ;
  USE SIGNAL ;
  PORT
   LAYER M5 ;
   RECT 184.3080 0.2160 184.3560 0.2640 ;
  END
 END wd[395]
 PIN rd[395]
  DIRECTION OUTPUT ;
  USE SIGNAL ;
  PORT
   LAYER M4 ;
   RECT 241.6560 30.9960 241.7040 31.0440 ;
  END
 END rd[395]
 PIN wd[396]
  DIRECTION INPUT ;
  USE SIGNAL ;
  PORT
   LAYER M5 ;
   RECT 184.5480 0.2160 184.5960 0.2640 ;
  END
 END wd[396]
 PIN rd[396]
  DIRECTION OUTPUT ;
  USE SIGNAL ;
  PORT
   LAYER M4 ;
   RECT 241.6560 31.1880 241.7040 31.2360 ;
  END
 END rd[396]
 PIN wd[397]
  DIRECTION INPUT ;
  USE SIGNAL ;
  PORT
   LAYER M5 ;
   RECT 184.7880 0.2160 184.8360 0.2640 ;
  END
 END wd[397]
 PIN rd[397]
  DIRECTION OUTPUT ;
  USE SIGNAL ;
  PORT
   LAYER M4 ;
   RECT 241.6560 31.3800 241.7040 31.4280 ;
  END
 END rd[397]
 PIN wd[398]
  DIRECTION INPUT ;
  USE SIGNAL ;
  PORT
   LAYER M5 ;
   RECT 185.0280 0.2160 185.0760 0.2640 ;
  END
 END wd[398]
 PIN rd[398]
  DIRECTION OUTPUT ;
  USE SIGNAL ;
  PORT
   LAYER M4 ;
   RECT 241.6560 31.5720 241.7040 31.6200 ;
  END
 END rd[398]
 PIN wd[399]
  DIRECTION INPUT ;
  USE SIGNAL ;
  PORT
   LAYER M5 ;
   RECT 185.2680 0.2160 185.3160 0.2640 ;
  END
 END wd[399]
 PIN rd[399]
  DIRECTION OUTPUT ;
  USE SIGNAL ;
  PORT
   LAYER M4 ;
   RECT 241.6560 31.7640 241.7040 31.8120 ;
  END
 END rd[399]
 PIN wd[400]
  DIRECTION INPUT ;
  USE SIGNAL ;
  PORT
   LAYER M5 ;
   RECT 185.5080 0.2160 185.5560 0.2640 ;
  END
 END wd[400]
 PIN rd[400]
  DIRECTION OUTPUT ;
  USE SIGNAL ;
  PORT
   LAYER M4 ;
   RECT 241.6560 31.9560 241.7040 32.0040 ;
  END
 END rd[400]
 PIN wd[401]
  DIRECTION INPUT ;
  USE SIGNAL ;
  PORT
   LAYER M5 ;
   RECT 185.7480 0.2160 185.7960 0.2640 ;
  END
 END wd[401]
 PIN rd[401]
  DIRECTION OUTPUT ;
  USE SIGNAL ;
  PORT
   LAYER M4 ;
   RECT 241.6560 32.1480 241.7040 32.1960 ;
  END
 END rd[401]
 PIN wd[402]
  DIRECTION INPUT ;
  USE SIGNAL ;
  PORT
   LAYER M5 ;
   RECT 185.9880 0.2160 186.0360 0.2640 ;
  END
 END wd[402]
 PIN rd[402]
  DIRECTION OUTPUT ;
  USE SIGNAL ;
  PORT
   LAYER M4 ;
   RECT 241.6560 32.3400 241.7040 32.3880 ;
  END
 END rd[402]
 PIN wd[403]
  DIRECTION INPUT ;
  USE SIGNAL ;
  PORT
   LAYER M5 ;
   RECT 186.2280 0.2160 186.2760 0.2640 ;
  END
 END wd[403]
 PIN rd[403]
  DIRECTION OUTPUT ;
  USE SIGNAL ;
  PORT
   LAYER M4 ;
   RECT 241.6560 32.5320 241.7040 32.5800 ;
  END
 END rd[403]
 PIN wd[404]
  DIRECTION INPUT ;
  USE SIGNAL ;
  PORT
   LAYER M5 ;
   RECT 186.4680 0.2160 186.5160 0.2640 ;
  END
 END wd[404]
 PIN rd[404]
  DIRECTION OUTPUT ;
  USE SIGNAL ;
  PORT
   LAYER M4 ;
   RECT 241.6560 32.7240 241.7040 32.7720 ;
  END
 END rd[404]
 PIN wd[405]
  DIRECTION INPUT ;
  USE SIGNAL ;
  PORT
   LAYER M5 ;
   RECT 186.7080 0.2160 186.7560 0.2640 ;
  END
 END wd[405]
 PIN rd[405]
  DIRECTION OUTPUT ;
  USE SIGNAL ;
  PORT
   LAYER M4 ;
   RECT 241.6560 32.9160 241.7040 32.9640 ;
  END
 END rd[405]
 PIN wd[406]
  DIRECTION INPUT ;
  USE SIGNAL ;
  PORT
   LAYER M5 ;
   RECT 186.9480 0.2160 186.9960 0.2640 ;
  END
 END wd[406]
 PIN rd[406]
  DIRECTION OUTPUT ;
  USE SIGNAL ;
  PORT
   LAYER M4 ;
   RECT 241.6560 33.1080 241.7040 33.1560 ;
  END
 END rd[406]
 PIN wd[407]
  DIRECTION INPUT ;
  USE SIGNAL ;
  PORT
   LAYER M5 ;
   RECT 187.1880 0.2160 187.2360 0.2640 ;
  END
 END wd[407]
 PIN rd[407]
  DIRECTION OUTPUT ;
  USE SIGNAL ;
  PORT
   LAYER M4 ;
   RECT 241.6560 33.3000 241.7040 33.3480 ;
  END
 END rd[407]
 PIN wd[408]
  DIRECTION INPUT ;
  USE SIGNAL ;
  PORT
   LAYER M5 ;
   RECT 187.4280 0.2160 187.4760 0.2640 ;
  END
 END wd[408]
 PIN rd[408]
  DIRECTION OUTPUT ;
  USE SIGNAL ;
  PORT
   LAYER M4 ;
   RECT 241.6560 33.4920 241.7040 33.5400 ;
  END
 END rd[408]
 PIN wd[409]
  DIRECTION INPUT ;
  USE SIGNAL ;
  PORT
   LAYER M5 ;
   RECT 187.6680 0.2160 187.7160 0.2640 ;
  END
 END wd[409]
 PIN rd[409]
  DIRECTION OUTPUT ;
  USE SIGNAL ;
  PORT
   LAYER M4 ;
   RECT 241.6560 33.6840 241.7040 33.7320 ;
  END
 END rd[409]
 PIN wd[410]
  DIRECTION INPUT ;
  USE SIGNAL ;
  PORT
   LAYER M5 ;
   RECT 187.9080 0.2160 187.9560 0.2640 ;
  END
 END wd[410]
 PIN rd[410]
  DIRECTION OUTPUT ;
  USE SIGNAL ;
  PORT
   LAYER M4 ;
   RECT 241.6560 33.8760 241.7040 33.9240 ;
  END
 END rd[410]
 PIN wd[411]
  DIRECTION INPUT ;
  USE SIGNAL ;
  PORT
   LAYER M5 ;
   RECT 188.1480 0.2160 188.1960 0.2640 ;
  END
 END wd[411]
 PIN rd[411]
  DIRECTION OUTPUT ;
  USE SIGNAL ;
  PORT
   LAYER M4 ;
   RECT 241.6560 34.0680 241.7040 34.1160 ;
  END
 END rd[411]
 PIN wd[412]
  DIRECTION INPUT ;
  USE SIGNAL ;
  PORT
   LAYER M5 ;
   RECT 188.3880 0.2160 188.4360 0.2640 ;
  END
 END wd[412]
 PIN rd[412]
  DIRECTION OUTPUT ;
  USE SIGNAL ;
  PORT
   LAYER M4 ;
   RECT 241.6560 34.2600 241.7040 34.3080 ;
  END
 END rd[412]
 PIN wd[413]
  DIRECTION INPUT ;
  USE SIGNAL ;
  PORT
   LAYER M5 ;
   RECT 188.6280 0.2160 188.6760 0.2640 ;
  END
 END wd[413]
 PIN rd[413]
  DIRECTION OUTPUT ;
  USE SIGNAL ;
  PORT
   LAYER M4 ;
   RECT 241.6560 34.4520 241.7040 34.5000 ;
  END
 END rd[413]
 PIN wd[414]
  DIRECTION INPUT ;
  USE SIGNAL ;
  PORT
   LAYER M5 ;
   RECT 188.8680 0.2160 188.9160 0.2640 ;
  END
 END wd[414]
 PIN rd[414]
  DIRECTION OUTPUT ;
  USE SIGNAL ;
  PORT
   LAYER M4 ;
   RECT 241.6560 34.6440 241.7040 34.6920 ;
  END
 END rd[414]
 PIN wd[415]
  DIRECTION INPUT ;
  USE SIGNAL ;
  PORT
   LAYER M5 ;
   RECT 189.1080 0.2160 189.1560 0.2640 ;
  END
 END wd[415]
 PIN rd[415]
  DIRECTION OUTPUT ;
  USE SIGNAL ;
  PORT
   LAYER M4 ;
   RECT 241.6560 34.8360 241.7040 34.8840 ;
  END
 END rd[415]
 PIN wd[416]
  DIRECTION INPUT ;
  USE SIGNAL ;
  PORT
   LAYER M5 ;
   RECT 189.3480 0.2160 189.3960 0.2640 ;
  END
 END wd[416]
 PIN rd[416]
  DIRECTION OUTPUT ;
  USE SIGNAL ;
  PORT
   LAYER M4 ;
   RECT 241.6560 35.0280 241.7040 35.0760 ;
  END
 END rd[416]
 PIN wd[417]
  DIRECTION INPUT ;
  USE SIGNAL ;
  PORT
   LAYER M5 ;
   RECT 189.5880 0.2160 189.6360 0.2640 ;
  END
 END wd[417]
 PIN rd[417]
  DIRECTION OUTPUT ;
  USE SIGNAL ;
  PORT
   LAYER M4 ;
   RECT 241.6560 35.2200 241.7040 35.2680 ;
  END
 END rd[417]
 PIN wd[418]
  DIRECTION INPUT ;
  USE SIGNAL ;
  PORT
   LAYER M5 ;
   RECT 189.8280 0.2160 189.8760 0.2640 ;
  END
 END wd[418]
 PIN rd[418]
  DIRECTION OUTPUT ;
  USE SIGNAL ;
  PORT
   LAYER M4 ;
   RECT 241.6560 35.4120 241.7040 35.4600 ;
  END
 END rd[418]
 PIN wd[419]
  DIRECTION INPUT ;
  USE SIGNAL ;
  PORT
   LAYER M5 ;
   RECT 190.0680 0.2160 190.1160 0.2640 ;
  END
 END wd[419]
 PIN rd[419]
  DIRECTION OUTPUT ;
  USE SIGNAL ;
  PORT
   LAYER M4 ;
   RECT 241.6560 35.6040 241.7040 35.6520 ;
  END
 END rd[419]
 PIN wd[420]
  DIRECTION INPUT ;
  USE SIGNAL ;
  PORT
   LAYER M5 ;
   RECT 190.3080 0.2160 190.3560 0.2640 ;
  END
 END wd[420]
 PIN rd[420]
  DIRECTION OUTPUT ;
  USE SIGNAL ;
  PORT
   LAYER M4 ;
   RECT 241.6560 35.7960 241.7040 35.8440 ;
  END
 END rd[420]
 PIN wd[421]
  DIRECTION INPUT ;
  USE SIGNAL ;
  PORT
   LAYER M5 ;
   RECT 190.5480 0.2160 190.5960 0.2640 ;
  END
 END wd[421]
 PIN rd[421]
  DIRECTION OUTPUT ;
  USE SIGNAL ;
  PORT
   LAYER M4 ;
   RECT 241.6560 35.9880 241.7040 36.0360 ;
  END
 END rd[421]
 PIN wd[422]
  DIRECTION INPUT ;
  USE SIGNAL ;
  PORT
   LAYER M5 ;
   RECT 190.7880 0.2160 190.8360 0.2640 ;
  END
 END wd[422]
 PIN rd[422]
  DIRECTION OUTPUT ;
  USE SIGNAL ;
  PORT
   LAYER M4 ;
   RECT 241.6560 36.1800 241.7040 36.2280 ;
  END
 END rd[422]
 PIN wd[423]
  DIRECTION INPUT ;
  USE SIGNAL ;
  PORT
   LAYER M5 ;
   RECT 191.0280 0.2160 191.0760 0.2640 ;
  END
 END wd[423]
 PIN rd[423]
  DIRECTION OUTPUT ;
  USE SIGNAL ;
  PORT
   LAYER M4 ;
   RECT 241.6560 36.3720 241.7040 36.4200 ;
  END
 END rd[423]
 PIN wd[424]
  DIRECTION INPUT ;
  USE SIGNAL ;
  PORT
   LAYER M5 ;
   RECT 191.2680 0.2160 191.3160 0.2640 ;
  END
 END wd[424]
 PIN rd[424]
  DIRECTION OUTPUT ;
  USE SIGNAL ;
  PORT
   LAYER M4 ;
   RECT 241.6560 36.5640 241.7040 36.6120 ;
  END
 END rd[424]
 PIN wd[425]
  DIRECTION INPUT ;
  USE SIGNAL ;
  PORT
   LAYER M5 ;
   RECT 191.5080 0.2160 191.5560 0.2640 ;
  END
 END wd[425]
 PIN rd[425]
  DIRECTION OUTPUT ;
  USE SIGNAL ;
  PORT
   LAYER M4 ;
   RECT 241.6560 36.7560 241.7040 36.8040 ;
  END
 END rd[425]
 PIN wd[426]
  DIRECTION INPUT ;
  USE SIGNAL ;
  PORT
   LAYER M5 ;
   RECT 191.7480 0.2160 191.7960 0.2640 ;
  END
 END wd[426]
 PIN rd[426]
  DIRECTION OUTPUT ;
  USE SIGNAL ;
  PORT
   LAYER M4 ;
   RECT 241.6560 36.9480 241.7040 36.9960 ;
  END
 END rd[426]
 PIN wd[427]
  DIRECTION INPUT ;
  USE SIGNAL ;
  PORT
   LAYER M5 ;
   RECT 191.9880 0.2160 192.0360 0.2640 ;
  END
 END wd[427]
 PIN rd[427]
  DIRECTION OUTPUT ;
  USE SIGNAL ;
  PORT
   LAYER M4 ;
   RECT 241.6560 37.1400 241.7040 37.1880 ;
  END
 END rd[427]
 PIN wd[428]
  DIRECTION INPUT ;
  USE SIGNAL ;
  PORT
   LAYER M5 ;
   RECT 192.2280 0.2160 192.2760 0.2640 ;
  END
 END wd[428]
 PIN rd[428]
  DIRECTION OUTPUT ;
  USE SIGNAL ;
  PORT
   LAYER M4 ;
   RECT 241.6560 37.3320 241.7040 37.3800 ;
  END
 END rd[428]
 PIN wd[429]
  DIRECTION INPUT ;
  USE SIGNAL ;
  PORT
   LAYER M5 ;
   RECT 192.4680 0.2160 192.5160 0.2640 ;
  END
 END wd[429]
 PIN rd[429]
  DIRECTION OUTPUT ;
  USE SIGNAL ;
  PORT
   LAYER M4 ;
   RECT 241.6560 37.5240 241.7040 37.5720 ;
  END
 END rd[429]
 PIN wd[430]
  DIRECTION INPUT ;
  USE SIGNAL ;
  PORT
   LAYER M5 ;
   RECT 192.7080 0.2160 192.7560 0.2640 ;
  END
 END wd[430]
 PIN rd[430]
  DIRECTION OUTPUT ;
  USE SIGNAL ;
  PORT
   LAYER M4 ;
   RECT 241.6560 37.7160 241.7040 37.7640 ;
  END
 END rd[430]
 PIN wd[431]
  DIRECTION INPUT ;
  USE SIGNAL ;
  PORT
   LAYER M5 ;
   RECT 192.9480 0.2160 192.9960 0.2640 ;
  END
 END wd[431]
 PIN rd[431]
  DIRECTION OUTPUT ;
  USE SIGNAL ;
  PORT
   LAYER M4 ;
   RECT 241.6560 37.9080 241.7040 37.9560 ;
  END
 END rd[431]
 PIN wd[432]
  DIRECTION INPUT ;
  USE SIGNAL ;
  PORT
   LAYER M5 ;
   RECT 193.1880 0.2160 193.2360 0.2640 ;
  END
 END wd[432]
 PIN rd[432]
  DIRECTION OUTPUT ;
  USE SIGNAL ;
  PORT
   LAYER M4 ;
   RECT 241.6560 38.1000 241.7040 38.1480 ;
  END
 END rd[432]
 PIN wd[433]
  DIRECTION INPUT ;
  USE SIGNAL ;
  PORT
   LAYER M5 ;
   RECT 193.4280 0.2160 193.4760 0.2640 ;
  END
 END wd[433]
 PIN rd[433]
  DIRECTION OUTPUT ;
  USE SIGNAL ;
  PORT
   LAYER M4 ;
   RECT 241.6560 38.2920 241.7040 38.3400 ;
  END
 END rd[433]
 PIN wd[434]
  DIRECTION INPUT ;
  USE SIGNAL ;
  PORT
   LAYER M5 ;
   RECT 193.6680 0.2160 193.7160 0.2640 ;
  END
 END wd[434]
 PIN rd[434]
  DIRECTION OUTPUT ;
  USE SIGNAL ;
  PORT
   LAYER M4 ;
   RECT 241.6560 38.4840 241.7040 38.5320 ;
  END
 END rd[434]
 PIN wd[435]
  DIRECTION INPUT ;
  USE SIGNAL ;
  PORT
   LAYER M5 ;
   RECT 193.9080 0.2160 193.9560 0.2640 ;
  END
 END wd[435]
 PIN rd[435]
  DIRECTION OUTPUT ;
  USE SIGNAL ;
  PORT
   LAYER M4 ;
   RECT 241.6560 38.6760 241.7040 38.7240 ;
  END
 END rd[435]
 PIN wd[436]
  DIRECTION INPUT ;
  USE SIGNAL ;
  PORT
   LAYER M5 ;
   RECT 194.1480 0.2160 194.1960 0.2640 ;
  END
 END wd[436]
 PIN rd[436]
  DIRECTION OUTPUT ;
  USE SIGNAL ;
  PORT
   LAYER M4 ;
   RECT 241.6560 38.8680 241.7040 38.9160 ;
  END
 END rd[436]
 PIN wd[437]
  DIRECTION INPUT ;
  USE SIGNAL ;
  PORT
   LAYER M5 ;
   RECT 194.3880 0.2160 194.4360 0.2640 ;
  END
 END wd[437]
 PIN rd[437]
  DIRECTION OUTPUT ;
  USE SIGNAL ;
  PORT
   LAYER M4 ;
   RECT 241.6560 39.0600 241.7040 39.1080 ;
  END
 END rd[437]
 PIN wd[438]
  DIRECTION INPUT ;
  USE SIGNAL ;
  PORT
   LAYER M5 ;
   RECT 194.6280 0.2160 194.6760 0.2640 ;
  END
 END wd[438]
 PIN rd[438]
  DIRECTION OUTPUT ;
  USE SIGNAL ;
  PORT
   LAYER M4 ;
   RECT 241.6560 39.2520 241.7040 39.3000 ;
  END
 END rd[438]
 PIN wd[439]
  DIRECTION INPUT ;
  USE SIGNAL ;
  PORT
   LAYER M5 ;
   RECT 194.8680 0.2160 194.9160 0.2640 ;
  END
 END wd[439]
 PIN rd[439]
  DIRECTION OUTPUT ;
  USE SIGNAL ;
  PORT
   LAYER M4 ;
   RECT 241.6560 39.4440 241.7040 39.4920 ;
  END
 END rd[439]
 PIN wd[440]
  DIRECTION INPUT ;
  USE SIGNAL ;
  PORT
   LAYER M5 ;
   RECT 195.1080 0.2160 195.1560 0.2640 ;
  END
 END wd[440]
 PIN rd[440]
  DIRECTION OUTPUT ;
  USE SIGNAL ;
  PORT
   LAYER M4 ;
   RECT 241.6560 39.6360 241.7040 39.6840 ;
  END
 END rd[440]
 PIN wd[441]
  DIRECTION INPUT ;
  USE SIGNAL ;
  PORT
   LAYER M5 ;
   RECT 195.3480 0.2160 195.3960 0.2640 ;
  END
 END wd[441]
 PIN rd[441]
  DIRECTION OUTPUT ;
  USE SIGNAL ;
  PORT
   LAYER M4 ;
   RECT 241.6560 39.8280 241.7040 39.8760 ;
  END
 END rd[441]
 PIN wd[442]
  DIRECTION INPUT ;
  USE SIGNAL ;
  PORT
   LAYER M5 ;
   RECT 195.5880 0.2160 195.6360 0.2640 ;
  END
 END wd[442]
 PIN rd[442]
  DIRECTION OUTPUT ;
  USE SIGNAL ;
  PORT
   LAYER M4 ;
   RECT 241.6560 40.0200 241.7040 40.0680 ;
  END
 END rd[442]
 PIN wd[443]
  DIRECTION INPUT ;
  USE SIGNAL ;
  PORT
   LAYER M5 ;
   RECT 195.8280 0.2160 195.8760 0.2640 ;
  END
 END wd[443]
 PIN rd[443]
  DIRECTION OUTPUT ;
  USE SIGNAL ;
  PORT
   LAYER M4 ;
   RECT 241.6560 40.2120 241.7040 40.2600 ;
  END
 END rd[443]
 PIN wd[444]
  DIRECTION INPUT ;
  USE SIGNAL ;
  PORT
   LAYER M5 ;
   RECT 196.0680 0.2160 196.1160 0.2640 ;
  END
 END wd[444]
 PIN rd[444]
  DIRECTION OUTPUT ;
  USE SIGNAL ;
  PORT
   LAYER M4 ;
   RECT 241.6560 40.4040 241.7040 40.4520 ;
  END
 END rd[444]
 PIN wd[445]
  DIRECTION INPUT ;
  USE SIGNAL ;
  PORT
   LAYER M5 ;
   RECT 196.3080 0.2160 196.3560 0.2640 ;
  END
 END wd[445]
 PIN rd[445]
  DIRECTION OUTPUT ;
  USE SIGNAL ;
  PORT
   LAYER M4 ;
   RECT 241.6560 40.5960 241.7040 40.6440 ;
  END
 END rd[445]
 PIN wd[446]
  DIRECTION INPUT ;
  USE SIGNAL ;
  PORT
   LAYER M5 ;
   RECT 196.5480 0.2160 196.5960 0.2640 ;
  END
 END wd[446]
 PIN rd[446]
  DIRECTION OUTPUT ;
  USE SIGNAL ;
  PORT
   LAYER M4 ;
   RECT 241.6560 40.7880 241.7040 40.8360 ;
  END
 END rd[446]
 PIN wd[447]
  DIRECTION INPUT ;
  USE SIGNAL ;
  PORT
   LAYER M5 ;
   RECT 196.7880 0.2160 196.8360 0.2640 ;
  END
 END wd[447]
 PIN rd[447]
  DIRECTION OUTPUT ;
  USE SIGNAL ;
  PORT
   LAYER M4 ;
   RECT 241.6560 40.9800 241.7040 41.0280 ;
  END
 END rd[447]
 PIN wd[448]
  DIRECTION INPUT ;
  USE SIGNAL ;
  PORT
   LAYER M5 ;
   RECT 197.0280 0.2160 197.0760 0.2640 ;
  END
 END wd[448]
 PIN rd[448]
  DIRECTION OUTPUT ;
  USE SIGNAL ;
  PORT
   LAYER M4 ;
   RECT 241.6560 41.1720 241.7040 41.2200 ;
  END
 END rd[448]
 PIN wd[449]
  DIRECTION INPUT ;
  USE SIGNAL ;
  PORT
   LAYER M5 ;
   RECT 197.2680 0.2160 197.3160 0.2640 ;
  END
 END wd[449]
 PIN rd[449]
  DIRECTION OUTPUT ;
  USE SIGNAL ;
  PORT
   LAYER M4 ;
   RECT 241.6560 41.3640 241.7040 41.4120 ;
  END
 END rd[449]
 PIN wd[450]
  DIRECTION INPUT ;
  USE SIGNAL ;
  PORT
   LAYER M5 ;
   RECT 197.5080 0.2160 197.5560 0.2640 ;
  END
 END wd[450]
 PIN rd[450]
  DIRECTION OUTPUT ;
  USE SIGNAL ;
  PORT
   LAYER M4 ;
   RECT 241.6560 41.5560 241.7040 41.6040 ;
  END
 END rd[450]
 PIN wd[451]
  DIRECTION INPUT ;
  USE SIGNAL ;
  PORT
   LAYER M5 ;
   RECT 197.7480 0.2160 197.7960 0.2640 ;
  END
 END wd[451]
 PIN rd[451]
  DIRECTION OUTPUT ;
  USE SIGNAL ;
  PORT
   LAYER M4 ;
   RECT 241.6560 41.7480 241.7040 41.7960 ;
  END
 END rd[451]
 PIN wd[452]
  DIRECTION INPUT ;
  USE SIGNAL ;
  PORT
   LAYER M5 ;
   RECT 197.9880 0.2160 198.0360 0.2640 ;
  END
 END wd[452]
 PIN rd[452]
  DIRECTION OUTPUT ;
  USE SIGNAL ;
  PORT
   LAYER M4 ;
   RECT 241.6560 41.9400 241.7040 41.9880 ;
  END
 END rd[452]
 PIN wd[453]
  DIRECTION INPUT ;
  USE SIGNAL ;
  PORT
   LAYER M5 ;
   RECT 198.2280 0.2160 198.2760 0.2640 ;
  END
 END wd[453]
 PIN rd[453]
  DIRECTION OUTPUT ;
  USE SIGNAL ;
  PORT
   LAYER M4 ;
   RECT 241.6560 42.1320 241.7040 42.1800 ;
  END
 END rd[453]
 PIN wd[454]
  DIRECTION INPUT ;
  USE SIGNAL ;
  PORT
   LAYER M5 ;
   RECT 198.4680 0.2160 198.5160 0.2640 ;
  END
 END wd[454]
 PIN rd[454]
  DIRECTION OUTPUT ;
  USE SIGNAL ;
  PORT
   LAYER M4 ;
   RECT 241.6560 42.3240 241.7040 42.3720 ;
  END
 END rd[454]
 PIN wd[455]
  DIRECTION INPUT ;
  USE SIGNAL ;
  PORT
   LAYER M5 ;
   RECT 198.7080 0.2160 198.7560 0.2640 ;
  END
 END wd[455]
 PIN rd[455]
  DIRECTION OUTPUT ;
  USE SIGNAL ;
  PORT
   LAYER M4 ;
   RECT 241.6560 42.5160 241.7040 42.5640 ;
  END
 END rd[455]
 PIN wd[456]
  DIRECTION INPUT ;
  USE SIGNAL ;
  PORT
   LAYER M5 ;
   RECT 198.9480 0.2160 198.9960 0.2640 ;
  END
 END wd[456]
 PIN rd[456]
  DIRECTION OUTPUT ;
  USE SIGNAL ;
  PORT
   LAYER M4 ;
   RECT 241.6560 42.7080 241.7040 42.7560 ;
  END
 END rd[456]
 PIN wd[457]
  DIRECTION INPUT ;
  USE SIGNAL ;
  PORT
   LAYER M5 ;
   RECT 199.1880 0.2160 199.2360 0.2640 ;
  END
 END wd[457]
 PIN rd[457]
  DIRECTION OUTPUT ;
  USE SIGNAL ;
  PORT
   LAYER M4 ;
   RECT 241.6560 42.9000 241.7040 42.9480 ;
  END
 END rd[457]
 PIN wd[458]
  DIRECTION INPUT ;
  USE SIGNAL ;
  PORT
   LAYER M5 ;
   RECT 199.4280 0.2160 199.4760 0.2640 ;
  END
 END wd[458]
 PIN rd[458]
  DIRECTION OUTPUT ;
  USE SIGNAL ;
  PORT
   LAYER M4 ;
   RECT 241.6560 43.0920 241.7040 43.1400 ;
  END
 END rd[458]
 PIN wd[459]
  DIRECTION INPUT ;
  USE SIGNAL ;
  PORT
   LAYER M5 ;
   RECT 199.6680 0.2160 199.7160 0.2640 ;
  END
 END wd[459]
 PIN rd[459]
  DIRECTION OUTPUT ;
  USE SIGNAL ;
  PORT
   LAYER M4 ;
   RECT 241.6560 43.2840 241.7040 43.3320 ;
  END
 END rd[459]
 PIN wd[460]
  DIRECTION INPUT ;
  USE SIGNAL ;
  PORT
   LAYER M5 ;
   RECT 199.9080 0.2160 199.9560 0.2640 ;
  END
 END wd[460]
 PIN rd[460]
  DIRECTION OUTPUT ;
  USE SIGNAL ;
  PORT
   LAYER M4 ;
   RECT 241.6560 43.4760 241.7040 43.5240 ;
  END
 END rd[460]
 PIN wd[461]
  DIRECTION INPUT ;
  USE SIGNAL ;
  PORT
   LAYER M5 ;
   RECT 200.1480 0.2160 200.1960 0.2640 ;
  END
 END wd[461]
 PIN rd[461]
  DIRECTION OUTPUT ;
  USE SIGNAL ;
  PORT
   LAYER M4 ;
   RECT 241.6560 43.6680 241.7040 43.7160 ;
  END
 END rd[461]
 PIN wd[462]
  DIRECTION INPUT ;
  USE SIGNAL ;
  PORT
   LAYER M5 ;
   RECT 200.3880 0.2160 200.4360 0.2640 ;
  END
 END wd[462]
 PIN rd[462]
  DIRECTION OUTPUT ;
  USE SIGNAL ;
  PORT
   LAYER M4 ;
   RECT 241.6560 43.8600 241.7040 43.9080 ;
  END
 END rd[462]
 PIN wd[463]
  DIRECTION INPUT ;
  USE SIGNAL ;
  PORT
   LAYER M5 ;
   RECT 200.6280 0.2160 200.6760 0.2640 ;
  END
 END wd[463]
 PIN rd[463]
  DIRECTION OUTPUT ;
  USE SIGNAL ;
  PORT
   LAYER M4 ;
   RECT 241.6560 44.0520 241.7040 44.1000 ;
  END
 END rd[463]
 PIN wd[464]
  DIRECTION INPUT ;
  USE SIGNAL ;
  PORT
   LAYER M5 ;
   RECT 200.8680 0.2160 200.9160 0.2640 ;
  END
 END wd[464]
 PIN rd[464]
  DIRECTION OUTPUT ;
  USE SIGNAL ;
  PORT
   LAYER M4 ;
   RECT 241.6560 44.2440 241.7040 44.2920 ;
  END
 END rd[464]
 PIN wd[465]
  DIRECTION INPUT ;
  USE SIGNAL ;
  PORT
   LAYER M5 ;
   RECT 201.1080 0.2160 201.1560 0.2640 ;
  END
 END wd[465]
 PIN rd[465]
  DIRECTION OUTPUT ;
  USE SIGNAL ;
  PORT
   LAYER M4 ;
   RECT 241.6560 44.4360 241.7040 44.4840 ;
  END
 END rd[465]
 PIN wd[466]
  DIRECTION INPUT ;
  USE SIGNAL ;
  PORT
   LAYER M5 ;
   RECT 201.3480 0.2160 201.3960 0.2640 ;
  END
 END wd[466]
 PIN rd[466]
  DIRECTION OUTPUT ;
  USE SIGNAL ;
  PORT
   LAYER M4 ;
   RECT 241.6560 44.6280 241.7040 44.6760 ;
  END
 END rd[466]
 PIN wd[467]
  DIRECTION INPUT ;
  USE SIGNAL ;
  PORT
   LAYER M5 ;
   RECT 201.5880 0.2160 201.6360 0.2640 ;
  END
 END wd[467]
 PIN rd[467]
  DIRECTION OUTPUT ;
  USE SIGNAL ;
  PORT
   LAYER M4 ;
   RECT 241.6560 44.8200 241.7040 44.8680 ;
  END
 END rd[467]
 PIN wd[468]
  DIRECTION INPUT ;
  USE SIGNAL ;
  PORT
   LAYER M5 ;
   RECT 201.8280 0.2160 201.8760 0.2640 ;
  END
 END wd[468]
 PIN rd[468]
  DIRECTION OUTPUT ;
  USE SIGNAL ;
  PORT
   LAYER M4 ;
   RECT 241.6560 45.0120 241.7040 45.0600 ;
  END
 END rd[468]
 PIN wd[469]
  DIRECTION INPUT ;
  USE SIGNAL ;
  PORT
   LAYER M5 ;
   RECT 202.0680 0.2160 202.1160 0.2640 ;
  END
 END wd[469]
 PIN rd[469]
  DIRECTION OUTPUT ;
  USE SIGNAL ;
  PORT
   LAYER M4 ;
   RECT 241.6560 45.2040 241.7040 45.2520 ;
  END
 END rd[469]
 PIN wd[470]
  DIRECTION INPUT ;
  USE SIGNAL ;
  PORT
   LAYER M5 ;
   RECT 202.3080 0.2160 202.3560 0.2640 ;
  END
 END wd[470]
 PIN rd[470]
  DIRECTION OUTPUT ;
  USE SIGNAL ;
  PORT
   LAYER M4 ;
   RECT 241.6560 45.3960 241.7040 45.4440 ;
  END
 END rd[470]
 PIN wd[471]
  DIRECTION INPUT ;
  USE SIGNAL ;
  PORT
   LAYER M5 ;
   RECT 202.5480 0.2160 202.5960 0.2640 ;
  END
 END wd[471]
 PIN rd[471]
  DIRECTION OUTPUT ;
  USE SIGNAL ;
  PORT
   LAYER M4 ;
   RECT 241.6560 45.5880 241.7040 45.6360 ;
  END
 END rd[471]
 PIN wd[472]
  DIRECTION INPUT ;
  USE SIGNAL ;
  PORT
   LAYER M5 ;
   RECT 202.7880 0.2160 202.8360 0.2640 ;
  END
 END wd[472]
 PIN rd[472]
  DIRECTION OUTPUT ;
  USE SIGNAL ;
  PORT
   LAYER M4 ;
   RECT 241.6560 45.7800 241.7040 45.8280 ;
  END
 END rd[472]
 PIN wd[473]
  DIRECTION INPUT ;
  USE SIGNAL ;
  PORT
   LAYER M5 ;
   RECT 203.0280 0.2160 203.0760 0.2640 ;
  END
 END wd[473]
 PIN rd[473]
  DIRECTION OUTPUT ;
  USE SIGNAL ;
  PORT
   LAYER M4 ;
   RECT 241.6560 45.9720 241.7040 46.0200 ;
  END
 END rd[473]
 PIN wd[474]
  DIRECTION INPUT ;
  USE SIGNAL ;
  PORT
   LAYER M5 ;
   RECT 203.2680 0.2160 203.3160 0.2640 ;
  END
 END wd[474]
 PIN rd[474]
  DIRECTION OUTPUT ;
  USE SIGNAL ;
  PORT
   LAYER M4 ;
   RECT 241.6560 46.1640 241.7040 46.2120 ;
  END
 END rd[474]
 PIN wd[475]
  DIRECTION INPUT ;
  USE SIGNAL ;
  PORT
   LAYER M5 ;
   RECT 203.5080 0.2160 203.5560 0.2640 ;
  END
 END wd[475]
 PIN rd[475]
  DIRECTION OUTPUT ;
  USE SIGNAL ;
  PORT
   LAYER M4 ;
   RECT 241.6560 46.3560 241.7040 46.4040 ;
  END
 END rd[475]
 PIN wd[476]
  DIRECTION INPUT ;
  USE SIGNAL ;
  PORT
   LAYER M5 ;
   RECT 203.7480 0.2160 203.7960 0.2640 ;
  END
 END wd[476]
 PIN rd[476]
  DIRECTION OUTPUT ;
  USE SIGNAL ;
  PORT
   LAYER M4 ;
   RECT 241.6560 46.5480 241.7040 46.5960 ;
  END
 END rd[476]
 PIN wd[477]
  DIRECTION INPUT ;
  USE SIGNAL ;
  PORT
   LAYER M5 ;
   RECT 203.9880 0.2160 204.0360 0.2640 ;
  END
 END wd[477]
 PIN rd[477]
  DIRECTION OUTPUT ;
  USE SIGNAL ;
  PORT
   LAYER M4 ;
   RECT 241.6560 46.7400 241.7040 46.7880 ;
  END
 END rd[477]
 PIN wd[478]
  DIRECTION INPUT ;
  USE SIGNAL ;
  PORT
   LAYER M5 ;
   RECT 204.2280 0.2160 204.2760 0.2640 ;
  END
 END wd[478]
 PIN rd[478]
  DIRECTION OUTPUT ;
  USE SIGNAL ;
  PORT
   LAYER M4 ;
   RECT 241.6560 46.9320 241.7040 46.9800 ;
  END
 END rd[478]
 PIN wd[479]
  DIRECTION INPUT ;
  USE SIGNAL ;
  PORT
   LAYER M5 ;
   RECT 204.4680 0.2160 204.5160 0.2640 ;
  END
 END wd[479]
 PIN rd[479]
  DIRECTION OUTPUT ;
  USE SIGNAL ;
  PORT
   LAYER M4 ;
   RECT 241.6560 47.1240 241.7040 47.1720 ;
  END
 END rd[479]
 PIN wd[480]
  DIRECTION INPUT ;
  USE SIGNAL ;
  PORT
   LAYER M5 ;
   RECT 204.7080 0.2160 204.7560 0.2640 ;
  END
 END wd[480]
 PIN rd[480]
  DIRECTION OUTPUT ;
  USE SIGNAL ;
  PORT
   LAYER M4 ;
   RECT 241.6560 47.3160 241.7040 47.3640 ;
  END
 END rd[480]
 PIN wd[481]
  DIRECTION INPUT ;
  USE SIGNAL ;
  PORT
   LAYER M5 ;
   RECT 204.9480 0.2160 204.9960 0.2640 ;
  END
 END wd[481]
 PIN rd[481]
  DIRECTION OUTPUT ;
  USE SIGNAL ;
  PORT
   LAYER M4 ;
   RECT 241.6560 47.5080 241.7040 47.5560 ;
  END
 END rd[481]
 PIN wd[482]
  DIRECTION INPUT ;
  USE SIGNAL ;
  PORT
   LAYER M5 ;
   RECT 205.1880 0.2160 205.2360 0.2640 ;
  END
 END wd[482]
 PIN rd[482]
  DIRECTION OUTPUT ;
  USE SIGNAL ;
  PORT
   LAYER M4 ;
   RECT 241.6560 47.7000 241.7040 47.7480 ;
  END
 END rd[482]
 PIN wd[483]
  DIRECTION INPUT ;
  USE SIGNAL ;
  PORT
   LAYER M5 ;
   RECT 205.4280 0.2160 205.4760 0.2640 ;
  END
 END wd[483]
 PIN rd[483]
  DIRECTION OUTPUT ;
  USE SIGNAL ;
  PORT
   LAYER M4 ;
   RECT 241.6560 47.8920 241.7040 47.9400 ;
  END
 END rd[483]
 PIN wd[484]
  DIRECTION INPUT ;
  USE SIGNAL ;
  PORT
   LAYER M5 ;
   RECT 205.6680 0.2160 205.7160 0.2640 ;
  END
 END wd[484]
 PIN rd[484]
  DIRECTION OUTPUT ;
  USE SIGNAL ;
  PORT
   LAYER M4 ;
   RECT 241.6560 48.0840 241.7040 48.1320 ;
  END
 END rd[484]
 PIN wd[485]
  DIRECTION INPUT ;
  USE SIGNAL ;
  PORT
   LAYER M5 ;
   RECT 205.9080 0.2160 205.9560 0.2640 ;
  END
 END wd[485]
 PIN rd[485]
  DIRECTION OUTPUT ;
  USE SIGNAL ;
  PORT
   LAYER M4 ;
   RECT 241.6560 48.2760 241.7040 48.3240 ;
  END
 END rd[485]
 PIN wd[486]
  DIRECTION INPUT ;
  USE SIGNAL ;
  PORT
   LAYER M5 ;
   RECT 206.1480 0.2160 206.1960 0.2640 ;
  END
 END wd[486]
 PIN rd[486]
  DIRECTION OUTPUT ;
  USE SIGNAL ;
  PORT
   LAYER M4 ;
   RECT 241.6560 48.4680 241.7040 48.5160 ;
  END
 END rd[486]
 PIN wd[487]
  DIRECTION INPUT ;
  USE SIGNAL ;
  PORT
   LAYER M5 ;
   RECT 206.3880 0.2160 206.4360 0.2640 ;
  END
 END wd[487]
 PIN rd[487]
  DIRECTION OUTPUT ;
  USE SIGNAL ;
  PORT
   LAYER M4 ;
   RECT 241.6560 48.6600 241.7040 48.7080 ;
  END
 END rd[487]
 PIN wd[488]
  DIRECTION INPUT ;
  USE SIGNAL ;
  PORT
   LAYER M5 ;
   RECT 206.6280 0.2160 206.6760 0.2640 ;
  END
 END wd[488]
 PIN rd[488]
  DIRECTION OUTPUT ;
  USE SIGNAL ;
  PORT
   LAYER M4 ;
   RECT 241.6560 48.8520 241.7040 48.9000 ;
  END
 END rd[488]
 PIN wd[489]
  DIRECTION INPUT ;
  USE SIGNAL ;
  PORT
   LAYER M5 ;
   RECT 206.8680 0.2160 206.9160 0.2640 ;
  END
 END wd[489]
 PIN rd[489]
  DIRECTION OUTPUT ;
  USE SIGNAL ;
  PORT
   LAYER M4 ;
   RECT 241.6560 49.0440 241.7040 49.0920 ;
  END
 END rd[489]
 PIN wd[490]
  DIRECTION INPUT ;
  USE SIGNAL ;
  PORT
   LAYER M5 ;
   RECT 207.1080 0.2160 207.1560 0.2640 ;
  END
 END wd[490]
 PIN rd[490]
  DIRECTION OUTPUT ;
  USE SIGNAL ;
  PORT
   LAYER M4 ;
   RECT 241.6560 49.2360 241.7040 49.2840 ;
  END
 END rd[490]
 PIN wd[491]
  DIRECTION INPUT ;
  USE SIGNAL ;
  PORT
   LAYER M5 ;
   RECT 207.3480 0.2160 207.3960 0.2640 ;
  END
 END wd[491]
 PIN rd[491]
  DIRECTION OUTPUT ;
  USE SIGNAL ;
  PORT
   LAYER M4 ;
   RECT 241.6560 49.4280 241.7040 49.4760 ;
  END
 END rd[491]
 PIN wd[492]
  DIRECTION INPUT ;
  USE SIGNAL ;
  PORT
   LAYER M5 ;
   RECT 207.5880 0.2160 207.6360 0.2640 ;
  END
 END wd[492]
 PIN rd[492]
  DIRECTION OUTPUT ;
  USE SIGNAL ;
  PORT
   LAYER M4 ;
   RECT 241.6560 49.6200 241.7040 49.6680 ;
  END
 END rd[492]
 PIN wd[493]
  DIRECTION INPUT ;
  USE SIGNAL ;
  PORT
   LAYER M5 ;
   RECT 207.8280 0.2160 207.8760 0.2640 ;
  END
 END wd[493]
 PIN rd[493]
  DIRECTION OUTPUT ;
  USE SIGNAL ;
  PORT
   LAYER M4 ;
   RECT 241.6560 49.8120 241.7040 49.8600 ;
  END
 END rd[493]
 PIN wd[494]
  DIRECTION INPUT ;
  USE SIGNAL ;
  PORT
   LAYER M5 ;
   RECT 208.0680 0.2160 208.1160 0.2640 ;
  END
 END wd[494]
 PIN rd[494]
  DIRECTION OUTPUT ;
  USE SIGNAL ;
  PORT
   LAYER M4 ;
   RECT 241.6560 50.0040 241.7040 50.0520 ;
  END
 END rd[494]
 PIN wd[495]
  DIRECTION INPUT ;
  USE SIGNAL ;
  PORT
   LAYER M5 ;
   RECT 208.3080 0.2160 208.3560 0.2640 ;
  END
 END wd[495]
 PIN rd[495]
  DIRECTION OUTPUT ;
  USE SIGNAL ;
  PORT
   LAYER M4 ;
   RECT 241.6560 50.1960 241.7040 50.2440 ;
  END
 END rd[495]
 PIN wd[496]
  DIRECTION INPUT ;
  USE SIGNAL ;
  PORT
   LAYER M5 ;
   RECT 208.5480 0.2160 208.5960 0.2640 ;
  END
 END wd[496]
 PIN rd[496]
  DIRECTION OUTPUT ;
  USE SIGNAL ;
  PORT
   LAYER M4 ;
   RECT 241.6560 50.3880 241.7040 50.4360 ;
  END
 END rd[496]
 PIN wd[497]
  DIRECTION INPUT ;
  USE SIGNAL ;
  PORT
   LAYER M5 ;
   RECT 208.7880 0.2160 208.8360 0.2640 ;
  END
 END wd[497]
 PIN rd[497]
  DIRECTION OUTPUT ;
  USE SIGNAL ;
  PORT
   LAYER M4 ;
   RECT 241.6560 50.5800 241.7040 50.6280 ;
  END
 END rd[497]
 PIN wd[498]
  DIRECTION INPUT ;
  USE SIGNAL ;
  PORT
   LAYER M5 ;
   RECT 209.0280 0.2160 209.0760 0.2640 ;
  END
 END wd[498]
 PIN rd[498]
  DIRECTION OUTPUT ;
  USE SIGNAL ;
  PORT
   LAYER M4 ;
   RECT 241.6560 50.7720 241.7040 50.8200 ;
  END
 END rd[498]
 PIN wd[499]
  DIRECTION INPUT ;
  USE SIGNAL ;
  PORT
   LAYER M5 ;
   RECT 209.2680 0.2160 209.3160 0.2640 ;
  END
 END wd[499]
 PIN rd[499]
  DIRECTION OUTPUT ;
  USE SIGNAL ;
  PORT
   LAYER M4 ;
   RECT 241.6560 50.9640 241.7040 51.0120 ;
  END
 END rd[499]
 PIN wd[500]
  DIRECTION INPUT ;
  USE SIGNAL ;
  PORT
   LAYER M5 ;
   RECT 209.5080 0.2160 209.5560 0.2640 ;
  END
 END wd[500]
 PIN rd[500]
  DIRECTION OUTPUT ;
  USE SIGNAL ;
  PORT
   LAYER M4 ;
   RECT 241.6560 51.1560 241.7040 51.2040 ;
  END
 END rd[500]
 PIN wd[501]
  DIRECTION INPUT ;
  USE SIGNAL ;
  PORT
   LAYER M5 ;
   RECT 209.7480 0.2160 209.7960 0.2640 ;
  END
 END wd[501]
 PIN rd[501]
  DIRECTION OUTPUT ;
  USE SIGNAL ;
  PORT
   LAYER M4 ;
   RECT 241.6560 51.3480 241.7040 51.3960 ;
  END
 END rd[501]
 PIN wd[502]
  DIRECTION INPUT ;
  USE SIGNAL ;
  PORT
   LAYER M5 ;
   RECT 209.9880 0.2160 210.0360 0.2640 ;
  END
 END wd[502]
 PIN rd[502]
  DIRECTION OUTPUT ;
  USE SIGNAL ;
  PORT
   LAYER M4 ;
   RECT 241.6560 51.5400 241.7040 51.5880 ;
  END
 END rd[502]
 PIN wd[503]
  DIRECTION INPUT ;
  USE SIGNAL ;
  PORT
   LAYER M5 ;
   RECT 210.2280 0.2160 210.2760 0.2640 ;
  END
 END wd[503]
 PIN rd[503]
  DIRECTION OUTPUT ;
  USE SIGNAL ;
  PORT
   LAYER M4 ;
   RECT 241.6560 51.7320 241.7040 51.7800 ;
  END
 END rd[503]
 PIN wd[504]
  DIRECTION INPUT ;
  USE SIGNAL ;
  PORT
   LAYER M5 ;
   RECT 210.4680 0.2160 210.5160 0.2640 ;
  END
 END wd[504]
 PIN rd[504]
  DIRECTION OUTPUT ;
  USE SIGNAL ;
  PORT
   LAYER M4 ;
   RECT 241.6560 51.9240 241.7040 51.9720 ;
  END
 END rd[504]
 PIN wd[505]
  DIRECTION INPUT ;
  USE SIGNAL ;
  PORT
   LAYER M5 ;
   RECT 210.7080 0.2160 210.7560 0.2640 ;
  END
 END wd[505]
 PIN rd[505]
  DIRECTION OUTPUT ;
  USE SIGNAL ;
  PORT
   LAYER M4 ;
   RECT 241.6560 52.1160 241.7040 52.1640 ;
  END
 END rd[505]
 PIN wd[506]
  DIRECTION INPUT ;
  USE SIGNAL ;
  PORT
   LAYER M5 ;
   RECT 210.9480 0.2160 210.9960 0.2640 ;
  END
 END wd[506]
 PIN rd[506]
  DIRECTION OUTPUT ;
  USE SIGNAL ;
  PORT
   LAYER M4 ;
   RECT 241.6560 52.3080 241.7040 52.3560 ;
  END
 END rd[506]
 PIN wd[507]
  DIRECTION INPUT ;
  USE SIGNAL ;
  PORT
   LAYER M5 ;
   RECT 211.1880 0.2160 211.2360 0.2640 ;
  END
 END wd[507]
 PIN rd[507]
  DIRECTION OUTPUT ;
  USE SIGNAL ;
  PORT
   LAYER M4 ;
   RECT 241.6560 52.5000 241.7040 52.5480 ;
  END
 END rd[507]
 PIN wd[508]
  DIRECTION INPUT ;
  USE SIGNAL ;
  PORT
   LAYER M5 ;
   RECT 211.4280 0.2160 211.4760 0.2640 ;
  END
 END wd[508]
 PIN rd[508]
  DIRECTION OUTPUT ;
  USE SIGNAL ;
  PORT
   LAYER M4 ;
   RECT 241.6560 52.6920 241.7040 52.7400 ;
  END
 END rd[508]
 PIN wd[509]
  DIRECTION INPUT ;
  USE SIGNAL ;
  PORT
   LAYER M5 ;
   RECT 211.6680 0.2160 211.7160 0.2640 ;
  END
 END wd[509]
 PIN rd[509]
  DIRECTION OUTPUT ;
  USE SIGNAL ;
  PORT
   LAYER M4 ;
   RECT 241.6560 52.8840 241.7040 52.9320 ;
  END
 END rd[509]
 PIN wd[510]
  DIRECTION INPUT ;
  USE SIGNAL ;
  PORT
   LAYER M5 ;
   RECT 211.9080 0.2160 211.9560 0.2640 ;
  END
 END wd[510]
 PIN rd[510]
  DIRECTION OUTPUT ;
  USE SIGNAL ;
  PORT
   LAYER M4 ;
   RECT 241.6560 53.0760 241.7040 53.1240 ;
  END
 END rd[510]
 PIN wd[511]
  DIRECTION INPUT ;
  USE SIGNAL ;
  PORT
   LAYER M5 ;
   RECT 212.1480 0.2160 212.1960 0.2640 ;
  END
 END wd[511]
 PIN rd[511]
  DIRECTION OUTPUT ;
  USE SIGNAL ;
  PORT
   LAYER M4 ;
   RECT 241.6560 53.2680 241.7040 53.3160 ;
  END
 END rd[511]
 PIN wd[512]
  DIRECTION INPUT ;
  USE SIGNAL ;
  PORT
   LAYER M4 ;
   RECT 0.2160 54.4200 0.2640 54.4680 ;
  END
 END wd[512]
 PIN rd[512]
  DIRECTION OUTPUT ;
  USE SIGNAL ;
  PORT
   LAYER M4 ;
   RECT 0.2160 54.6120 0.2640 54.6600 ;
  END
 END rd[512]
 PIN wd[513]
  DIRECTION INPUT ;
  USE SIGNAL ;
  PORT
   LAYER M4 ;
   RECT 0.2160 54.8040 0.2640 54.8520 ;
  END
 END wd[513]
 PIN rd[513]
  DIRECTION OUTPUT ;
  USE SIGNAL ;
  PORT
   LAYER M4 ;
   RECT 0.2160 54.9960 0.2640 55.0440 ;
  END
 END rd[513]
 PIN wd[514]
  DIRECTION INPUT ;
  USE SIGNAL ;
  PORT
   LAYER M4 ;
   RECT 0.2160 55.1880 0.2640 55.2360 ;
  END
 END wd[514]
 PIN rd[514]
  DIRECTION OUTPUT ;
  USE SIGNAL ;
  PORT
   LAYER M4 ;
   RECT 0.2160 55.3800 0.2640 55.4280 ;
  END
 END rd[514]
 PIN wd[515]
  DIRECTION INPUT ;
  USE SIGNAL ;
  PORT
   LAYER M4 ;
   RECT 0.2160 55.5720 0.2640 55.6200 ;
  END
 END wd[515]
 PIN rd[515]
  DIRECTION OUTPUT ;
  USE SIGNAL ;
  PORT
   LAYER M4 ;
   RECT 0.2160 55.7640 0.2640 55.8120 ;
  END
 END rd[515]
 PIN wd[516]
  DIRECTION INPUT ;
  USE SIGNAL ;
  PORT
   LAYER M4 ;
   RECT 0.2160 55.9560 0.2640 56.0040 ;
  END
 END wd[516]
 PIN rd[516]
  DIRECTION OUTPUT ;
  USE SIGNAL ;
  PORT
   LAYER M4 ;
   RECT 0.2160 56.1480 0.2640 56.1960 ;
  END
 END rd[516]
 PIN wd[517]
  DIRECTION INPUT ;
  USE SIGNAL ;
  PORT
   LAYER M4 ;
   RECT 0.2160 56.3400 0.2640 56.3880 ;
  END
 END wd[517]
 PIN rd[517]
  DIRECTION OUTPUT ;
  USE SIGNAL ;
  PORT
   LAYER M4 ;
   RECT 0.2160 56.5320 0.2640 56.5800 ;
  END
 END rd[517]
 PIN wd[518]
  DIRECTION INPUT ;
  USE SIGNAL ;
  PORT
   LAYER M4 ;
   RECT 0.2160 56.7240 0.2640 56.7720 ;
  END
 END wd[518]
 PIN rd[518]
  DIRECTION OUTPUT ;
  USE SIGNAL ;
  PORT
   LAYER M4 ;
   RECT 0.2160 56.9160 0.2640 56.9640 ;
  END
 END rd[518]
 PIN wd[519]
  DIRECTION INPUT ;
  USE SIGNAL ;
  PORT
   LAYER M4 ;
   RECT 0.2160 57.1080 0.2640 57.1560 ;
  END
 END wd[519]
 PIN rd[519]
  DIRECTION OUTPUT ;
  USE SIGNAL ;
  PORT
   LAYER M4 ;
   RECT 0.2160 57.3000 0.2640 57.3480 ;
  END
 END rd[519]
 PIN wd[520]
  DIRECTION INPUT ;
  USE SIGNAL ;
  PORT
   LAYER M4 ;
   RECT 0.2160 57.4920 0.2640 57.5400 ;
  END
 END wd[520]
 PIN rd[520]
  DIRECTION OUTPUT ;
  USE SIGNAL ;
  PORT
   LAYER M4 ;
   RECT 0.2160 57.6840 0.2640 57.7320 ;
  END
 END rd[520]
 PIN wd[521]
  DIRECTION INPUT ;
  USE SIGNAL ;
  PORT
   LAYER M4 ;
   RECT 0.2160 57.8760 0.2640 57.9240 ;
  END
 END wd[521]
 PIN rd[521]
  DIRECTION OUTPUT ;
  USE SIGNAL ;
  PORT
   LAYER M4 ;
   RECT 0.2160 58.0680 0.2640 58.1160 ;
  END
 END rd[521]
 PIN wd[522]
  DIRECTION INPUT ;
  USE SIGNAL ;
  PORT
   LAYER M4 ;
   RECT 0.2160 58.2600 0.2640 58.3080 ;
  END
 END wd[522]
 PIN rd[522]
  DIRECTION OUTPUT ;
  USE SIGNAL ;
  PORT
   LAYER M4 ;
   RECT 0.2160 58.4520 0.2640 58.5000 ;
  END
 END rd[522]
 PIN wd[523]
  DIRECTION INPUT ;
  USE SIGNAL ;
  PORT
   LAYER M4 ;
   RECT 0.2160 58.6440 0.2640 58.6920 ;
  END
 END wd[523]
 PIN rd[523]
  DIRECTION OUTPUT ;
  USE SIGNAL ;
  PORT
   LAYER M4 ;
   RECT 0.2160 58.8360 0.2640 58.8840 ;
  END
 END rd[523]
 PIN wd[524]
  DIRECTION INPUT ;
  USE SIGNAL ;
  PORT
   LAYER M4 ;
   RECT 0.2160 59.0280 0.2640 59.0760 ;
  END
 END wd[524]
 PIN rd[524]
  DIRECTION OUTPUT ;
  USE SIGNAL ;
  PORT
   LAYER M4 ;
   RECT 0.2160 59.2200 0.2640 59.2680 ;
  END
 END rd[524]
 PIN wd[525]
  DIRECTION INPUT ;
  USE SIGNAL ;
  PORT
   LAYER M4 ;
   RECT 0.2160 59.4120 0.2640 59.4600 ;
  END
 END wd[525]
 PIN rd[525]
  DIRECTION OUTPUT ;
  USE SIGNAL ;
  PORT
   LAYER M4 ;
   RECT 0.2160 59.6040 0.2640 59.6520 ;
  END
 END rd[525]
 PIN wd[526]
  DIRECTION INPUT ;
  USE SIGNAL ;
  PORT
   LAYER M4 ;
   RECT 0.2160 59.7960 0.2640 59.8440 ;
  END
 END wd[526]
 PIN rd[526]
  DIRECTION OUTPUT ;
  USE SIGNAL ;
  PORT
   LAYER M4 ;
   RECT 0.2160 59.9880 0.2640 60.0360 ;
  END
 END rd[526]
 PIN wd[527]
  DIRECTION INPUT ;
  USE SIGNAL ;
  PORT
   LAYER M4 ;
   RECT 0.2160 60.1800 0.2640 60.2280 ;
  END
 END wd[527]
 PIN rd[527]
  DIRECTION OUTPUT ;
  USE SIGNAL ;
  PORT
   LAYER M4 ;
   RECT 0.2160 60.3720 0.2640 60.4200 ;
  END
 END rd[527]
 PIN wd[528]
  DIRECTION INPUT ;
  USE SIGNAL ;
  PORT
   LAYER M4 ;
   RECT 0.2160 60.5640 0.2640 60.6120 ;
  END
 END wd[528]
 PIN rd[528]
  DIRECTION OUTPUT ;
  USE SIGNAL ;
  PORT
   LAYER M4 ;
   RECT 0.2160 60.7560 0.2640 60.8040 ;
  END
 END rd[528]
 PIN wd[529]
  DIRECTION INPUT ;
  USE SIGNAL ;
  PORT
   LAYER M4 ;
   RECT 0.2160 60.9480 0.2640 60.9960 ;
  END
 END wd[529]
 PIN rd[529]
  DIRECTION OUTPUT ;
  USE SIGNAL ;
  PORT
   LAYER M4 ;
   RECT 0.2160 61.1400 0.2640 61.1880 ;
  END
 END rd[529]
 PIN wd[530]
  DIRECTION INPUT ;
  USE SIGNAL ;
  PORT
   LAYER M4 ;
   RECT 0.2160 61.3320 0.2640 61.3800 ;
  END
 END wd[530]
 PIN rd[530]
  DIRECTION OUTPUT ;
  USE SIGNAL ;
  PORT
   LAYER M4 ;
   RECT 0.2160 61.5240 0.2640 61.5720 ;
  END
 END rd[530]
 PIN wd[531]
  DIRECTION INPUT ;
  USE SIGNAL ;
  PORT
   LAYER M4 ;
   RECT 0.2160 61.7160 0.2640 61.7640 ;
  END
 END wd[531]
 PIN rd[531]
  DIRECTION OUTPUT ;
  USE SIGNAL ;
  PORT
   LAYER M4 ;
   RECT 0.2160 61.9080 0.2640 61.9560 ;
  END
 END rd[531]
 PIN wd[532]
  DIRECTION INPUT ;
  USE SIGNAL ;
  PORT
   LAYER M4 ;
   RECT 0.2160 62.1000 0.2640 62.1480 ;
  END
 END wd[532]
 PIN rd[532]
  DIRECTION OUTPUT ;
  USE SIGNAL ;
  PORT
   LAYER M4 ;
   RECT 0.2160 62.2920 0.2640 62.3400 ;
  END
 END rd[532]
 PIN wd[533]
  DIRECTION INPUT ;
  USE SIGNAL ;
  PORT
   LAYER M4 ;
   RECT 0.2160 62.4840 0.2640 62.5320 ;
  END
 END wd[533]
 PIN rd[533]
  DIRECTION OUTPUT ;
  USE SIGNAL ;
  PORT
   LAYER M4 ;
   RECT 0.2160 62.6760 0.2640 62.7240 ;
  END
 END rd[533]
 PIN wd[534]
  DIRECTION INPUT ;
  USE SIGNAL ;
  PORT
   LAYER M4 ;
   RECT 0.2160 62.8680 0.2640 62.9160 ;
  END
 END wd[534]
 PIN rd[534]
  DIRECTION OUTPUT ;
  USE SIGNAL ;
  PORT
   LAYER M4 ;
   RECT 0.2160 63.0600 0.2640 63.1080 ;
  END
 END rd[534]
 PIN wd[535]
  DIRECTION INPUT ;
  USE SIGNAL ;
  PORT
   LAYER M4 ;
   RECT 0.2160 63.2520 0.2640 63.3000 ;
  END
 END wd[535]
 PIN rd[535]
  DIRECTION OUTPUT ;
  USE SIGNAL ;
  PORT
   LAYER M4 ;
   RECT 0.2160 63.4440 0.2640 63.4920 ;
  END
 END rd[535]
 PIN wd[536]
  DIRECTION INPUT ;
  USE SIGNAL ;
  PORT
   LAYER M4 ;
   RECT 0.2160 63.6360 0.2640 63.6840 ;
  END
 END wd[536]
 PIN rd[536]
  DIRECTION OUTPUT ;
  USE SIGNAL ;
  PORT
   LAYER M4 ;
   RECT 0.2160 63.8280 0.2640 63.8760 ;
  END
 END rd[536]
 PIN wd[537]
  DIRECTION INPUT ;
  USE SIGNAL ;
  PORT
   LAYER M4 ;
   RECT 0.2160 64.0200 0.2640 64.0680 ;
  END
 END wd[537]
 PIN rd[537]
  DIRECTION OUTPUT ;
  USE SIGNAL ;
  PORT
   LAYER M4 ;
   RECT 0.2160 64.2120 0.2640 64.2600 ;
  END
 END rd[537]
 PIN wd[538]
  DIRECTION INPUT ;
  USE SIGNAL ;
  PORT
   LAYER M4 ;
   RECT 0.2160 64.4040 0.2640 64.4520 ;
  END
 END wd[538]
 PIN rd[538]
  DIRECTION OUTPUT ;
  USE SIGNAL ;
  PORT
   LAYER M4 ;
   RECT 0.2160 64.5960 0.2640 64.6440 ;
  END
 END rd[538]
 PIN wd[539]
  DIRECTION INPUT ;
  USE SIGNAL ;
  PORT
   LAYER M4 ;
   RECT 0.2160 64.7880 0.2640 64.8360 ;
  END
 END wd[539]
 PIN rd[539]
  DIRECTION OUTPUT ;
  USE SIGNAL ;
  PORT
   LAYER M4 ;
   RECT 0.2160 64.9800 0.2640 65.0280 ;
  END
 END rd[539]
 PIN wd[540]
  DIRECTION INPUT ;
  USE SIGNAL ;
  PORT
   LAYER M4 ;
   RECT 0.2160 65.1720 0.2640 65.2200 ;
  END
 END wd[540]
 PIN rd[540]
  DIRECTION OUTPUT ;
  USE SIGNAL ;
  PORT
   LAYER M4 ;
   RECT 0.2160 65.3640 0.2640 65.4120 ;
  END
 END rd[540]
 PIN wd[541]
  DIRECTION INPUT ;
  USE SIGNAL ;
  PORT
   LAYER M4 ;
   RECT 0.2160 65.5560 0.2640 65.6040 ;
  END
 END wd[541]
 PIN rd[541]
  DIRECTION OUTPUT ;
  USE SIGNAL ;
  PORT
   LAYER M4 ;
   RECT 0.2160 65.7480 0.2640 65.7960 ;
  END
 END rd[541]
 PIN wd[542]
  DIRECTION INPUT ;
  USE SIGNAL ;
  PORT
   LAYER M4 ;
   RECT 0.2160 65.9400 0.2640 65.9880 ;
  END
 END wd[542]
 PIN rd[542]
  DIRECTION OUTPUT ;
  USE SIGNAL ;
  PORT
   LAYER M4 ;
   RECT 0.2160 66.1320 0.2640 66.1800 ;
  END
 END rd[542]
 PIN wd[543]
  DIRECTION INPUT ;
  USE SIGNAL ;
  PORT
   LAYER M4 ;
   RECT 0.2160 66.3240 0.2640 66.3720 ;
  END
 END wd[543]
 PIN rd[543]
  DIRECTION OUTPUT ;
  USE SIGNAL ;
  PORT
   LAYER M4 ;
   RECT 0.2160 66.5160 0.2640 66.5640 ;
  END
 END rd[543]
 PIN wd[544]
  DIRECTION INPUT ;
  USE SIGNAL ;
  PORT
   LAYER M4 ;
   RECT 0.2160 66.7080 0.2640 66.7560 ;
  END
 END wd[544]
 PIN rd[544]
  DIRECTION OUTPUT ;
  USE SIGNAL ;
  PORT
   LAYER M4 ;
   RECT 0.2160 66.9000 0.2640 66.9480 ;
  END
 END rd[544]
 PIN wd[545]
  DIRECTION INPUT ;
  USE SIGNAL ;
  PORT
   LAYER M4 ;
   RECT 0.2160 67.0920 0.2640 67.1400 ;
  END
 END wd[545]
 PIN rd[545]
  DIRECTION OUTPUT ;
  USE SIGNAL ;
  PORT
   LAYER M4 ;
   RECT 0.2160 67.2840 0.2640 67.3320 ;
  END
 END rd[545]
 PIN wd[546]
  DIRECTION INPUT ;
  USE SIGNAL ;
  PORT
   LAYER M4 ;
   RECT 0.2160 67.4760 0.2640 67.5240 ;
  END
 END wd[546]
 PIN rd[546]
  DIRECTION OUTPUT ;
  USE SIGNAL ;
  PORT
   LAYER M4 ;
   RECT 0.2160 67.6680 0.2640 67.7160 ;
  END
 END rd[546]
 PIN wd[547]
  DIRECTION INPUT ;
  USE SIGNAL ;
  PORT
   LAYER M4 ;
   RECT 0.2160 67.8600 0.2640 67.9080 ;
  END
 END wd[547]
 PIN rd[547]
  DIRECTION OUTPUT ;
  USE SIGNAL ;
  PORT
   LAYER M4 ;
   RECT 0.2160 68.0520 0.2640 68.1000 ;
  END
 END rd[547]
 PIN wd[548]
  DIRECTION INPUT ;
  USE SIGNAL ;
  PORT
   LAYER M4 ;
   RECT 0.2160 68.2440 0.2640 68.2920 ;
  END
 END wd[548]
 PIN rd[548]
  DIRECTION OUTPUT ;
  USE SIGNAL ;
  PORT
   LAYER M4 ;
   RECT 0.2160 68.4360 0.2640 68.4840 ;
  END
 END rd[548]
 PIN wd[549]
  DIRECTION INPUT ;
  USE SIGNAL ;
  PORT
   LAYER M4 ;
   RECT 0.2160 68.6280 0.2640 68.6760 ;
  END
 END wd[549]
 PIN rd[549]
  DIRECTION OUTPUT ;
  USE SIGNAL ;
  PORT
   LAYER M4 ;
   RECT 0.2160 68.8200 0.2640 68.8680 ;
  END
 END rd[549]
 PIN wd[550]
  DIRECTION INPUT ;
  USE SIGNAL ;
  PORT
   LAYER M4 ;
   RECT 0.2160 69.0120 0.2640 69.0600 ;
  END
 END wd[550]
 PIN rd[550]
  DIRECTION OUTPUT ;
  USE SIGNAL ;
  PORT
   LAYER M4 ;
   RECT 0.2160 69.2040 0.2640 69.2520 ;
  END
 END rd[550]
 PIN wd[551]
  DIRECTION INPUT ;
  USE SIGNAL ;
  PORT
   LAYER M4 ;
   RECT 0.2160 69.3960 0.2640 69.4440 ;
  END
 END wd[551]
 PIN rd[551]
  DIRECTION OUTPUT ;
  USE SIGNAL ;
  PORT
   LAYER M4 ;
   RECT 0.2160 69.5880 0.2640 69.6360 ;
  END
 END rd[551]
 PIN wd[552]
  DIRECTION INPUT ;
  USE SIGNAL ;
  PORT
   LAYER M4 ;
   RECT 0.2160 69.7800 0.2640 69.8280 ;
  END
 END wd[552]
 PIN rd[552]
  DIRECTION OUTPUT ;
  USE SIGNAL ;
  PORT
   LAYER M4 ;
   RECT 0.2160 69.9720 0.2640 70.0200 ;
  END
 END rd[552]
 PIN wd[553]
  DIRECTION INPUT ;
  USE SIGNAL ;
  PORT
   LAYER M4 ;
   RECT 0.2160 70.1640 0.2640 70.2120 ;
  END
 END wd[553]
 PIN rd[553]
  DIRECTION OUTPUT ;
  USE SIGNAL ;
  PORT
   LAYER M4 ;
   RECT 0.2160 70.3560 0.2640 70.4040 ;
  END
 END rd[553]
 PIN wd[554]
  DIRECTION INPUT ;
  USE SIGNAL ;
  PORT
   LAYER M4 ;
   RECT 0.2160 70.5480 0.2640 70.5960 ;
  END
 END wd[554]
 PIN rd[554]
  DIRECTION OUTPUT ;
  USE SIGNAL ;
  PORT
   LAYER M4 ;
   RECT 0.2160 70.7400 0.2640 70.7880 ;
  END
 END rd[554]
 PIN wd[555]
  DIRECTION INPUT ;
  USE SIGNAL ;
  PORT
   LAYER M4 ;
   RECT 0.2160 70.9320 0.2640 70.9800 ;
  END
 END wd[555]
 PIN rd[555]
  DIRECTION OUTPUT ;
  USE SIGNAL ;
  PORT
   LAYER M4 ;
   RECT 0.2160 71.1240 0.2640 71.1720 ;
  END
 END rd[555]
 PIN wd[556]
  DIRECTION INPUT ;
  USE SIGNAL ;
  PORT
   LAYER M4 ;
   RECT 0.2160 71.3160 0.2640 71.3640 ;
  END
 END wd[556]
 PIN rd[556]
  DIRECTION OUTPUT ;
  USE SIGNAL ;
  PORT
   LAYER M4 ;
   RECT 0.2160 71.5080 0.2640 71.5560 ;
  END
 END rd[556]
 PIN wd[557]
  DIRECTION INPUT ;
  USE SIGNAL ;
  PORT
   LAYER M4 ;
   RECT 0.2160 71.7000 0.2640 71.7480 ;
  END
 END wd[557]
 PIN rd[557]
  DIRECTION OUTPUT ;
  USE SIGNAL ;
  PORT
   LAYER M4 ;
   RECT 0.2160 71.8920 0.2640 71.9400 ;
  END
 END rd[557]
 PIN wd[558]
  DIRECTION INPUT ;
  USE SIGNAL ;
  PORT
   LAYER M4 ;
   RECT 0.2160 72.0840 0.2640 72.1320 ;
  END
 END wd[558]
 PIN rd[558]
  DIRECTION OUTPUT ;
  USE SIGNAL ;
  PORT
   LAYER M4 ;
   RECT 0.2160 72.2760 0.2640 72.3240 ;
  END
 END rd[558]
 PIN wd[559]
  DIRECTION INPUT ;
  USE SIGNAL ;
  PORT
   LAYER M4 ;
   RECT 0.2160 72.4680 0.2640 72.5160 ;
  END
 END wd[559]
 PIN rd[559]
  DIRECTION OUTPUT ;
  USE SIGNAL ;
  PORT
   LAYER M4 ;
   RECT 0.2160 72.6600 0.2640 72.7080 ;
  END
 END rd[559]
 PIN wd[560]
  DIRECTION INPUT ;
  USE SIGNAL ;
  PORT
   LAYER M4 ;
   RECT 0.2160 72.8520 0.2640 72.9000 ;
  END
 END wd[560]
 PIN rd[560]
  DIRECTION OUTPUT ;
  USE SIGNAL ;
  PORT
   LAYER M4 ;
   RECT 0.2160 73.0440 0.2640 73.0920 ;
  END
 END rd[560]
 PIN wd[561]
  DIRECTION INPUT ;
  USE SIGNAL ;
  PORT
   LAYER M4 ;
   RECT 0.2160 73.2360 0.2640 73.2840 ;
  END
 END wd[561]
 PIN rd[561]
  DIRECTION OUTPUT ;
  USE SIGNAL ;
  PORT
   LAYER M4 ;
   RECT 0.2160 73.4280 0.2640 73.4760 ;
  END
 END rd[561]
 PIN wd[562]
  DIRECTION INPUT ;
  USE SIGNAL ;
  PORT
   LAYER M4 ;
   RECT 0.2160 73.6200 0.2640 73.6680 ;
  END
 END wd[562]
 PIN rd[562]
  DIRECTION OUTPUT ;
  USE SIGNAL ;
  PORT
   LAYER M4 ;
   RECT 0.2160 73.8120 0.2640 73.8600 ;
  END
 END rd[562]
 PIN wd[563]
  DIRECTION INPUT ;
  USE SIGNAL ;
  PORT
   LAYER M4 ;
   RECT 0.2160 74.0040 0.2640 74.0520 ;
  END
 END wd[563]
 PIN rd[563]
  DIRECTION OUTPUT ;
  USE SIGNAL ;
  PORT
   LAYER M4 ;
   RECT 0.2160 74.1960 0.2640 74.2440 ;
  END
 END rd[563]
 PIN wd[564]
  DIRECTION INPUT ;
  USE SIGNAL ;
  PORT
   LAYER M4 ;
   RECT 0.2160 74.3880 0.2640 74.4360 ;
  END
 END wd[564]
 PIN rd[564]
  DIRECTION OUTPUT ;
  USE SIGNAL ;
  PORT
   LAYER M4 ;
   RECT 0.2160 74.5800 0.2640 74.6280 ;
  END
 END rd[564]
 PIN wd[565]
  DIRECTION INPUT ;
  USE SIGNAL ;
  PORT
   LAYER M4 ;
   RECT 0.2160 74.7720 0.2640 74.8200 ;
  END
 END wd[565]
 PIN rd[565]
  DIRECTION OUTPUT ;
  USE SIGNAL ;
  PORT
   LAYER M4 ;
   RECT 0.2160 74.9640 0.2640 75.0120 ;
  END
 END rd[565]
 PIN wd[566]
  DIRECTION INPUT ;
  USE SIGNAL ;
  PORT
   LAYER M4 ;
   RECT 0.2160 75.1560 0.2640 75.2040 ;
  END
 END wd[566]
 PIN rd[566]
  DIRECTION OUTPUT ;
  USE SIGNAL ;
  PORT
   LAYER M4 ;
   RECT 0.2160 75.3480 0.2640 75.3960 ;
  END
 END rd[566]
 PIN wd[567]
  DIRECTION INPUT ;
  USE SIGNAL ;
  PORT
   LAYER M4 ;
   RECT 0.2160 75.5400 0.2640 75.5880 ;
  END
 END wd[567]
 PIN rd[567]
  DIRECTION OUTPUT ;
  USE SIGNAL ;
  PORT
   LAYER M4 ;
   RECT 0.2160 75.7320 0.2640 75.7800 ;
  END
 END rd[567]
 PIN wd[568]
  DIRECTION INPUT ;
  USE SIGNAL ;
  PORT
   LAYER M4 ;
   RECT 0.2160 75.9240 0.2640 75.9720 ;
  END
 END wd[568]
 PIN rd[568]
  DIRECTION OUTPUT ;
  USE SIGNAL ;
  PORT
   LAYER M4 ;
   RECT 0.2160 76.1160 0.2640 76.1640 ;
  END
 END rd[568]
 PIN wd[569]
  DIRECTION INPUT ;
  USE SIGNAL ;
  PORT
   LAYER M4 ;
   RECT 0.2160 76.3080 0.2640 76.3560 ;
  END
 END wd[569]
 PIN rd[569]
  DIRECTION OUTPUT ;
  USE SIGNAL ;
  PORT
   LAYER M4 ;
   RECT 0.2160 76.5000 0.2640 76.5480 ;
  END
 END rd[569]
 PIN wd[570]
  DIRECTION INPUT ;
  USE SIGNAL ;
  PORT
   LAYER M4 ;
   RECT 0.2160 76.6920 0.2640 76.7400 ;
  END
 END wd[570]
 PIN rd[570]
  DIRECTION OUTPUT ;
  USE SIGNAL ;
  PORT
   LAYER M4 ;
   RECT 0.2160 76.8840 0.2640 76.9320 ;
  END
 END rd[570]
 PIN wd[571]
  DIRECTION INPUT ;
  USE SIGNAL ;
  PORT
   LAYER M4 ;
   RECT 0.2160 77.0760 0.2640 77.1240 ;
  END
 END wd[571]
 PIN rd[571]
  DIRECTION OUTPUT ;
  USE SIGNAL ;
  PORT
   LAYER M4 ;
   RECT 0.2160 77.2680 0.2640 77.3160 ;
  END
 END rd[571]
 PIN wd[572]
  DIRECTION INPUT ;
  USE SIGNAL ;
  PORT
   LAYER M4 ;
   RECT 0.2160 77.4600 0.2640 77.5080 ;
  END
 END wd[572]
 PIN rd[572]
  DIRECTION OUTPUT ;
  USE SIGNAL ;
  PORT
   LAYER M4 ;
   RECT 0.2160 77.6520 0.2640 77.7000 ;
  END
 END rd[572]
 PIN wd[573]
  DIRECTION INPUT ;
  USE SIGNAL ;
  PORT
   LAYER M4 ;
   RECT 0.2160 77.8440 0.2640 77.8920 ;
  END
 END wd[573]
 PIN rd[573]
  DIRECTION OUTPUT ;
  USE SIGNAL ;
  PORT
   LAYER M4 ;
   RECT 0.2160 78.0360 0.2640 78.0840 ;
  END
 END rd[573]
 PIN wd[574]
  DIRECTION INPUT ;
  USE SIGNAL ;
  PORT
   LAYER M4 ;
   RECT 0.2160 78.2280 0.2640 78.2760 ;
  END
 END wd[574]
 PIN rd[574]
  DIRECTION OUTPUT ;
  USE SIGNAL ;
  PORT
   LAYER M4 ;
   RECT 0.2160 78.4200 0.2640 78.4680 ;
  END
 END rd[574]
 PIN wd[575]
  DIRECTION INPUT ;
  USE SIGNAL ;
  PORT
   LAYER M4 ;
   RECT 0.2160 78.6120 0.2640 78.6600 ;
  END
 END wd[575]
 PIN rd[575]
  DIRECTION OUTPUT ;
  USE SIGNAL ;
  PORT
   LAYER M4 ;
   RECT 0.2160 78.8040 0.2640 78.8520 ;
  END
 END rd[575]
 PIN wd[576]
  DIRECTION INPUT ;
  USE SIGNAL ;
  PORT
   LAYER M4 ;
   RECT 0.2160 78.9960 0.2640 79.0440 ;
  END
 END wd[576]
 PIN rd[576]
  DIRECTION OUTPUT ;
  USE SIGNAL ;
  PORT
   LAYER M4 ;
   RECT 0.2160 79.1880 0.2640 79.2360 ;
  END
 END rd[576]
 PIN wd[577]
  DIRECTION INPUT ;
  USE SIGNAL ;
  PORT
   LAYER M4 ;
   RECT 0.2160 79.3800 0.2640 79.4280 ;
  END
 END wd[577]
 PIN rd[577]
  DIRECTION OUTPUT ;
  USE SIGNAL ;
  PORT
   LAYER M4 ;
   RECT 0.2160 79.5720 0.2640 79.6200 ;
  END
 END rd[577]
 PIN wd[578]
  DIRECTION INPUT ;
  USE SIGNAL ;
  PORT
   LAYER M4 ;
   RECT 0.2160 79.7640 0.2640 79.8120 ;
  END
 END wd[578]
 PIN rd[578]
  DIRECTION OUTPUT ;
  USE SIGNAL ;
  PORT
   LAYER M4 ;
   RECT 0.2160 79.9560 0.2640 80.0040 ;
  END
 END rd[578]
 PIN wd[579]
  DIRECTION INPUT ;
  USE SIGNAL ;
  PORT
   LAYER M4 ;
   RECT 0.2160 80.1480 0.2640 80.1960 ;
  END
 END wd[579]
 PIN rd[579]
  DIRECTION OUTPUT ;
  USE SIGNAL ;
  PORT
   LAYER M4 ;
   RECT 0.2160 80.3400 0.2640 80.3880 ;
  END
 END rd[579]
 PIN wd[580]
  DIRECTION INPUT ;
  USE SIGNAL ;
  PORT
   LAYER M4 ;
   RECT 0.2160 80.5320 0.2640 80.5800 ;
  END
 END wd[580]
 PIN rd[580]
  DIRECTION OUTPUT ;
  USE SIGNAL ;
  PORT
   LAYER M4 ;
   RECT 0.2160 80.7240 0.2640 80.7720 ;
  END
 END rd[580]
 PIN wd[581]
  DIRECTION INPUT ;
  USE SIGNAL ;
  PORT
   LAYER M4 ;
   RECT 0.2160 80.9160 0.2640 80.9640 ;
  END
 END wd[581]
 PIN rd[581]
  DIRECTION OUTPUT ;
  USE SIGNAL ;
  PORT
   LAYER M4 ;
   RECT 0.2160 81.1080 0.2640 81.1560 ;
  END
 END rd[581]
 PIN wd[582]
  DIRECTION INPUT ;
  USE SIGNAL ;
  PORT
   LAYER M4 ;
   RECT 0.2160 81.3000 0.2640 81.3480 ;
  END
 END wd[582]
 PIN rd[582]
  DIRECTION OUTPUT ;
  USE SIGNAL ;
  PORT
   LAYER M4 ;
   RECT 0.2160 81.4920 0.2640 81.5400 ;
  END
 END rd[582]
 PIN wd[583]
  DIRECTION INPUT ;
  USE SIGNAL ;
  PORT
   LAYER M4 ;
   RECT 0.2160 81.6840 0.2640 81.7320 ;
  END
 END wd[583]
 PIN rd[583]
  DIRECTION OUTPUT ;
  USE SIGNAL ;
  PORT
   LAYER M4 ;
   RECT 0.2160 81.8760 0.2640 81.9240 ;
  END
 END rd[583]
 PIN wd[584]
  DIRECTION INPUT ;
  USE SIGNAL ;
  PORT
   LAYER M4 ;
   RECT 0.2160 82.0680 0.2640 82.1160 ;
  END
 END wd[584]
 PIN rd[584]
  DIRECTION OUTPUT ;
  USE SIGNAL ;
  PORT
   LAYER M4 ;
   RECT 0.2160 82.2600 0.2640 82.3080 ;
  END
 END rd[584]
 PIN wd[585]
  DIRECTION INPUT ;
  USE SIGNAL ;
  PORT
   LAYER M4 ;
   RECT 0.2160 82.4520 0.2640 82.5000 ;
  END
 END wd[585]
 PIN rd[585]
  DIRECTION OUTPUT ;
  USE SIGNAL ;
  PORT
   LAYER M4 ;
   RECT 0.2160 82.6440 0.2640 82.6920 ;
  END
 END rd[585]
 PIN wd[586]
  DIRECTION INPUT ;
  USE SIGNAL ;
  PORT
   LAYER M4 ;
   RECT 0.2160 82.8360 0.2640 82.8840 ;
  END
 END wd[586]
 PIN rd[586]
  DIRECTION OUTPUT ;
  USE SIGNAL ;
  PORT
   LAYER M4 ;
   RECT 0.2160 83.0280 0.2640 83.0760 ;
  END
 END rd[586]
 PIN wd[587]
  DIRECTION INPUT ;
  USE SIGNAL ;
  PORT
   LAYER M4 ;
   RECT 0.2160 83.2200 0.2640 83.2680 ;
  END
 END wd[587]
 PIN rd[587]
  DIRECTION OUTPUT ;
  USE SIGNAL ;
  PORT
   LAYER M4 ;
   RECT 0.2160 83.4120 0.2640 83.4600 ;
  END
 END rd[587]
 PIN wd[588]
  DIRECTION INPUT ;
  USE SIGNAL ;
  PORT
   LAYER M4 ;
   RECT 0.2160 83.6040 0.2640 83.6520 ;
  END
 END wd[588]
 PIN rd[588]
  DIRECTION OUTPUT ;
  USE SIGNAL ;
  PORT
   LAYER M4 ;
   RECT 0.2160 83.7960 0.2640 83.8440 ;
  END
 END rd[588]
 PIN wd[589]
  DIRECTION INPUT ;
  USE SIGNAL ;
  PORT
   LAYER M4 ;
   RECT 0.2160 83.9880 0.2640 84.0360 ;
  END
 END wd[589]
 PIN rd[589]
  DIRECTION OUTPUT ;
  USE SIGNAL ;
  PORT
   LAYER M4 ;
   RECT 0.2160 84.1800 0.2640 84.2280 ;
  END
 END rd[589]
 PIN wd[590]
  DIRECTION INPUT ;
  USE SIGNAL ;
  PORT
   LAYER M4 ;
   RECT 0.2160 84.3720 0.2640 84.4200 ;
  END
 END wd[590]
 PIN rd[590]
  DIRECTION OUTPUT ;
  USE SIGNAL ;
  PORT
   LAYER M4 ;
   RECT 0.2160 84.5640 0.2640 84.6120 ;
  END
 END rd[590]
 PIN wd[591]
  DIRECTION INPUT ;
  USE SIGNAL ;
  PORT
   LAYER M4 ;
   RECT 0.2160 84.7560 0.2640 84.8040 ;
  END
 END wd[591]
 PIN rd[591]
  DIRECTION OUTPUT ;
  USE SIGNAL ;
  PORT
   LAYER M4 ;
   RECT 0.2160 84.9480 0.2640 84.9960 ;
  END
 END rd[591]
 PIN wd[592]
  DIRECTION INPUT ;
  USE SIGNAL ;
  PORT
   LAYER M4 ;
   RECT 0.2160 85.1400 0.2640 85.1880 ;
  END
 END wd[592]
 PIN rd[592]
  DIRECTION OUTPUT ;
  USE SIGNAL ;
  PORT
   LAYER M4 ;
   RECT 0.2160 85.3320 0.2640 85.3800 ;
  END
 END rd[592]
 PIN wd[593]
  DIRECTION INPUT ;
  USE SIGNAL ;
  PORT
   LAYER M4 ;
   RECT 0.2160 85.5240 0.2640 85.5720 ;
  END
 END wd[593]
 PIN rd[593]
  DIRECTION OUTPUT ;
  USE SIGNAL ;
  PORT
   LAYER M4 ;
   RECT 0.2160 85.7160 0.2640 85.7640 ;
  END
 END rd[593]
 PIN wd[594]
  DIRECTION INPUT ;
  USE SIGNAL ;
  PORT
   LAYER M4 ;
   RECT 0.2160 85.9080 0.2640 85.9560 ;
  END
 END wd[594]
 PIN rd[594]
  DIRECTION OUTPUT ;
  USE SIGNAL ;
  PORT
   LAYER M4 ;
   RECT 0.2160 86.1000 0.2640 86.1480 ;
  END
 END rd[594]
 PIN wd[595]
  DIRECTION INPUT ;
  USE SIGNAL ;
  PORT
   LAYER M4 ;
   RECT 0.2160 86.2920 0.2640 86.3400 ;
  END
 END wd[595]
 PIN rd[595]
  DIRECTION OUTPUT ;
  USE SIGNAL ;
  PORT
   LAYER M4 ;
   RECT 0.2160 86.4840 0.2640 86.5320 ;
  END
 END rd[595]
 PIN wd[596]
  DIRECTION INPUT ;
  USE SIGNAL ;
  PORT
   LAYER M4 ;
   RECT 0.2160 86.6760 0.2640 86.7240 ;
  END
 END wd[596]
 PIN rd[596]
  DIRECTION OUTPUT ;
  USE SIGNAL ;
  PORT
   LAYER M4 ;
   RECT 0.2160 86.8680 0.2640 86.9160 ;
  END
 END rd[596]
 PIN wd[597]
  DIRECTION INPUT ;
  USE SIGNAL ;
  PORT
   LAYER M4 ;
   RECT 0.2160 87.0600 0.2640 87.1080 ;
  END
 END wd[597]
 PIN rd[597]
  DIRECTION OUTPUT ;
  USE SIGNAL ;
  PORT
   LAYER M4 ;
   RECT 0.2160 87.2520 0.2640 87.3000 ;
  END
 END rd[597]
 PIN wd[598]
  DIRECTION INPUT ;
  USE SIGNAL ;
  PORT
   LAYER M4 ;
   RECT 0.2160 87.4440 0.2640 87.4920 ;
  END
 END wd[598]
 PIN rd[598]
  DIRECTION OUTPUT ;
  USE SIGNAL ;
  PORT
   LAYER M4 ;
   RECT 0.2160 87.6360 0.2640 87.6840 ;
  END
 END rd[598]
 PIN wd[599]
  DIRECTION INPUT ;
  USE SIGNAL ;
  PORT
   LAYER M4 ;
   RECT 0.2160 87.8280 0.2640 87.8760 ;
  END
 END wd[599]
 PIN rd[599]
  DIRECTION OUTPUT ;
  USE SIGNAL ;
  PORT
   LAYER M4 ;
   RECT 0.2160 88.0200 0.2640 88.0680 ;
  END
 END rd[599]
 PIN wd[600]
  DIRECTION INPUT ;
  USE SIGNAL ;
  PORT
   LAYER M4 ;
   RECT 0.2160 88.2120 0.2640 88.2600 ;
  END
 END wd[600]
 PIN rd[600]
  DIRECTION OUTPUT ;
  USE SIGNAL ;
  PORT
   LAYER M4 ;
   RECT 0.2160 88.4040 0.2640 88.4520 ;
  END
 END rd[600]
 PIN wd[601]
  DIRECTION INPUT ;
  USE SIGNAL ;
  PORT
   LAYER M4 ;
   RECT 0.2160 88.5960 0.2640 88.6440 ;
  END
 END wd[601]
 PIN rd[601]
  DIRECTION OUTPUT ;
  USE SIGNAL ;
  PORT
   LAYER M4 ;
   RECT 0.2160 88.7880 0.2640 88.8360 ;
  END
 END rd[601]
 PIN wd[602]
  DIRECTION INPUT ;
  USE SIGNAL ;
  PORT
   LAYER M4 ;
   RECT 0.2160 88.9800 0.2640 89.0280 ;
  END
 END wd[602]
 PIN rd[602]
  DIRECTION OUTPUT ;
  USE SIGNAL ;
  PORT
   LAYER M4 ;
   RECT 0.2160 89.1720 0.2640 89.2200 ;
  END
 END rd[602]
 PIN wd[603]
  DIRECTION INPUT ;
  USE SIGNAL ;
  PORT
   LAYER M4 ;
   RECT 0.2160 89.3640 0.2640 89.4120 ;
  END
 END wd[603]
 PIN rd[603]
  DIRECTION OUTPUT ;
  USE SIGNAL ;
  PORT
   LAYER M4 ;
   RECT 0.2160 89.5560 0.2640 89.6040 ;
  END
 END rd[603]
 PIN wd[604]
  DIRECTION INPUT ;
  USE SIGNAL ;
  PORT
   LAYER M4 ;
   RECT 0.2160 89.7480 0.2640 89.7960 ;
  END
 END wd[604]
 PIN rd[604]
  DIRECTION OUTPUT ;
  USE SIGNAL ;
  PORT
   LAYER M4 ;
   RECT 0.2160 89.9400 0.2640 89.9880 ;
  END
 END rd[604]
 PIN wd[605]
  DIRECTION INPUT ;
  USE SIGNAL ;
  PORT
   LAYER M4 ;
   RECT 0.2160 90.1320 0.2640 90.1800 ;
  END
 END wd[605]
 PIN rd[605]
  DIRECTION OUTPUT ;
  USE SIGNAL ;
  PORT
   LAYER M4 ;
   RECT 0.2160 90.3240 0.2640 90.3720 ;
  END
 END rd[605]
 PIN wd[606]
  DIRECTION INPUT ;
  USE SIGNAL ;
  PORT
   LAYER M4 ;
   RECT 0.2160 90.5160 0.2640 90.5640 ;
  END
 END wd[606]
 PIN rd[606]
  DIRECTION OUTPUT ;
  USE SIGNAL ;
  PORT
   LAYER M4 ;
   RECT 0.2160 90.7080 0.2640 90.7560 ;
  END
 END rd[606]
 PIN wd[607]
  DIRECTION INPUT ;
  USE SIGNAL ;
  PORT
   LAYER M4 ;
   RECT 0.2160 90.9000 0.2640 90.9480 ;
  END
 END wd[607]
 PIN rd[607]
  DIRECTION OUTPUT ;
  USE SIGNAL ;
  PORT
   LAYER M4 ;
   RECT 0.2160 91.0920 0.2640 91.1400 ;
  END
 END rd[607]
 PIN wd[608]
  DIRECTION INPUT ;
  USE SIGNAL ;
  PORT
   LAYER M4 ;
   RECT 0.2160 91.2840 0.2640 91.3320 ;
  END
 END wd[608]
 PIN rd[608]
  DIRECTION OUTPUT ;
  USE SIGNAL ;
  PORT
   LAYER M4 ;
   RECT 0.2160 91.4760 0.2640 91.5240 ;
  END
 END rd[608]
 PIN wd[609]
  DIRECTION INPUT ;
  USE SIGNAL ;
  PORT
   LAYER M4 ;
   RECT 0.2160 91.6680 0.2640 91.7160 ;
  END
 END wd[609]
 PIN rd[609]
  DIRECTION OUTPUT ;
  USE SIGNAL ;
  PORT
   LAYER M4 ;
   RECT 0.2160 91.8600 0.2640 91.9080 ;
  END
 END rd[609]
 PIN wd[610]
  DIRECTION INPUT ;
  USE SIGNAL ;
  PORT
   LAYER M4 ;
   RECT 0.2160 92.0520 0.2640 92.1000 ;
  END
 END wd[610]
 PIN rd[610]
  DIRECTION OUTPUT ;
  USE SIGNAL ;
  PORT
   LAYER M4 ;
   RECT 0.2160 92.2440 0.2640 92.2920 ;
  END
 END rd[610]
 PIN wd[611]
  DIRECTION INPUT ;
  USE SIGNAL ;
  PORT
   LAYER M4 ;
   RECT 0.2160 92.4360 0.2640 92.4840 ;
  END
 END wd[611]
 PIN rd[611]
  DIRECTION OUTPUT ;
  USE SIGNAL ;
  PORT
   LAYER M4 ;
   RECT 0.2160 92.6280 0.2640 92.6760 ;
  END
 END rd[611]
 PIN wd[612]
  DIRECTION INPUT ;
  USE SIGNAL ;
  PORT
   LAYER M4 ;
   RECT 0.2160 92.8200 0.2640 92.8680 ;
  END
 END wd[612]
 PIN rd[612]
  DIRECTION OUTPUT ;
  USE SIGNAL ;
  PORT
   LAYER M4 ;
   RECT 0.2160 93.0120 0.2640 93.0600 ;
  END
 END rd[612]
 PIN wd[613]
  DIRECTION INPUT ;
  USE SIGNAL ;
  PORT
   LAYER M4 ;
   RECT 0.2160 93.2040 0.2640 93.2520 ;
  END
 END wd[613]
 PIN rd[613]
  DIRECTION OUTPUT ;
  USE SIGNAL ;
  PORT
   LAYER M4 ;
   RECT 0.2160 93.3960 0.2640 93.4440 ;
  END
 END rd[613]
 PIN wd[614]
  DIRECTION INPUT ;
  USE SIGNAL ;
  PORT
   LAYER M4 ;
   RECT 0.2160 93.5880 0.2640 93.6360 ;
  END
 END wd[614]
 PIN rd[614]
  DIRECTION OUTPUT ;
  USE SIGNAL ;
  PORT
   LAYER M4 ;
   RECT 0.2160 93.7800 0.2640 93.8280 ;
  END
 END rd[614]
 PIN wd[615]
  DIRECTION INPUT ;
  USE SIGNAL ;
  PORT
   LAYER M4 ;
   RECT 0.2160 93.9720 0.2640 94.0200 ;
  END
 END wd[615]
 PIN rd[615]
  DIRECTION OUTPUT ;
  USE SIGNAL ;
  PORT
   LAYER M4 ;
   RECT 0.2160 94.1640 0.2640 94.2120 ;
  END
 END rd[615]
 PIN wd[616]
  DIRECTION INPUT ;
  USE SIGNAL ;
  PORT
   LAYER M4 ;
   RECT 0.2160 94.3560 0.2640 94.4040 ;
  END
 END wd[616]
 PIN rd[616]
  DIRECTION OUTPUT ;
  USE SIGNAL ;
  PORT
   LAYER M4 ;
   RECT 0.2160 94.5480 0.2640 94.5960 ;
  END
 END rd[616]
 PIN wd[617]
  DIRECTION INPUT ;
  USE SIGNAL ;
  PORT
   LAYER M4 ;
   RECT 0.2160 94.7400 0.2640 94.7880 ;
  END
 END wd[617]
 PIN rd[617]
  DIRECTION OUTPUT ;
  USE SIGNAL ;
  PORT
   LAYER M4 ;
   RECT 0.2160 94.9320 0.2640 94.9800 ;
  END
 END rd[617]
 PIN wd[618]
  DIRECTION INPUT ;
  USE SIGNAL ;
  PORT
   LAYER M4 ;
   RECT 0.2160 95.1240 0.2640 95.1720 ;
  END
 END wd[618]
 PIN rd[618]
  DIRECTION OUTPUT ;
  USE SIGNAL ;
  PORT
   LAYER M4 ;
   RECT 0.2160 95.3160 0.2640 95.3640 ;
  END
 END rd[618]
 PIN wd[619]
  DIRECTION INPUT ;
  USE SIGNAL ;
  PORT
   LAYER M4 ;
   RECT 0.2160 95.5080 0.2640 95.5560 ;
  END
 END wd[619]
 PIN rd[619]
  DIRECTION OUTPUT ;
  USE SIGNAL ;
  PORT
   LAYER M4 ;
   RECT 0.2160 95.7000 0.2640 95.7480 ;
  END
 END rd[619]
 PIN wd[620]
  DIRECTION INPUT ;
  USE SIGNAL ;
  PORT
   LAYER M4 ;
   RECT 0.2160 95.8920 0.2640 95.9400 ;
  END
 END wd[620]
 PIN rd[620]
  DIRECTION OUTPUT ;
  USE SIGNAL ;
  PORT
   LAYER M4 ;
   RECT 0.2160 96.0840 0.2640 96.1320 ;
  END
 END rd[620]
 PIN wd[621]
  DIRECTION INPUT ;
  USE SIGNAL ;
  PORT
   LAYER M4 ;
   RECT 0.2160 96.2760 0.2640 96.3240 ;
  END
 END wd[621]
 PIN rd[621]
  DIRECTION OUTPUT ;
  USE SIGNAL ;
  PORT
   LAYER M4 ;
   RECT 0.2160 96.4680 0.2640 96.5160 ;
  END
 END rd[621]
 PIN wd[622]
  DIRECTION INPUT ;
  USE SIGNAL ;
  PORT
   LAYER M4 ;
   RECT 0.2160 96.6600 0.2640 96.7080 ;
  END
 END wd[622]
 PIN rd[622]
  DIRECTION OUTPUT ;
  USE SIGNAL ;
  PORT
   LAYER M4 ;
   RECT 0.2160 96.8520 0.2640 96.9000 ;
  END
 END rd[622]
 PIN wd[623]
  DIRECTION INPUT ;
  USE SIGNAL ;
  PORT
   LAYER M4 ;
   RECT 0.2160 97.0440 0.2640 97.0920 ;
  END
 END wd[623]
 PIN rd[623]
  DIRECTION OUTPUT ;
  USE SIGNAL ;
  PORT
   LAYER M4 ;
   RECT 0.2160 97.2360 0.2640 97.2840 ;
  END
 END rd[623]
 PIN wd[624]
  DIRECTION INPUT ;
  USE SIGNAL ;
  PORT
   LAYER M4 ;
   RECT 0.2160 97.4280 0.2640 97.4760 ;
  END
 END wd[624]
 PIN rd[624]
  DIRECTION OUTPUT ;
  USE SIGNAL ;
  PORT
   LAYER M4 ;
   RECT 0.2160 97.6200 0.2640 97.6680 ;
  END
 END rd[624]
 PIN wd[625]
  DIRECTION INPUT ;
  USE SIGNAL ;
  PORT
   LAYER M4 ;
   RECT 0.2160 97.8120 0.2640 97.8600 ;
  END
 END wd[625]
 PIN rd[625]
  DIRECTION OUTPUT ;
  USE SIGNAL ;
  PORT
   LAYER M4 ;
   RECT 0.2160 98.0040 0.2640 98.0520 ;
  END
 END rd[625]
 PIN wd[626]
  DIRECTION INPUT ;
  USE SIGNAL ;
  PORT
   LAYER M4 ;
   RECT 0.2160 98.1960 0.2640 98.2440 ;
  END
 END wd[626]
 PIN rd[626]
  DIRECTION OUTPUT ;
  USE SIGNAL ;
  PORT
   LAYER M4 ;
   RECT 0.2160 98.3880 0.2640 98.4360 ;
  END
 END rd[626]
 PIN wd[627]
  DIRECTION INPUT ;
  USE SIGNAL ;
  PORT
   LAYER M4 ;
   RECT 0.2160 98.5800 0.2640 98.6280 ;
  END
 END wd[627]
 PIN rd[627]
  DIRECTION OUTPUT ;
  USE SIGNAL ;
  PORT
   LAYER M4 ;
   RECT 0.2160 98.7720 0.2640 98.8200 ;
  END
 END rd[627]
 PIN wd[628]
  DIRECTION INPUT ;
  USE SIGNAL ;
  PORT
   LAYER M4 ;
   RECT 0.2160 98.9640 0.2640 99.0120 ;
  END
 END wd[628]
 PIN rd[628]
  DIRECTION OUTPUT ;
  USE SIGNAL ;
  PORT
   LAYER M4 ;
   RECT 0.2160 99.1560 0.2640 99.2040 ;
  END
 END rd[628]
 PIN wd[629]
  DIRECTION INPUT ;
  USE SIGNAL ;
  PORT
   LAYER M4 ;
   RECT 0.2160 99.3480 0.2640 99.3960 ;
  END
 END wd[629]
 PIN rd[629]
  DIRECTION OUTPUT ;
  USE SIGNAL ;
  PORT
   LAYER M4 ;
   RECT 0.2160 99.5400 0.2640 99.5880 ;
  END
 END rd[629]
 PIN wd[630]
  DIRECTION INPUT ;
  USE SIGNAL ;
  PORT
   LAYER M4 ;
   RECT 0.2160 99.7320 0.2640 99.7800 ;
  END
 END wd[630]
 PIN rd[630]
  DIRECTION OUTPUT ;
  USE SIGNAL ;
  PORT
   LAYER M4 ;
   RECT 0.2160 99.9240 0.2640 99.9720 ;
  END
 END rd[630]
 PIN wd[631]
  DIRECTION INPUT ;
  USE SIGNAL ;
  PORT
   LAYER M4 ;
   RECT 0.2160 100.1160 0.2640 100.1640 ;
  END
 END wd[631]
 PIN rd[631]
  DIRECTION OUTPUT ;
  USE SIGNAL ;
  PORT
   LAYER M4 ;
   RECT 0.2160 100.3080 0.2640 100.3560 ;
  END
 END rd[631]
 PIN wd[632]
  DIRECTION INPUT ;
  USE SIGNAL ;
  PORT
   LAYER M4 ;
   RECT 0.2160 100.5000 0.2640 100.5480 ;
  END
 END wd[632]
 PIN rd[632]
  DIRECTION OUTPUT ;
  USE SIGNAL ;
  PORT
   LAYER M4 ;
   RECT 0.2160 100.6920 0.2640 100.7400 ;
  END
 END rd[632]
 PIN wd[633]
  DIRECTION INPUT ;
  USE SIGNAL ;
  PORT
   LAYER M4 ;
   RECT 0.2160 100.8840 0.2640 100.9320 ;
  END
 END wd[633]
 PIN rd[633]
  DIRECTION OUTPUT ;
  USE SIGNAL ;
  PORT
   LAYER M4 ;
   RECT 0.2160 101.0760 0.2640 101.1240 ;
  END
 END rd[633]
 PIN wd[634]
  DIRECTION INPUT ;
  USE SIGNAL ;
  PORT
   LAYER M4 ;
   RECT 0.2160 101.2680 0.2640 101.3160 ;
  END
 END wd[634]
 PIN rd[634]
  DIRECTION OUTPUT ;
  USE SIGNAL ;
  PORT
   LAYER M4 ;
   RECT 0.2160 101.4600 0.2640 101.5080 ;
  END
 END rd[634]
 PIN wd[635]
  DIRECTION INPUT ;
  USE SIGNAL ;
  PORT
   LAYER M4 ;
   RECT 0.2160 101.6520 0.2640 101.7000 ;
  END
 END wd[635]
 PIN rd[635]
  DIRECTION OUTPUT ;
  USE SIGNAL ;
  PORT
   LAYER M4 ;
   RECT 0.2160 101.8440 0.2640 101.8920 ;
  END
 END rd[635]
 PIN wd[636]
  DIRECTION INPUT ;
  USE SIGNAL ;
  PORT
   LAYER M4 ;
   RECT 0.2160 102.0360 0.2640 102.0840 ;
  END
 END wd[636]
 PIN rd[636]
  DIRECTION OUTPUT ;
  USE SIGNAL ;
  PORT
   LAYER M4 ;
   RECT 0.2160 102.2280 0.2640 102.2760 ;
  END
 END rd[636]
 PIN wd[637]
  DIRECTION INPUT ;
  USE SIGNAL ;
  PORT
   LAYER M4 ;
   RECT 0.2160 102.4200 0.2640 102.4680 ;
  END
 END wd[637]
 PIN rd[637]
  DIRECTION OUTPUT ;
  USE SIGNAL ;
  PORT
   LAYER M4 ;
   RECT 0.2160 102.6120 0.2640 102.6600 ;
  END
 END rd[637]
 PIN wd[638]
  DIRECTION INPUT ;
  USE SIGNAL ;
  PORT
   LAYER M4 ;
   RECT 0.2160 102.8040 0.2640 102.8520 ;
  END
 END wd[638]
 PIN rd[638]
  DIRECTION OUTPUT ;
  USE SIGNAL ;
  PORT
   LAYER M4 ;
   RECT 0.2160 102.9960 0.2640 103.0440 ;
  END
 END rd[638]
 PIN wd[639]
  DIRECTION INPUT ;
  USE SIGNAL ;
  PORT
   LAYER M4 ;
   RECT 0.2160 103.1880 0.2640 103.2360 ;
  END
 END wd[639]
 PIN rd[639]
  DIRECTION OUTPUT ;
  USE SIGNAL ;
  PORT
   LAYER M4 ;
   RECT 0.2160 103.3800 0.2640 103.4280 ;
  END
 END rd[639]
 PIN wd[640]
  DIRECTION INPUT ;
  USE SIGNAL ;
  PORT
   LAYER M4 ;
   RECT 0.2160 103.5720 0.2640 103.6200 ;
  END
 END wd[640]
 PIN rd[640]
  DIRECTION OUTPUT ;
  USE SIGNAL ;
  PORT
   LAYER M4 ;
   RECT 0.2160 103.7640 0.2640 103.8120 ;
  END
 END rd[640]
 PIN wd[641]
  DIRECTION INPUT ;
  USE SIGNAL ;
  PORT
   LAYER M4 ;
   RECT 0.2160 103.9560 0.2640 104.0040 ;
  END
 END wd[641]
 PIN rd[641]
  DIRECTION OUTPUT ;
  USE SIGNAL ;
  PORT
   LAYER M4 ;
   RECT 0.2160 104.1480 0.2640 104.1960 ;
  END
 END rd[641]
 PIN wd[642]
  DIRECTION INPUT ;
  USE SIGNAL ;
  PORT
   LAYER M4 ;
   RECT 0.2160 104.3400 0.2640 104.3880 ;
  END
 END wd[642]
 PIN rd[642]
  DIRECTION OUTPUT ;
  USE SIGNAL ;
  PORT
   LAYER M4 ;
   RECT 0.2160 104.5320 0.2640 104.5800 ;
  END
 END rd[642]
 PIN wd[643]
  DIRECTION INPUT ;
  USE SIGNAL ;
  PORT
   LAYER M4 ;
   RECT 0.2160 104.7240 0.2640 104.7720 ;
  END
 END wd[643]
 PIN rd[643]
  DIRECTION OUTPUT ;
  USE SIGNAL ;
  PORT
   LAYER M4 ;
   RECT 0.2160 104.9160 0.2640 104.9640 ;
  END
 END rd[643]
 PIN wd[644]
  DIRECTION INPUT ;
  USE SIGNAL ;
  PORT
   LAYER M4 ;
   RECT 0.2160 105.1080 0.2640 105.1560 ;
  END
 END wd[644]
 PIN rd[644]
  DIRECTION OUTPUT ;
  USE SIGNAL ;
  PORT
   LAYER M4 ;
   RECT 0.2160 105.3000 0.2640 105.3480 ;
  END
 END rd[644]
 PIN wd[645]
  DIRECTION INPUT ;
  USE SIGNAL ;
  PORT
   LAYER M4 ;
   RECT 0.2160 105.4920 0.2640 105.5400 ;
  END
 END wd[645]
 PIN rd[645]
  DIRECTION OUTPUT ;
  USE SIGNAL ;
  PORT
   LAYER M4 ;
   RECT 0.2160 105.6840 0.2640 105.7320 ;
  END
 END rd[645]
 PIN wd[646]
  DIRECTION INPUT ;
  USE SIGNAL ;
  PORT
   LAYER M4 ;
   RECT 0.2160 105.8760 0.2640 105.9240 ;
  END
 END wd[646]
 PIN rd[646]
  DIRECTION OUTPUT ;
  USE SIGNAL ;
  PORT
   LAYER M4 ;
   RECT 0.2160 106.0680 0.2640 106.1160 ;
  END
 END rd[646]
 PIN wd[647]
  DIRECTION INPUT ;
  USE SIGNAL ;
  PORT
   LAYER M4 ;
   RECT 0.2160 106.2600 0.2640 106.3080 ;
  END
 END wd[647]
 PIN rd[647]
  DIRECTION OUTPUT ;
  USE SIGNAL ;
  PORT
   LAYER M4 ;
   RECT 0.2160 106.4520 0.2640 106.5000 ;
  END
 END rd[647]
 PIN wd[648]
  DIRECTION INPUT ;
  USE SIGNAL ;
  PORT
   LAYER M4 ;
   RECT 0.2160 106.6440 0.2640 106.6920 ;
  END
 END wd[648]
 PIN rd[648]
  DIRECTION OUTPUT ;
  USE SIGNAL ;
  PORT
   LAYER M4 ;
   RECT 0.2160 106.8360 0.2640 106.8840 ;
  END
 END rd[648]
 PIN wd[649]
  DIRECTION INPUT ;
  USE SIGNAL ;
  PORT
   LAYER M4 ;
   RECT 0.2160 107.0280 0.2640 107.0760 ;
  END
 END wd[649]
 PIN rd[649]
  DIRECTION OUTPUT ;
  USE SIGNAL ;
  PORT
   LAYER M4 ;
   RECT 0.2160 107.2200 0.2640 107.2680 ;
  END
 END rd[649]
 PIN wd[650]
  DIRECTION INPUT ;
  USE SIGNAL ;
  PORT
   LAYER M4 ;
   RECT 0.2160 107.4120 0.2640 107.4600 ;
  END
 END wd[650]
 PIN rd[650]
  DIRECTION OUTPUT ;
  USE SIGNAL ;
  PORT
   LAYER M4 ;
   RECT 0.2160 107.6040 0.2640 107.6520 ;
  END
 END rd[650]
 PIN wd[651]
  DIRECTION INPUT ;
  USE SIGNAL ;
  PORT
   LAYER M4 ;
   RECT 0.2160 107.7960 0.2640 107.8440 ;
  END
 END wd[651]
 PIN rd[651]
  DIRECTION OUTPUT ;
  USE SIGNAL ;
  PORT
   LAYER M4 ;
   RECT 0.2160 107.9880 0.2640 108.0360 ;
  END
 END rd[651]
 PIN wd[652]
  DIRECTION INPUT ;
  USE SIGNAL ;
  PORT
   LAYER M4 ;
   RECT 0.2160 108.1800 0.2640 108.2280 ;
  END
 END wd[652]
 PIN rd[652]
  DIRECTION OUTPUT ;
  USE SIGNAL ;
  PORT
   LAYER M4 ;
   RECT 0.2160 108.3720 0.2640 108.4200 ;
  END
 END rd[652]
 PIN wd[653]
  DIRECTION INPUT ;
  USE SIGNAL ;
  PORT
   LAYER M4 ;
   RECT 0.2160 108.5640 0.2640 108.6120 ;
  END
 END wd[653]
 PIN rd[653]
  DIRECTION OUTPUT ;
  USE SIGNAL ;
  PORT
   LAYER M4 ;
   RECT 0.2160 108.7560 0.2640 108.8040 ;
  END
 END rd[653]
 PIN wd[654]
  DIRECTION INPUT ;
  USE SIGNAL ;
  PORT
   LAYER M4 ;
   RECT 0.2160 108.9480 0.2640 108.9960 ;
  END
 END wd[654]
 PIN rd[654]
  DIRECTION OUTPUT ;
  USE SIGNAL ;
  PORT
   LAYER M4 ;
   RECT 0.2160 109.1400 0.2640 109.1880 ;
  END
 END rd[654]
 PIN wd[655]
  DIRECTION INPUT ;
  USE SIGNAL ;
  PORT
   LAYER M4 ;
   RECT 0.2160 109.3320 0.2640 109.3800 ;
  END
 END wd[655]
 PIN rd[655]
  DIRECTION OUTPUT ;
  USE SIGNAL ;
  PORT
   LAYER M4 ;
   RECT 0.2160 109.5240 0.2640 109.5720 ;
  END
 END rd[655]
 PIN wd[656]
  DIRECTION INPUT ;
  USE SIGNAL ;
  PORT
   LAYER M4 ;
   RECT 0.2160 109.7160 0.2640 109.7640 ;
  END
 END wd[656]
 PIN rd[656]
  DIRECTION OUTPUT ;
  USE SIGNAL ;
  PORT
   LAYER M4 ;
   RECT 0.2160 109.9080 0.2640 109.9560 ;
  END
 END rd[656]
 PIN wd[657]
  DIRECTION INPUT ;
  USE SIGNAL ;
  PORT
   LAYER M4 ;
   RECT 0.2160 110.1000 0.2640 110.1480 ;
  END
 END wd[657]
 PIN rd[657]
  DIRECTION OUTPUT ;
  USE SIGNAL ;
  PORT
   LAYER M4 ;
   RECT 0.2160 110.2920 0.2640 110.3400 ;
  END
 END rd[657]
 PIN wd[658]
  DIRECTION INPUT ;
  USE SIGNAL ;
  PORT
   LAYER M4 ;
   RECT 0.2160 110.4840 0.2640 110.5320 ;
  END
 END wd[658]
 PIN rd[658]
  DIRECTION OUTPUT ;
  USE SIGNAL ;
  PORT
   LAYER M4 ;
   RECT 0.2160 110.6760 0.2640 110.7240 ;
  END
 END rd[658]
 PIN wd[659]
  DIRECTION INPUT ;
  USE SIGNAL ;
  PORT
   LAYER M4 ;
   RECT 0.2160 110.8680 0.2640 110.9160 ;
  END
 END wd[659]
 PIN rd[659]
  DIRECTION OUTPUT ;
  USE SIGNAL ;
  PORT
   LAYER M4 ;
   RECT 0.2160 111.0600 0.2640 111.1080 ;
  END
 END rd[659]
 PIN wd[660]
  DIRECTION INPUT ;
  USE SIGNAL ;
  PORT
   LAYER M4 ;
   RECT 0.2160 111.2520 0.2640 111.3000 ;
  END
 END wd[660]
 PIN rd[660]
  DIRECTION OUTPUT ;
  USE SIGNAL ;
  PORT
   LAYER M4 ;
   RECT 0.2160 111.4440 0.2640 111.4920 ;
  END
 END rd[660]
 PIN wd[661]
  DIRECTION INPUT ;
  USE SIGNAL ;
  PORT
   LAYER M4 ;
   RECT 0.2160 111.6360 0.2640 111.6840 ;
  END
 END wd[661]
 PIN rd[661]
  DIRECTION OUTPUT ;
  USE SIGNAL ;
  PORT
   LAYER M4 ;
   RECT 0.2160 111.8280 0.2640 111.8760 ;
  END
 END rd[661]
 PIN wd[662]
  DIRECTION INPUT ;
  USE SIGNAL ;
  PORT
   LAYER M4 ;
   RECT 0.2160 112.0200 0.2640 112.0680 ;
  END
 END wd[662]
 PIN rd[662]
  DIRECTION OUTPUT ;
  USE SIGNAL ;
  PORT
   LAYER M4 ;
   RECT 0.2160 112.2120 0.2640 112.2600 ;
  END
 END rd[662]
 PIN wd[663]
  DIRECTION INPUT ;
  USE SIGNAL ;
  PORT
   LAYER M4 ;
   RECT 0.2160 112.4040 0.2640 112.4520 ;
  END
 END wd[663]
 PIN rd[663]
  DIRECTION OUTPUT ;
  USE SIGNAL ;
  PORT
   LAYER M4 ;
   RECT 0.2160 112.5960 0.2640 112.6440 ;
  END
 END rd[663]
 PIN wd[664]
  DIRECTION INPUT ;
  USE SIGNAL ;
  PORT
   LAYER M4 ;
   RECT 0.2160 112.7880 0.2640 112.8360 ;
  END
 END wd[664]
 PIN rd[664]
  DIRECTION OUTPUT ;
  USE SIGNAL ;
  PORT
   LAYER M4 ;
   RECT 0.2160 112.9800 0.2640 113.0280 ;
  END
 END rd[664]
 PIN wd[665]
  DIRECTION INPUT ;
  USE SIGNAL ;
  PORT
   LAYER M4 ;
   RECT 0.2160 113.1720 0.2640 113.2200 ;
  END
 END wd[665]
 PIN rd[665]
  DIRECTION OUTPUT ;
  USE SIGNAL ;
  PORT
   LAYER M4 ;
   RECT 0.2160 113.3640 0.2640 113.4120 ;
  END
 END rd[665]
 PIN wd[666]
  DIRECTION INPUT ;
  USE SIGNAL ;
  PORT
   LAYER M4 ;
   RECT 0.2160 113.5560 0.2640 113.6040 ;
  END
 END wd[666]
 PIN rd[666]
  DIRECTION OUTPUT ;
  USE SIGNAL ;
  PORT
   LAYER M4 ;
   RECT 0.2160 113.7480 0.2640 113.7960 ;
  END
 END rd[666]
 PIN wd[667]
  DIRECTION INPUT ;
  USE SIGNAL ;
  PORT
   LAYER M4 ;
   RECT 0.2160 113.9400 0.2640 113.9880 ;
  END
 END wd[667]
 PIN rd[667]
  DIRECTION OUTPUT ;
  USE SIGNAL ;
  PORT
   LAYER M4 ;
   RECT 0.2160 114.1320 0.2640 114.1800 ;
  END
 END rd[667]
 PIN wd[668]
  DIRECTION INPUT ;
  USE SIGNAL ;
  PORT
   LAYER M4 ;
   RECT 0.2160 114.3240 0.2640 114.3720 ;
  END
 END wd[668]
 PIN rd[668]
  DIRECTION OUTPUT ;
  USE SIGNAL ;
  PORT
   LAYER M4 ;
   RECT 0.2160 114.5160 0.2640 114.5640 ;
  END
 END rd[668]
 PIN wd[669]
  DIRECTION INPUT ;
  USE SIGNAL ;
  PORT
   LAYER M4 ;
   RECT 0.2160 114.7080 0.2640 114.7560 ;
  END
 END wd[669]
 PIN rd[669]
  DIRECTION OUTPUT ;
  USE SIGNAL ;
  PORT
   LAYER M4 ;
   RECT 0.2160 114.9000 0.2640 114.9480 ;
  END
 END rd[669]
 PIN wd[670]
  DIRECTION INPUT ;
  USE SIGNAL ;
  PORT
   LAYER M4 ;
   RECT 0.2160 115.0920 0.2640 115.1400 ;
  END
 END wd[670]
 PIN rd[670]
  DIRECTION OUTPUT ;
  USE SIGNAL ;
  PORT
   LAYER M4 ;
   RECT 0.2160 115.2840 0.2640 115.3320 ;
  END
 END rd[670]
 PIN wd[671]
  DIRECTION INPUT ;
  USE SIGNAL ;
  PORT
   LAYER M4 ;
   RECT 0.2160 115.4760 0.2640 115.5240 ;
  END
 END wd[671]
 PIN rd[671]
  DIRECTION OUTPUT ;
  USE SIGNAL ;
  PORT
   LAYER M4 ;
   RECT 0.2160 115.6680 0.2640 115.7160 ;
  END
 END rd[671]
 PIN wd[672]
  DIRECTION INPUT ;
  USE SIGNAL ;
  PORT
   LAYER M4 ;
   RECT 0.2160 115.8600 0.2640 115.9080 ;
  END
 END wd[672]
 PIN rd[672]
  DIRECTION OUTPUT ;
  USE SIGNAL ;
  PORT
   LAYER M4 ;
   RECT 0.2160 116.0520 0.2640 116.1000 ;
  END
 END rd[672]
 PIN wd[673]
  DIRECTION INPUT ;
  USE SIGNAL ;
  PORT
   LAYER M4 ;
   RECT 0.2160 116.2440 0.2640 116.2920 ;
  END
 END wd[673]
 PIN rd[673]
  DIRECTION OUTPUT ;
  USE SIGNAL ;
  PORT
   LAYER M4 ;
   RECT 0.2160 116.4360 0.2640 116.4840 ;
  END
 END rd[673]
 PIN wd[674]
  DIRECTION INPUT ;
  USE SIGNAL ;
  PORT
   LAYER M4 ;
   RECT 0.2160 116.6280 0.2640 116.6760 ;
  END
 END wd[674]
 PIN rd[674]
  DIRECTION OUTPUT ;
  USE SIGNAL ;
  PORT
   LAYER M4 ;
   RECT 0.2160 116.8200 0.2640 116.8680 ;
  END
 END rd[674]
 PIN wd[675]
  DIRECTION INPUT ;
  USE SIGNAL ;
  PORT
   LAYER M4 ;
   RECT 0.2160 117.0120 0.2640 117.0600 ;
  END
 END wd[675]
 PIN rd[675]
  DIRECTION OUTPUT ;
  USE SIGNAL ;
  PORT
   LAYER M4 ;
   RECT 0.2160 117.2040 0.2640 117.2520 ;
  END
 END rd[675]
 PIN wd[676]
  DIRECTION INPUT ;
  USE SIGNAL ;
  PORT
   LAYER M4 ;
   RECT 0.2160 117.3960 0.2640 117.4440 ;
  END
 END wd[676]
 PIN rd[676]
  DIRECTION OUTPUT ;
  USE SIGNAL ;
  PORT
   LAYER M4 ;
   RECT 0.2160 117.5880 0.2640 117.6360 ;
  END
 END rd[676]
 PIN wd[677]
  DIRECTION INPUT ;
  USE SIGNAL ;
  PORT
   LAYER M4 ;
   RECT 0.2160 117.7800 0.2640 117.8280 ;
  END
 END wd[677]
 PIN rd[677]
  DIRECTION OUTPUT ;
  USE SIGNAL ;
  PORT
   LAYER M4 ;
   RECT 0.2160 117.9720 0.2640 118.0200 ;
  END
 END rd[677]
 PIN wd[678]
  DIRECTION INPUT ;
  USE SIGNAL ;
  PORT
   LAYER M4 ;
   RECT 0.2160 118.1640 0.2640 118.2120 ;
  END
 END wd[678]
 PIN rd[678]
  DIRECTION OUTPUT ;
  USE SIGNAL ;
  PORT
   LAYER M4 ;
   RECT 0.2160 118.3560 0.2640 118.4040 ;
  END
 END rd[678]
 PIN wd[679]
  DIRECTION INPUT ;
  USE SIGNAL ;
  PORT
   LAYER M4 ;
   RECT 0.2160 118.5480 0.2640 118.5960 ;
  END
 END wd[679]
 PIN rd[679]
  DIRECTION OUTPUT ;
  USE SIGNAL ;
  PORT
   LAYER M4 ;
   RECT 0.2160 118.7400 0.2640 118.7880 ;
  END
 END rd[679]
 PIN wd[680]
  DIRECTION INPUT ;
  USE SIGNAL ;
  PORT
   LAYER M4 ;
   RECT 0.2160 118.9320 0.2640 118.9800 ;
  END
 END wd[680]
 PIN rd[680]
  DIRECTION OUTPUT ;
  USE SIGNAL ;
  PORT
   LAYER M4 ;
   RECT 0.2160 119.1240 0.2640 119.1720 ;
  END
 END rd[680]
 PIN wd[681]
  DIRECTION INPUT ;
  USE SIGNAL ;
  PORT
   LAYER M4 ;
   RECT 0.2160 119.3160 0.2640 119.3640 ;
  END
 END wd[681]
 PIN rd[681]
  DIRECTION OUTPUT ;
  USE SIGNAL ;
  PORT
   LAYER M4 ;
   RECT 0.2160 119.5080 0.2640 119.5560 ;
  END
 END rd[681]
 PIN wd[682]
  DIRECTION INPUT ;
  USE SIGNAL ;
  PORT
   LAYER M4 ;
   RECT 0.2160 119.7000 0.2640 119.7480 ;
  END
 END wd[682]
 PIN rd[682]
  DIRECTION OUTPUT ;
  USE SIGNAL ;
  PORT
   LAYER M4 ;
   RECT 0.2160 119.8920 0.2640 119.9400 ;
  END
 END rd[682]
 PIN wd[683]
  DIRECTION INPUT ;
  USE SIGNAL ;
  PORT
   LAYER M4 ;
   RECT 0.2160 120.0840 0.2640 120.1320 ;
  END
 END wd[683]
 PIN rd[683]
  DIRECTION OUTPUT ;
  USE SIGNAL ;
  PORT
   LAYER M4 ;
   RECT 0.2160 120.2760 0.2640 120.3240 ;
  END
 END rd[683]
 PIN wd[684]
  DIRECTION INPUT ;
  USE SIGNAL ;
  PORT
   LAYER M4 ;
   RECT 0.2160 120.4680 0.2640 120.5160 ;
  END
 END wd[684]
 PIN rd[684]
  DIRECTION OUTPUT ;
  USE SIGNAL ;
  PORT
   LAYER M4 ;
   RECT 0.2160 120.6600 0.2640 120.7080 ;
  END
 END rd[684]
 PIN wd[685]
  DIRECTION INPUT ;
  USE SIGNAL ;
  PORT
   LAYER M4 ;
   RECT 0.2160 120.8520 0.2640 120.9000 ;
  END
 END wd[685]
 PIN rd[685]
  DIRECTION OUTPUT ;
  USE SIGNAL ;
  PORT
   LAYER M4 ;
   RECT 0.2160 121.0440 0.2640 121.0920 ;
  END
 END rd[685]
 PIN wd[686]
  DIRECTION INPUT ;
  USE SIGNAL ;
  PORT
   LAYER M4 ;
   RECT 0.2160 121.2360 0.2640 121.2840 ;
  END
 END wd[686]
 PIN rd[686]
  DIRECTION OUTPUT ;
  USE SIGNAL ;
  PORT
   LAYER M4 ;
   RECT 0.2160 121.4280 0.2640 121.4760 ;
  END
 END rd[686]
 PIN wd[687]
  DIRECTION INPUT ;
  USE SIGNAL ;
  PORT
   LAYER M4 ;
   RECT 0.2160 121.6200 0.2640 121.6680 ;
  END
 END wd[687]
 PIN rd[687]
  DIRECTION OUTPUT ;
  USE SIGNAL ;
  PORT
   LAYER M4 ;
   RECT 0.2160 121.8120 0.2640 121.8600 ;
  END
 END rd[687]
 PIN wd[688]
  DIRECTION INPUT ;
  USE SIGNAL ;
  PORT
   LAYER M4 ;
   RECT 0.2160 122.0040 0.2640 122.0520 ;
  END
 END wd[688]
 PIN rd[688]
  DIRECTION OUTPUT ;
  USE SIGNAL ;
  PORT
   LAYER M4 ;
   RECT 0.2160 122.1960 0.2640 122.2440 ;
  END
 END rd[688]
 PIN wd[689]
  DIRECTION INPUT ;
  USE SIGNAL ;
  PORT
   LAYER M4 ;
   RECT 0.2160 122.3880 0.2640 122.4360 ;
  END
 END wd[689]
 PIN rd[689]
  DIRECTION OUTPUT ;
  USE SIGNAL ;
  PORT
   LAYER M4 ;
   RECT 0.2160 122.5800 0.2640 122.6280 ;
  END
 END rd[689]
 PIN wd[690]
  DIRECTION INPUT ;
  USE SIGNAL ;
  PORT
   LAYER M4 ;
   RECT 0.2160 122.7720 0.2640 122.8200 ;
  END
 END wd[690]
 PIN rd[690]
  DIRECTION OUTPUT ;
  USE SIGNAL ;
  PORT
   LAYER M4 ;
   RECT 0.2160 122.9640 0.2640 123.0120 ;
  END
 END rd[690]
 PIN wd[691]
  DIRECTION INPUT ;
  USE SIGNAL ;
  PORT
   LAYER M4 ;
   RECT 0.2160 123.1560 0.2640 123.2040 ;
  END
 END wd[691]
 PIN rd[691]
  DIRECTION OUTPUT ;
  USE SIGNAL ;
  PORT
   LAYER M4 ;
   RECT 0.2160 123.3480 0.2640 123.3960 ;
  END
 END rd[691]
 PIN wd[692]
  DIRECTION INPUT ;
  USE SIGNAL ;
  PORT
   LAYER M4 ;
   RECT 0.2160 123.5400 0.2640 123.5880 ;
  END
 END wd[692]
 PIN rd[692]
  DIRECTION OUTPUT ;
  USE SIGNAL ;
  PORT
   LAYER M4 ;
   RECT 0.2160 123.7320 0.2640 123.7800 ;
  END
 END rd[692]
 PIN wd[693]
  DIRECTION INPUT ;
  USE SIGNAL ;
  PORT
   LAYER M4 ;
   RECT 0.2160 123.9240 0.2640 123.9720 ;
  END
 END wd[693]
 PIN rd[693]
  DIRECTION OUTPUT ;
  USE SIGNAL ;
  PORT
   LAYER M4 ;
   RECT 0.2160 124.1160 0.2640 124.1640 ;
  END
 END rd[693]
 PIN wd[694]
  DIRECTION INPUT ;
  USE SIGNAL ;
  PORT
   LAYER M4 ;
   RECT 0.2160 124.3080 0.2640 124.3560 ;
  END
 END wd[694]
 PIN rd[694]
  DIRECTION OUTPUT ;
  USE SIGNAL ;
  PORT
   LAYER M4 ;
   RECT 0.2160 124.5000 0.2640 124.5480 ;
  END
 END rd[694]
 PIN wd[695]
  DIRECTION INPUT ;
  USE SIGNAL ;
  PORT
   LAYER M4 ;
   RECT 0.2160 124.6920 0.2640 124.7400 ;
  END
 END wd[695]
 PIN rd[695]
  DIRECTION OUTPUT ;
  USE SIGNAL ;
  PORT
   LAYER M4 ;
   RECT 0.2160 124.8840 0.2640 124.9320 ;
  END
 END rd[695]
 PIN wd[696]
  DIRECTION INPUT ;
  USE SIGNAL ;
  PORT
   LAYER M4 ;
   RECT 0.2160 125.0760 0.2640 125.1240 ;
  END
 END wd[696]
 PIN rd[696]
  DIRECTION OUTPUT ;
  USE SIGNAL ;
  PORT
   LAYER M4 ;
   RECT 0.2160 125.2680 0.2640 125.3160 ;
  END
 END rd[696]
 PIN wd[697]
  DIRECTION INPUT ;
  USE SIGNAL ;
  PORT
   LAYER M4 ;
   RECT 0.2160 125.4600 0.2640 125.5080 ;
  END
 END wd[697]
 PIN rd[697]
  DIRECTION OUTPUT ;
  USE SIGNAL ;
  PORT
   LAYER M4 ;
   RECT 0.2160 125.6520 0.2640 125.7000 ;
  END
 END rd[697]
 PIN wd[698]
  DIRECTION INPUT ;
  USE SIGNAL ;
  PORT
   LAYER M4 ;
   RECT 0.2160 125.8440 0.2640 125.8920 ;
  END
 END wd[698]
 PIN rd[698]
  DIRECTION OUTPUT ;
  USE SIGNAL ;
  PORT
   LAYER M4 ;
   RECT 0.2160 126.0360 0.2640 126.0840 ;
  END
 END rd[698]
 PIN wd[699]
  DIRECTION INPUT ;
  USE SIGNAL ;
  PORT
   LAYER M4 ;
   RECT 0.2160 126.2280 0.2640 126.2760 ;
  END
 END wd[699]
 PIN rd[699]
  DIRECTION OUTPUT ;
  USE SIGNAL ;
  PORT
   LAYER M4 ;
   RECT 0.2160 126.4200 0.2640 126.4680 ;
  END
 END rd[699]
 PIN wd[700]
  DIRECTION INPUT ;
  USE SIGNAL ;
  PORT
   LAYER M4 ;
   RECT 0.2160 126.6120 0.2640 126.6600 ;
  END
 END wd[700]
 PIN rd[700]
  DIRECTION OUTPUT ;
  USE SIGNAL ;
  PORT
   LAYER M4 ;
   RECT 0.2160 126.8040 0.2640 126.8520 ;
  END
 END rd[700]
 PIN wd[701]
  DIRECTION INPUT ;
  USE SIGNAL ;
  PORT
   LAYER M4 ;
   RECT 0.2160 126.9960 0.2640 127.0440 ;
  END
 END wd[701]
 PIN rd[701]
  DIRECTION OUTPUT ;
  USE SIGNAL ;
  PORT
   LAYER M4 ;
   RECT 0.2160 127.1880 0.2640 127.2360 ;
  END
 END rd[701]
 PIN wd[702]
  DIRECTION INPUT ;
  USE SIGNAL ;
  PORT
   LAYER M4 ;
   RECT 0.2160 127.3800 0.2640 127.4280 ;
  END
 END wd[702]
 PIN rd[702]
  DIRECTION OUTPUT ;
  USE SIGNAL ;
  PORT
   LAYER M4 ;
   RECT 0.2160 127.5720 0.2640 127.6200 ;
  END
 END rd[702]
 PIN wd[703]
  DIRECTION INPUT ;
  USE SIGNAL ;
  PORT
   LAYER M4 ;
   RECT 0.2160 127.7640 0.2640 127.8120 ;
  END
 END wd[703]
 PIN rd[703]
  DIRECTION OUTPUT ;
  USE SIGNAL ;
  PORT
   LAYER M4 ;
   RECT 0.2160 127.9560 0.2640 128.0040 ;
  END
 END rd[703]
 PIN wd[704]
  DIRECTION INPUT ;
  USE SIGNAL ;
  PORT
   LAYER M4 ;
   RECT 0.2160 128.1480 0.2640 128.1960 ;
  END
 END wd[704]
 PIN rd[704]
  DIRECTION OUTPUT ;
  USE SIGNAL ;
  PORT
   LAYER M4 ;
   RECT 0.2160 128.3400 0.2640 128.3880 ;
  END
 END rd[704]
 PIN wd[705]
  DIRECTION INPUT ;
  USE SIGNAL ;
  PORT
   LAYER M4 ;
   RECT 0.2160 128.5320 0.2640 128.5800 ;
  END
 END wd[705]
 PIN rd[705]
  DIRECTION OUTPUT ;
  USE SIGNAL ;
  PORT
   LAYER M4 ;
   RECT 0.2160 128.7240 0.2640 128.7720 ;
  END
 END rd[705]
 PIN wd[706]
  DIRECTION INPUT ;
  USE SIGNAL ;
  PORT
   LAYER M4 ;
   RECT 0.2160 128.9160 0.2640 128.9640 ;
  END
 END wd[706]
 PIN rd[706]
  DIRECTION OUTPUT ;
  USE SIGNAL ;
  PORT
   LAYER M4 ;
   RECT 0.2160 129.1080 0.2640 129.1560 ;
  END
 END rd[706]
 PIN wd[707]
  DIRECTION INPUT ;
  USE SIGNAL ;
  PORT
   LAYER M4 ;
   RECT 0.2160 129.3000 0.2640 129.3480 ;
  END
 END wd[707]
 PIN rd[707]
  DIRECTION OUTPUT ;
  USE SIGNAL ;
  PORT
   LAYER M4 ;
   RECT 0.2160 129.4920 0.2640 129.5400 ;
  END
 END rd[707]
 PIN wd[708]
  DIRECTION INPUT ;
  USE SIGNAL ;
  PORT
   LAYER M4 ;
   RECT 0.2160 129.6840 0.2640 129.7320 ;
  END
 END wd[708]
 PIN rd[708]
  DIRECTION OUTPUT ;
  USE SIGNAL ;
  PORT
   LAYER M4 ;
   RECT 0.2160 129.8760 0.2640 129.9240 ;
  END
 END rd[708]
 PIN wd[709]
  DIRECTION INPUT ;
  USE SIGNAL ;
  PORT
   LAYER M4 ;
   RECT 0.2160 130.0680 0.2640 130.1160 ;
  END
 END wd[709]
 PIN rd[709]
  DIRECTION OUTPUT ;
  USE SIGNAL ;
  PORT
   LAYER M4 ;
   RECT 0.2160 130.2600 0.2640 130.3080 ;
  END
 END rd[709]
 PIN wd[710]
  DIRECTION INPUT ;
  USE SIGNAL ;
  PORT
   LAYER M4 ;
   RECT 0.2160 130.4520 0.2640 130.5000 ;
  END
 END wd[710]
 PIN rd[710]
  DIRECTION OUTPUT ;
  USE SIGNAL ;
  PORT
   LAYER M4 ;
   RECT 0.2160 130.6440 0.2640 130.6920 ;
  END
 END rd[710]
 PIN wd[711]
  DIRECTION INPUT ;
  USE SIGNAL ;
  PORT
   LAYER M4 ;
   RECT 0.2160 130.8360 0.2640 130.8840 ;
  END
 END wd[711]
 PIN rd[711]
  DIRECTION OUTPUT ;
  USE SIGNAL ;
  PORT
   LAYER M4 ;
   RECT 0.2160 131.0280 0.2640 131.0760 ;
  END
 END rd[711]
 PIN wd[712]
  DIRECTION INPUT ;
  USE SIGNAL ;
  PORT
   LAYER M4 ;
   RECT 0.2160 131.2200 0.2640 131.2680 ;
  END
 END wd[712]
 PIN rd[712]
  DIRECTION OUTPUT ;
  USE SIGNAL ;
  PORT
   LAYER M4 ;
   RECT 0.2160 131.4120 0.2640 131.4600 ;
  END
 END rd[712]
 PIN wd[713]
  DIRECTION INPUT ;
  USE SIGNAL ;
  PORT
   LAYER M4 ;
   RECT 0.2160 131.6040 0.2640 131.6520 ;
  END
 END wd[713]
 PIN rd[713]
  DIRECTION OUTPUT ;
  USE SIGNAL ;
  PORT
   LAYER M4 ;
   RECT 0.2160 131.7960 0.2640 131.8440 ;
  END
 END rd[713]
 PIN wd[714]
  DIRECTION INPUT ;
  USE SIGNAL ;
  PORT
   LAYER M4 ;
   RECT 0.2160 131.9880 0.2640 132.0360 ;
  END
 END wd[714]
 PIN rd[714]
  DIRECTION OUTPUT ;
  USE SIGNAL ;
  PORT
   LAYER M4 ;
   RECT 0.2160 132.1800 0.2640 132.2280 ;
  END
 END rd[714]
 PIN wd[715]
  DIRECTION INPUT ;
  USE SIGNAL ;
  PORT
   LAYER M4 ;
   RECT 0.2160 132.3720 0.2640 132.4200 ;
  END
 END wd[715]
 PIN rd[715]
  DIRECTION OUTPUT ;
  USE SIGNAL ;
  PORT
   LAYER M4 ;
   RECT 0.2160 132.5640 0.2640 132.6120 ;
  END
 END rd[715]
 PIN wd[716]
  DIRECTION INPUT ;
  USE SIGNAL ;
  PORT
   LAYER M4 ;
   RECT 0.2160 132.7560 0.2640 132.8040 ;
  END
 END wd[716]
 PIN rd[716]
  DIRECTION OUTPUT ;
  USE SIGNAL ;
  PORT
   LAYER M4 ;
   RECT 0.2160 132.9480 0.2640 132.9960 ;
  END
 END rd[716]
 PIN wd[717]
  DIRECTION INPUT ;
  USE SIGNAL ;
  PORT
   LAYER M4 ;
   RECT 0.2160 133.1400 0.2640 133.1880 ;
  END
 END wd[717]
 PIN rd[717]
  DIRECTION OUTPUT ;
  USE SIGNAL ;
  PORT
   LAYER M4 ;
   RECT 0.2160 133.3320 0.2640 133.3800 ;
  END
 END rd[717]
 PIN wd[718]
  DIRECTION INPUT ;
  USE SIGNAL ;
  PORT
   LAYER M4 ;
   RECT 0.2160 133.5240 0.2640 133.5720 ;
  END
 END wd[718]
 PIN rd[718]
  DIRECTION OUTPUT ;
  USE SIGNAL ;
  PORT
   LAYER M4 ;
   RECT 0.2160 133.7160 0.2640 133.7640 ;
  END
 END rd[718]
 PIN wd[719]
  DIRECTION INPUT ;
  USE SIGNAL ;
  PORT
   LAYER M4 ;
   RECT 0.2160 133.9080 0.2640 133.9560 ;
  END
 END wd[719]
 PIN rd[719]
  DIRECTION OUTPUT ;
  USE SIGNAL ;
  PORT
   LAYER M4 ;
   RECT 0.2160 134.1000 0.2640 134.1480 ;
  END
 END rd[719]
 PIN wd[720]
  DIRECTION INPUT ;
  USE SIGNAL ;
  PORT
   LAYER M4 ;
   RECT 0.2160 134.2920 0.2640 134.3400 ;
  END
 END wd[720]
 PIN rd[720]
  DIRECTION OUTPUT ;
  USE SIGNAL ;
  PORT
   LAYER M4 ;
   RECT 0.2160 134.4840 0.2640 134.5320 ;
  END
 END rd[720]
 PIN wd[721]
  DIRECTION INPUT ;
  USE SIGNAL ;
  PORT
   LAYER M4 ;
   RECT 0.2160 134.6760 0.2640 134.7240 ;
  END
 END wd[721]
 PIN rd[721]
  DIRECTION OUTPUT ;
  USE SIGNAL ;
  PORT
   LAYER M4 ;
   RECT 0.2160 134.8680 0.2640 134.9160 ;
  END
 END rd[721]
 PIN wd[722]
  DIRECTION INPUT ;
  USE SIGNAL ;
  PORT
   LAYER M4 ;
   RECT 0.2160 135.0600 0.2640 135.1080 ;
  END
 END wd[722]
 PIN rd[722]
  DIRECTION OUTPUT ;
  USE SIGNAL ;
  PORT
   LAYER M4 ;
   RECT 0.2160 135.2520 0.2640 135.3000 ;
  END
 END rd[722]
 PIN wd[723]
  DIRECTION INPUT ;
  USE SIGNAL ;
  PORT
   LAYER M4 ;
   RECT 0.2160 135.4440 0.2640 135.4920 ;
  END
 END wd[723]
 PIN rd[723]
  DIRECTION OUTPUT ;
  USE SIGNAL ;
  PORT
   LAYER M4 ;
   RECT 0.2160 135.6360 0.2640 135.6840 ;
  END
 END rd[723]
 PIN wd[724]
  DIRECTION INPUT ;
  USE SIGNAL ;
  PORT
   LAYER M4 ;
   RECT 0.2160 135.8280 0.2640 135.8760 ;
  END
 END wd[724]
 PIN rd[724]
  DIRECTION OUTPUT ;
  USE SIGNAL ;
  PORT
   LAYER M4 ;
   RECT 0.2160 136.0200 0.2640 136.0680 ;
  END
 END rd[724]
 PIN wd[725]
  DIRECTION INPUT ;
  USE SIGNAL ;
  PORT
   LAYER M4 ;
   RECT 0.2160 136.2120 0.2640 136.2600 ;
  END
 END wd[725]
 PIN rd[725]
  DIRECTION OUTPUT ;
  USE SIGNAL ;
  PORT
   LAYER M4 ;
   RECT 0.2160 136.4040 0.2640 136.4520 ;
  END
 END rd[725]
 PIN wd[726]
  DIRECTION INPUT ;
  USE SIGNAL ;
  PORT
   LAYER M4 ;
   RECT 0.2160 136.5960 0.2640 136.6440 ;
  END
 END wd[726]
 PIN rd[726]
  DIRECTION OUTPUT ;
  USE SIGNAL ;
  PORT
   LAYER M4 ;
   RECT 0.2160 136.7880 0.2640 136.8360 ;
  END
 END rd[726]
 PIN wd[727]
  DIRECTION INPUT ;
  USE SIGNAL ;
  PORT
   LAYER M4 ;
   RECT 0.2160 136.9800 0.2640 137.0280 ;
  END
 END wd[727]
 PIN rd[727]
  DIRECTION OUTPUT ;
  USE SIGNAL ;
  PORT
   LAYER M4 ;
   RECT 0.2160 137.1720 0.2640 137.2200 ;
  END
 END rd[727]
 PIN wd[728]
  DIRECTION INPUT ;
  USE SIGNAL ;
  PORT
   LAYER M4 ;
   RECT 0.2160 137.3640 0.2640 137.4120 ;
  END
 END wd[728]
 PIN rd[728]
  DIRECTION OUTPUT ;
  USE SIGNAL ;
  PORT
   LAYER M4 ;
   RECT 0.2160 137.5560 0.2640 137.6040 ;
  END
 END rd[728]
 PIN wd[729]
  DIRECTION INPUT ;
  USE SIGNAL ;
  PORT
   LAYER M4 ;
   RECT 0.2160 137.7480 0.2640 137.7960 ;
  END
 END wd[729]
 PIN rd[729]
  DIRECTION OUTPUT ;
  USE SIGNAL ;
  PORT
   LAYER M4 ;
   RECT 0.2160 137.9400 0.2640 137.9880 ;
  END
 END rd[729]
 PIN wd[730]
  DIRECTION INPUT ;
  USE SIGNAL ;
  PORT
   LAYER M4 ;
   RECT 0.2160 138.1320 0.2640 138.1800 ;
  END
 END wd[730]
 PIN rd[730]
  DIRECTION OUTPUT ;
  USE SIGNAL ;
  PORT
   LAYER M4 ;
   RECT 0.2160 138.3240 0.2640 138.3720 ;
  END
 END rd[730]
 PIN wd[731]
  DIRECTION INPUT ;
  USE SIGNAL ;
  PORT
   LAYER M4 ;
   RECT 0.2160 138.5160 0.2640 138.5640 ;
  END
 END wd[731]
 PIN rd[731]
  DIRECTION OUTPUT ;
  USE SIGNAL ;
  PORT
   LAYER M4 ;
   RECT 0.2160 138.7080 0.2640 138.7560 ;
  END
 END rd[731]
 PIN wd[732]
  DIRECTION INPUT ;
  USE SIGNAL ;
  PORT
   LAYER M4 ;
   RECT 0.2160 138.9000 0.2640 138.9480 ;
  END
 END wd[732]
 PIN rd[732]
  DIRECTION OUTPUT ;
  USE SIGNAL ;
  PORT
   LAYER M4 ;
   RECT 0.2160 139.0920 0.2640 139.1400 ;
  END
 END rd[732]
 PIN wd[733]
  DIRECTION INPUT ;
  USE SIGNAL ;
  PORT
   LAYER M4 ;
   RECT 0.2160 139.2840 0.2640 139.3320 ;
  END
 END wd[733]
 PIN rd[733]
  DIRECTION OUTPUT ;
  USE SIGNAL ;
  PORT
   LAYER M4 ;
   RECT 0.2160 139.4760 0.2640 139.5240 ;
  END
 END rd[733]
 PIN wd[734]
  DIRECTION INPUT ;
  USE SIGNAL ;
  PORT
   LAYER M4 ;
   RECT 0.2160 139.6680 0.2640 139.7160 ;
  END
 END wd[734]
 PIN rd[734]
  DIRECTION OUTPUT ;
  USE SIGNAL ;
  PORT
   LAYER M4 ;
   RECT 0.2160 139.8600 0.2640 139.9080 ;
  END
 END rd[734]
 PIN wd[735]
  DIRECTION INPUT ;
  USE SIGNAL ;
  PORT
   LAYER M4 ;
   RECT 0.2160 140.0520 0.2640 140.1000 ;
  END
 END wd[735]
 PIN rd[735]
  DIRECTION OUTPUT ;
  USE SIGNAL ;
  PORT
   LAYER M4 ;
   RECT 0.2160 140.2440 0.2640 140.2920 ;
  END
 END rd[735]
 PIN wd[736]
  DIRECTION INPUT ;
  USE SIGNAL ;
  PORT
   LAYER M4 ;
   RECT 0.2160 140.4360 0.2640 140.4840 ;
  END
 END wd[736]
 PIN rd[736]
  DIRECTION OUTPUT ;
  USE SIGNAL ;
  PORT
   LAYER M4 ;
   RECT 0.2160 140.6280 0.2640 140.6760 ;
  END
 END rd[736]
 PIN wd[737]
  DIRECTION INPUT ;
  USE SIGNAL ;
  PORT
   LAYER M4 ;
   RECT 0.2160 140.8200 0.2640 140.8680 ;
  END
 END wd[737]
 PIN rd[737]
  DIRECTION OUTPUT ;
  USE SIGNAL ;
  PORT
   LAYER M4 ;
   RECT 0.2160 141.0120 0.2640 141.0600 ;
  END
 END rd[737]
 PIN wd[738]
  DIRECTION INPUT ;
  USE SIGNAL ;
  PORT
   LAYER M4 ;
   RECT 0.2160 141.2040 0.2640 141.2520 ;
  END
 END wd[738]
 PIN rd[738]
  DIRECTION OUTPUT ;
  USE SIGNAL ;
  PORT
   LAYER M4 ;
   RECT 0.2160 141.3960 0.2640 141.4440 ;
  END
 END rd[738]
 PIN wd[739]
  DIRECTION INPUT ;
  USE SIGNAL ;
  PORT
   LAYER M4 ;
   RECT 0.2160 141.5880 0.2640 141.6360 ;
  END
 END wd[739]
 PIN rd[739]
  DIRECTION OUTPUT ;
  USE SIGNAL ;
  PORT
   LAYER M4 ;
   RECT 0.2160 141.7800 0.2640 141.8280 ;
  END
 END rd[739]
 PIN wd[740]
  DIRECTION INPUT ;
  USE SIGNAL ;
  PORT
   LAYER M4 ;
   RECT 0.2160 141.9720 0.2640 142.0200 ;
  END
 END wd[740]
 PIN rd[740]
  DIRECTION OUTPUT ;
  USE SIGNAL ;
  PORT
   LAYER M4 ;
   RECT 0.2160 142.1640 0.2640 142.2120 ;
  END
 END rd[740]
 PIN wd[741]
  DIRECTION INPUT ;
  USE SIGNAL ;
  PORT
   LAYER M4 ;
   RECT 0.2160 142.3560 0.2640 142.4040 ;
  END
 END wd[741]
 PIN rd[741]
  DIRECTION OUTPUT ;
  USE SIGNAL ;
  PORT
   LAYER M4 ;
   RECT 0.2160 142.5480 0.2640 142.5960 ;
  END
 END rd[741]
 PIN wd[742]
  DIRECTION INPUT ;
  USE SIGNAL ;
  PORT
   LAYER M4 ;
   RECT 0.2160 142.7400 0.2640 142.7880 ;
  END
 END wd[742]
 PIN rd[742]
  DIRECTION OUTPUT ;
  USE SIGNAL ;
  PORT
   LAYER M4 ;
   RECT 0.2160 142.9320 0.2640 142.9800 ;
  END
 END rd[742]
 PIN wd[743]
  DIRECTION INPUT ;
  USE SIGNAL ;
  PORT
   LAYER M4 ;
   RECT 0.2160 143.1240 0.2640 143.1720 ;
  END
 END wd[743]
 PIN rd[743]
  DIRECTION OUTPUT ;
  USE SIGNAL ;
  PORT
   LAYER M4 ;
   RECT 0.2160 143.3160 0.2640 143.3640 ;
  END
 END rd[743]
 PIN wd[744]
  DIRECTION INPUT ;
  USE SIGNAL ;
  PORT
   LAYER M4 ;
   RECT 0.2160 143.5080 0.2640 143.5560 ;
  END
 END wd[744]
 PIN rd[744]
  DIRECTION OUTPUT ;
  USE SIGNAL ;
  PORT
   LAYER M4 ;
   RECT 0.2160 143.7000 0.2640 143.7480 ;
  END
 END rd[744]
 PIN wd[745]
  DIRECTION INPUT ;
  USE SIGNAL ;
  PORT
   LAYER M4 ;
   RECT 0.2160 143.8920 0.2640 143.9400 ;
  END
 END wd[745]
 PIN rd[745]
  DIRECTION OUTPUT ;
  USE SIGNAL ;
  PORT
   LAYER M4 ;
   RECT 0.2160 144.0840 0.2640 144.1320 ;
  END
 END rd[745]
 PIN wd[746]
  DIRECTION INPUT ;
  USE SIGNAL ;
  PORT
   LAYER M4 ;
   RECT 0.2160 144.2760 0.2640 144.3240 ;
  END
 END wd[746]
 PIN rd[746]
  DIRECTION OUTPUT ;
  USE SIGNAL ;
  PORT
   LAYER M4 ;
   RECT 0.2160 144.4680 0.2640 144.5160 ;
  END
 END rd[746]
 PIN wd[747]
  DIRECTION INPUT ;
  USE SIGNAL ;
  PORT
   LAYER M4 ;
   RECT 0.2160 144.6600 0.2640 144.7080 ;
  END
 END wd[747]
 PIN rd[747]
  DIRECTION OUTPUT ;
  USE SIGNAL ;
  PORT
   LAYER M4 ;
   RECT 0.2160 144.8520 0.2640 144.9000 ;
  END
 END rd[747]
 PIN wd[748]
  DIRECTION INPUT ;
  USE SIGNAL ;
  PORT
   LAYER M4 ;
   RECT 0.2160 145.0440 0.2640 145.0920 ;
  END
 END wd[748]
 PIN rd[748]
  DIRECTION OUTPUT ;
  USE SIGNAL ;
  PORT
   LAYER M4 ;
   RECT 0.2160 145.2360 0.2640 145.2840 ;
  END
 END rd[748]
 PIN wd[749]
  DIRECTION INPUT ;
  USE SIGNAL ;
  PORT
   LAYER M4 ;
   RECT 0.2160 145.4280 0.2640 145.4760 ;
  END
 END wd[749]
 PIN rd[749]
  DIRECTION OUTPUT ;
  USE SIGNAL ;
  PORT
   LAYER M4 ;
   RECT 0.2160 145.6200 0.2640 145.6680 ;
  END
 END rd[749]
 PIN wd[750]
  DIRECTION INPUT ;
  USE SIGNAL ;
  PORT
   LAYER M4 ;
   RECT 0.2160 145.8120 0.2640 145.8600 ;
  END
 END wd[750]
 PIN rd[750]
  DIRECTION OUTPUT ;
  USE SIGNAL ;
  PORT
   LAYER M4 ;
   RECT 0.2160 146.0040 0.2640 146.0520 ;
  END
 END rd[750]
 PIN wd[751]
  DIRECTION INPUT ;
  USE SIGNAL ;
  PORT
   LAYER M4 ;
   RECT 0.2160 146.1960 0.2640 146.2440 ;
  END
 END wd[751]
 PIN rd[751]
  DIRECTION OUTPUT ;
  USE SIGNAL ;
  PORT
   LAYER M4 ;
   RECT 0.2160 146.3880 0.2640 146.4360 ;
  END
 END rd[751]
 PIN wd[752]
  DIRECTION INPUT ;
  USE SIGNAL ;
  PORT
   LAYER M4 ;
   RECT 0.2160 146.5800 0.2640 146.6280 ;
  END
 END wd[752]
 PIN rd[752]
  DIRECTION OUTPUT ;
  USE SIGNAL ;
  PORT
   LAYER M4 ;
   RECT 0.2160 146.7720 0.2640 146.8200 ;
  END
 END rd[752]
 PIN wd[753]
  DIRECTION INPUT ;
  USE SIGNAL ;
  PORT
   LAYER M4 ;
   RECT 0.2160 146.9640 0.2640 147.0120 ;
  END
 END wd[753]
 PIN rd[753]
  DIRECTION OUTPUT ;
  USE SIGNAL ;
  PORT
   LAYER M4 ;
   RECT 0.2160 147.1560 0.2640 147.2040 ;
  END
 END rd[753]
 PIN wd[754]
  DIRECTION INPUT ;
  USE SIGNAL ;
  PORT
   LAYER M4 ;
   RECT 0.2160 147.3480 0.2640 147.3960 ;
  END
 END wd[754]
 PIN rd[754]
  DIRECTION OUTPUT ;
  USE SIGNAL ;
  PORT
   LAYER M4 ;
   RECT 0.2160 147.5400 0.2640 147.5880 ;
  END
 END rd[754]
 PIN wd[755]
  DIRECTION INPUT ;
  USE SIGNAL ;
  PORT
   LAYER M4 ;
   RECT 0.2160 147.7320 0.2640 147.7800 ;
  END
 END wd[755]
 PIN rd[755]
  DIRECTION OUTPUT ;
  USE SIGNAL ;
  PORT
   LAYER M4 ;
   RECT 0.2160 147.9240 0.2640 147.9720 ;
  END
 END rd[755]
 PIN wd[756]
  DIRECTION INPUT ;
  USE SIGNAL ;
  PORT
   LAYER M4 ;
   RECT 0.2160 148.1160 0.2640 148.1640 ;
  END
 END wd[756]
 PIN rd[756]
  DIRECTION OUTPUT ;
  USE SIGNAL ;
  PORT
   LAYER M4 ;
   RECT 0.2160 148.3080 0.2640 148.3560 ;
  END
 END rd[756]
 PIN wd[757]
  DIRECTION INPUT ;
  USE SIGNAL ;
  PORT
   LAYER M4 ;
   RECT 0.2160 148.5000 0.2640 148.5480 ;
  END
 END wd[757]
 PIN rd[757]
  DIRECTION OUTPUT ;
  USE SIGNAL ;
  PORT
   LAYER M4 ;
   RECT 0.2160 148.6920 0.2640 148.7400 ;
  END
 END rd[757]
 PIN wd[758]
  DIRECTION INPUT ;
  USE SIGNAL ;
  PORT
   LAYER M4 ;
   RECT 0.2160 148.8840 0.2640 148.9320 ;
  END
 END wd[758]
 PIN rd[758]
  DIRECTION OUTPUT ;
  USE SIGNAL ;
  PORT
   LAYER M4 ;
   RECT 0.2160 149.0760 0.2640 149.1240 ;
  END
 END rd[758]
 PIN wd[759]
  DIRECTION INPUT ;
  USE SIGNAL ;
  PORT
   LAYER M4 ;
   RECT 0.2160 149.2680 0.2640 149.3160 ;
  END
 END wd[759]
 PIN rd[759]
  DIRECTION OUTPUT ;
  USE SIGNAL ;
  PORT
   LAYER M4 ;
   RECT 0.2160 149.4600 0.2640 149.5080 ;
  END
 END rd[759]
 PIN wd[760]
  DIRECTION INPUT ;
  USE SIGNAL ;
  PORT
   LAYER M4 ;
   RECT 0.2160 149.6520 0.2640 149.7000 ;
  END
 END wd[760]
 PIN rd[760]
  DIRECTION OUTPUT ;
  USE SIGNAL ;
  PORT
   LAYER M4 ;
   RECT 0.2160 149.8440 0.2640 149.8920 ;
  END
 END rd[760]
 PIN wd[761]
  DIRECTION INPUT ;
  USE SIGNAL ;
  PORT
   LAYER M4 ;
   RECT 0.2160 150.0360 0.2640 150.0840 ;
  END
 END wd[761]
 PIN rd[761]
  DIRECTION OUTPUT ;
  USE SIGNAL ;
  PORT
   LAYER M4 ;
   RECT 0.2160 150.2280 0.2640 150.2760 ;
  END
 END rd[761]
 PIN wd[762]
  DIRECTION INPUT ;
  USE SIGNAL ;
  PORT
   LAYER M4 ;
   RECT 0.2160 150.4200 0.2640 150.4680 ;
  END
 END wd[762]
 PIN rd[762]
  DIRECTION OUTPUT ;
  USE SIGNAL ;
  PORT
   LAYER M4 ;
   RECT 0.2160 150.6120 0.2640 150.6600 ;
  END
 END rd[762]
 PIN wd[763]
  DIRECTION INPUT ;
  USE SIGNAL ;
  PORT
   LAYER M4 ;
   RECT 0.2160 150.8040 0.2640 150.8520 ;
  END
 END wd[763]
 PIN rd[763]
  DIRECTION OUTPUT ;
  USE SIGNAL ;
  PORT
   LAYER M4 ;
   RECT 0.2160 150.9960 0.2640 151.0440 ;
  END
 END rd[763]
 PIN wd[764]
  DIRECTION INPUT ;
  USE SIGNAL ;
  PORT
   LAYER M4 ;
   RECT 0.2160 151.1880 0.2640 151.2360 ;
  END
 END wd[764]
 PIN rd[764]
  DIRECTION OUTPUT ;
  USE SIGNAL ;
  PORT
   LAYER M4 ;
   RECT 0.2160 151.3800 0.2640 151.4280 ;
  END
 END rd[764]
 PIN wd[765]
  DIRECTION INPUT ;
  USE SIGNAL ;
  PORT
   LAYER M4 ;
   RECT 0.2160 151.5720 0.2640 151.6200 ;
  END
 END wd[765]
 PIN rd[765]
  DIRECTION OUTPUT ;
  USE SIGNAL ;
  PORT
   LAYER M4 ;
   RECT 0.2160 151.7640 0.2640 151.8120 ;
  END
 END rd[765]
 PIN wd[766]
  DIRECTION INPUT ;
  USE SIGNAL ;
  PORT
   LAYER M4 ;
   RECT 0.2160 151.9560 0.2640 152.0040 ;
  END
 END wd[766]
 PIN rd[766]
  DIRECTION OUTPUT ;
  USE SIGNAL ;
  PORT
   LAYER M4 ;
   RECT 0.2160 152.1480 0.2640 152.1960 ;
  END
 END rd[766]
 PIN wd[767]
  DIRECTION INPUT ;
  USE SIGNAL ;
  PORT
   LAYER M4 ;
   RECT 0.2160 152.3400 0.2640 152.3880 ;
  END
 END wd[767]
 PIN rd[767]
  DIRECTION OUTPUT ;
  USE SIGNAL ;
  PORT
   LAYER M4 ;
   RECT 0.2160 152.5320 0.2640 152.5800 ;
  END
 END rd[767]
 PIN wd[768]
  DIRECTION INPUT ;
  USE SIGNAL ;
  PORT
   LAYER M4 ;
   RECT 241.6560 54.4200 241.7040 54.4680 ;
  END
 END wd[768]
 PIN rd[768]
  DIRECTION OUTPUT ;
  USE SIGNAL ;
  PORT
   LAYER M4 ;
   RECT 241.6560 54.6120 241.7040 54.6600 ;
  END
 END rd[768]
 PIN wd[769]
  DIRECTION INPUT ;
  USE SIGNAL ;
  PORT
   LAYER M4 ;
   RECT 241.6560 54.8040 241.7040 54.8520 ;
  END
 END wd[769]
 PIN rd[769]
  DIRECTION OUTPUT ;
  USE SIGNAL ;
  PORT
   LAYER M4 ;
   RECT 241.6560 54.9960 241.7040 55.0440 ;
  END
 END rd[769]
 PIN wd[770]
  DIRECTION INPUT ;
  USE SIGNAL ;
  PORT
   LAYER M4 ;
   RECT 241.6560 55.1880 241.7040 55.2360 ;
  END
 END wd[770]
 PIN rd[770]
  DIRECTION OUTPUT ;
  USE SIGNAL ;
  PORT
   LAYER M4 ;
   RECT 241.6560 55.3800 241.7040 55.4280 ;
  END
 END rd[770]
 PIN wd[771]
  DIRECTION INPUT ;
  USE SIGNAL ;
  PORT
   LAYER M4 ;
   RECT 241.6560 55.5720 241.7040 55.6200 ;
  END
 END wd[771]
 PIN rd[771]
  DIRECTION OUTPUT ;
  USE SIGNAL ;
  PORT
   LAYER M4 ;
   RECT 241.6560 55.7640 241.7040 55.8120 ;
  END
 END rd[771]
 PIN wd[772]
  DIRECTION INPUT ;
  USE SIGNAL ;
  PORT
   LAYER M4 ;
   RECT 241.6560 55.9560 241.7040 56.0040 ;
  END
 END wd[772]
 PIN rd[772]
  DIRECTION OUTPUT ;
  USE SIGNAL ;
  PORT
   LAYER M4 ;
   RECT 241.6560 56.1480 241.7040 56.1960 ;
  END
 END rd[772]
 PIN wd[773]
  DIRECTION INPUT ;
  USE SIGNAL ;
  PORT
   LAYER M4 ;
   RECT 241.6560 56.3400 241.7040 56.3880 ;
  END
 END wd[773]
 PIN rd[773]
  DIRECTION OUTPUT ;
  USE SIGNAL ;
  PORT
   LAYER M4 ;
   RECT 241.6560 56.5320 241.7040 56.5800 ;
  END
 END rd[773]
 PIN wd[774]
  DIRECTION INPUT ;
  USE SIGNAL ;
  PORT
   LAYER M4 ;
   RECT 241.6560 56.7240 241.7040 56.7720 ;
  END
 END wd[774]
 PIN rd[774]
  DIRECTION OUTPUT ;
  USE SIGNAL ;
  PORT
   LAYER M4 ;
   RECT 241.6560 56.9160 241.7040 56.9640 ;
  END
 END rd[774]
 PIN wd[775]
  DIRECTION INPUT ;
  USE SIGNAL ;
  PORT
   LAYER M4 ;
   RECT 241.6560 57.1080 241.7040 57.1560 ;
  END
 END wd[775]
 PIN rd[775]
  DIRECTION OUTPUT ;
  USE SIGNAL ;
  PORT
   LAYER M4 ;
   RECT 241.6560 57.3000 241.7040 57.3480 ;
  END
 END rd[775]
 PIN wd[776]
  DIRECTION INPUT ;
  USE SIGNAL ;
  PORT
   LAYER M4 ;
   RECT 241.6560 57.4920 241.7040 57.5400 ;
  END
 END wd[776]
 PIN rd[776]
  DIRECTION OUTPUT ;
  USE SIGNAL ;
  PORT
   LAYER M4 ;
   RECT 241.6560 57.6840 241.7040 57.7320 ;
  END
 END rd[776]
 PIN wd[777]
  DIRECTION INPUT ;
  USE SIGNAL ;
  PORT
   LAYER M4 ;
   RECT 241.6560 57.8760 241.7040 57.9240 ;
  END
 END wd[777]
 PIN rd[777]
  DIRECTION OUTPUT ;
  USE SIGNAL ;
  PORT
   LAYER M4 ;
   RECT 241.6560 58.0680 241.7040 58.1160 ;
  END
 END rd[777]
 PIN wd[778]
  DIRECTION INPUT ;
  USE SIGNAL ;
  PORT
   LAYER M4 ;
   RECT 241.6560 58.2600 241.7040 58.3080 ;
  END
 END wd[778]
 PIN rd[778]
  DIRECTION OUTPUT ;
  USE SIGNAL ;
  PORT
   LAYER M4 ;
   RECT 241.6560 58.4520 241.7040 58.5000 ;
  END
 END rd[778]
 PIN wd[779]
  DIRECTION INPUT ;
  USE SIGNAL ;
  PORT
   LAYER M4 ;
   RECT 241.6560 58.6440 241.7040 58.6920 ;
  END
 END wd[779]
 PIN rd[779]
  DIRECTION OUTPUT ;
  USE SIGNAL ;
  PORT
   LAYER M4 ;
   RECT 241.6560 58.8360 241.7040 58.8840 ;
  END
 END rd[779]
 PIN wd[780]
  DIRECTION INPUT ;
  USE SIGNAL ;
  PORT
   LAYER M4 ;
   RECT 241.6560 59.0280 241.7040 59.0760 ;
  END
 END wd[780]
 PIN rd[780]
  DIRECTION OUTPUT ;
  USE SIGNAL ;
  PORT
   LAYER M4 ;
   RECT 241.6560 59.2200 241.7040 59.2680 ;
  END
 END rd[780]
 PIN wd[781]
  DIRECTION INPUT ;
  USE SIGNAL ;
  PORT
   LAYER M4 ;
   RECT 241.6560 59.4120 241.7040 59.4600 ;
  END
 END wd[781]
 PIN rd[781]
  DIRECTION OUTPUT ;
  USE SIGNAL ;
  PORT
   LAYER M4 ;
   RECT 241.6560 59.6040 241.7040 59.6520 ;
  END
 END rd[781]
 PIN wd[782]
  DIRECTION INPUT ;
  USE SIGNAL ;
  PORT
   LAYER M4 ;
   RECT 241.6560 59.7960 241.7040 59.8440 ;
  END
 END wd[782]
 PIN rd[782]
  DIRECTION OUTPUT ;
  USE SIGNAL ;
  PORT
   LAYER M4 ;
   RECT 241.6560 59.9880 241.7040 60.0360 ;
  END
 END rd[782]
 PIN wd[783]
  DIRECTION INPUT ;
  USE SIGNAL ;
  PORT
   LAYER M4 ;
   RECT 241.6560 60.1800 241.7040 60.2280 ;
  END
 END wd[783]
 PIN rd[783]
  DIRECTION OUTPUT ;
  USE SIGNAL ;
  PORT
   LAYER M4 ;
   RECT 241.6560 60.3720 241.7040 60.4200 ;
  END
 END rd[783]
 PIN wd[784]
  DIRECTION INPUT ;
  USE SIGNAL ;
  PORT
   LAYER M4 ;
   RECT 241.6560 60.5640 241.7040 60.6120 ;
  END
 END wd[784]
 PIN rd[784]
  DIRECTION OUTPUT ;
  USE SIGNAL ;
  PORT
   LAYER M4 ;
   RECT 241.6560 60.7560 241.7040 60.8040 ;
  END
 END rd[784]
 PIN wd[785]
  DIRECTION INPUT ;
  USE SIGNAL ;
  PORT
   LAYER M4 ;
   RECT 241.6560 60.9480 241.7040 60.9960 ;
  END
 END wd[785]
 PIN rd[785]
  DIRECTION OUTPUT ;
  USE SIGNAL ;
  PORT
   LAYER M4 ;
   RECT 241.6560 61.1400 241.7040 61.1880 ;
  END
 END rd[785]
 PIN wd[786]
  DIRECTION INPUT ;
  USE SIGNAL ;
  PORT
   LAYER M4 ;
   RECT 241.6560 61.3320 241.7040 61.3800 ;
  END
 END wd[786]
 PIN rd[786]
  DIRECTION OUTPUT ;
  USE SIGNAL ;
  PORT
   LAYER M4 ;
   RECT 241.6560 61.5240 241.7040 61.5720 ;
  END
 END rd[786]
 PIN wd[787]
  DIRECTION INPUT ;
  USE SIGNAL ;
  PORT
   LAYER M4 ;
   RECT 241.6560 61.7160 241.7040 61.7640 ;
  END
 END wd[787]
 PIN rd[787]
  DIRECTION OUTPUT ;
  USE SIGNAL ;
  PORT
   LAYER M4 ;
   RECT 241.6560 61.9080 241.7040 61.9560 ;
  END
 END rd[787]
 PIN wd[788]
  DIRECTION INPUT ;
  USE SIGNAL ;
  PORT
   LAYER M4 ;
   RECT 241.6560 62.1000 241.7040 62.1480 ;
  END
 END wd[788]
 PIN rd[788]
  DIRECTION OUTPUT ;
  USE SIGNAL ;
  PORT
   LAYER M4 ;
   RECT 241.6560 62.2920 241.7040 62.3400 ;
  END
 END rd[788]
 PIN wd[789]
  DIRECTION INPUT ;
  USE SIGNAL ;
  PORT
   LAYER M4 ;
   RECT 241.6560 62.4840 241.7040 62.5320 ;
  END
 END wd[789]
 PIN rd[789]
  DIRECTION OUTPUT ;
  USE SIGNAL ;
  PORT
   LAYER M4 ;
   RECT 241.6560 62.6760 241.7040 62.7240 ;
  END
 END rd[789]
 PIN wd[790]
  DIRECTION INPUT ;
  USE SIGNAL ;
  PORT
   LAYER M4 ;
   RECT 241.6560 62.8680 241.7040 62.9160 ;
  END
 END wd[790]
 PIN rd[790]
  DIRECTION OUTPUT ;
  USE SIGNAL ;
  PORT
   LAYER M4 ;
   RECT 241.6560 63.0600 241.7040 63.1080 ;
  END
 END rd[790]
 PIN wd[791]
  DIRECTION INPUT ;
  USE SIGNAL ;
  PORT
   LAYER M4 ;
   RECT 241.6560 63.2520 241.7040 63.3000 ;
  END
 END wd[791]
 PIN rd[791]
  DIRECTION OUTPUT ;
  USE SIGNAL ;
  PORT
   LAYER M4 ;
   RECT 241.6560 63.4440 241.7040 63.4920 ;
  END
 END rd[791]
 PIN wd[792]
  DIRECTION INPUT ;
  USE SIGNAL ;
  PORT
   LAYER M4 ;
   RECT 241.6560 63.6360 241.7040 63.6840 ;
  END
 END wd[792]
 PIN rd[792]
  DIRECTION OUTPUT ;
  USE SIGNAL ;
  PORT
   LAYER M4 ;
   RECT 241.6560 63.8280 241.7040 63.8760 ;
  END
 END rd[792]
 PIN wd[793]
  DIRECTION INPUT ;
  USE SIGNAL ;
  PORT
   LAYER M4 ;
   RECT 241.6560 64.0200 241.7040 64.0680 ;
  END
 END wd[793]
 PIN rd[793]
  DIRECTION OUTPUT ;
  USE SIGNAL ;
  PORT
   LAYER M4 ;
   RECT 241.6560 64.2120 241.7040 64.2600 ;
  END
 END rd[793]
 PIN wd[794]
  DIRECTION INPUT ;
  USE SIGNAL ;
  PORT
   LAYER M4 ;
   RECT 241.6560 64.4040 241.7040 64.4520 ;
  END
 END wd[794]
 PIN rd[794]
  DIRECTION OUTPUT ;
  USE SIGNAL ;
  PORT
   LAYER M4 ;
   RECT 241.6560 64.5960 241.7040 64.6440 ;
  END
 END rd[794]
 PIN wd[795]
  DIRECTION INPUT ;
  USE SIGNAL ;
  PORT
   LAYER M4 ;
   RECT 241.6560 64.7880 241.7040 64.8360 ;
  END
 END wd[795]
 PIN rd[795]
  DIRECTION OUTPUT ;
  USE SIGNAL ;
  PORT
   LAYER M4 ;
   RECT 241.6560 64.9800 241.7040 65.0280 ;
  END
 END rd[795]
 PIN wd[796]
  DIRECTION INPUT ;
  USE SIGNAL ;
  PORT
   LAYER M4 ;
   RECT 241.6560 65.1720 241.7040 65.2200 ;
  END
 END wd[796]
 PIN rd[796]
  DIRECTION OUTPUT ;
  USE SIGNAL ;
  PORT
   LAYER M4 ;
   RECT 241.6560 65.3640 241.7040 65.4120 ;
  END
 END rd[796]
 PIN wd[797]
  DIRECTION INPUT ;
  USE SIGNAL ;
  PORT
   LAYER M4 ;
   RECT 241.6560 65.5560 241.7040 65.6040 ;
  END
 END wd[797]
 PIN rd[797]
  DIRECTION OUTPUT ;
  USE SIGNAL ;
  PORT
   LAYER M4 ;
   RECT 241.6560 65.7480 241.7040 65.7960 ;
  END
 END rd[797]
 PIN wd[798]
  DIRECTION INPUT ;
  USE SIGNAL ;
  PORT
   LAYER M4 ;
   RECT 241.6560 65.9400 241.7040 65.9880 ;
  END
 END wd[798]
 PIN rd[798]
  DIRECTION OUTPUT ;
  USE SIGNAL ;
  PORT
   LAYER M4 ;
   RECT 241.6560 66.1320 241.7040 66.1800 ;
  END
 END rd[798]
 PIN wd[799]
  DIRECTION INPUT ;
  USE SIGNAL ;
  PORT
   LAYER M4 ;
   RECT 241.6560 66.3240 241.7040 66.3720 ;
  END
 END wd[799]
 PIN rd[799]
  DIRECTION OUTPUT ;
  USE SIGNAL ;
  PORT
   LAYER M4 ;
   RECT 241.6560 66.5160 241.7040 66.5640 ;
  END
 END rd[799]
 PIN wd[800]
  DIRECTION INPUT ;
  USE SIGNAL ;
  PORT
   LAYER M4 ;
   RECT 241.6560 66.7080 241.7040 66.7560 ;
  END
 END wd[800]
 PIN rd[800]
  DIRECTION OUTPUT ;
  USE SIGNAL ;
  PORT
   LAYER M4 ;
   RECT 241.6560 66.9000 241.7040 66.9480 ;
  END
 END rd[800]
 PIN wd[801]
  DIRECTION INPUT ;
  USE SIGNAL ;
  PORT
   LAYER M4 ;
   RECT 241.6560 67.0920 241.7040 67.1400 ;
  END
 END wd[801]
 PIN rd[801]
  DIRECTION OUTPUT ;
  USE SIGNAL ;
  PORT
   LAYER M4 ;
   RECT 241.6560 67.2840 241.7040 67.3320 ;
  END
 END rd[801]
 PIN wd[802]
  DIRECTION INPUT ;
  USE SIGNAL ;
  PORT
   LAYER M4 ;
   RECT 241.6560 67.4760 241.7040 67.5240 ;
  END
 END wd[802]
 PIN rd[802]
  DIRECTION OUTPUT ;
  USE SIGNAL ;
  PORT
   LAYER M4 ;
   RECT 241.6560 67.6680 241.7040 67.7160 ;
  END
 END rd[802]
 PIN wd[803]
  DIRECTION INPUT ;
  USE SIGNAL ;
  PORT
   LAYER M4 ;
   RECT 241.6560 67.8600 241.7040 67.9080 ;
  END
 END wd[803]
 PIN rd[803]
  DIRECTION OUTPUT ;
  USE SIGNAL ;
  PORT
   LAYER M4 ;
   RECT 241.6560 68.0520 241.7040 68.1000 ;
  END
 END rd[803]
 PIN wd[804]
  DIRECTION INPUT ;
  USE SIGNAL ;
  PORT
   LAYER M4 ;
   RECT 241.6560 68.2440 241.7040 68.2920 ;
  END
 END wd[804]
 PIN rd[804]
  DIRECTION OUTPUT ;
  USE SIGNAL ;
  PORT
   LAYER M4 ;
   RECT 241.6560 68.4360 241.7040 68.4840 ;
  END
 END rd[804]
 PIN wd[805]
  DIRECTION INPUT ;
  USE SIGNAL ;
  PORT
   LAYER M4 ;
   RECT 241.6560 68.6280 241.7040 68.6760 ;
  END
 END wd[805]
 PIN rd[805]
  DIRECTION OUTPUT ;
  USE SIGNAL ;
  PORT
   LAYER M4 ;
   RECT 241.6560 68.8200 241.7040 68.8680 ;
  END
 END rd[805]
 PIN wd[806]
  DIRECTION INPUT ;
  USE SIGNAL ;
  PORT
   LAYER M4 ;
   RECT 241.6560 69.0120 241.7040 69.0600 ;
  END
 END wd[806]
 PIN rd[806]
  DIRECTION OUTPUT ;
  USE SIGNAL ;
  PORT
   LAYER M4 ;
   RECT 241.6560 69.2040 241.7040 69.2520 ;
  END
 END rd[806]
 PIN wd[807]
  DIRECTION INPUT ;
  USE SIGNAL ;
  PORT
   LAYER M4 ;
   RECT 241.6560 69.3960 241.7040 69.4440 ;
  END
 END wd[807]
 PIN rd[807]
  DIRECTION OUTPUT ;
  USE SIGNAL ;
  PORT
   LAYER M4 ;
   RECT 241.6560 69.5880 241.7040 69.6360 ;
  END
 END rd[807]
 PIN wd[808]
  DIRECTION INPUT ;
  USE SIGNAL ;
  PORT
   LAYER M4 ;
   RECT 241.6560 69.7800 241.7040 69.8280 ;
  END
 END wd[808]
 PIN rd[808]
  DIRECTION OUTPUT ;
  USE SIGNAL ;
  PORT
   LAYER M4 ;
   RECT 241.6560 69.9720 241.7040 70.0200 ;
  END
 END rd[808]
 PIN wd[809]
  DIRECTION INPUT ;
  USE SIGNAL ;
  PORT
   LAYER M4 ;
   RECT 241.6560 70.1640 241.7040 70.2120 ;
  END
 END wd[809]
 PIN rd[809]
  DIRECTION OUTPUT ;
  USE SIGNAL ;
  PORT
   LAYER M4 ;
   RECT 241.6560 70.3560 241.7040 70.4040 ;
  END
 END rd[809]
 PIN wd[810]
  DIRECTION INPUT ;
  USE SIGNAL ;
  PORT
   LAYER M4 ;
   RECT 241.6560 70.5480 241.7040 70.5960 ;
  END
 END wd[810]
 PIN rd[810]
  DIRECTION OUTPUT ;
  USE SIGNAL ;
  PORT
   LAYER M4 ;
   RECT 241.6560 70.7400 241.7040 70.7880 ;
  END
 END rd[810]
 PIN wd[811]
  DIRECTION INPUT ;
  USE SIGNAL ;
  PORT
   LAYER M4 ;
   RECT 241.6560 70.9320 241.7040 70.9800 ;
  END
 END wd[811]
 PIN rd[811]
  DIRECTION OUTPUT ;
  USE SIGNAL ;
  PORT
   LAYER M4 ;
   RECT 241.6560 71.1240 241.7040 71.1720 ;
  END
 END rd[811]
 PIN wd[812]
  DIRECTION INPUT ;
  USE SIGNAL ;
  PORT
   LAYER M4 ;
   RECT 241.6560 71.3160 241.7040 71.3640 ;
  END
 END wd[812]
 PIN rd[812]
  DIRECTION OUTPUT ;
  USE SIGNAL ;
  PORT
   LAYER M4 ;
   RECT 241.6560 71.5080 241.7040 71.5560 ;
  END
 END rd[812]
 PIN wd[813]
  DIRECTION INPUT ;
  USE SIGNAL ;
  PORT
   LAYER M4 ;
   RECT 241.6560 71.7000 241.7040 71.7480 ;
  END
 END wd[813]
 PIN rd[813]
  DIRECTION OUTPUT ;
  USE SIGNAL ;
  PORT
   LAYER M4 ;
   RECT 241.6560 71.8920 241.7040 71.9400 ;
  END
 END rd[813]
 PIN wd[814]
  DIRECTION INPUT ;
  USE SIGNAL ;
  PORT
   LAYER M4 ;
   RECT 241.6560 72.0840 241.7040 72.1320 ;
  END
 END wd[814]
 PIN rd[814]
  DIRECTION OUTPUT ;
  USE SIGNAL ;
  PORT
   LAYER M4 ;
   RECT 241.6560 72.2760 241.7040 72.3240 ;
  END
 END rd[814]
 PIN wd[815]
  DIRECTION INPUT ;
  USE SIGNAL ;
  PORT
   LAYER M4 ;
   RECT 241.6560 72.4680 241.7040 72.5160 ;
  END
 END wd[815]
 PIN rd[815]
  DIRECTION OUTPUT ;
  USE SIGNAL ;
  PORT
   LAYER M4 ;
   RECT 241.6560 72.6600 241.7040 72.7080 ;
  END
 END rd[815]
 PIN wd[816]
  DIRECTION INPUT ;
  USE SIGNAL ;
  PORT
   LAYER M4 ;
   RECT 241.6560 72.8520 241.7040 72.9000 ;
  END
 END wd[816]
 PIN rd[816]
  DIRECTION OUTPUT ;
  USE SIGNAL ;
  PORT
   LAYER M4 ;
   RECT 241.6560 73.0440 241.7040 73.0920 ;
  END
 END rd[816]
 PIN wd[817]
  DIRECTION INPUT ;
  USE SIGNAL ;
  PORT
   LAYER M4 ;
   RECT 241.6560 73.2360 241.7040 73.2840 ;
  END
 END wd[817]
 PIN rd[817]
  DIRECTION OUTPUT ;
  USE SIGNAL ;
  PORT
   LAYER M4 ;
   RECT 241.6560 73.4280 241.7040 73.4760 ;
  END
 END rd[817]
 PIN wd[818]
  DIRECTION INPUT ;
  USE SIGNAL ;
  PORT
   LAYER M4 ;
   RECT 241.6560 73.6200 241.7040 73.6680 ;
  END
 END wd[818]
 PIN rd[818]
  DIRECTION OUTPUT ;
  USE SIGNAL ;
  PORT
   LAYER M4 ;
   RECT 241.6560 73.8120 241.7040 73.8600 ;
  END
 END rd[818]
 PIN wd[819]
  DIRECTION INPUT ;
  USE SIGNAL ;
  PORT
   LAYER M4 ;
   RECT 241.6560 74.0040 241.7040 74.0520 ;
  END
 END wd[819]
 PIN rd[819]
  DIRECTION OUTPUT ;
  USE SIGNAL ;
  PORT
   LAYER M4 ;
   RECT 241.6560 74.1960 241.7040 74.2440 ;
  END
 END rd[819]
 PIN wd[820]
  DIRECTION INPUT ;
  USE SIGNAL ;
  PORT
   LAYER M4 ;
   RECT 241.6560 74.3880 241.7040 74.4360 ;
  END
 END wd[820]
 PIN rd[820]
  DIRECTION OUTPUT ;
  USE SIGNAL ;
  PORT
   LAYER M4 ;
   RECT 241.6560 74.5800 241.7040 74.6280 ;
  END
 END rd[820]
 PIN wd[821]
  DIRECTION INPUT ;
  USE SIGNAL ;
  PORT
   LAYER M4 ;
   RECT 241.6560 74.7720 241.7040 74.8200 ;
  END
 END wd[821]
 PIN rd[821]
  DIRECTION OUTPUT ;
  USE SIGNAL ;
  PORT
   LAYER M4 ;
   RECT 241.6560 74.9640 241.7040 75.0120 ;
  END
 END rd[821]
 PIN wd[822]
  DIRECTION INPUT ;
  USE SIGNAL ;
  PORT
   LAYER M4 ;
   RECT 241.6560 75.1560 241.7040 75.2040 ;
  END
 END wd[822]
 PIN rd[822]
  DIRECTION OUTPUT ;
  USE SIGNAL ;
  PORT
   LAYER M4 ;
   RECT 241.6560 75.3480 241.7040 75.3960 ;
  END
 END rd[822]
 PIN wd[823]
  DIRECTION INPUT ;
  USE SIGNAL ;
  PORT
   LAYER M4 ;
   RECT 241.6560 75.5400 241.7040 75.5880 ;
  END
 END wd[823]
 PIN rd[823]
  DIRECTION OUTPUT ;
  USE SIGNAL ;
  PORT
   LAYER M4 ;
   RECT 241.6560 75.7320 241.7040 75.7800 ;
  END
 END rd[823]
 PIN wd[824]
  DIRECTION INPUT ;
  USE SIGNAL ;
  PORT
   LAYER M4 ;
   RECT 241.6560 75.9240 241.7040 75.9720 ;
  END
 END wd[824]
 PIN rd[824]
  DIRECTION OUTPUT ;
  USE SIGNAL ;
  PORT
   LAYER M4 ;
   RECT 241.6560 76.1160 241.7040 76.1640 ;
  END
 END rd[824]
 PIN wd[825]
  DIRECTION INPUT ;
  USE SIGNAL ;
  PORT
   LAYER M4 ;
   RECT 241.6560 76.3080 241.7040 76.3560 ;
  END
 END wd[825]
 PIN rd[825]
  DIRECTION OUTPUT ;
  USE SIGNAL ;
  PORT
   LAYER M4 ;
   RECT 241.6560 76.5000 241.7040 76.5480 ;
  END
 END rd[825]
 PIN wd[826]
  DIRECTION INPUT ;
  USE SIGNAL ;
  PORT
   LAYER M4 ;
   RECT 241.6560 76.6920 241.7040 76.7400 ;
  END
 END wd[826]
 PIN rd[826]
  DIRECTION OUTPUT ;
  USE SIGNAL ;
  PORT
   LAYER M4 ;
   RECT 241.6560 76.8840 241.7040 76.9320 ;
  END
 END rd[826]
 PIN wd[827]
  DIRECTION INPUT ;
  USE SIGNAL ;
  PORT
   LAYER M4 ;
   RECT 241.6560 77.0760 241.7040 77.1240 ;
  END
 END wd[827]
 PIN rd[827]
  DIRECTION OUTPUT ;
  USE SIGNAL ;
  PORT
   LAYER M4 ;
   RECT 241.6560 77.2680 241.7040 77.3160 ;
  END
 END rd[827]
 PIN wd[828]
  DIRECTION INPUT ;
  USE SIGNAL ;
  PORT
   LAYER M4 ;
   RECT 241.6560 77.4600 241.7040 77.5080 ;
  END
 END wd[828]
 PIN rd[828]
  DIRECTION OUTPUT ;
  USE SIGNAL ;
  PORT
   LAYER M4 ;
   RECT 241.6560 77.6520 241.7040 77.7000 ;
  END
 END rd[828]
 PIN wd[829]
  DIRECTION INPUT ;
  USE SIGNAL ;
  PORT
   LAYER M4 ;
   RECT 241.6560 77.8440 241.7040 77.8920 ;
  END
 END wd[829]
 PIN rd[829]
  DIRECTION OUTPUT ;
  USE SIGNAL ;
  PORT
   LAYER M4 ;
   RECT 241.6560 78.0360 241.7040 78.0840 ;
  END
 END rd[829]
 PIN wd[830]
  DIRECTION INPUT ;
  USE SIGNAL ;
  PORT
   LAYER M4 ;
   RECT 241.6560 78.2280 241.7040 78.2760 ;
  END
 END wd[830]
 PIN rd[830]
  DIRECTION OUTPUT ;
  USE SIGNAL ;
  PORT
   LAYER M4 ;
   RECT 241.6560 78.4200 241.7040 78.4680 ;
  END
 END rd[830]
 PIN wd[831]
  DIRECTION INPUT ;
  USE SIGNAL ;
  PORT
   LAYER M4 ;
   RECT 241.6560 78.6120 241.7040 78.6600 ;
  END
 END wd[831]
 PIN rd[831]
  DIRECTION OUTPUT ;
  USE SIGNAL ;
  PORT
   LAYER M4 ;
   RECT 241.6560 78.8040 241.7040 78.8520 ;
  END
 END rd[831]
 PIN wd[832]
  DIRECTION INPUT ;
  USE SIGNAL ;
  PORT
   LAYER M4 ;
   RECT 241.6560 78.9960 241.7040 79.0440 ;
  END
 END wd[832]
 PIN rd[832]
  DIRECTION OUTPUT ;
  USE SIGNAL ;
  PORT
   LAYER M4 ;
   RECT 241.6560 79.1880 241.7040 79.2360 ;
  END
 END rd[832]
 PIN wd[833]
  DIRECTION INPUT ;
  USE SIGNAL ;
  PORT
   LAYER M4 ;
   RECT 241.6560 79.3800 241.7040 79.4280 ;
  END
 END wd[833]
 PIN rd[833]
  DIRECTION OUTPUT ;
  USE SIGNAL ;
  PORT
   LAYER M4 ;
   RECT 241.6560 79.5720 241.7040 79.6200 ;
  END
 END rd[833]
 PIN wd[834]
  DIRECTION INPUT ;
  USE SIGNAL ;
  PORT
   LAYER M4 ;
   RECT 241.6560 79.7640 241.7040 79.8120 ;
  END
 END wd[834]
 PIN rd[834]
  DIRECTION OUTPUT ;
  USE SIGNAL ;
  PORT
   LAYER M4 ;
   RECT 241.6560 79.9560 241.7040 80.0040 ;
  END
 END rd[834]
 PIN wd[835]
  DIRECTION INPUT ;
  USE SIGNAL ;
  PORT
   LAYER M4 ;
   RECT 241.6560 80.1480 241.7040 80.1960 ;
  END
 END wd[835]
 PIN rd[835]
  DIRECTION OUTPUT ;
  USE SIGNAL ;
  PORT
   LAYER M4 ;
   RECT 241.6560 80.3400 241.7040 80.3880 ;
  END
 END rd[835]
 PIN wd[836]
  DIRECTION INPUT ;
  USE SIGNAL ;
  PORT
   LAYER M4 ;
   RECT 241.6560 80.5320 241.7040 80.5800 ;
  END
 END wd[836]
 PIN rd[836]
  DIRECTION OUTPUT ;
  USE SIGNAL ;
  PORT
   LAYER M4 ;
   RECT 241.6560 80.7240 241.7040 80.7720 ;
  END
 END rd[836]
 PIN wd[837]
  DIRECTION INPUT ;
  USE SIGNAL ;
  PORT
   LAYER M4 ;
   RECT 241.6560 80.9160 241.7040 80.9640 ;
  END
 END wd[837]
 PIN rd[837]
  DIRECTION OUTPUT ;
  USE SIGNAL ;
  PORT
   LAYER M4 ;
   RECT 241.6560 81.1080 241.7040 81.1560 ;
  END
 END rd[837]
 PIN wd[838]
  DIRECTION INPUT ;
  USE SIGNAL ;
  PORT
   LAYER M4 ;
   RECT 241.6560 81.3000 241.7040 81.3480 ;
  END
 END wd[838]
 PIN rd[838]
  DIRECTION OUTPUT ;
  USE SIGNAL ;
  PORT
   LAYER M4 ;
   RECT 241.6560 81.4920 241.7040 81.5400 ;
  END
 END rd[838]
 PIN wd[839]
  DIRECTION INPUT ;
  USE SIGNAL ;
  PORT
   LAYER M4 ;
   RECT 241.6560 81.6840 241.7040 81.7320 ;
  END
 END wd[839]
 PIN rd[839]
  DIRECTION OUTPUT ;
  USE SIGNAL ;
  PORT
   LAYER M4 ;
   RECT 241.6560 81.8760 241.7040 81.9240 ;
  END
 END rd[839]
 PIN wd[840]
  DIRECTION INPUT ;
  USE SIGNAL ;
  PORT
   LAYER M4 ;
   RECT 241.6560 82.0680 241.7040 82.1160 ;
  END
 END wd[840]
 PIN rd[840]
  DIRECTION OUTPUT ;
  USE SIGNAL ;
  PORT
   LAYER M4 ;
   RECT 241.6560 82.2600 241.7040 82.3080 ;
  END
 END rd[840]
 PIN wd[841]
  DIRECTION INPUT ;
  USE SIGNAL ;
  PORT
   LAYER M4 ;
   RECT 241.6560 82.4520 241.7040 82.5000 ;
  END
 END wd[841]
 PIN rd[841]
  DIRECTION OUTPUT ;
  USE SIGNAL ;
  PORT
   LAYER M4 ;
   RECT 241.6560 82.6440 241.7040 82.6920 ;
  END
 END rd[841]
 PIN wd[842]
  DIRECTION INPUT ;
  USE SIGNAL ;
  PORT
   LAYER M4 ;
   RECT 241.6560 82.8360 241.7040 82.8840 ;
  END
 END wd[842]
 PIN rd[842]
  DIRECTION OUTPUT ;
  USE SIGNAL ;
  PORT
   LAYER M4 ;
   RECT 241.6560 83.0280 241.7040 83.0760 ;
  END
 END rd[842]
 PIN wd[843]
  DIRECTION INPUT ;
  USE SIGNAL ;
  PORT
   LAYER M4 ;
   RECT 241.6560 83.2200 241.7040 83.2680 ;
  END
 END wd[843]
 PIN rd[843]
  DIRECTION OUTPUT ;
  USE SIGNAL ;
  PORT
   LAYER M4 ;
   RECT 241.6560 83.4120 241.7040 83.4600 ;
  END
 END rd[843]
 PIN wd[844]
  DIRECTION INPUT ;
  USE SIGNAL ;
  PORT
   LAYER M4 ;
   RECT 241.6560 83.6040 241.7040 83.6520 ;
  END
 END wd[844]
 PIN rd[844]
  DIRECTION OUTPUT ;
  USE SIGNAL ;
  PORT
   LAYER M4 ;
   RECT 241.6560 83.7960 241.7040 83.8440 ;
  END
 END rd[844]
 PIN wd[845]
  DIRECTION INPUT ;
  USE SIGNAL ;
  PORT
   LAYER M4 ;
   RECT 241.6560 83.9880 241.7040 84.0360 ;
  END
 END wd[845]
 PIN rd[845]
  DIRECTION OUTPUT ;
  USE SIGNAL ;
  PORT
   LAYER M4 ;
   RECT 241.6560 84.1800 241.7040 84.2280 ;
  END
 END rd[845]
 PIN wd[846]
  DIRECTION INPUT ;
  USE SIGNAL ;
  PORT
   LAYER M4 ;
   RECT 241.6560 84.3720 241.7040 84.4200 ;
  END
 END wd[846]
 PIN rd[846]
  DIRECTION OUTPUT ;
  USE SIGNAL ;
  PORT
   LAYER M4 ;
   RECT 241.6560 84.5640 241.7040 84.6120 ;
  END
 END rd[846]
 PIN wd[847]
  DIRECTION INPUT ;
  USE SIGNAL ;
  PORT
   LAYER M4 ;
   RECT 241.6560 84.7560 241.7040 84.8040 ;
  END
 END wd[847]
 PIN rd[847]
  DIRECTION OUTPUT ;
  USE SIGNAL ;
  PORT
   LAYER M4 ;
   RECT 241.6560 84.9480 241.7040 84.9960 ;
  END
 END rd[847]
 PIN wd[848]
  DIRECTION INPUT ;
  USE SIGNAL ;
  PORT
   LAYER M4 ;
   RECT 241.6560 85.1400 241.7040 85.1880 ;
  END
 END wd[848]
 PIN rd[848]
  DIRECTION OUTPUT ;
  USE SIGNAL ;
  PORT
   LAYER M4 ;
   RECT 241.6560 85.3320 241.7040 85.3800 ;
  END
 END rd[848]
 PIN wd[849]
  DIRECTION INPUT ;
  USE SIGNAL ;
  PORT
   LAYER M4 ;
   RECT 241.6560 85.5240 241.7040 85.5720 ;
  END
 END wd[849]
 PIN rd[849]
  DIRECTION OUTPUT ;
  USE SIGNAL ;
  PORT
   LAYER M4 ;
   RECT 241.6560 85.7160 241.7040 85.7640 ;
  END
 END rd[849]
 PIN wd[850]
  DIRECTION INPUT ;
  USE SIGNAL ;
  PORT
   LAYER M4 ;
   RECT 241.6560 85.9080 241.7040 85.9560 ;
  END
 END wd[850]
 PIN rd[850]
  DIRECTION OUTPUT ;
  USE SIGNAL ;
  PORT
   LAYER M4 ;
   RECT 241.6560 86.1000 241.7040 86.1480 ;
  END
 END rd[850]
 PIN wd[851]
  DIRECTION INPUT ;
  USE SIGNAL ;
  PORT
   LAYER M4 ;
   RECT 241.6560 86.2920 241.7040 86.3400 ;
  END
 END wd[851]
 PIN rd[851]
  DIRECTION OUTPUT ;
  USE SIGNAL ;
  PORT
   LAYER M4 ;
   RECT 241.6560 86.4840 241.7040 86.5320 ;
  END
 END rd[851]
 PIN wd[852]
  DIRECTION INPUT ;
  USE SIGNAL ;
  PORT
   LAYER M4 ;
   RECT 241.6560 86.6760 241.7040 86.7240 ;
  END
 END wd[852]
 PIN rd[852]
  DIRECTION OUTPUT ;
  USE SIGNAL ;
  PORT
   LAYER M4 ;
   RECT 241.6560 86.8680 241.7040 86.9160 ;
  END
 END rd[852]
 PIN wd[853]
  DIRECTION INPUT ;
  USE SIGNAL ;
  PORT
   LAYER M4 ;
   RECT 241.6560 87.0600 241.7040 87.1080 ;
  END
 END wd[853]
 PIN rd[853]
  DIRECTION OUTPUT ;
  USE SIGNAL ;
  PORT
   LAYER M4 ;
   RECT 241.6560 87.2520 241.7040 87.3000 ;
  END
 END rd[853]
 PIN wd[854]
  DIRECTION INPUT ;
  USE SIGNAL ;
  PORT
   LAYER M4 ;
   RECT 241.6560 87.4440 241.7040 87.4920 ;
  END
 END wd[854]
 PIN rd[854]
  DIRECTION OUTPUT ;
  USE SIGNAL ;
  PORT
   LAYER M4 ;
   RECT 241.6560 87.6360 241.7040 87.6840 ;
  END
 END rd[854]
 PIN wd[855]
  DIRECTION INPUT ;
  USE SIGNAL ;
  PORT
   LAYER M4 ;
   RECT 241.6560 87.8280 241.7040 87.8760 ;
  END
 END wd[855]
 PIN rd[855]
  DIRECTION OUTPUT ;
  USE SIGNAL ;
  PORT
   LAYER M4 ;
   RECT 241.6560 88.0200 241.7040 88.0680 ;
  END
 END rd[855]
 PIN wd[856]
  DIRECTION INPUT ;
  USE SIGNAL ;
  PORT
   LAYER M4 ;
   RECT 241.6560 88.2120 241.7040 88.2600 ;
  END
 END wd[856]
 PIN rd[856]
  DIRECTION OUTPUT ;
  USE SIGNAL ;
  PORT
   LAYER M4 ;
   RECT 241.6560 88.4040 241.7040 88.4520 ;
  END
 END rd[856]
 PIN wd[857]
  DIRECTION INPUT ;
  USE SIGNAL ;
  PORT
   LAYER M4 ;
   RECT 241.6560 88.5960 241.7040 88.6440 ;
  END
 END wd[857]
 PIN rd[857]
  DIRECTION OUTPUT ;
  USE SIGNAL ;
  PORT
   LAYER M4 ;
   RECT 241.6560 88.7880 241.7040 88.8360 ;
  END
 END rd[857]
 PIN wd[858]
  DIRECTION INPUT ;
  USE SIGNAL ;
  PORT
   LAYER M4 ;
   RECT 241.6560 88.9800 241.7040 89.0280 ;
  END
 END wd[858]
 PIN rd[858]
  DIRECTION OUTPUT ;
  USE SIGNAL ;
  PORT
   LAYER M4 ;
   RECT 241.6560 89.1720 241.7040 89.2200 ;
  END
 END rd[858]
 PIN wd[859]
  DIRECTION INPUT ;
  USE SIGNAL ;
  PORT
   LAYER M4 ;
   RECT 241.6560 89.3640 241.7040 89.4120 ;
  END
 END wd[859]
 PIN rd[859]
  DIRECTION OUTPUT ;
  USE SIGNAL ;
  PORT
   LAYER M4 ;
   RECT 241.6560 89.5560 241.7040 89.6040 ;
  END
 END rd[859]
 PIN wd[860]
  DIRECTION INPUT ;
  USE SIGNAL ;
  PORT
   LAYER M4 ;
   RECT 241.6560 89.7480 241.7040 89.7960 ;
  END
 END wd[860]
 PIN rd[860]
  DIRECTION OUTPUT ;
  USE SIGNAL ;
  PORT
   LAYER M4 ;
   RECT 241.6560 89.9400 241.7040 89.9880 ;
  END
 END rd[860]
 PIN wd[861]
  DIRECTION INPUT ;
  USE SIGNAL ;
  PORT
   LAYER M4 ;
   RECT 241.6560 90.1320 241.7040 90.1800 ;
  END
 END wd[861]
 PIN rd[861]
  DIRECTION OUTPUT ;
  USE SIGNAL ;
  PORT
   LAYER M4 ;
   RECT 241.6560 90.3240 241.7040 90.3720 ;
  END
 END rd[861]
 PIN wd[862]
  DIRECTION INPUT ;
  USE SIGNAL ;
  PORT
   LAYER M4 ;
   RECT 241.6560 90.5160 241.7040 90.5640 ;
  END
 END wd[862]
 PIN rd[862]
  DIRECTION OUTPUT ;
  USE SIGNAL ;
  PORT
   LAYER M4 ;
   RECT 241.6560 90.7080 241.7040 90.7560 ;
  END
 END rd[862]
 PIN wd[863]
  DIRECTION INPUT ;
  USE SIGNAL ;
  PORT
   LAYER M4 ;
   RECT 241.6560 90.9000 241.7040 90.9480 ;
  END
 END wd[863]
 PIN rd[863]
  DIRECTION OUTPUT ;
  USE SIGNAL ;
  PORT
   LAYER M4 ;
   RECT 241.6560 91.0920 241.7040 91.1400 ;
  END
 END rd[863]
 PIN wd[864]
  DIRECTION INPUT ;
  USE SIGNAL ;
  PORT
   LAYER M4 ;
   RECT 241.6560 91.2840 241.7040 91.3320 ;
  END
 END wd[864]
 PIN rd[864]
  DIRECTION OUTPUT ;
  USE SIGNAL ;
  PORT
   LAYER M4 ;
   RECT 241.6560 91.4760 241.7040 91.5240 ;
  END
 END rd[864]
 PIN wd[865]
  DIRECTION INPUT ;
  USE SIGNAL ;
  PORT
   LAYER M4 ;
   RECT 241.6560 91.6680 241.7040 91.7160 ;
  END
 END wd[865]
 PIN rd[865]
  DIRECTION OUTPUT ;
  USE SIGNAL ;
  PORT
   LAYER M4 ;
   RECT 241.6560 91.8600 241.7040 91.9080 ;
  END
 END rd[865]
 PIN wd[866]
  DIRECTION INPUT ;
  USE SIGNAL ;
  PORT
   LAYER M4 ;
   RECT 241.6560 92.0520 241.7040 92.1000 ;
  END
 END wd[866]
 PIN rd[866]
  DIRECTION OUTPUT ;
  USE SIGNAL ;
  PORT
   LAYER M4 ;
   RECT 241.6560 92.2440 241.7040 92.2920 ;
  END
 END rd[866]
 PIN wd[867]
  DIRECTION INPUT ;
  USE SIGNAL ;
  PORT
   LAYER M4 ;
   RECT 241.6560 92.4360 241.7040 92.4840 ;
  END
 END wd[867]
 PIN rd[867]
  DIRECTION OUTPUT ;
  USE SIGNAL ;
  PORT
   LAYER M4 ;
   RECT 241.6560 92.6280 241.7040 92.6760 ;
  END
 END rd[867]
 PIN wd[868]
  DIRECTION INPUT ;
  USE SIGNAL ;
  PORT
   LAYER M4 ;
   RECT 241.6560 92.8200 241.7040 92.8680 ;
  END
 END wd[868]
 PIN rd[868]
  DIRECTION OUTPUT ;
  USE SIGNAL ;
  PORT
   LAYER M4 ;
   RECT 241.6560 93.0120 241.7040 93.0600 ;
  END
 END rd[868]
 PIN wd[869]
  DIRECTION INPUT ;
  USE SIGNAL ;
  PORT
   LAYER M4 ;
   RECT 241.6560 93.2040 241.7040 93.2520 ;
  END
 END wd[869]
 PIN rd[869]
  DIRECTION OUTPUT ;
  USE SIGNAL ;
  PORT
   LAYER M4 ;
   RECT 241.6560 93.3960 241.7040 93.4440 ;
  END
 END rd[869]
 PIN wd[870]
  DIRECTION INPUT ;
  USE SIGNAL ;
  PORT
   LAYER M4 ;
   RECT 241.6560 93.5880 241.7040 93.6360 ;
  END
 END wd[870]
 PIN rd[870]
  DIRECTION OUTPUT ;
  USE SIGNAL ;
  PORT
   LAYER M4 ;
   RECT 241.6560 93.7800 241.7040 93.8280 ;
  END
 END rd[870]
 PIN wd[871]
  DIRECTION INPUT ;
  USE SIGNAL ;
  PORT
   LAYER M4 ;
   RECT 241.6560 93.9720 241.7040 94.0200 ;
  END
 END wd[871]
 PIN rd[871]
  DIRECTION OUTPUT ;
  USE SIGNAL ;
  PORT
   LAYER M4 ;
   RECT 241.6560 94.1640 241.7040 94.2120 ;
  END
 END rd[871]
 PIN wd[872]
  DIRECTION INPUT ;
  USE SIGNAL ;
  PORT
   LAYER M4 ;
   RECT 241.6560 94.3560 241.7040 94.4040 ;
  END
 END wd[872]
 PIN rd[872]
  DIRECTION OUTPUT ;
  USE SIGNAL ;
  PORT
   LAYER M4 ;
   RECT 241.6560 94.5480 241.7040 94.5960 ;
  END
 END rd[872]
 PIN wd[873]
  DIRECTION INPUT ;
  USE SIGNAL ;
  PORT
   LAYER M4 ;
   RECT 241.6560 94.7400 241.7040 94.7880 ;
  END
 END wd[873]
 PIN rd[873]
  DIRECTION OUTPUT ;
  USE SIGNAL ;
  PORT
   LAYER M4 ;
   RECT 241.6560 94.9320 241.7040 94.9800 ;
  END
 END rd[873]
 PIN wd[874]
  DIRECTION INPUT ;
  USE SIGNAL ;
  PORT
   LAYER M4 ;
   RECT 241.6560 95.1240 241.7040 95.1720 ;
  END
 END wd[874]
 PIN rd[874]
  DIRECTION OUTPUT ;
  USE SIGNAL ;
  PORT
   LAYER M4 ;
   RECT 241.6560 95.3160 241.7040 95.3640 ;
  END
 END rd[874]
 PIN wd[875]
  DIRECTION INPUT ;
  USE SIGNAL ;
  PORT
   LAYER M4 ;
   RECT 241.6560 95.5080 241.7040 95.5560 ;
  END
 END wd[875]
 PIN rd[875]
  DIRECTION OUTPUT ;
  USE SIGNAL ;
  PORT
   LAYER M4 ;
   RECT 241.6560 95.7000 241.7040 95.7480 ;
  END
 END rd[875]
 PIN wd[876]
  DIRECTION INPUT ;
  USE SIGNAL ;
  PORT
   LAYER M4 ;
   RECT 241.6560 95.8920 241.7040 95.9400 ;
  END
 END wd[876]
 PIN rd[876]
  DIRECTION OUTPUT ;
  USE SIGNAL ;
  PORT
   LAYER M4 ;
   RECT 241.6560 96.0840 241.7040 96.1320 ;
  END
 END rd[876]
 PIN wd[877]
  DIRECTION INPUT ;
  USE SIGNAL ;
  PORT
   LAYER M4 ;
   RECT 241.6560 96.2760 241.7040 96.3240 ;
  END
 END wd[877]
 PIN rd[877]
  DIRECTION OUTPUT ;
  USE SIGNAL ;
  PORT
   LAYER M4 ;
   RECT 241.6560 96.4680 241.7040 96.5160 ;
  END
 END rd[877]
 PIN wd[878]
  DIRECTION INPUT ;
  USE SIGNAL ;
  PORT
   LAYER M4 ;
   RECT 241.6560 96.6600 241.7040 96.7080 ;
  END
 END wd[878]
 PIN rd[878]
  DIRECTION OUTPUT ;
  USE SIGNAL ;
  PORT
   LAYER M4 ;
   RECT 241.6560 96.8520 241.7040 96.9000 ;
  END
 END rd[878]
 PIN wd[879]
  DIRECTION INPUT ;
  USE SIGNAL ;
  PORT
   LAYER M4 ;
   RECT 241.6560 97.0440 241.7040 97.0920 ;
  END
 END wd[879]
 PIN rd[879]
  DIRECTION OUTPUT ;
  USE SIGNAL ;
  PORT
   LAYER M4 ;
   RECT 241.6560 97.2360 241.7040 97.2840 ;
  END
 END rd[879]
 PIN wd[880]
  DIRECTION INPUT ;
  USE SIGNAL ;
  PORT
   LAYER M4 ;
   RECT 241.6560 97.4280 241.7040 97.4760 ;
  END
 END wd[880]
 PIN rd[880]
  DIRECTION OUTPUT ;
  USE SIGNAL ;
  PORT
   LAYER M4 ;
   RECT 241.6560 97.6200 241.7040 97.6680 ;
  END
 END rd[880]
 PIN wd[881]
  DIRECTION INPUT ;
  USE SIGNAL ;
  PORT
   LAYER M4 ;
   RECT 241.6560 97.8120 241.7040 97.8600 ;
  END
 END wd[881]
 PIN rd[881]
  DIRECTION OUTPUT ;
  USE SIGNAL ;
  PORT
   LAYER M4 ;
   RECT 241.6560 98.0040 241.7040 98.0520 ;
  END
 END rd[881]
 PIN wd[882]
  DIRECTION INPUT ;
  USE SIGNAL ;
  PORT
   LAYER M4 ;
   RECT 241.6560 98.1960 241.7040 98.2440 ;
  END
 END wd[882]
 PIN rd[882]
  DIRECTION OUTPUT ;
  USE SIGNAL ;
  PORT
   LAYER M4 ;
   RECT 241.6560 98.3880 241.7040 98.4360 ;
  END
 END rd[882]
 PIN wd[883]
  DIRECTION INPUT ;
  USE SIGNAL ;
  PORT
   LAYER M4 ;
   RECT 241.6560 98.5800 241.7040 98.6280 ;
  END
 END wd[883]
 PIN rd[883]
  DIRECTION OUTPUT ;
  USE SIGNAL ;
  PORT
   LAYER M4 ;
   RECT 241.6560 98.7720 241.7040 98.8200 ;
  END
 END rd[883]
 PIN wd[884]
  DIRECTION INPUT ;
  USE SIGNAL ;
  PORT
   LAYER M4 ;
   RECT 241.6560 98.9640 241.7040 99.0120 ;
  END
 END wd[884]
 PIN rd[884]
  DIRECTION OUTPUT ;
  USE SIGNAL ;
  PORT
   LAYER M4 ;
   RECT 241.6560 99.1560 241.7040 99.2040 ;
  END
 END rd[884]
 PIN wd[885]
  DIRECTION INPUT ;
  USE SIGNAL ;
  PORT
   LAYER M4 ;
   RECT 241.6560 99.3480 241.7040 99.3960 ;
  END
 END wd[885]
 PIN rd[885]
  DIRECTION OUTPUT ;
  USE SIGNAL ;
  PORT
   LAYER M4 ;
   RECT 241.6560 99.5400 241.7040 99.5880 ;
  END
 END rd[885]
 PIN wd[886]
  DIRECTION INPUT ;
  USE SIGNAL ;
  PORT
   LAYER M4 ;
   RECT 241.6560 99.7320 241.7040 99.7800 ;
  END
 END wd[886]
 PIN rd[886]
  DIRECTION OUTPUT ;
  USE SIGNAL ;
  PORT
   LAYER M4 ;
   RECT 241.6560 99.9240 241.7040 99.9720 ;
  END
 END rd[886]
 PIN wd[887]
  DIRECTION INPUT ;
  USE SIGNAL ;
  PORT
   LAYER M4 ;
   RECT 241.6560 100.1160 241.7040 100.1640 ;
  END
 END wd[887]
 PIN rd[887]
  DIRECTION OUTPUT ;
  USE SIGNAL ;
  PORT
   LAYER M4 ;
   RECT 241.6560 100.3080 241.7040 100.3560 ;
  END
 END rd[887]
 PIN wd[888]
  DIRECTION INPUT ;
  USE SIGNAL ;
  PORT
   LAYER M4 ;
   RECT 241.6560 100.5000 241.7040 100.5480 ;
  END
 END wd[888]
 PIN rd[888]
  DIRECTION OUTPUT ;
  USE SIGNAL ;
  PORT
   LAYER M4 ;
   RECT 241.6560 100.6920 241.7040 100.7400 ;
  END
 END rd[888]
 PIN wd[889]
  DIRECTION INPUT ;
  USE SIGNAL ;
  PORT
   LAYER M4 ;
   RECT 241.6560 100.8840 241.7040 100.9320 ;
  END
 END wd[889]
 PIN rd[889]
  DIRECTION OUTPUT ;
  USE SIGNAL ;
  PORT
   LAYER M4 ;
   RECT 241.6560 101.0760 241.7040 101.1240 ;
  END
 END rd[889]
 PIN wd[890]
  DIRECTION INPUT ;
  USE SIGNAL ;
  PORT
   LAYER M4 ;
   RECT 241.6560 101.2680 241.7040 101.3160 ;
  END
 END wd[890]
 PIN rd[890]
  DIRECTION OUTPUT ;
  USE SIGNAL ;
  PORT
   LAYER M4 ;
   RECT 241.6560 101.4600 241.7040 101.5080 ;
  END
 END rd[890]
 PIN wd[891]
  DIRECTION INPUT ;
  USE SIGNAL ;
  PORT
   LAYER M4 ;
   RECT 241.6560 101.6520 241.7040 101.7000 ;
  END
 END wd[891]
 PIN rd[891]
  DIRECTION OUTPUT ;
  USE SIGNAL ;
  PORT
   LAYER M4 ;
   RECT 241.6560 101.8440 241.7040 101.8920 ;
  END
 END rd[891]
 PIN wd[892]
  DIRECTION INPUT ;
  USE SIGNAL ;
  PORT
   LAYER M4 ;
   RECT 241.6560 102.0360 241.7040 102.0840 ;
  END
 END wd[892]
 PIN rd[892]
  DIRECTION OUTPUT ;
  USE SIGNAL ;
  PORT
   LAYER M4 ;
   RECT 241.6560 102.2280 241.7040 102.2760 ;
  END
 END rd[892]
 PIN wd[893]
  DIRECTION INPUT ;
  USE SIGNAL ;
  PORT
   LAYER M4 ;
   RECT 241.6560 102.4200 241.7040 102.4680 ;
  END
 END wd[893]
 PIN rd[893]
  DIRECTION OUTPUT ;
  USE SIGNAL ;
  PORT
   LAYER M4 ;
   RECT 241.6560 102.6120 241.7040 102.6600 ;
  END
 END rd[893]
 PIN wd[894]
  DIRECTION INPUT ;
  USE SIGNAL ;
  PORT
   LAYER M4 ;
   RECT 241.6560 102.8040 241.7040 102.8520 ;
  END
 END wd[894]
 PIN rd[894]
  DIRECTION OUTPUT ;
  USE SIGNAL ;
  PORT
   LAYER M4 ;
   RECT 241.6560 102.9960 241.7040 103.0440 ;
  END
 END rd[894]
 PIN wd[895]
  DIRECTION INPUT ;
  USE SIGNAL ;
  PORT
   LAYER M4 ;
   RECT 241.6560 103.1880 241.7040 103.2360 ;
  END
 END wd[895]
 PIN rd[895]
  DIRECTION OUTPUT ;
  USE SIGNAL ;
  PORT
   LAYER M4 ;
   RECT 241.6560 103.3800 241.7040 103.4280 ;
  END
 END rd[895]
 PIN wd[896]
  DIRECTION INPUT ;
  USE SIGNAL ;
  PORT
   LAYER M4 ;
   RECT 241.6560 103.5720 241.7040 103.6200 ;
  END
 END wd[896]
 PIN rd[896]
  DIRECTION OUTPUT ;
  USE SIGNAL ;
  PORT
   LAYER M4 ;
   RECT 241.6560 103.7640 241.7040 103.8120 ;
  END
 END rd[896]
 PIN wd[897]
  DIRECTION INPUT ;
  USE SIGNAL ;
  PORT
   LAYER M4 ;
   RECT 241.6560 103.9560 241.7040 104.0040 ;
  END
 END wd[897]
 PIN rd[897]
  DIRECTION OUTPUT ;
  USE SIGNAL ;
  PORT
   LAYER M4 ;
   RECT 241.6560 104.1480 241.7040 104.1960 ;
  END
 END rd[897]
 PIN wd[898]
  DIRECTION INPUT ;
  USE SIGNAL ;
  PORT
   LAYER M4 ;
   RECT 241.6560 104.3400 241.7040 104.3880 ;
  END
 END wd[898]
 PIN rd[898]
  DIRECTION OUTPUT ;
  USE SIGNAL ;
  PORT
   LAYER M4 ;
   RECT 241.6560 104.5320 241.7040 104.5800 ;
  END
 END rd[898]
 PIN wd[899]
  DIRECTION INPUT ;
  USE SIGNAL ;
  PORT
   LAYER M4 ;
   RECT 241.6560 104.7240 241.7040 104.7720 ;
  END
 END wd[899]
 PIN rd[899]
  DIRECTION OUTPUT ;
  USE SIGNAL ;
  PORT
   LAYER M4 ;
   RECT 241.6560 104.9160 241.7040 104.9640 ;
  END
 END rd[899]
 PIN wd[900]
  DIRECTION INPUT ;
  USE SIGNAL ;
  PORT
   LAYER M4 ;
   RECT 241.6560 105.1080 241.7040 105.1560 ;
  END
 END wd[900]
 PIN rd[900]
  DIRECTION OUTPUT ;
  USE SIGNAL ;
  PORT
   LAYER M4 ;
   RECT 241.6560 105.3000 241.7040 105.3480 ;
  END
 END rd[900]
 PIN wd[901]
  DIRECTION INPUT ;
  USE SIGNAL ;
  PORT
   LAYER M4 ;
   RECT 241.6560 105.4920 241.7040 105.5400 ;
  END
 END wd[901]
 PIN rd[901]
  DIRECTION OUTPUT ;
  USE SIGNAL ;
  PORT
   LAYER M4 ;
   RECT 241.6560 105.6840 241.7040 105.7320 ;
  END
 END rd[901]
 PIN wd[902]
  DIRECTION INPUT ;
  USE SIGNAL ;
  PORT
   LAYER M4 ;
   RECT 241.6560 105.8760 241.7040 105.9240 ;
  END
 END wd[902]
 PIN rd[902]
  DIRECTION OUTPUT ;
  USE SIGNAL ;
  PORT
   LAYER M4 ;
   RECT 241.6560 106.0680 241.7040 106.1160 ;
  END
 END rd[902]
 PIN wd[903]
  DIRECTION INPUT ;
  USE SIGNAL ;
  PORT
   LAYER M4 ;
   RECT 241.6560 106.2600 241.7040 106.3080 ;
  END
 END wd[903]
 PIN rd[903]
  DIRECTION OUTPUT ;
  USE SIGNAL ;
  PORT
   LAYER M4 ;
   RECT 241.6560 106.4520 241.7040 106.5000 ;
  END
 END rd[903]
 PIN wd[904]
  DIRECTION INPUT ;
  USE SIGNAL ;
  PORT
   LAYER M4 ;
   RECT 241.6560 106.6440 241.7040 106.6920 ;
  END
 END wd[904]
 PIN rd[904]
  DIRECTION OUTPUT ;
  USE SIGNAL ;
  PORT
   LAYER M4 ;
   RECT 241.6560 106.8360 241.7040 106.8840 ;
  END
 END rd[904]
 PIN wd[905]
  DIRECTION INPUT ;
  USE SIGNAL ;
  PORT
   LAYER M4 ;
   RECT 241.6560 107.0280 241.7040 107.0760 ;
  END
 END wd[905]
 PIN rd[905]
  DIRECTION OUTPUT ;
  USE SIGNAL ;
  PORT
   LAYER M4 ;
   RECT 241.6560 107.2200 241.7040 107.2680 ;
  END
 END rd[905]
 PIN wd[906]
  DIRECTION INPUT ;
  USE SIGNAL ;
  PORT
   LAYER M4 ;
   RECT 241.6560 107.4120 241.7040 107.4600 ;
  END
 END wd[906]
 PIN rd[906]
  DIRECTION OUTPUT ;
  USE SIGNAL ;
  PORT
   LAYER M4 ;
   RECT 241.6560 107.6040 241.7040 107.6520 ;
  END
 END rd[906]
 PIN wd[907]
  DIRECTION INPUT ;
  USE SIGNAL ;
  PORT
   LAYER M4 ;
   RECT 241.6560 107.7960 241.7040 107.8440 ;
  END
 END wd[907]
 PIN rd[907]
  DIRECTION OUTPUT ;
  USE SIGNAL ;
  PORT
   LAYER M4 ;
   RECT 241.6560 107.9880 241.7040 108.0360 ;
  END
 END rd[907]
 PIN wd[908]
  DIRECTION INPUT ;
  USE SIGNAL ;
  PORT
   LAYER M4 ;
   RECT 241.6560 108.1800 241.7040 108.2280 ;
  END
 END wd[908]
 PIN rd[908]
  DIRECTION OUTPUT ;
  USE SIGNAL ;
  PORT
   LAYER M4 ;
   RECT 241.6560 108.3720 241.7040 108.4200 ;
  END
 END rd[908]
 PIN wd[909]
  DIRECTION INPUT ;
  USE SIGNAL ;
  PORT
   LAYER M4 ;
   RECT 241.6560 108.5640 241.7040 108.6120 ;
  END
 END wd[909]
 PIN rd[909]
  DIRECTION OUTPUT ;
  USE SIGNAL ;
  PORT
   LAYER M4 ;
   RECT 241.6560 108.7560 241.7040 108.8040 ;
  END
 END rd[909]
 PIN wd[910]
  DIRECTION INPUT ;
  USE SIGNAL ;
  PORT
   LAYER M4 ;
   RECT 241.6560 108.9480 241.7040 108.9960 ;
  END
 END wd[910]
 PIN rd[910]
  DIRECTION OUTPUT ;
  USE SIGNAL ;
  PORT
   LAYER M4 ;
   RECT 241.6560 109.1400 241.7040 109.1880 ;
  END
 END rd[910]
 PIN wd[911]
  DIRECTION INPUT ;
  USE SIGNAL ;
  PORT
   LAYER M4 ;
   RECT 241.6560 109.3320 241.7040 109.3800 ;
  END
 END wd[911]
 PIN rd[911]
  DIRECTION OUTPUT ;
  USE SIGNAL ;
  PORT
   LAYER M4 ;
   RECT 241.6560 109.5240 241.7040 109.5720 ;
  END
 END rd[911]
 PIN wd[912]
  DIRECTION INPUT ;
  USE SIGNAL ;
  PORT
   LAYER M4 ;
   RECT 241.6560 109.7160 241.7040 109.7640 ;
  END
 END wd[912]
 PIN rd[912]
  DIRECTION OUTPUT ;
  USE SIGNAL ;
  PORT
   LAYER M4 ;
   RECT 241.6560 109.9080 241.7040 109.9560 ;
  END
 END rd[912]
 PIN wd[913]
  DIRECTION INPUT ;
  USE SIGNAL ;
  PORT
   LAYER M4 ;
   RECT 241.6560 110.1000 241.7040 110.1480 ;
  END
 END wd[913]
 PIN rd[913]
  DIRECTION OUTPUT ;
  USE SIGNAL ;
  PORT
   LAYER M4 ;
   RECT 241.6560 110.2920 241.7040 110.3400 ;
  END
 END rd[913]
 PIN wd[914]
  DIRECTION INPUT ;
  USE SIGNAL ;
  PORT
   LAYER M4 ;
   RECT 241.6560 110.4840 241.7040 110.5320 ;
  END
 END wd[914]
 PIN rd[914]
  DIRECTION OUTPUT ;
  USE SIGNAL ;
  PORT
   LAYER M4 ;
   RECT 241.6560 110.6760 241.7040 110.7240 ;
  END
 END rd[914]
 PIN wd[915]
  DIRECTION INPUT ;
  USE SIGNAL ;
  PORT
   LAYER M4 ;
   RECT 241.6560 110.8680 241.7040 110.9160 ;
  END
 END wd[915]
 PIN rd[915]
  DIRECTION OUTPUT ;
  USE SIGNAL ;
  PORT
   LAYER M4 ;
   RECT 241.6560 111.0600 241.7040 111.1080 ;
  END
 END rd[915]
 PIN wd[916]
  DIRECTION INPUT ;
  USE SIGNAL ;
  PORT
   LAYER M4 ;
   RECT 241.6560 111.2520 241.7040 111.3000 ;
  END
 END wd[916]
 PIN rd[916]
  DIRECTION OUTPUT ;
  USE SIGNAL ;
  PORT
   LAYER M4 ;
   RECT 241.6560 111.4440 241.7040 111.4920 ;
  END
 END rd[916]
 PIN wd[917]
  DIRECTION INPUT ;
  USE SIGNAL ;
  PORT
   LAYER M4 ;
   RECT 241.6560 111.6360 241.7040 111.6840 ;
  END
 END wd[917]
 PIN rd[917]
  DIRECTION OUTPUT ;
  USE SIGNAL ;
  PORT
   LAYER M4 ;
   RECT 241.6560 111.8280 241.7040 111.8760 ;
  END
 END rd[917]
 PIN wd[918]
  DIRECTION INPUT ;
  USE SIGNAL ;
  PORT
   LAYER M4 ;
   RECT 241.6560 112.0200 241.7040 112.0680 ;
  END
 END wd[918]
 PIN rd[918]
  DIRECTION OUTPUT ;
  USE SIGNAL ;
  PORT
   LAYER M4 ;
   RECT 241.6560 112.2120 241.7040 112.2600 ;
  END
 END rd[918]
 PIN wd[919]
  DIRECTION INPUT ;
  USE SIGNAL ;
  PORT
   LAYER M4 ;
   RECT 241.6560 112.4040 241.7040 112.4520 ;
  END
 END wd[919]
 PIN rd[919]
  DIRECTION OUTPUT ;
  USE SIGNAL ;
  PORT
   LAYER M4 ;
   RECT 241.6560 112.5960 241.7040 112.6440 ;
  END
 END rd[919]
 PIN wd[920]
  DIRECTION INPUT ;
  USE SIGNAL ;
  PORT
   LAYER M4 ;
   RECT 241.6560 112.7880 241.7040 112.8360 ;
  END
 END wd[920]
 PIN rd[920]
  DIRECTION OUTPUT ;
  USE SIGNAL ;
  PORT
   LAYER M4 ;
   RECT 241.6560 112.9800 241.7040 113.0280 ;
  END
 END rd[920]
 PIN wd[921]
  DIRECTION INPUT ;
  USE SIGNAL ;
  PORT
   LAYER M4 ;
   RECT 241.6560 113.1720 241.7040 113.2200 ;
  END
 END wd[921]
 PIN rd[921]
  DIRECTION OUTPUT ;
  USE SIGNAL ;
  PORT
   LAYER M4 ;
   RECT 241.6560 113.3640 241.7040 113.4120 ;
  END
 END rd[921]
 PIN wd[922]
  DIRECTION INPUT ;
  USE SIGNAL ;
  PORT
   LAYER M4 ;
   RECT 241.6560 113.5560 241.7040 113.6040 ;
  END
 END wd[922]
 PIN rd[922]
  DIRECTION OUTPUT ;
  USE SIGNAL ;
  PORT
   LAYER M4 ;
   RECT 241.6560 113.7480 241.7040 113.7960 ;
  END
 END rd[922]
 PIN wd[923]
  DIRECTION INPUT ;
  USE SIGNAL ;
  PORT
   LAYER M4 ;
   RECT 241.6560 113.9400 241.7040 113.9880 ;
  END
 END wd[923]
 PIN rd[923]
  DIRECTION OUTPUT ;
  USE SIGNAL ;
  PORT
   LAYER M4 ;
   RECT 241.6560 114.1320 241.7040 114.1800 ;
  END
 END rd[923]
 PIN wd[924]
  DIRECTION INPUT ;
  USE SIGNAL ;
  PORT
   LAYER M4 ;
   RECT 241.6560 114.3240 241.7040 114.3720 ;
  END
 END wd[924]
 PIN rd[924]
  DIRECTION OUTPUT ;
  USE SIGNAL ;
  PORT
   LAYER M4 ;
   RECT 241.6560 114.5160 241.7040 114.5640 ;
  END
 END rd[924]
 PIN wd[925]
  DIRECTION INPUT ;
  USE SIGNAL ;
  PORT
   LAYER M4 ;
   RECT 241.6560 114.7080 241.7040 114.7560 ;
  END
 END wd[925]
 PIN rd[925]
  DIRECTION OUTPUT ;
  USE SIGNAL ;
  PORT
   LAYER M4 ;
   RECT 241.6560 114.9000 241.7040 114.9480 ;
  END
 END rd[925]
 PIN wd[926]
  DIRECTION INPUT ;
  USE SIGNAL ;
  PORT
   LAYER M4 ;
   RECT 241.6560 115.0920 241.7040 115.1400 ;
  END
 END wd[926]
 PIN rd[926]
  DIRECTION OUTPUT ;
  USE SIGNAL ;
  PORT
   LAYER M4 ;
   RECT 241.6560 115.2840 241.7040 115.3320 ;
  END
 END rd[926]
 PIN wd[927]
  DIRECTION INPUT ;
  USE SIGNAL ;
  PORT
   LAYER M4 ;
   RECT 241.6560 115.4760 241.7040 115.5240 ;
  END
 END wd[927]
 PIN rd[927]
  DIRECTION OUTPUT ;
  USE SIGNAL ;
  PORT
   LAYER M4 ;
   RECT 241.6560 115.6680 241.7040 115.7160 ;
  END
 END rd[927]
 PIN wd[928]
  DIRECTION INPUT ;
  USE SIGNAL ;
  PORT
   LAYER M4 ;
   RECT 241.6560 115.8600 241.7040 115.9080 ;
  END
 END wd[928]
 PIN rd[928]
  DIRECTION OUTPUT ;
  USE SIGNAL ;
  PORT
   LAYER M4 ;
   RECT 241.6560 116.0520 241.7040 116.1000 ;
  END
 END rd[928]
 PIN wd[929]
  DIRECTION INPUT ;
  USE SIGNAL ;
  PORT
   LAYER M4 ;
   RECT 241.6560 116.2440 241.7040 116.2920 ;
  END
 END wd[929]
 PIN rd[929]
  DIRECTION OUTPUT ;
  USE SIGNAL ;
  PORT
   LAYER M4 ;
   RECT 241.6560 116.4360 241.7040 116.4840 ;
  END
 END rd[929]
 PIN wd[930]
  DIRECTION INPUT ;
  USE SIGNAL ;
  PORT
   LAYER M4 ;
   RECT 241.6560 116.6280 241.7040 116.6760 ;
  END
 END wd[930]
 PIN rd[930]
  DIRECTION OUTPUT ;
  USE SIGNAL ;
  PORT
   LAYER M4 ;
   RECT 241.6560 116.8200 241.7040 116.8680 ;
  END
 END rd[930]
 PIN wd[931]
  DIRECTION INPUT ;
  USE SIGNAL ;
  PORT
   LAYER M4 ;
   RECT 241.6560 117.0120 241.7040 117.0600 ;
  END
 END wd[931]
 PIN rd[931]
  DIRECTION OUTPUT ;
  USE SIGNAL ;
  PORT
   LAYER M4 ;
   RECT 241.6560 117.2040 241.7040 117.2520 ;
  END
 END rd[931]
 PIN wd[932]
  DIRECTION INPUT ;
  USE SIGNAL ;
  PORT
   LAYER M4 ;
   RECT 241.6560 117.3960 241.7040 117.4440 ;
  END
 END wd[932]
 PIN rd[932]
  DIRECTION OUTPUT ;
  USE SIGNAL ;
  PORT
   LAYER M4 ;
   RECT 241.6560 117.5880 241.7040 117.6360 ;
  END
 END rd[932]
 PIN wd[933]
  DIRECTION INPUT ;
  USE SIGNAL ;
  PORT
   LAYER M4 ;
   RECT 241.6560 117.7800 241.7040 117.8280 ;
  END
 END wd[933]
 PIN rd[933]
  DIRECTION OUTPUT ;
  USE SIGNAL ;
  PORT
   LAYER M4 ;
   RECT 241.6560 117.9720 241.7040 118.0200 ;
  END
 END rd[933]
 PIN wd[934]
  DIRECTION INPUT ;
  USE SIGNAL ;
  PORT
   LAYER M4 ;
   RECT 241.6560 118.1640 241.7040 118.2120 ;
  END
 END wd[934]
 PIN rd[934]
  DIRECTION OUTPUT ;
  USE SIGNAL ;
  PORT
   LAYER M4 ;
   RECT 241.6560 118.3560 241.7040 118.4040 ;
  END
 END rd[934]
 PIN wd[935]
  DIRECTION INPUT ;
  USE SIGNAL ;
  PORT
   LAYER M4 ;
   RECT 241.6560 118.5480 241.7040 118.5960 ;
  END
 END wd[935]
 PIN rd[935]
  DIRECTION OUTPUT ;
  USE SIGNAL ;
  PORT
   LAYER M4 ;
   RECT 241.6560 118.7400 241.7040 118.7880 ;
  END
 END rd[935]
 PIN wd[936]
  DIRECTION INPUT ;
  USE SIGNAL ;
  PORT
   LAYER M4 ;
   RECT 241.6560 118.9320 241.7040 118.9800 ;
  END
 END wd[936]
 PIN rd[936]
  DIRECTION OUTPUT ;
  USE SIGNAL ;
  PORT
   LAYER M4 ;
   RECT 241.6560 119.1240 241.7040 119.1720 ;
  END
 END rd[936]
 PIN wd[937]
  DIRECTION INPUT ;
  USE SIGNAL ;
  PORT
   LAYER M4 ;
   RECT 241.6560 119.3160 241.7040 119.3640 ;
  END
 END wd[937]
 PIN rd[937]
  DIRECTION OUTPUT ;
  USE SIGNAL ;
  PORT
   LAYER M4 ;
   RECT 241.6560 119.5080 241.7040 119.5560 ;
  END
 END rd[937]
 PIN wd[938]
  DIRECTION INPUT ;
  USE SIGNAL ;
  PORT
   LAYER M4 ;
   RECT 241.6560 119.7000 241.7040 119.7480 ;
  END
 END wd[938]
 PIN rd[938]
  DIRECTION OUTPUT ;
  USE SIGNAL ;
  PORT
   LAYER M4 ;
   RECT 241.6560 119.8920 241.7040 119.9400 ;
  END
 END rd[938]
 PIN wd[939]
  DIRECTION INPUT ;
  USE SIGNAL ;
  PORT
   LAYER M4 ;
   RECT 241.6560 120.0840 241.7040 120.1320 ;
  END
 END wd[939]
 PIN rd[939]
  DIRECTION OUTPUT ;
  USE SIGNAL ;
  PORT
   LAYER M4 ;
   RECT 241.6560 120.2760 241.7040 120.3240 ;
  END
 END rd[939]
 PIN wd[940]
  DIRECTION INPUT ;
  USE SIGNAL ;
  PORT
   LAYER M4 ;
   RECT 241.6560 120.4680 241.7040 120.5160 ;
  END
 END wd[940]
 PIN rd[940]
  DIRECTION OUTPUT ;
  USE SIGNAL ;
  PORT
   LAYER M4 ;
   RECT 241.6560 120.6600 241.7040 120.7080 ;
  END
 END rd[940]
 PIN wd[941]
  DIRECTION INPUT ;
  USE SIGNAL ;
  PORT
   LAYER M4 ;
   RECT 241.6560 120.8520 241.7040 120.9000 ;
  END
 END wd[941]
 PIN rd[941]
  DIRECTION OUTPUT ;
  USE SIGNAL ;
  PORT
   LAYER M4 ;
   RECT 241.6560 121.0440 241.7040 121.0920 ;
  END
 END rd[941]
 PIN wd[942]
  DIRECTION INPUT ;
  USE SIGNAL ;
  PORT
   LAYER M4 ;
   RECT 241.6560 121.2360 241.7040 121.2840 ;
  END
 END wd[942]
 PIN rd[942]
  DIRECTION OUTPUT ;
  USE SIGNAL ;
  PORT
   LAYER M4 ;
   RECT 241.6560 121.4280 241.7040 121.4760 ;
  END
 END rd[942]
 PIN wd[943]
  DIRECTION INPUT ;
  USE SIGNAL ;
  PORT
   LAYER M4 ;
   RECT 241.6560 121.6200 241.7040 121.6680 ;
  END
 END wd[943]
 PIN rd[943]
  DIRECTION OUTPUT ;
  USE SIGNAL ;
  PORT
   LAYER M4 ;
   RECT 241.6560 121.8120 241.7040 121.8600 ;
  END
 END rd[943]
 PIN wd[944]
  DIRECTION INPUT ;
  USE SIGNAL ;
  PORT
   LAYER M4 ;
   RECT 241.6560 122.0040 241.7040 122.0520 ;
  END
 END wd[944]
 PIN rd[944]
  DIRECTION OUTPUT ;
  USE SIGNAL ;
  PORT
   LAYER M4 ;
   RECT 241.6560 122.1960 241.7040 122.2440 ;
  END
 END rd[944]
 PIN wd[945]
  DIRECTION INPUT ;
  USE SIGNAL ;
  PORT
   LAYER M4 ;
   RECT 241.6560 122.3880 241.7040 122.4360 ;
  END
 END wd[945]
 PIN rd[945]
  DIRECTION OUTPUT ;
  USE SIGNAL ;
  PORT
   LAYER M4 ;
   RECT 241.6560 122.5800 241.7040 122.6280 ;
  END
 END rd[945]
 PIN wd[946]
  DIRECTION INPUT ;
  USE SIGNAL ;
  PORT
   LAYER M4 ;
   RECT 241.6560 122.7720 241.7040 122.8200 ;
  END
 END wd[946]
 PIN rd[946]
  DIRECTION OUTPUT ;
  USE SIGNAL ;
  PORT
   LAYER M4 ;
   RECT 241.6560 122.9640 241.7040 123.0120 ;
  END
 END rd[946]
 PIN wd[947]
  DIRECTION INPUT ;
  USE SIGNAL ;
  PORT
   LAYER M4 ;
   RECT 241.6560 123.1560 241.7040 123.2040 ;
  END
 END wd[947]
 PIN rd[947]
  DIRECTION OUTPUT ;
  USE SIGNAL ;
  PORT
   LAYER M4 ;
   RECT 241.6560 123.3480 241.7040 123.3960 ;
  END
 END rd[947]
 PIN wd[948]
  DIRECTION INPUT ;
  USE SIGNAL ;
  PORT
   LAYER M4 ;
   RECT 241.6560 123.5400 241.7040 123.5880 ;
  END
 END wd[948]
 PIN rd[948]
  DIRECTION OUTPUT ;
  USE SIGNAL ;
  PORT
   LAYER M4 ;
   RECT 241.6560 123.7320 241.7040 123.7800 ;
  END
 END rd[948]
 PIN wd[949]
  DIRECTION INPUT ;
  USE SIGNAL ;
  PORT
   LAYER M4 ;
   RECT 241.6560 123.9240 241.7040 123.9720 ;
  END
 END wd[949]
 PIN rd[949]
  DIRECTION OUTPUT ;
  USE SIGNAL ;
  PORT
   LAYER M4 ;
   RECT 241.6560 124.1160 241.7040 124.1640 ;
  END
 END rd[949]
 PIN wd[950]
  DIRECTION INPUT ;
  USE SIGNAL ;
  PORT
   LAYER M4 ;
   RECT 241.6560 124.3080 241.7040 124.3560 ;
  END
 END wd[950]
 PIN rd[950]
  DIRECTION OUTPUT ;
  USE SIGNAL ;
  PORT
   LAYER M4 ;
   RECT 241.6560 124.5000 241.7040 124.5480 ;
  END
 END rd[950]
 PIN wd[951]
  DIRECTION INPUT ;
  USE SIGNAL ;
  PORT
   LAYER M4 ;
   RECT 241.6560 124.6920 241.7040 124.7400 ;
  END
 END wd[951]
 PIN rd[951]
  DIRECTION OUTPUT ;
  USE SIGNAL ;
  PORT
   LAYER M4 ;
   RECT 241.6560 124.8840 241.7040 124.9320 ;
  END
 END rd[951]
 PIN wd[952]
  DIRECTION INPUT ;
  USE SIGNAL ;
  PORT
   LAYER M4 ;
   RECT 241.6560 125.0760 241.7040 125.1240 ;
  END
 END wd[952]
 PIN rd[952]
  DIRECTION OUTPUT ;
  USE SIGNAL ;
  PORT
   LAYER M4 ;
   RECT 241.6560 125.2680 241.7040 125.3160 ;
  END
 END rd[952]
 PIN wd[953]
  DIRECTION INPUT ;
  USE SIGNAL ;
  PORT
   LAYER M4 ;
   RECT 241.6560 125.4600 241.7040 125.5080 ;
  END
 END wd[953]
 PIN rd[953]
  DIRECTION OUTPUT ;
  USE SIGNAL ;
  PORT
   LAYER M4 ;
   RECT 241.6560 125.6520 241.7040 125.7000 ;
  END
 END rd[953]
 PIN wd[954]
  DIRECTION INPUT ;
  USE SIGNAL ;
  PORT
   LAYER M4 ;
   RECT 241.6560 125.8440 241.7040 125.8920 ;
  END
 END wd[954]
 PIN rd[954]
  DIRECTION OUTPUT ;
  USE SIGNAL ;
  PORT
   LAYER M4 ;
   RECT 241.6560 126.0360 241.7040 126.0840 ;
  END
 END rd[954]
 PIN wd[955]
  DIRECTION INPUT ;
  USE SIGNAL ;
  PORT
   LAYER M4 ;
   RECT 241.6560 126.2280 241.7040 126.2760 ;
  END
 END wd[955]
 PIN rd[955]
  DIRECTION OUTPUT ;
  USE SIGNAL ;
  PORT
   LAYER M4 ;
   RECT 241.6560 126.4200 241.7040 126.4680 ;
  END
 END rd[955]
 PIN wd[956]
  DIRECTION INPUT ;
  USE SIGNAL ;
  PORT
   LAYER M4 ;
   RECT 241.6560 126.6120 241.7040 126.6600 ;
  END
 END wd[956]
 PIN rd[956]
  DIRECTION OUTPUT ;
  USE SIGNAL ;
  PORT
   LAYER M4 ;
   RECT 241.6560 126.8040 241.7040 126.8520 ;
  END
 END rd[956]
 PIN wd[957]
  DIRECTION INPUT ;
  USE SIGNAL ;
  PORT
   LAYER M4 ;
   RECT 241.6560 126.9960 241.7040 127.0440 ;
  END
 END wd[957]
 PIN rd[957]
  DIRECTION OUTPUT ;
  USE SIGNAL ;
  PORT
   LAYER M4 ;
   RECT 241.6560 127.1880 241.7040 127.2360 ;
  END
 END rd[957]
 PIN wd[958]
  DIRECTION INPUT ;
  USE SIGNAL ;
  PORT
   LAYER M4 ;
   RECT 241.6560 127.3800 241.7040 127.4280 ;
  END
 END wd[958]
 PIN rd[958]
  DIRECTION OUTPUT ;
  USE SIGNAL ;
  PORT
   LAYER M4 ;
   RECT 241.6560 127.5720 241.7040 127.6200 ;
  END
 END rd[958]
 PIN wd[959]
  DIRECTION INPUT ;
  USE SIGNAL ;
  PORT
   LAYER M4 ;
   RECT 241.6560 127.7640 241.7040 127.8120 ;
  END
 END wd[959]
 PIN rd[959]
  DIRECTION OUTPUT ;
  USE SIGNAL ;
  PORT
   LAYER M4 ;
   RECT 241.6560 127.9560 241.7040 128.0040 ;
  END
 END rd[959]
 PIN wd[960]
  DIRECTION INPUT ;
  USE SIGNAL ;
  PORT
   LAYER M4 ;
   RECT 241.6560 128.1480 241.7040 128.1960 ;
  END
 END wd[960]
 PIN rd[960]
  DIRECTION OUTPUT ;
  USE SIGNAL ;
  PORT
   LAYER M4 ;
   RECT 241.6560 128.3400 241.7040 128.3880 ;
  END
 END rd[960]
 PIN wd[961]
  DIRECTION INPUT ;
  USE SIGNAL ;
  PORT
   LAYER M4 ;
   RECT 241.6560 128.5320 241.7040 128.5800 ;
  END
 END wd[961]
 PIN rd[961]
  DIRECTION OUTPUT ;
  USE SIGNAL ;
  PORT
   LAYER M4 ;
   RECT 241.6560 128.7240 241.7040 128.7720 ;
  END
 END rd[961]
 PIN wd[962]
  DIRECTION INPUT ;
  USE SIGNAL ;
  PORT
   LAYER M4 ;
   RECT 241.6560 128.9160 241.7040 128.9640 ;
  END
 END wd[962]
 PIN rd[962]
  DIRECTION OUTPUT ;
  USE SIGNAL ;
  PORT
   LAYER M4 ;
   RECT 241.6560 129.1080 241.7040 129.1560 ;
  END
 END rd[962]
 PIN wd[963]
  DIRECTION INPUT ;
  USE SIGNAL ;
  PORT
   LAYER M4 ;
   RECT 241.6560 129.3000 241.7040 129.3480 ;
  END
 END wd[963]
 PIN rd[963]
  DIRECTION OUTPUT ;
  USE SIGNAL ;
  PORT
   LAYER M4 ;
   RECT 241.6560 129.4920 241.7040 129.5400 ;
  END
 END rd[963]
 PIN wd[964]
  DIRECTION INPUT ;
  USE SIGNAL ;
  PORT
   LAYER M4 ;
   RECT 241.6560 129.6840 241.7040 129.7320 ;
  END
 END wd[964]
 PIN rd[964]
  DIRECTION OUTPUT ;
  USE SIGNAL ;
  PORT
   LAYER M4 ;
   RECT 241.6560 129.8760 241.7040 129.9240 ;
  END
 END rd[964]
 PIN wd[965]
  DIRECTION INPUT ;
  USE SIGNAL ;
  PORT
   LAYER M4 ;
   RECT 241.6560 130.0680 241.7040 130.1160 ;
  END
 END wd[965]
 PIN rd[965]
  DIRECTION OUTPUT ;
  USE SIGNAL ;
  PORT
   LAYER M4 ;
   RECT 241.6560 130.2600 241.7040 130.3080 ;
  END
 END rd[965]
 PIN wd[966]
  DIRECTION INPUT ;
  USE SIGNAL ;
  PORT
   LAYER M4 ;
   RECT 241.6560 130.4520 241.7040 130.5000 ;
  END
 END wd[966]
 PIN rd[966]
  DIRECTION OUTPUT ;
  USE SIGNAL ;
  PORT
   LAYER M4 ;
   RECT 241.6560 130.6440 241.7040 130.6920 ;
  END
 END rd[966]
 PIN wd[967]
  DIRECTION INPUT ;
  USE SIGNAL ;
  PORT
   LAYER M4 ;
   RECT 241.6560 130.8360 241.7040 130.8840 ;
  END
 END wd[967]
 PIN rd[967]
  DIRECTION OUTPUT ;
  USE SIGNAL ;
  PORT
   LAYER M4 ;
   RECT 241.6560 131.0280 241.7040 131.0760 ;
  END
 END rd[967]
 PIN wd[968]
  DIRECTION INPUT ;
  USE SIGNAL ;
  PORT
   LAYER M4 ;
   RECT 241.6560 131.2200 241.7040 131.2680 ;
  END
 END wd[968]
 PIN rd[968]
  DIRECTION OUTPUT ;
  USE SIGNAL ;
  PORT
   LAYER M4 ;
   RECT 241.6560 131.4120 241.7040 131.4600 ;
  END
 END rd[968]
 PIN wd[969]
  DIRECTION INPUT ;
  USE SIGNAL ;
  PORT
   LAYER M4 ;
   RECT 241.6560 131.6040 241.7040 131.6520 ;
  END
 END wd[969]
 PIN rd[969]
  DIRECTION OUTPUT ;
  USE SIGNAL ;
  PORT
   LAYER M4 ;
   RECT 241.6560 131.7960 241.7040 131.8440 ;
  END
 END rd[969]
 PIN wd[970]
  DIRECTION INPUT ;
  USE SIGNAL ;
  PORT
   LAYER M4 ;
   RECT 241.6560 131.9880 241.7040 132.0360 ;
  END
 END wd[970]
 PIN rd[970]
  DIRECTION OUTPUT ;
  USE SIGNAL ;
  PORT
   LAYER M4 ;
   RECT 241.6560 132.1800 241.7040 132.2280 ;
  END
 END rd[970]
 PIN wd[971]
  DIRECTION INPUT ;
  USE SIGNAL ;
  PORT
   LAYER M4 ;
   RECT 241.6560 132.3720 241.7040 132.4200 ;
  END
 END wd[971]
 PIN rd[971]
  DIRECTION OUTPUT ;
  USE SIGNAL ;
  PORT
   LAYER M4 ;
   RECT 241.6560 132.5640 241.7040 132.6120 ;
  END
 END rd[971]
 PIN wd[972]
  DIRECTION INPUT ;
  USE SIGNAL ;
  PORT
   LAYER M4 ;
   RECT 241.6560 132.7560 241.7040 132.8040 ;
  END
 END wd[972]
 PIN rd[972]
  DIRECTION OUTPUT ;
  USE SIGNAL ;
  PORT
   LAYER M4 ;
   RECT 241.6560 132.9480 241.7040 132.9960 ;
  END
 END rd[972]
 PIN wd[973]
  DIRECTION INPUT ;
  USE SIGNAL ;
  PORT
   LAYER M4 ;
   RECT 241.6560 133.1400 241.7040 133.1880 ;
  END
 END wd[973]
 PIN rd[973]
  DIRECTION OUTPUT ;
  USE SIGNAL ;
  PORT
   LAYER M4 ;
   RECT 241.6560 133.3320 241.7040 133.3800 ;
  END
 END rd[973]
 PIN wd[974]
  DIRECTION INPUT ;
  USE SIGNAL ;
  PORT
   LAYER M4 ;
   RECT 241.6560 133.5240 241.7040 133.5720 ;
  END
 END wd[974]
 PIN rd[974]
  DIRECTION OUTPUT ;
  USE SIGNAL ;
  PORT
   LAYER M4 ;
   RECT 241.6560 133.7160 241.7040 133.7640 ;
  END
 END rd[974]
 PIN wd[975]
  DIRECTION INPUT ;
  USE SIGNAL ;
  PORT
   LAYER M4 ;
   RECT 241.6560 133.9080 241.7040 133.9560 ;
  END
 END wd[975]
 PIN rd[975]
  DIRECTION OUTPUT ;
  USE SIGNAL ;
  PORT
   LAYER M4 ;
   RECT 241.6560 134.1000 241.7040 134.1480 ;
  END
 END rd[975]
 PIN wd[976]
  DIRECTION INPUT ;
  USE SIGNAL ;
  PORT
   LAYER M4 ;
   RECT 241.6560 134.2920 241.7040 134.3400 ;
  END
 END wd[976]
 PIN rd[976]
  DIRECTION OUTPUT ;
  USE SIGNAL ;
  PORT
   LAYER M4 ;
   RECT 241.6560 134.4840 241.7040 134.5320 ;
  END
 END rd[976]
 PIN wd[977]
  DIRECTION INPUT ;
  USE SIGNAL ;
  PORT
   LAYER M4 ;
   RECT 241.6560 134.6760 241.7040 134.7240 ;
  END
 END wd[977]
 PIN rd[977]
  DIRECTION OUTPUT ;
  USE SIGNAL ;
  PORT
   LAYER M4 ;
   RECT 241.6560 134.8680 241.7040 134.9160 ;
  END
 END rd[977]
 PIN wd[978]
  DIRECTION INPUT ;
  USE SIGNAL ;
  PORT
   LAYER M4 ;
   RECT 241.6560 135.0600 241.7040 135.1080 ;
  END
 END wd[978]
 PIN rd[978]
  DIRECTION OUTPUT ;
  USE SIGNAL ;
  PORT
   LAYER M4 ;
   RECT 241.6560 135.2520 241.7040 135.3000 ;
  END
 END rd[978]
 PIN wd[979]
  DIRECTION INPUT ;
  USE SIGNAL ;
  PORT
   LAYER M4 ;
   RECT 241.6560 135.4440 241.7040 135.4920 ;
  END
 END wd[979]
 PIN rd[979]
  DIRECTION OUTPUT ;
  USE SIGNAL ;
  PORT
   LAYER M4 ;
   RECT 241.6560 135.6360 241.7040 135.6840 ;
  END
 END rd[979]
 PIN wd[980]
  DIRECTION INPUT ;
  USE SIGNAL ;
  PORT
   LAYER M4 ;
   RECT 241.6560 135.8280 241.7040 135.8760 ;
  END
 END wd[980]
 PIN rd[980]
  DIRECTION OUTPUT ;
  USE SIGNAL ;
  PORT
   LAYER M4 ;
   RECT 241.6560 136.0200 241.7040 136.0680 ;
  END
 END rd[980]
 PIN wd[981]
  DIRECTION INPUT ;
  USE SIGNAL ;
  PORT
   LAYER M4 ;
   RECT 241.6560 136.2120 241.7040 136.2600 ;
  END
 END wd[981]
 PIN rd[981]
  DIRECTION OUTPUT ;
  USE SIGNAL ;
  PORT
   LAYER M4 ;
   RECT 241.6560 136.4040 241.7040 136.4520 ;
  END
 END rd[981]
 PIN wd[982]
  DIRECTION INPUT ;
  USE SIGNAL ;
  PORT
   LAYER M4 ;
   RECT 241.6560 136.5960 241.7040 136.6440 ;
  END
 END wd[982]
 PIN rd[982]
  DIRECTION OUTPUT ;
  USE SIGNAL ;
  PORT
   LAYER M4 ;
   RECT 241.6560 136.7880 241.7040 136.8360 ;
  END
 END rd[982]
 PIN wd[983]
  DIRECTION INPUT ;
  USE SIGNAL ;
  PORT
   LAYER M4 ;
   RECT 241.6560 136.9800 241.7040 137.0280 ;
  END
 END wd[983]
 PIN rd[983]
  DIRECTION OUTPUT ;
  USE SIGNAL ;
  PORT
   LAYER M4 ;
   RECT 241.6560 137.1720 241.7040 137.2200 ;
  END
 END rd[983]
 PIN wd[984]
  DIRECTION INPUT ;
  USE SIGNAL ;
  PORT
   LAYER M4 ;
   RECT 241.6560 137.3640 241.7040 137.4120 ;
  END
 END wd[984]
 PIN rd[984]
  DIRECTION OUTPUT ;
  USE SIGNAL ;
  PORT
   LAYER M4 ;
   RECT 241.6560 137.5560 241.7040 137.6040 ;
  END
 END rd[984]
 PIN wd[985]
  DIRECTION INPUT ;
  USE SIGNAL ;
  PORT
   LAYER M4 ;
   RECT 241.6560 137.7480 241.7040 137.7960 ;
  END
 END wd[985]
 PIN rd[985]
  DIRECTION OUTPUT ;
  USE SIGNAL ;
  PORT
   LAYER M4 ;
   RECT 241.6560 137.9400 241.7040 137.9880 ;
  END
 END rd[985]
 PIN wd[986]
  DIRECTION INPUT ;
  USE SIGNAL ;
  PORT
   LAYER M4 ;
   RECT 241.6560 138.1320 241.7040 138.1800 ;
  END
 END wd[986]
 PIN rd[986]
  DIRECTION OUTPUT ;
  USE SIGNAL ;
  PORT
   LAYER M4 ;
   RECT 241.6560 138.3240 241.7040 138.3720 ;
  END
 END rd[986]
 PIN wd[987]
  DIRECTION INPUT ;
  USE SIGNAL ;
  PORT
   LAYER M4 ;
   RECT 241.6560 138.5160 241.7040 138.5640 ;
  END
 END wd[987]
 PIN rd[987]
  DIRECTION OUTPUT ;
  USE SIGNAL ;
  PORT
   LAYER M4 ;
   RECT 241.6560 138.7080 241.7040 138.7560 ;
  END
 END rd[987]
 PIN wd[988]
  DIRECTION INPUT ;
  USE SIGNAL ;
  PORT
   LAYER M4 ;
   RECT 241.6560 138.9000 241.7040 138.9480 ;
  END
 END wd[988]
 PIN rd[988]
  DIRECTION OUTPUT ;
  USE SIGNAL ;
  PORT
   LAYER M4 ;
   RECT 241.6560 139.0920 241.7040 139.1400 ;
  END
 END rd[988]
 PIN wd[989]
  DIRECTION INPUT ;
  USE SIGNAL ;
  PORT
   LAYER M4 ;
   RECT 241.6560 139.2840 241.7040 139.3320 ;
  END
 END wd[989]
 PIN rd[989]
  DIRECTION OUTPUT ;
  USE SIGNAL ;
  PORT
   LAYER M4 ;
   RECT 241.6560 139.4760 241.7040 139.5240 ;
  END
 END rd[989]
 PIN wd[990]
  DIRECTION INPUT ;
  USE SIGNAL ;
  PORT
   LAYER M4 ;
   RECT 241.6560 139.6680 241.7040 139.7160 ;
  END
 END wd[990]
 PIN rd[990]
  DIRECTION OUTPUT ;
  USE SIGNAL ;
  PORT
   LAYER M4 ;
   RECT 241.6560 139.8600 241.7040 139.9080 ;
  END
 END rd[990]
 PIN wd[991]
  DIRECTION INPUT ;
  USE SIGNAL ;
  PORT
   LAYER M4 ;
   RECT 241.6560 140.0520 241.7040 140.1000 ;
  END
 END wd[991]
 PIN rd[991]
  DIRECTION OUTPUT ;
  USE SIGNAL ;
  PORT
   LAYER M4 ;
   RECT 241.6560 140.2440 241.7040 140.2920 ;
  END
 END rd[991]
 PIN wd[992]
  DIRECTION INPUT ;
  USE SIGNAL ;
  PORT
   LAYER M4 ;
   RECT 241.6560 140.4360 241.7040 140.4840 ;
  END
 END wd[992]
 PIN rd[992]
  DIRECTION OUTPUT ;
  USE SIGNAL ;
  PORT
   LAYER M4 ;
   RECT 241.6560 140.6280 241.7040 140.6760 ;
  END
 END rd[992]
 PIN wd[993]
  DIRECTION INPUT ;
  USE SIGNAL ;
  PORT
   LAYER M4 ;
   RECT 241.6560 140.8200 241.7040 140.8680 ;
  END
 END wd[993]
 PIN rd[993]
  DIRECTION OUTPUT ;
  USE SIGNAL ;
  PORT
   LAYER M4 ;
   RECT 241.6560 141.0120 241.7040 141.0600 ;
  END
 END rd[993]
 PIN wd[994]
  DIRECTION INPUT ;
  USE SIGNAL ;
  PORT
   LAYER M4 ;
   RECT 241.6560 141.2040 241.7040 141.2520 ;
  END
 END wd[994]
 PIN rd[994]
  DIRECTION OUTPUT ;
  USE SIGNAL ;
  PORT
   LAYER M4 ;
   RECT 241.6560 141.3960 241.7040 141.4440 ;
  END
 END rd[994]
 PIN wd[995]
  DIRECTION INPUT ;
  USE SIGNAL ;
  PORT
   LAYER M4 ;
   RECT 241.6560 141.5880 241.7040 141.6360 ;
  END
 END wd[995]
 PIN rd[995]
  DIRECTION OUTPUT ;
  USE SIGNAL ;
  PORT
   LAYER M4 ;
   RECT 241.6560 141.7800 241.7040 141.8280 ;
  END
 END rd[995]
 PIN wd[996]
  DIRECTION INPUT ;
  USE SIGNAL ;
  PORT
   LAYER M4 ;
   RECT 241.6560 141.9720 241.7040 142.0200 ;
  END
 END wd[996]
 PIN rd[996]
  DIRECTION OUTPUT ;
  USE SIGNAL ;
  PORT
   LAYER M4 ;
   RECT 241.6560 142.1640 241.7040 142.2120 ;
  END
 END rd[996]
 PIN wd[997]
  DIRECTION INPUT ;
  USE SIGNAL ;
  PORT
   LAYER M4 ;
   RECT 241.6560 142.3560 241.7040 142.4040 ;
  END
 END wd[997]
 PIN rd[997]
  DIRECTION OUTPUT ;
  USE SIGNAL ;
  PORT
   LAYER M4 ;
   RECT 241.6560 142.5480 241.7040 142.5960 ;
  END
 END rd[997]
 PIN wd[998]
  DIRECTION INPUT ;
  USE SIGNAL ;
  PORT
   LAYER M4 ;
   RECT 241.6560 142.7400 241.7040 142.7880 ;
  END
 END wd[998]
 PIN rd[998]
  DIRECTION OUTPUT ;
  USE SIGNAL ;
  PORT
   LAYER M4 ;
   RECT 241.6560 142.9320 241.7040 142.9800 ;
  END
 END rd[998]
 PIN wd[999]
  DIRECTION INPUT ;
  USE SIGNAL ;
  PORT
   LAYER M4 ;
   RECT 241.6560 143.1240 241.7040 143.1720 ;
  END
 END wd[999]
 PIN rd[999]
  DIRECTION OUTPUT ;
  USE SIGNAL ;
  PORT
   LAYER M4 ;
   RECT 241.6560 143.3160 241.7040 143.3640 ;
  END
 END rd[999]
 PIN wd[1000]
  DIRECTION INPUT ;
  USE SIGNAL ;
  PORT
   LAYER M4 ;
   RECT 241.6560 143.5080 241.7040 143.5560 ;
  END
 END wd[1000]
 PIN rd[1000]
  DIRECTION OUTPUT ;
  USE SIGNAL ;
  PORT
   LAYER M4 ;
   RECT 241.6560 143.7000 241.7040 143.7480 ;
  END
 END rd[1000]
 PIN wd[1001]
  DIRECTION INPUT ;
  USE SIGNAL ;
  PORT
   LAYER M4 ;
   RECT 241.6560 143.8920 241.7040 143.9400 ;
  END
 END wd[1001]
 PIN rd[1001]
  DIRECTION OUTPUT ;
  USE SIGNAL ;
  PORT
   LAYER M4 ;
   RECT 241.6560 144.0840 241.7040 144.1320 ;
  END
 END rd[1001]
 PIN wd[1002]
  DIRECTION INPUT ;
  USE SIGNAL ;
  PORT
   LAYER M4 ;
   RECT 241.6560 144.2760 241.7040 144.3240 ;
  END
 END wd[1002]
 PIN rd[1002]
  DIRECTION OUTPUT ;
  USE SIGNAL ;
  PORT
   LAYER M4 ;
   RECT 241.6560 144.4680 241.7040 144.5160 ;
  END
 END rd[1002]
 PIN wd[1003]
  DIRECTION INPUT ;
  USE SIGNAL ;
  PORT
   LAYER M4 ;
   RECT 241.6560 144.6600 241.7040 144.7080 ;
  END
 END wd[1003]
 PIN rd[1003]
  DIRECTION OUTPUT ;
  USE SIGNAL ;
  PORT
   LAYER M4 ;
   RECT 241.6560 144.8520 241.7040 144.9000 ;
  END
 END rd[1003]
 PIN wd[1004]
  DIRECTION INPUT ;
  USE SIGNAL ;
  PORT
   LAYER M4 ;
   RECT 241.6560 145.0440 241.7040 145.0920 ;
  END
 END wd[1004]
 PIN rd[1004]
  DIRECTION OUTPUT ;
  USE SIGNAL ;
  PORT
   LAYER M4 ;
   RECT 241.6560 145.2360 241.7040 145.2840 ;
  END
 END rd[1004]
 PIN wd[1005]
  DIRECTION INPUT ;
  USE SIGNAL ;
  PORT
   LAYER M4 ;
   RECT 241.6560 145.4280 241.7040 145.4760 ;
  END
 END wd[1005]
 PIN rd[1005]
  DIRECTION OUTPUT ;
  USE SIGNAL ;
  PORT
   LAYER M4 ;
   RECT 241.6560 145.6200 241.7040 145.6680 ;
  END
 END rd[1005]
 PIN wd[1006]
  DIRECTION INPUT ;
  USE SIGNAL ;
  PORT
   LAYER M4 ;
   RECT 241.6560 145.8120 241.7040 145.8600 ;
  END
 END wd[1006]
 PIN rd[1006]
  DIRECTION OUTPUT ;
  USE SIGNAL ;
  PORT
   LAYER M4 ;
   RECT 241.6560 146.0040 241.7040 146.0520 ;
  END
 END rd[1006]
 PIN wd[1007]
  DIRECTION INPUT ;
  USE SIGNAL ;
  PORT
   LAYER M4 ;
   RECT 241.6560 146.1960 241.7040 146.2440 ;
  END
 END wd[1007]
 PIN rd[1007]
  DIRECTION OUTPUT ;
  USE SIGNAL ;
  PORT
   LAYER M4 ;
   RECT 241.6560 146.3880 241.7040 146.4360 ;
  END
 END rd[1007]
 PIN wd[1008]
  DIRECTION INPUT ;
  USE SIGNAL ;
  PORT
   LAYER M4 ;
   RECT 241.6560 146.5800 241.7040 146.6280 ;
  END
 END wd[1008]
 PIN rd[1008]
  DIRECTION OUTPUT ;
  USE SIGNAL ;
  PORT
   LAYER M4 ;
   RECT 241.6560 146.7720 241.7040 146.8200 ;
  END
 END rd[1008]
 PIN wd[1009]
  DIRECTION INPUT ;
  USE SIGNAL ;
  PORT
   LAYER M4 ;
   RECT 241.6560 146.9640 241.7040 147.0120 ;
  END
 END wd[1009]
 PIN rd[1009]
  DIRECTION OUTPUT ;
  USE SIGNAL ;
  PORT
   LAYER M4 ;
   RECT 241.6560 147.1560 241.7040 147.2040 ;
  END
 END rd[1009]
 PIN wd[1010]
  DIRECTION INPUT ;
  USE SIGNAL ;
  PORT
   LAYER M4 ;
   RECT 241.6560 147.3480 241.7040 147.3960 ;
  END
 END wd[1010]
 PIN rd[1010]
  DIRECTION OUTPUT ;
  USE SIGNAL ;
  PORT
   LAYER M4 ;
   RECT 241.6560 147.5400 241.7040 147.5880 ;
  END
 END rd[1010]
 PIN wd[1011]
  DIRECTION INPUT ;
  USE SIGNAL ;
  PORT
   LAYER M4 ;
   RECT 241.6560 147.7320 241.7040 147.7800 ;
  END
 END wd[1011]
 PIN rd[1011]
  DIRECTION OUTPUT ;
  USE SIGNAL ;
  PORT
   LAYER M4 ;
   RECT 241.6560 147.9240 241.7040 147.9720 ;
  END
 END rd[1011]
 PIN wd[1012]
  DIRECTION INPUT ;
  USE SIGNAL ;
  PORT
   LAYER M4 ;
   RECT 241.6560 148.1160 241.7040 148.1640 ;
  END
 END wd[1012]
 PIN rd[1012]
  DIRECTION OUTPUT ;
  USE SIGNAL ;
  PORT
   LAYER M4 ;
   RECT 241.6560 148.3080 241.7040 148.3560 ;
  END
 END rd[1012]
 PIN wd[1013]
  DIRECTION INPUT ;
  USE SIGNAL ;
  PORT
   LAYER M4 ;
   RECT 241.6560 148.5000 241.7040 148.5480 ;
  END
 END wd[1013]
 PIN rd[1013]
  DIRECTION OUTPUT ;
  USE SIGNAL ;
  PORT
   LAYER M4 ;
   RECT 241.6560 148.6920 241.7040 148.7400 ;
  END
 END rd[1013]
 PIN wd[1014]
  DIRECTION INPUT ;
  USE SIGNAL ;
  PORT
   LAYER M4 ;
   RECT 241.6560 148.8840 241.7040 148.9320 ;
  END
 END wd[1014]
 PIN rd[1014]
  DIRECTION OUTPUT ;
  USE SIGNAL ;
  PORT
   LAYER M4 ;
   RECT 241.6560 149.0760 241.7040 149.1240 ;
  END
 END rd[1014]
 PIN wd[1015]
  DIRECTION INPUT ;
  USE SIGNAL ;
  PORT
   LAYER M4 ;
   RECT 241.6560 149.2680 241.7040 149.3160 ;
  END
 END wd[1015]
 PIN rd[1015]
  DIRECTION OUTPUT ;
  USE SIGNAL ;
  PORT
   LAYER M4 ;
   RECT 241.6560 149.4600 241.7040 149.5080 ;
  END
 END rd[1015]
 PIN wd[1016]
  DIRECTION INPUT ;
  USE SIGNAL ;
  PORT
   LAYER M4 ;
   RECT 241.6560 149.6520 241.7040 149.7000 ;
  END
 END wd[1016]
 PIN rd[1016]
  DIRECTION OUTPUT ;
  USE SIGNAL ;
  PORT
   LAYER M4 ;
   RECT 241.6560 149.8440 241.7040 149.8920 ;
  END
 END rd[1016]
 PIN wd[1017]
  DIRECTION INPUT ;
  USE SIGNAL ;
  PORT
   LAYER M4 ;
   RECT 241.6560 150.0360 241.7040 150.0840 ;
  END
 END wd[1017]
 PIN rd[1017]
  DIRECTION OUTPUT ;
  USE SIGNAL ;
  PORT
   LAYER M4 ;
   RECT 241.6560 150.2280 241.7040 150.2760 ;
  END
 END rd[1017]
 PIN wd[1018]
  DIRECTION INPUT ;
  USE SIGNAL ;
  PORT
   LAYER M4 ;
   RECT 241.6560 150.4200 241.7040 150.4680 ;
  END
 END wd[1018]
 PIN rd[1018]
  DIRECTION OUTPUT ;
  USE SIGNAL ;
  PORT
   LAYER M4 ;
   RECT 241.6560 150.6120 241.7040 150.6600 ;
  END
 END rd[1018]
 PIN wd[1019]
  DIRECTION INPUT ;
  USE SIGNAL ;
  PORT
   LAYER M4 ;
   RECT 241.6560 150.8040 241.7040 150.8520 ;
  END
 END wd[1019]
 PIN rd[1019]
  DIRECTION OUTPUT ;
  USE SIGNAL ;
  PORT
   LAYER M4 ;
   RECT 241.6560 150.9960 241.7040 151.0440 ;
  END
 END rd[1019]
 PIN wd[1020]
  DIRECTION INPUT ;
  USE SIGNAL ;
  PORT
   LAYER M4 ;
   RECT 241.6560 151.1880 241.7040 151.2360 ;
  END
 END wd[1020]
 PIN rd[1020]
  DIRECTION OUTPUT ;
  USE SIGNAL ;
  PORT
   LAYER M4 ;
   RECT 241.6560 151.3800 241.7040 151.4280 ;
  END
 END rd[1020]
 PIN wd[1021]
  DIRECTION INPUT ;
  USE SIGNAL ;
  PORT
   LAYER M4 ;
   RECT 241.6560 151.5720 241.7040 151.6200 ;
  END
 END wd[1021]
 PIN rd[1021]
  DIRECTION OUTPUT ;
  USE SIGNAL ;
  PORT
   LAYER M4 ;
   RECT 241.6560 151.7640 241.7040 151.8120 ;
  END
 END rd[1021]
 PIN wd[1022]
  DIRECTION INPUT ;
  USE SIGNAL ;
  PORT
   LAYER M4 ;
   RECT 241.6560 151.9560 241.7040 152.0040 ;
  END
 END wd[1022]
 PIN rd[1022]
  DIRECTION OUTPUT ;
  USE SIGNAL ;
  PORT
   LAYER M4 ;
   RECT 241.6560 152.1480 241.7040 152.1960 ;
  END
 END rd[1022]
 PIN wd[1023]
  DIRECTION INPUT ;
  USE SIGNAL ;
  PORT
   LAYER M4 ;
   RECT 241.6560 152.3400 241.7040 152.3880 ;
  END
 END wd[1023]
 PIN rd[1023]
  DIRECTION OUTPUT ;
  USE SIGNAL ;
  PORT
   LAYER M4 ;
   RECT 241.6560 152.5320 241.7040 152.5800 ;
  END
 END rd[1023]
 PIN wd[1024]
  DIRECTION INPUT ;
  USE SIGNAL ;
  PORT
   LAYER M5 ;
   RECT 8.6280 155.2560 8.6760 155.3040 ;
  END
 END wd[1024]
 PIN rd[1024]
  DIRECTION OUTPUT ;
  USE SIGNAL ;
  PORT
   LAYER M5 ;
   RECT 8.8680 155.2560 8.9160 155.3040 ;
  END
 END rd[1024]
 PIN wd[1025]
  DIRECTION INPUT ;
  USE SIGNAL ;
  PORT
   LAYER M5 ;
   RECT 9.1080 155.2560 9.1560 155.3040 ;
  END
 END wd[1025]
 PIN rd[1025]
  DIRECTION OUTPUT ;
  USE SIGNAL ;
  PORT
   LAYER M5 ;
   RECT 9.3480 155.2560 9.3960 155.3040 ;
  END
 END rd[1025]
 PIN wd[1026]
  DIRECTION INPUT ;
  USE SIGNAL ;
  PORT
   LAYER M5 ;
   RECT 9.5880 155.2560 9.6360 155.3040 ;
  END
 END wd[1026]
 PIN rd[1026]
  DIRECTION OUTPUT ;
  USE SIGNAL ;
  PORT
   LAYER M5 ;
   RECT 9.8280 155.2560 9.8760 155.3040 ;
  END
 END rd[1026]
 PIN wd[1027]
  DIRECTION INPUT ;
  USE SIGNAL ;
  PORT
   LAYER M5 ;
   RECT 10.0680 155.2560 10.1160 155.3040 ;
  END
 END wd[1027]
 PIN rd[1027]
  DIRECTION OUTPUT ;
  USE SIGNAL ;
  PORT
   LAYER M5 ;
   RECT 10.3080 155.2560 10.3560 155.3040 ;
  END
 END rd[1027]
 PIN wd[1028]
  DIRECTION INPUT ;
  USE SIGNAL ;
  PORT
   LAYER M5 ;
   RECT 10.5480 155.2560 10.5960 155.3040 ;
  END
 END wd[1028]
 PIN rd[1028]
  DIRECTION OUTPUT ;
  USE SIGNAL ;
  PORT
   LAYER M5 ;
   RECT 10.7880 155.2560 10.8360 155.3040 ;
  END
 END rd[1028]
 PIN wd[1029]
  DIRECTION INPUT ;
  USE SIGNAL ;
  PORT
   LAYER M5 ;
   RECT 11.0280 155.2560 11.0760 155.3040 ;
  END
 END wd[1029]
 PIN rd[1029]
  DIRECTION OUTPUT ;
  USE SIGNAL ;
  PORT
   LAYER M5 ;
   RECT 11.2680 155.2560 11.3160 155.3040 ;
  END
 END rd[1029]
 PIN wd[1030]
  DIRECTION INPUT ;
  USE SIGNAL ;
  PORT
   LAYER M5 ;
   RECT 11.5080 155.2560 11.5560 155.3040 ;
  END
 END wd[1030]
 PIN rd[1030]
  DIRECTION OUTPUT ;
  USE SIGNAL ;
  PORT
   LAYER M5 ;
   RECT 11.7480 155.2560 11.7960 155.3040 ;
  END
 END rd[1030]
 PIN wd[1031]
  DIRECTION INPUT ;
  USE SIGNAL ;
  PORT
   LAYER M5 ;
   RECT 11.9880 155.2560 12.0360 155.3040 ;
  END
 END wd[1031]
 PIN rd[1031]
  DIRECTION OUTPUT ;
  USE SIGNAL ;
  PORT
   LAYER M5 ;
   RECT 12.2280 155.2560 12.2760 155.3040 ;
  END
 END rd[1031]
 PIN wd[1032]
  DIRECTION INPUT ;
  USE SIGNAL ;
  PORT
   LAYER M5 ;
   RECT 12.4680 155.2560 12.5160 155.3040 ;
  END
 END wd[1032]
 PIN rd[1032]
  DIRECTION OUTPUT ;
  USE SIGNAL ;
  PORT
   LAYER M5 ;
   RECT 12.7080 155.2560 12.7560 155.3040 ;
  END
 END rd[1032]
 PIN wd[1033]
  DIRECTION INPUT ;
  USE SIGNAL ;
  PORT
   LAYER M5 ;
   RECT 12.9480 155.2560 12.9960 155.3040 ;
  END
 END wd[1033]
 PIN rd[1033]
  DIRECTION OUTPUT ;
  USE SIGNAL ;
  PORT
   LAYER M5 ;
   RECT 13.1880 155.2560 13.2360 155.3040 ;
  END
 END rd[1033]
 PIN wd[1034]
  DIRECTION INPUT ;
  USE SIGNAL ;
  PORT
   LAYER M5 ;
   RECT 13.4280 155.2560 13.4760 155.3040 ;
  END
 END wd[1034]
 PIN rd[1034]
  DIRECTION OUTPUT ;
  USE SIGNAL ;
  PORT
   LAYER M5 ;
   RECT 13.6680 155.2560 13.7160 155.3040 ;
  END
 END rd[1034]
 PIN wd[1035]
  DIRECTION INPUT ;
  USE SIGNAL ;
  PORT
   LAYER M5 ;
   RECT 13.9080 155.2560 13.9560 155.3040 ;
  END
 END wd[1035]
 PIN rd[1035]
  DIRECTION OUTPUT ;
  USE SIGNAL ;
  PORT
   LAYER M5 ;
   RECT 14.1480 155.2560 14.1960 155.3040 ;
  END
 END rd[1035]
 PIN wd[1036]
  DIRECTION INPUT ;
  USE SIGNAL ;
  PORT
   LAYER M5 ;
   RECT 14.3880 155.2560 14.4360 155.3040 ;
  END
 END wd[1036]
 PIN rd[1036]
  DIRECTION OUTPUT ;
  USE SIGNAL ;
  PORT
   LAYER M5 ;
   RECT 14.6280 155.2560 14.6760 155.3040 ;
  END
 END rd[1036]
 PIN wd[1037]
  DIRECTION INPUT ;
  USE SIGNAL ;
  PORT
   LAYER M5 ;
   RECT 14.8680 155.2560 14.9160 155.3040 ;
  END
 END wd[1037]
 PIN rd[1037]
  DIRECTION OUTPUT ;
  USE SIGNAL ;
  PORT
   LAYER M5 ;
   RECT 15.1080 155.2560 15.1560 155.3040 ;
  END
 END rd[1037]
 PIN wd[1038]
  DIRECTION INPUT ;
  USE SIGNAL ;
  PORT
   LAYER M5 ;
   RECT 15.3480 155.2560 15.3960 155.3040 ;
  END
 END wd[1038]
 PIN rd[1038]
  DIRECTION OUTPUT ;
  USE SIGNAL ;
  PORT
   LAYER M5 ;
   RECT 15.5880 155.2560 15.6360 155.3040 ;
  END
 END rd[1038]
 PIN wd[1039]
  DIRECTION INPUT ;
  USE SIGNAL ;
  PORT
   LAYER M5 ;
   RECT 15.8280 155.2560 15.8760 155.3040 ;
  END
 END wd[1039]
 PIN rd[1039]
  DIRECTION OUTPUT ;
  USE SIGNAL ;
  PORT
   LAYER M5 ;
   RECT 16.0680 155.2560 16.1160 155.3040 ;
  END
 END rd[1039]
 PIN wd[1040]
  DIRECTION INPUT ;
  USE SIGNAL ;
  PORT
   LAYER M5 ;
   RECT 16.3080 155.2560 16.3560 155.3040 ;
  END
 END wd[1040]
 PIN rd[1040]
  DIRECTION OUTPUT ;
  USE SIGNAL ;
  PORT
   LAYER M5 ;
   RECT 16.5480 155.2560 16.5960 155.3040 ;
  END
 END rd[1040]
 PIN wd[1041]
  DIRECTION INPUT ;
  USE SIGNAL ;
  PORT
   LAYER M5 ;
   RECT 16.7880 155.2560 16.8360 155.3040 ;
  END
 END wd[1041]
 PIN rd[1041]
  DIRECTION OUTPUT ;
  USE SIGNAL ;
  PORT
   LAYER M5 ;
   RECT 17.0280 155.2560 17.0760 155.3040 ;
  END
 END rd[1041]
 PIN wd[1042]
  DIRECTION INPUT ;
  USE SIGNAL ;
  PORT
   LAYER M5 ;
   RECT 17.2680 155.2560 17.3160 155.3040 ;
  END
 END wd[1042]
 PIN rd[1042]
  DIRECTION OUTPUT ;
  USE SIGNAL ;
  PORT
   LAYER M5 ;
   RECT 17.5080 155.2560 17.5560 155.3040 ;
  END
 END rd[1042]
 PIN wd[1043]
  DIRECTION INPUT ;
  USE SIGNAL ;
  PORT
   LAYER M5 ;
   RECT 17.7480 155.2560 17.7960 155.3040 ;
  END
 END wd[1043]
 PIN rd[1043]
  DIRECTION OUTPUT ;
  USE SIGNAL ;
  PORT
   LAYER M5 ;
   RECT 17.9880 155.2560 18.0360 155.3040 ;
  END
 END rd[1043]
 PIN wd[1044]
  DIRECTION INPUT ;
  USE SIGNAL ;
  PORT
   LAYER M5 ;
   RECT 18.2280 155.2560 18.2760 155.3040 ;
  END
 END wd[1044]
 PIN rd[1044]
  DIRECTION OUTPUT ;
  USE SIGNAL ;
  PORT
   LAYER M5 ;
   RECT 18.4680 155.2560 18.5160 155.3040 ;
  END
 END rd[1044]
 PIN wd[1045]
  DIRECTION INPUT ;
  USE SIGNAL ;
  PORT
   LAYER M5 ;
   RECT 18.7080 155.2560 18.7560 155.3040 ;
  END
 END wd[1045]
 PIN rd[1045]
  DIRECTION OUTPUT ;
  USE SIGNAL ;
  PORT
   LAYER M5 ;
   RECT 18.9480 155.2560 18.9960 155.3040 ;
  END
 END rd[1045]
 PIN wd[1046]
  DIRECTION INPUT ;
  USE SIGNAL ;
  PORT
   LAYER M5 ;
   RECT 19.1880 155.2560 19.2360 155.3040 ;
  END
 END wd[1046]
 PIN rd[1046]
  DIRECTION OUTPUT ;
  USE SIGNAL ;
  PORT
   LAYER M5 ;
   RECT 19.4280 155.2560 19.4760 155.3040 ;
  END
 END rd[1046]
 PIN wd[1047]
  DIRECTION INPUT ;
  USE SIGNAL ;
  PORT
   LAYER M5 ;
   RECT 19.6680 155.2560 19.7160 155.3040 ;
  END
 END wd[1047]
 PIN rd[1047]
  DIRECTION OUTPUT ;
  USE SIGNAL ;
  PORT
   LAYER M5 ;
   RECT 19.9080 155.2560 19.9560 155.3040 ;
  END
 END rd[1047]
 PIN wd[1048]
  DIRECTION INPUT ;
  USE SIGNAL ;
  PORT
   LAYER M5 ;
   RECT 20.1480 155.2560 20.1960 155.3040 ;
  END
 END wd[1048]
 PIN rd[1048]
  DIRECTION OUTPUT ;
  USE SIGNAL ;
  PORT
   LAYER M5 ;
   RECT 20.3880 155.2560 20.4360 155.3040 ;
  END
 END rd[1048]
 PIN wd[1049]
  DIRECTION INPUT ;
  USE SIGNAL ;
  PORT
   LAYER M5 ;
   RECT 20.6280 155.2560 20.6760 155.3040 ;
  END
 END wd[1049]
 PIN rd[1049]
  DIRECTION OUTPUT ;
  USE SIGNAL ;
  PORT
   LAYER M5 ;
   RECT 20.8680 155.2560 20.9160 155.3040 ;
  END
 END rd[1049]
 PIN wd[1050]
  DIRECTION INPUT ;
  USE SIGNAL ;
  PORT
   LAYER M5 ;
   RECT 21.1080 155.2560 21.1560 155.3040 ;
  END
 END wd[1050]
 PIN rd[1050]
  DIRECTION OUTPUT ;
  USE SIGNAL ;
  PORT
   LAYER M5 ;
   RECT 21.3480 155.2560 21.3960 155.3040 ;
  END
 END rd[1050]
 PIN wd[1051]
  DIRECTION INPUT ;
  USE SIGNAL ;
  PORT
   LAYER M5 ;
   RECT 21.5880 155.2560 21.6360 155.3040 ;
  END
 END wd[1051]
 PIN rd[1051]
  DIRECTION OUTPUT ;
  USE SIGNAL ;
  PORT
   LAYER M5 ;
   RECT 21.8280 155.2560 21.8760 155.3040 ;
  END
 END rd[1051]
 PIN wd[1052]
  DIRECTION INPUT ;
  USE SIGNAL ;
  PORT
   LAYER M5 ;
   RECT 22.0680 155.2560 22.1160 155.3040 ;
  END
 END wd[1052]
 PIN rd[1052]
  DIRECTION OUTPUT ;
  USE SIGNAL ;
  PORT
   LAYER M5 ;
   RECT 22.3080 155.2560 22.3560 155.3040 ;
  END
 END rd[1052]
 PIN wd[1053]
  DIRECTION INPUT ;
  USE SIGNAL ;
  PORT
   LAYER M5 ;
   RECT 22.5480 155.2560 22.5960 155.3040 ;
  END
 END wd[1053]
 PIN rd[1053]
  DIRECTION OUTPUT ;
  USE SIGNAL ;
  PORT
   LAYER M5 ;
   RECT 22.7880 155.2560 22.8360 155.3040 ;
  END
 END rd[1053]
 PIN wd[1054]
  DIRECTION INPUT ;
  USE SIGNAL ;
  PORT
   LAYER M5 ;
   RECT 23.0280 155.2560 23.0760 155.3040 ;
  END
 END wd[1054]
 PIN rd[1054]
  DIRECTION OUTPUT ;
  USE SIGNAL ;
  PORT
   LAYER M5 ;
   RECT 23.2680 155.2560 23.3160 155.3040 ;
  END
 END rd[1054]
 PIN wd[1055]
  DIRECTION INPUT ;
  USE SIGNAL ;
  PORT
   LAYER M5 ;
   RECT 23.5080 155.2560 23.5560 155.3040 ;
  END
 END wd[1055]
 PIN rd[1055]
  DIRECTION OUTPUT ;
  USE SIGNAL ;
  PORT
   LAYER M5 ;
   RECT 23.7480 155.2560 23.7960 155.3040 ;
  END
 END rd[1055]
 PIN wd[1056]
  DIRECTION INPUT ;
  USE SIGNAL ;
  PORT
   LAYER M5 ;
   RECT 23.9880 155.2560 24.0360 155.3040 ;
  END
 END wd[1056]
 PIN rd[1056]
  DIRECTION OUTPUT ;
  USE SIGNAL ;
  PORT
   LAYER M5 ;
   RECT 24.2280 155.2560 24.2760 155.3040 ;
  END
 END rd[1056]
 PIN wd[1057]
  DIRECTION INPUT ;
  USE SIGNAL ;
  PORT
   LAYER M5 ;
   RECT 24.4680 155.2560 24.5160 155.3040 ;
  END
 END wd[1057]
 PIN rd[1057]
  DIRECTION OUTPUT ;
  USE SIGNAL ;
  PORT
   LAYER M5 ;
   RECT 24.7080 155.2560 24.7560 155.3040 ;
  END
 END rd[1057]
 PIN wd[1058]
  DIRECTION INPUT ;
  USE SIGNAL ;
  PORT
   LAYER M5 ;
   RECT 24.9480 155.2560 24.9960 155.3040 ;
  END
 END wd[1058]
 PIN rd[1058]
  DIRECTION OUTPUT ;
  USE SIGNAL ;
  PORT
   LAYER M5 ;
   RECT 25.1880 155.2560 25.2360 155.3040 ;
  END
 END rd[1058]
 PIN wd[1059]
  DIRECTION INPUT ;
  USE SIGNAL ;
  PORT
   LAYER M5 ;
   RECT 25.4280 155.2560 25.4760 155.3040 ;
  END
 END wd[1059]
 PIN rd[1059]
  DIRECTION OUTPUT ;
  USE SIGNAL ;
  PORT
   LAYER M5 ;
   RECT 25.6680 155.2560 25.7160 155.3040 ;
  END
 END rd[1059]
 PIN wd[1060]
  DIRECTION INPUT ;
  USE SIGNAL ;
  PORT
   LAYER M5 ;
   RECT 25.9080 155.2560 25.9560 155.3040 ;
  END
 END wd[1060]
 PIN rd[1060]
  DIRECTION OUTPUT ;
  USE SIGNAL ;
  PORT
   LAYER M5 ;
   RECT 26.1480 155.2560 26.1960 155.3040 ;
  END
 END rd[1060]
 PIN wd[1061]
  DIRECTION INPUT ;
  USE SIGNAL ;
  PORT
   LAYER M5 ;
   RECT 26.3880 155.2560 26.4360 155.3040 ;
  END
 END wd[1061]
 PIN rd[1061]
  DIRECTION OUTPUT ;
  USE SIGNAL ;
  PORT
   LAYER M5 ;
   RECT 26.6280 155.2560 26.6760 155.3040 ;
  END
 END rd[1061]
 PIN wd[1062]
  DIRECTION INPUT ;
  USE SIGNAL ;
  PORT
   LAYER M5 ;
   RECT 26.8680 155.2560 26.9160 155.3040 ;
  END
 END wd[1062]
 PIN rd[1062]
  DIRECTION OUTPUT ;
  USE SIGNAL ;
  PORT
   LAYER M5 ;
   RECT 27.1080 155.2560 27.1560 155.3040 ;
  END
 END rd[1062]
 PIN wd[1063]
  DIRECTION INPUT ;
  USE SIGNAL ;
  PORT
   LAYER M5 ;
   RECT 27.3480 155.2560 27.3960 155.3040 ;
  END
 END wd[1063]
 PIN rd[1063]
  DIRECTION OUTPUT ;
  USE SIGNAL ;
  PORT
   LAYER M5 ;
   RECT 27.5880 155.2560 27.6360 155.3040 ;
  END
 END rd[1063]
 PIN wd[1064]
  DIRECTION INPUT ;
  USE SIGNAL ;
  PORT
   LAYER M5 ;
   RECT 27.8280 155.2560 27.8760 155.3040 ;
  END
 END wd[1064]
 PIN rd[1064]
  DIRECTION OUTPUT ;
  USE SIGNAL ;
  PORT
   LAYER M5 ;
   RECT 28.0680 155.2560 28.1160 155.3040 ;
  END
 END rd[1064]
 PIN wd[1065]
  DIRECTION INPUT ;
  USE SIGNAL ;
  PORT
   LAYER M5 ;
   RECT 28.3080 155.2560 28.3560 155.3040 ;
  END
 END wd[1065]
 PIN rd[1065]
  DIRECTION OUTPUT ;
  USE SIGNAL ;
  PORT
   LAYER M5 ;
   RECT 28.5480 155.2560 28.5960 155.3040 ;
  END
 END rd[1065]
 PIN wd[1066]
  DIRECTION INPUT ;
  USE SIGNAL ;
  PORT
   LAYER M5 ;
   RECT 28.7880 155.2560 28.8360 155.3040 ;
  END
 END wd[1066]
 PIN rd[1066]
  DIRECTION OUTPUT ;
  USE SIGNAL ;
  PORT
   LAYER M5 ;
   RECT 29.0280 155.2560 29.0760 155.3040 ;
  END
 END rd[1066]
 PIN wd[1067]
  DIRECTION INPUT ;
  USE SIGNAL ;
  PORT
   LAYER M5 ;
   RECT 29.2680 155.2560 29.3160 155.3040 ;
  END
 END wd[1067]
 PIN rd[1067]
  DIRECTION OUTPUT ;
  USE SIGNAL ;
  PORT
   LAYER M5 ;
   RECT 29.5080 155.2560 29.5560 155.3040 ;
  END
 END rd[1067]
 PIN wd[1068]
  DIRECTION INPUT ;
  USE SIGNAL ;
  PORT
   LAYER M5 ;
   RECT 29.7480 155.2560 29.7960 155.3040 ;
  END
 END wd[1068]
 PIN rd[1068]
  DIRECTION OUTPUT ;
  USE SIGNAL ;
  PORT
   LAYER M5 ;
   RECT 29.9880 155.2560 30.0360 155.3040 ;
  END
 END rd[1068]
 PIN wd[1069]
  DIRECTION INPUT ;
  USE SIGNAL ;
  PORT
   LAYER M5 ;
   RECT 30.2280 155.2560 30.2760 155.3040 ;
  END
 END wd[1069]
 PIN rd[1069]
  DIRECTION OUTPUT ;
  USE SIGNAL ;
  PORT
   LAYER M5 ;
   RECT 30.4680 155.2560 30.5160 155.3040 ;
  END
 END rd[1069]
 PIN wd[1070]
  DIRECTION INPUT ;
  USE SIGNAL ;
  PORT
   LAYER M5 ;
   RECT 30.7080 155.2560 30.7560 155.3040 ;
  END
 END wd[1070]
 PIN rd[1070]
  DIRECTION OUTPUT ;
  USE SIGNAL ;
  PORT
   LAYER M5 ;
   RECT 30.9480 155.2560 30.9960 155.3040 ;
  END
 END rd[1070]
 PIN wd[1071]
  DIRECTION INPUT ;
  USE SIGNAL ;
  PORT
   LAYER M5 ;
   RECT 31.1880 155.2560 31.2360 155.3040 ;
  END
 END wd[1071]
 PIN rd[1071]
  DIRECTION OUTPUT ;
  USE SIGNAL ;
  PORT
   LAYER M5 ;
   RECT 31.4280 155.2560 31.4760 155.3040 ;
  END
 END rd[1071]
 PIN wd[1072]
  DIRECTION INPUT ;
  USE SIGNAL ;
  PORT
   LAYER M5 ;
   RECT 31.6680 155.2560 31.7160 155.3040 ;
  END
 END wd[1072]
 PIN rd[1072]
  DIRECTION OUTPUT ;
  USE SIGNAL ;
  PORT
   LAYER M5 ;
   RECT 31.9080 155.2560 31.9560 155.3040 ;
  END
 END rd[1072]
 PIN wd[1073]
  DIRECTION INPUT ;
  USE SIGNAL ;
  PORT
   LAYER M5 ;
   RECT 32.1480 155.2560 32.1960 155.3040 ;
  END
 END wd[1073]
 PIN rd[1073]
  DIRECTION OUTPUT ;
  USE SIGNAL ;
  PORT
   LAYER M5 ;
   RECT 32.3880 155.2560 32.4360 155.3040 ;
  END
 END rd[1073]
 PIN wd[1074]
  DIRECTION INPUT ;
  USE SIGNAL ;
  PORT
   LAYER M5 ;
   RECT 32.6280 155.2560 32.6760 155.3040 ;
  END
 END wd[1074]
 PIN rd[1074]
  DIRECTION OUTPUT ;
  USE SIGNAL ;
  PORT
   LAYER M5 ;
   RECT 32.8680 155.2560 32.9160 155.3040 ;
  END
 END rd[1074]
 PIN wd[1075]
  DIRECTION INPUT ;
  USE SIGNAL ;
  PORT
   LAYER M5 ;
   RECT 33.1080 155.2560 33.1560 155.3040 ;
  END
 END wd[1075]
 PIN rd[1075]
  DIRECTION OUTPUT ;
  USE SIGNAL ;
  PORT
   LAYER M5 ;
   RECT 33.3480 155.2560 33.3960 155.3040 ;
  END
 END rd[1075]
 PIN wd[1076]
  DIRECTION INPUT ;
  USE SIGNAL ;
  PORT
   LAYER M5 ;
   RECT 33.5880 155.2560 33.6360 155.3040 ;
  END
 END wd[1076]
 PIN rd[1076]
  DIRECTION OUTPUT ;
  USE SIGNAL ;
  PORT
   LAYER M5 ;
   RECT 33.8280 155.2560 33.8760 155.3040 ;
  END
 END rd[1076]
 PIN wd[1077]
  DIRECTION INPUT ;
  USE SIGNAL ;
  PORT
   LAYER M5 ;
   RECT 34.0680 155.2560 34.1160 155.3040 ;
  END
 END wd[1077]
 PIN rd[1077]
  DIRECTION OUTPUT ;
  USE SIGNAL ;
  PORT
   LAYER M5 ;
   RECT 34.3080 155.2560 34.3560 155.3040 ;
  END
 END rd[1077]
 PIN wd[1078]
  DIRECTION INPUT ;
  USE SIGNAL ;
  PORT
   LAYER M5 ;
   RECT 34.5480 155.2560 34.5960 155.3040 ;
  END
 END wd[1078]
 PIN rd[1078]
  DIRECTION OUTPUT ;
  USE SIGNAL ;
  PORT
   LAYER M5 ;
   RECT 34.7880 155.2560 34.8360 155.3040 ;
  END
 END rd[1078]
 PIN wd[1079]
  DIRECTION INPUT ;
  USE SIGNAL ;
  PORT
   LAYER M5 ;
   RECT 35.0280 155.2560 35.0760 155.3040 ;
  END
 END wd[1079]
 PIN rd[1079]
  DIRECTION OUTPUT ;
  USE SIGNAL ;
  PORT
   LAYER M5 ;
   RECT 35.2680 155.2560 35.3160 155.3040 ;
  END
 END rd[1079]
 PIN wd[1080]
  DIRECTION INPUT ;
  USE SIGNAL ;
  PORT
   LAYER M5 ;
   RECT 35.5080 155.2560 35.5560 155.3040 ;
  END
 END wd[1080]
 PIN rd[1080]
  DIRECTION OUTPUT ;
  USE SIGNAL ;
  PORT
   LAYER M5 ;
   RECT 35.7480 155.2560 35.7960 155.3040 ;
  END
 END rd[1080]
 PIN wd[1081]
  DIRECTION INPUT ;
  USE SIGNAL ;
  PORT
   LAYER M5 ;
   RECT 35.9880 155.2560 36.0360 155.3040 ;
  END
 END wd[1081]
 PIN rd[1081]
  DIRECTION OUTPUT ;
  USE SIGNAL ;
  PORT
   LAYER M5 ;
   RECT 36.2280 155.2560 36.2760 155.3040 ;
  END
 END rd[1081]
 PIN wd[1082]
  DIRECTION INPUT ;
  USE SIGNAL ;
  PORT
   LAYER M5 ;
   RECT 36.4680 155.2560 36.5160 155.3040 ;
  END
 END wd[1082]
 PIN rd[1082]
  DIRECTION OUTPUT ;
  USE SIGNAL ;
  PORT
   LAYER M5 ;
   RECT 36.7080 155.2560 36.7560 155.3040 ;
  END
 END rd[1082]
 PIN wd[1083]
  DIRECTION INPUT ;
  USE SIGNAL ;
  PORT
   LAYER M5 ;
   RECT 36.9480 155.2560 36.9960 155.3040 ;
  END
 END wd[1083]
 PIN rd[1083]
  DIRECTION OUTPUT ;
  USE SIGNAL ;
  PORT
   LAYER M5 ;
   RECT 37.1880 155.2560 37.2360 155.3040 ;
  END
 END rd[1083]
 PIN wd[1084]
  DIRECTION INPUT ;
  USE SIGNAL ;
  PORT
   LAYER M5 ;
   RECT 37.4280 155.2560 37.4760 155.3040 ;
  END
 END wd[1084]
 PIN rd[1084]
  DIRECTION OUTPUT ;
  USE SIGNAL ;
  PORT
   LAYER M5 ;
   RECT 37.6680 155.2560 37.7160 155.3040 ;
  END
 END rd[1084]
 PIN wd[1085]
  DIRECTION INPUT ;
  USE SIGNAL ;
  PORT
   LAYER M5 ;
   RECT 37.9080 155.2560 37.9560 155.3040 ;
  END
 END wd[1085]
 PIN rd[1085]
  DIRECTION OUTPUT ;
  USE SIGNAL ;
  PORT
   LAYER M5 ;
   RECT 38.1480 155.2560 38.1960 155.3040 ;
  END
 END rd[1085]
 PIN wd[1086]
  DIRECTION INPUT ;
  USE SIGNAL ;
  PORT
   LAYER M5 ;
   RECT 38.3880 155.2560 38.4360 155.3040 ;
  END
 END wd[1086]
 PIN rd[1086]
  DIRECTION OUTPUT ;
  USE SIGNAL ;
  PORT
   LAYER M5 ;
   RECT 38.6280 155.2560 38.6760 155.3040 ;
  END
 END rd[1086]
 PIN wd[1087]
  DIRECTION INPUT ;
  USE SIGNAL ;
  PORT
   LAYER M5 ;
   RECT 38.8680 155.2560 38.9160 155.3040 ;
  END
 END wd[1087]
 PIN rd[1087]
  DIRECTION OUTPUT ;
  USE SIGNAL ;
  PORT
   LAYER M5 ;
   RECT 39.1080 155.2560 39.1560 155.3040 ;
  END
 END rd[1087]
 PIN wd[1088]
  DIRECTION INPUT ;
  USE SIGNAL ;
  PORT
   LAYER M5 ;
   RECT 39.3480 155.2560 39.3960 155.3040 ;
  END
 END wd[1088]
 PIN rd[1088]
  DIRECTION OUTPUT ;
  USE SIGNAL ;
  PORT
   LAYER M5 ;
   RECT 39.5880 155.2560 39.6360 155.3040 ;
  END
 END rd[1088]
 PIN wd[1089]
  DIRECTION INPUT ;
  USE SIGNAL ;
  PORT
   LAYER M5 ;
   RECT 39.8280 155.2560 39.8760 155.3040 ;
  END
 END wd[1089]
 PIN rd[1089]
  DIRECTION OUTPUT ;
  USE SIGNAL ;
  PORT
   LAYER M5 ;
   RECT 40.0680 155.2560 40.1160 155.3040 ;
  END
 END rd[1089]
 PIN wd[1090]
  DIRECTION INPUT ;
  USE SIGNAL ;
  PORT
   LAYER M5 ;
   RECT 40.3080 155.2560 40.3560 155.3040 ;
  END
 END wd[1090]
 PIN rd[1090]
  DIRECTION OUTPUT ;
  USE SIGNAL ;
  PORT
   LAYER M5 ;
   RECT 40.5480 155.2560 40.5960 155.3040 ;
  END
 END rd[1090]
 PIN wd[1091]
  DIRECTION INPUT ;
  USE SIGNAL ;
  PORT
   LAYER M5 ;
   RECT 40.7880 155.2560 40.8360 155.3040 ;
  END
 END wd[1091]
 PIN rd[1091]
  DIRECTION OUTPUT ;
  USE SIGNAL ;
  PORT
   LAYER M5 ;
   RECT 41.0280 155.2560 41.0760 155.3040 ;
  END
 END rd[1091]
 PIN wd[1092]
  DIRECTION INPUT ;
  USE SIGNAL ;
  PORT
   LAYER M5 ;
   RECT 41.2680 155.2560 41.3160 155.3040 ;
  END
 END wd[1092]
 PIN rd[1092]
  DIRECTION OUTPUT ;
  USE SIGNAL ;
  PORT
   LAYER M5 ;
   RECT 41.5080 155.2560 41.5560 155.3040 ;
  END
 END rd[1092]
 PIN wd[1093]
  DIRECTION INPUT ;
  USE SIGNAL ;
  PORT
   LAYER M5 ;
   RECT 41.7480 155.2560 41.7960 155.3040 ;
  END
 END wd[1093]
 PIN rd[1093]
  DIRECTION OUTPUT ;
  USE SIGNAL ;
  PORT
   LAYER M5 ;
   RECT 41.9880 155.2560 42.0360 155.3040 ;
  END
 END rd[1093]
 PIN wd[1094]
  DIRECTION INPUT ;
  USE SIGNAL ;
  PORT
   LAYER M5 ;
   RECT 42.2280 155.2560 42.2760 155.3040 ;
  END
 END wd[1094]
 PIN rd[1094]
  DIRECTION OUTPUT ;
  USE SIGNAL ;
  PORT
   LAYER M5 ;
   RECT 42.4680 155.2560 42.5160 155.3040 ;
  END
 END rd[1094]
 PIN wd[1095]
  DIRECTION INPUT ;
  USE SIGNAL ;
  PORT
   LAYER M5 ;
   RECT 42.7080 155.2560 42.7560 155.3040 ;
  END
 END wd[1095]
 PIN rd[1095]
  DIRECTION OUTPUT ;
  USE SIGNAL ;
  PORT
   LAYER M5 ;
   RECT 42.9480 155.2560 42.9960 155.3040 ;
  END
 END rd[1095]
 PIN wd[1096]
  DIRECTION INPUT ;
  USE SIGNAL ;
  PORT
   LAYER M5 ;
   RECT 43.1880 155.2560 43.2360 155.3040 ;
  END
 END wd[1096]
 PIN rd[1096]
  DIRECTION OUTPUT ;
  USE SIGNAL ;
  PORT
   LAYER M5 ;
   RECT 43.4280 155.2560 43.4760 155.3040 ;
  END
 END rd[1096]
 PIN wd[1097]
  DIRECTION INPUT ;
  USE SIGNAL ;
  PORT
   LAYER M5 ;
   RECT 43.6680 155.2560 43.7160 155.3040 ;
  END
 END wd[1097]
 PIN rd[1097]
  DIRECTION OUTPUT ;
  USE SIGNAL ;
  PORT
   LAYER M5 ;
   RECT 43.9080 155.2560 43.9560 155.3040 ;
  END
 END rd[1097]
 PIN wd[1098]
  DIRECTION INPUT ;
  USE SIGNAL ;
  PORT
   LAYER M5 ;
   RECT 44.1480 155.2560 44.1960 155.3040 ;
  END
 END wd[1098]
 PIN rd[1098]
  DIRECTION OUTPUT ;
  USE SIGNAL ;
  PORT
   LAYER M5 ;
   RECT 44.3880 155.2560 44.4360 155.3040 ;
  END
 END rd[1098]
 PIN wd[1099]
  DIRECTION INPUT ;
  USE SIGNAL ;
  PORT
   LAYER M5 ;
   RECT 44.6280 155.2560 44.6760 155.3040 ;
  END
 END wd[1099]
 PIN rd[1099]
  DIRECTION OUTPUT ;
  USE SIGNAL ;
  PORT
   LAYER M5 ;
   RECT 44.8680 155.2560 44.9160 155.3040 ;
  END
 END rd[1099]
 PIN wd[1100]
  DIRECTION INPUT ;
  USE SIGNAL ;
  PORT
   LAYER M5 ;
   RECT 45.1080 155.2560 45.1560 155.3040 ;
  END
 END wd[1100]
 PIN rd[1100]
  DIRECTION OUTPUT ;
  USE SIGNAL ;
  PORT
   LAYER M5 ;
   RECT 45.3480 155.2560 45.3960 155.3040 ;
  END
 END rd[1100]
 PIN wd[1101]
  DIRECTION INPUT ;
  USE SIGNAL ;
  PORT
   LAYER M5 ;
   RECT 45.5880 155.2560 45.6360 155.3040 ;
  END
 END wd[1101]
 PIN rd[1101]
  DIRECTION OUTPUT ;
  USE SIGNAL ;
  PORT
   LAYER M5 ;
   RECT 45.8280 155.2560 45.8760 155.3040 ;
  END
 END rd[1101]
 PIN wd[1102]
  DIRECTION INPUT ;
  USE SIGNAL ;
  PORT
   LAYER M5 ;
   RECT 46.0680 155.2560 46.1160 155.3040 ;
  END
 END wd[1102]
 PIN rd[1102]
  DIRECTION OUTPUT ;
  USE SIGNAL ;
  PORT
   LAYER M5 ;
   RECT 46.3080 155.2560 46.3560 155.3040 ;
  END
 END rd[1102]
 PIN wd[1103]
  DIRECTION INPUT ;
  USE SIGNAL ;
  PORT
   LAYER M5 ;
   RECT 46.5480 155.2560 46.5960 155.3040 ;
  END
 END wd[1103]
 PIN rd[1103]
  DIRECTION OUTPUT ;
  USE SIGNAL ;
  PORT
   LAYER M5 ;
   RECT 46.7880 155.2560 46.8360 155.3040 ;
  END
 END rd[1103]
 PIN rc[0]
  DIRECTION INPUT ;
  USE SIGNAL ;
  PORT
   LAYER M5 ;
   RECT 167.9880 155.2560 168.0360 155.3040 ;
  END
 END rc[0]
 PIN rc[1]
  DIRECTION INPUT ;
  USE SIGNAL ;
  PORT
   LAYER M5 ;
   RECT 168.2280 155.2560 168.2760 155.3040 ;
  END
 END rc[1]
 PIN rc[2]
  DIRECTION INPUT ;
  USE SIGNAL ;
  PORT
   LAYER M5 ;
   RECT 168.4680 155.2560 168.5160 155.3040 ;
  END
 END rc[2]
 PIN rc[3]
  DIRECTION INPUT ;
  USE SIGNAL ;
  PORT
   LAYER M5 ;
   RECT 168.7080 155.2560 168.7560 155.3040 ;
  END
 END rc[3]
 PIN rc[4]
  DIRECTION INPUT ;
  USE SIGNAL ;
  PORT
   LAYER M5 ;
   RECT 168.9480 155.2560 168.9960 155.3040 ;
  END
 END rc[4]
 PIN rc[5]
  DIRECTION INPUT ;
  USE SIGNAL ;
  PORT
   LAYER M5 ;
   RECT 169.1880 155.2560 169.2360 155.3040 ;
  END
 END rc[5]
 PIN rc[6]
  DIRECTION INPUT ;
  USE SIGNAL ;
  PORT
   LAYER M5 ;
   RECT 169.4280 155.2560 169.4760 155.3040 ;
  END
 END rc[6]
 PIN rc[7]
  DIRECTION INPUT ;
  USE SIGNAL ;
  PORT
   LAYER M5 ;
   RECT 169.6680 155.2560 169.7160 155.3040 ;
  END
 END rc[7]
 PIN rc[8]
  DIRECTION INPUT ;
  USE SIGNAL ;
  PORT
   LAYER M5 ;
   RECT 169.9080 155.2560 169.9560 155.3040 ;
  END
 END rc[8]
 PIN rc[9]
  DIRECTION INPUT ;
  USE SIGNAL ;
  PORT
   LAYER M5 ;
   RECT 170.1480 155.2560 170.1960 155.3040 ;
  END
 END rc[9]
 PIN rc[10]
  DIRECTION INPUT ;
  USE SIGNAL ;
  PORT
   LAYER M5 ;
   RECT 170.3880 155.2560 170.4360 155.3040 ;
  END
 END rc[10]
 PIN rst_n
  DIRECTION INPUT ;
  USE SIGNAL ;
  PORT
   LAYER M5 ;
   RECT 172.7880 155.2560 172.8360 155.3040 ;
  END
 END rst_n
 PIN wv
  DIRECTION INPUT ;
  USE SIGNAL ;
  PORT
   LAYER M5 ;
   RECT 173.0280 155.2560 173.0760 155.3040 ;
  END
 END wv
 PIN rv
  DIRECTION OUTPUT ;
  USE SIGNAL ;
  PORT
   LAYER M5 ;
   RECT 173.2680 155.2560 173.3160 155.3040 ;
  END
 END rv
 PIN fault
  DIRECTION OUTPUT ;
  USE SIGNAL ;
  PORT
   LAYER M5 ;
   RECT 173.5080 155.2560 173.5560 155.3040 ;
  END
 END fault
 PIN clk
  DIRECTION INPUT ;
  USE CLOCK ;
  PORT
   LAYER M5 ;
   RECT 120.9480 77.5200 120.9960 78.0000 ;
  END
 END clk
END dsdv_mu_land
END LIBRARY
